VERSION 5.8 ;
BUSBITCHARS "[]" ;
DIVIDERCHAR "/" ;
UNITS
    DATABASE MICRONS 1000 ;
END UNITS

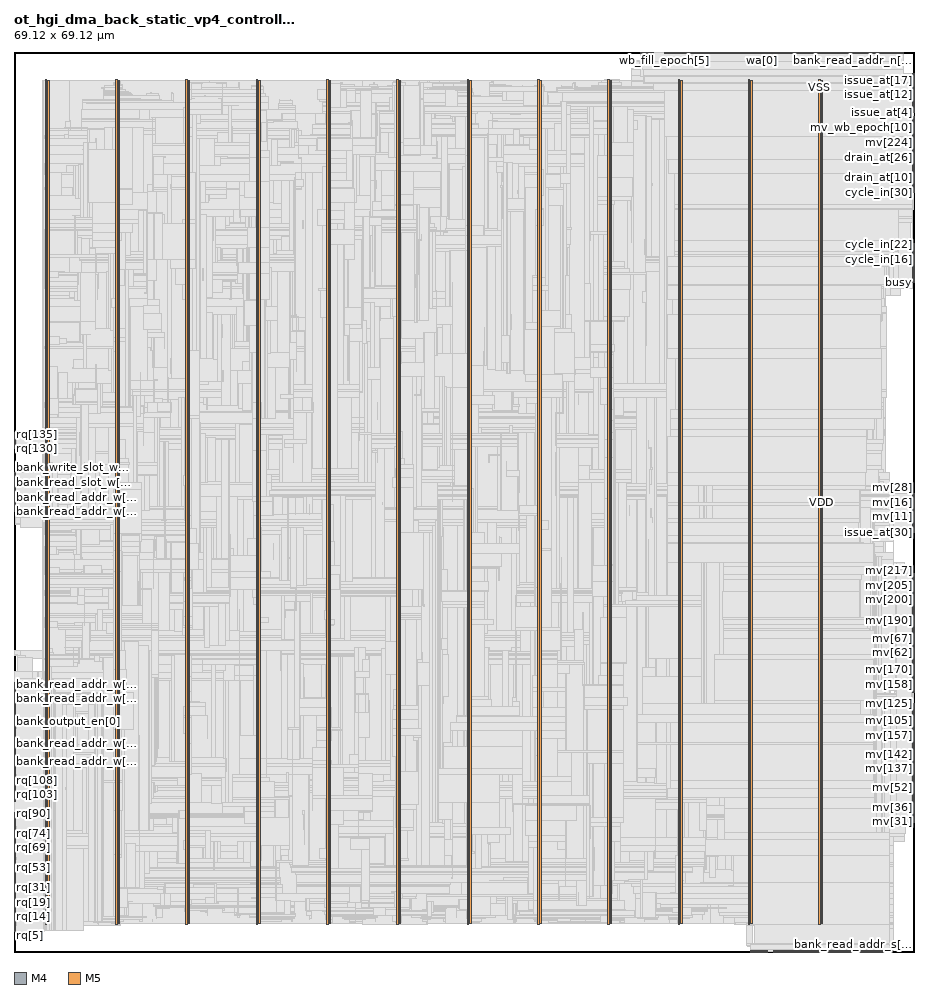
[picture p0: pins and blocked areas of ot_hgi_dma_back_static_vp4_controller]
MACRO ot_hgi_dma_back_static_vp4_controller
  FOREIGN ot_hgi_dma_back_static_vp4_controller 0 0 ;
  CLASS BLOCK ;
  SIZE 69.12 BY 69.12 ;
  PIN bank_output_en[0]
    DIRECTION OUTPUT ;
    USE SIGNAL ;
    PORT
      LAYER M4 ;
        RECT  0 17.712 0.084 17.736 ;
    END
  END bank_output_en[0]
  PIN bank_output_en[1]
    DIRECTION OUTPUT ;
    USE SIGNAL ;
    PORT
      LAYER M4 ;
        RECT  0 17.808 0.084 17.832 ;
    END
  END bank_output_en[1]
  PIN bank_output_en[2]
    DIRECTION OUTPUT ;
    USE SIGNAL ;
    PORT
      LAYER M4 ;
        RECT  0 17.904 0.084 17.928 ;
    END
  END bank_output_en[2]
  PIN bank_output_en[3]
    DIRECTION OUTPUT ;
    USE SIGNAL ;
    PORT
      LAYER M4 ;
        RECT  0 18 0.084 18.024 ;
    END
  END bank_output_en[3]
  PIN bank_output_en[4]
    DIRECTION OUTPUT ;
    USE SIGNAL ;
    PORT
      LAYER M4 ;
        RECT  0 18.096 0.084 18.12 ;
    END
  END bank_output_en[4]
  PIN bank_output_en[5]
    DIRECTION OUTPUT ;
    USE SIGNAL ;
    PORT
      LAYER M4 ;
        RECT  0 18.192 0.084 18.216 ;
    END
  END bank_output_en[5]
  PIN bank_output_en[6]
    DIRECTION OUTPUT ;
    USE SIGNAL ;
    PORT
      LAYER M4 ;
        RECT  0 18.288 0.084 18.312 ;
    END
  END bank_output_en[6]
  PIN bank_output_en[7]
    DIRECTION OUTPUT ;
    USE SIGNAL ;
    PORT
      LAYER M4 ;
        RECT  0 18.384 0.084 18.408 ;
    END
  END bank_output_en[7]
  PIN bank_read_addr_n[0]
    DIRECTION OUTPUT ;
    USE SIGNAL ;
    PORT
      LAYER M5 ;
        RECT  62.256 69.036 62.28 69.12 ;
    END
  END bank_read_addr_n[0]
  PIN bank_read_addr_n[10]
    DIRECTION OUTPUT ;
    USE SIGNAL ;
    PORT
      LAYER M5 ;
        RECT  63.216 69.036 63.24 69.12 ;
    END
  END bank_read_addr_n[10]
  PIN bank_read_addr_n[11]
    DIRECTION OUTPUT ;
    USE SIGNAL ;
    PORT
      LAYER M5 ;
        RECT  63.312 69.036 63.336 69.12 ;
    END
  END bank_read_addr_n[11]
  PIN bank_read_addr_n[12]
    DIRECTION OUTPUT ;
    USE SIGNAL ;
    PORT
      LAYER M5 ;
        RECT  63.408 69.036 63.432 69.12 ;
    END
  END bank_read_addr_n[12]
  PIN bank_read_addr_n[13]
    DIRECTION OUTPUT ;
    USE SIGNAL ;
    PORT
      LAYER M5 ;
        RECT  63.504 69.036 63.528 69.12 ;
    END
  END bank_read_addr_n[13]
  PIN bank_read_addr_n[14]
    DIRECTION OUTPUT ;
    USE SIGNAL ;
    PORT
      LAYER M5 ;
        RECT  63.6 69.036 63.624 69.12 ;
    END
  END bank_read_addr_n[14]
  PIN bank_read_addr_n[15]
    DIRECTION OUTPUT ;
    USE SIGNAL ;
    PORT
      LAYER M5 ;
        RECT  63.696 69.036 63.72 69.12 ;
    END
  END bank_read_addr_n[15]
  PIN bank_read_addr_n[16]
    DIRECTION OUTPUT ;
    USE SIGNAL ;
    PORT
      LAYER M5 ;
        RECT  63.792 69.036 63.816 69.12 ;
    END
  END bank_read_addr_n[16]
  PIN bank_read_addr_n[17]
    DIRECTION OUTPUT ;
    USE SIGNAL ;
    PORT
      LAYER M5 ;
        RECT  63.888 69.036 63.912 69.12 ;
    END
  END bank_read_addr_n[17]
  PIN bank_read_addr_n[18]
    DIRECTION OUTPUT ;
    USE SIGNAL ;
    PORT
      LAYER M5 ;
        RECT  63.984 69.036 64.008 69.12 ;
    END
  END bank_read_addr_n[18]
  PIN bank_read_addr_n[19]
    DIRECTION OUTPUT ;
    USE SIGNAL ;
    PORT
      LAYER M5 ;
        RECT  64.08 69.036 64.104 69.12 ;
    END
  END bank_read_addr_n[19]
  PIN bank_read_addr_n[1]
    DIRECTION OUTPUT ;
    USE SIGNAL ;
    PORT
      LAYER M5 ;
        RECT  62.352 69.036 62.376 69.12 ;
    END
  END bank_read_addr_n[1]
  PIN bank_read_addr_n[20]
    DIRECTION OUTPUT ;
    USE SIGNAL ;
    PORT
      LAYER M5 ;
        RECT  64.176 69.036 64.2 69.12 ;
    END
  END bank_read_addr_n[20]
  PIN bank_read_addr_n[21]
    DIRECTION OUTPUT ;
    USE SIGNAL ;
    PORT
      LAYER M5 ;
        RECT  64.272 69.036 64.296 69.12 ;
    END
  END bank_read_addr_n[21]
  PIN bank_read_addr_n[22]
    DIRECTION OUTPUT ;
    USE SIGNAL ;
    PORT
      LAYER M5 ;
        RECT  64.368 69.036 64.392 69.12 ;
    END
  END bank_read_addr_n[22]
  PIN bank_read_addr_n[23]
    DIRECTION OUTPUT ;
    USE SIGNAL ;
    PORT
      LAYER M5 ;
        RECT  64.464 69.036 64.488 69.12 ;
    END
  END bank_read_addr_n[23]
  PIN bank_read_addr_n[24]
    DIRECTION OUTPUT ;
    USE SIGNAL ;
    PORT
      LAYER M5 ;
        RECT  64.56 69.036 64.584 69.12 ;
    END
  END bank_read_addr_n[24]
  PIN bank_read_addr_n[25]
    DIRECTION OUTPUT ;
    USE SIGNAL ;
    PORT
      LAYER M5 ;
        RECT  64.656 69.036 64.68 69.12 ;
    END
  END bank_read_addr_n[25]
  PIN bank_read_addr_n[26]
    DIRECTION OUTPUT ;
    USE SIGNAL ;
    PORT
      LAYER M5 ;
        RECT  64.752 69.036 64.776 69.12 ;
    END
  END bank_read_addr_n[26]
  PIN bank_read_addr_n[27]
    DIRECTION OUTPUT ;
    USE SIGNAL ;
    PORT
      LAYER M5 ;
        RECT  64.848 69.036 64.872 69.12 ;
    END
  END bank_read_addr_n[27]
  PIN bank_read_addr_n[28]
    DIRECTION OUTPUT ;
    USE SIGNAL ;
    PORT
      LAYER M5 ;
        RECT  64.944 69.036 64.968 69.12 ;
    END
  END bank_read_addr_n[28]
  PIN bank_read_addr_n[29]
    DIRECTION OUTPUT ;
    USE SIGNAL ;
    PORT
      LAYER M5 ;
        RECT  65.04 69.036 65.064 69.12 ;
    END
  END bank_read_addr_n[29]
  PIN bank_read_addr_n[2]
    DIRECTION OUTPUT ;
    USE SIGNAL ;
    PORT
      LAYER M5 ;
        RECT  62.448 69.036 62.472 69.12 ;
    END
  END bank_read_addr_n[2]
  PIN bank_read_addr_n[30]
    DIRECTION OUTPUT ;
    USE SIGNAL ;
    PORT
      LAYER M5 ;
        RECT  65.136 69.036 65.16 69.12 ;
    END
  END bank_read_addr_n[30]
  PIN bank_read_addr_n[31]
    DIRECTION OUTPUT ;
    USE SIGNAL ;
    PORT
      LAYER M5 ;
        RECT  65.232 69.036 65.256 69.12 ;
    END
  END bank_read_addr_n[31]
  PIN bank_read_addr_n[32]
    DIRECTION OUTPUT ;
    USE SIGNAL ;
    PORT
      LAYER M5 ;
        RECT  65.328 69.036 65.352 69.12 ;
    END
  END bank_read_addr_n[32]
  PIN bank_read_addr_n[33]
    DIRECTION OUTPUT ;
    USE SIGNAL ;
    PORT
      LAYER M5 ;
        RECT  65.424 69.036 65.448 69.12 ;
    END
  END bank_read_addr_n[33]
  PIN bank_read_addr_n[34]
    DIRECTION OUTPUT ;
    USE SIGNAL ;
    PORT
      LAYER M5 ;
        RECT  65.52 69.036 65.544 69.12 ;
    END
  END bank_read_addr_n[34]
  PIN bank_read_addr_n[35]
    DIRECTION OUTPUT ;
    USE SIGNAL ;
    PORT
      LAYER M5 ;
        RECT  65.616 69.036 65.64 69.12 ;
    END
  END bank_read_addr_n[35]
  PIN bank_read_addr_n[36]
    DIRECTION OUTPUT ;
    USE SIGNAL ;
    PORT
      LAYER M5 ;
        RECT  65.712 69.036 65.736 69.12 ;
    END
  END bank_read_addr_n[36]
  PIN bank_read_addr_n[37]
    DIRECTION OUTPUT ;
    USE SIGNAL ;
    PORT
      LAYER M5 ;
        RECT  65.808 69.036 65.832 69.12 ;
    END
  END bank_read_addr_n[37]
  PIN bank_read_addr_n[38]
    DIRECTION OUTPUT ;
    USE SIGNAL ;
    PORT
      LAYER M5 ;
        RECT  65.904 69.036 65.928 69.12 ;
    END
  END bank_read_addr_n[38]
  PIN bank_read_addr_n[39]
    DIRECTION OUTPUT ;
    USE SIGNAL ;
    PORT
      LAYER M5 ;
        RECT  66 69.036 66.024 69.12 ;
    END
  END bank_read_addr_n[39]
  PIN bank_read_addr_n[3]
    DIRECTION OUTPUT ;
    USE SIGNAL ;
    PORT
      LAYER M5 ;
        RECT  62.544 69.036 62.568 69.12 ;
    END
  END bank_read_addr_n[3]
  PIN bank_read_addr_n[40]
    DIRECTION OUTPUT ;
    USE SIGNAL ;
    PORT
      LAYER M5 ;
        RECT  66.096 69.036 66.12 69.12 ;
    END
  END bank_read_addr_n[40]
  PIN bank_read_addr_n[41]
    DIRECTION OUTPUT ;
    USE SIGNAL ;
    PORT
      LAYER M5 ;
        RECT  66.192 69.036 66.216 69.12 ;
    END
  END bank_read_addr_n[41]
  PIN bank_read_addr_n[42]
    DIRECTION OUTPUT ;
    USE SIGNAL ;
    PORT
      LAYER M5 ;
        RECT  66.288 69.036 66.312 69.12 ;
    END
  END bank_read_addr_n[42]
  PIN bank_read_addr_n[43]
    DIRECTION OUTPUT ;
    USE SIGNAL ;
    PORT
      LAYER M5 ;
        RECT  66.384 69.036 66.408 69.12 ;
    END
  END bank_read_addr_n[43]
  PIN bank_read_addr_n[44]
    DIRECTION OUTPUT ;
    USE SIGNAL ;
    PORT
      LAYER M5 ;
        RECT  66.48 69.036 66.504 69.12 ;
    END
  END bank_read_addr_n[44]
  PIN bank_read_addr_n[45]
    DIRECTION OUTPUT ;
    USE SIGNAL ;
    PORT
      LAYER M5 ;
        RECT  66.576 69.036 66.6 69.12 ;
    END
  END bank_read_addr_n[45]
  PIN bank_read_addr_n[46]
    DIRECTION OUTPUT ;
    USE SIGNAL ;
    PORT
      LAYER M5 ;
        RECT  66.672 69.036 66.696 69.12 ;
    END
  END bank_read_addr_n[46]
  PIN bank_read_addr_n[47]
    DIRECTION OUTPUT ;
    USE SIGNAL ;
    PORT
      LAYER M5 ;
        RECT  66.768 69.036 66.792 69.12 ;
    END
  END bank_read_addr_n[47]
  PIN bank_read_addr_n[48]
    DIRECTION OUTPUT ;
    USE SIGNAL ;
    PORT
      LAYER M5 ;
        RECT  66.864 69.036 66.888 69.12 ;
    END
  END bank_read_addr_n[48]
  PIN bank_read_addr_n[49]
    DIRECTION OUTPUT ;
    USE SIGNAL ;
    PORT
      LAYER M5 ;
        RECT  66.96 69.036 66.984 69.12 ;
    END
  END bank_read_addr_n[49]
  PIN bank_read_addr_n[4]
    DIRECTION OUTPUT ;
    USE SIGNAL ;
    PORT
      LAYER M5 ;
        RECT  62.64 69.036 62.664 69.12 ;
    END
  END bank_read_addr_n[4]
  PIN bank_read_addr_n[50]
    DIRECTION OUTPUT ;
    USE SIGNAL ;
    PORT
      LAYER M5 ;
        RECT  67.056 69.036 67.08 69.12 ;
    END
  END bank_read_addr_n[50]
  PIN bank_read_addr_n[51]
    DIRECTION OUTPUT ;
    USE SIGNAL ;
    PORT
      LAYER M5 ;
        RECT  67.152 69.036 67.176 69.12 ;
    END
  END bank_read_addr_n[51]
  PIN bank_read_addr_n[52]
    DIRECTION OUTPUT ;
    USE SIGNAL ;
    PORT
      LAYER M5 ;
        RECT  67.248 69.036 67.272 69.12 ;
    END
  END bank_read_addr_n[52]
  PIN bank_read_addr_n[53]
    DIRECTION OUTPUT ;
    USE SIGNAL ;
    PORT
      LAYER M5 ;
        RECT  67.344 69.036 67.368 69.12 ;
    END
  END bank_read_addr_n[53]
  PIN bank_read_addr_n[54]
    DIRECTION OUTPUT ;
    USE SIGNAL ;
    PORT
      LAYER M5 ;
        RECT  67.44 69.036 67.464 69.12 ;
    END
  END bank_read_addr_n[54]
  PIN bank_read_addr_n[55]
    DIRECTION OUTPUT ;
    USE SIGNAL ;
    PORT
      LAYER M5 ;
        RECT  67.536 69.036 67.56 69.12 ;
    END
  END bank_read_addr_n[55]
  PIN bank_read_addr_n[56]
    DIRECTION OUTPUT ;
    USE SIGNAL ;
    PORT
      LAYER M5 ;
        RECT  67.632 69.036 67.656 69.12 ;
    END
  END bank_read_addr_n[56]
  PIN bank_read_addr_n[57]
    DIRECTION OUTPUT ;
    USE SIGNAL ;
    PORT
      LAYER M5 ;
        RECT  67.728 69.036 67.752 69.12 ;
    END
  END bank_read_addr_n[57]
  PIN bank_read_addr_n[58]
    DIRECTION OUTPUT ;
    USE SIGNAL ;
    PORT
      LAYER M5 ;
        RECT  67.824 69.036 67.848 69.12 ;
    END
  END bank_read_addr_n[58]
  PIN bank_read_addr_n[59]
    DIRECTION OUTPUT ;
    USE SIGNAL ;
    PORT
      LAYER M5 ;
        RECT  67.92 69.036 67.944 69.12 ;
    END
  END bank_read_addr_n[59]
  PIN bank_read_addr_n[5]
    DIRECTION OUTPUT ;
    USE SIGNAL ;
    PORT
      LAYER M5 ;
        RECT  62.736 69.036 62.76 69.12 ;
    END
  END bank_read_addr_n[5]
  PIN bank_read_addr_n[60]
    DIRECTION OUTPUT ;
    USE SIGNAL ;
    PORT
      LAYER M5 ;
        RECT  68.016 69.036 68.04 69.12 ;
    END
  END bank_read_addr_n[60]
  PIN bank_read_addr_n[61]
    DIRECTION OUTPUT ;
    USE SIGNAL ;
    PORT
      LAYER M5 ;
        RECT  68.112 69.036 68.136 69.12 ;
    END
  END bank_read_addr_n[61]
  PIN bank_read_addr_n[62]
    DIRECTION OUTPUT ;
    USE SIGNAL ;
    PORT
      LAYER M5 ;
        RECT  68.208 69.036 68.232 69.12 ;
    END
  END bank_read_addr_n[62]
  PIN bank_read_addr_n[63]
    DIRECTION OUTPUT ;
    USE SIGNAL ;
    PORT
      LAYER M5 ;
        RECT  68.304 69.036 68.328 69.12 ;
    END
  END bank_read_addr_n[63]
  PIN bank_read_addr_n[64]
    DIRECTION OUTPUT ;
    USE SIGNAL ;
    PORT
      LAYER M5 ;
        RECT  59.184 69.036 59.208 69.12 ;
    END
  END bank_read_addr_n[64]
  PIN bank_read_addr_n[65]
    DIRECTION OUTPUT ;
    USE SIGNAL ;
    PORT
      LAYER M5 ;
        RECT  59.28 69.036 59.304 69.12 ;
    END
  END bank_read_addr_n[65]
  PIN bank_read_addr_n[66]
    DIRECTION OUTPUT ;
    USE SIGNAL ;
    PORT
      LAYER M5 ;
        RECT  59.376 69.036 59.4 69.12 ;
    END
  END bank_read_addr_n[66]
  PIN bank_read_addr_n[67]
    DIRECTION OUTPUT ;
    USE SIGNAL ;
    PORT
      LAYER M5 ;
        RECT  59.472 69.036 59.496 69.12 ;
    END
  END bank_read_addr_n[67]
  PIN bank_read_addr_n[68]
    DIRECTION OUTPUT ;
    USE SIGNAL ;
    PORT
      LAYER M5 ;
        RECT  59.568 69.036 59.592 69.12 ;
    END
  END bank_read_addr_n[68]
  PIN bank_read_addr_n[69]
    DIRECTION OUTPUT ;
    USE SIGNAL ;
    PORT
      LAYER M5 ;
        RECT  59.664 69.036 59.688 69.12 ;
    END
  END bank_read_addr_n[69]
  PIN bank_read_addr_n[6]
    DIRECTION OUTPUT ;
    USE SIGNAL ;
    PORT
      LAYER M5 ;
        RECT  62.832 69.036 62.856 69.12 ;
    END
  END bank_read_addr_n[6]
  PIN bank_read_addr_n[70]
    DIRECTION OUTPUT ;
    USE SIGNAL ;
    PORT
      LAYER M5 ;
        RECT  59.76 69.036 59.784 69.12 ;
    END
  END bank_read_addr_n[70]
  PIN bank_read_addr_n[71]
    DIRECTION OUTPUT ;
    USE SIGNAL ;
    PORT
      LAYER M5 ;
        RECT  59.856 69.036 59.88 69.12 ;
    END
  END bank_read_addr_n[71]
  PIN bank_read_addr_n[72]
    DIRECTION OUTPUT ;
    USE SIGNAL ;
    PORT
      LAYER M5 ;
        RECT  59.952 69.036 59.976 69.12 ;
    END
  END bank_read_addr_n[72]
  PIN bank_read_addr_n[73]
    DIRECTION OUTPUT ;
    USE SIGNAL ;
    PORT
      LAYER M5 ;
        RECT  60.048 69.036 60.072 69.12 ;
    END
  END bank_read_addr_n[73]
  PIN bank_read_addr_n[74]
    DIRECTION OUTPUT ;
    USE SIGNAL ;
    PORT
      LAYER M5 ;
        RECT  60.144 69.036 60.168 69.12 ;
    END
  END bank_read_addr_n[74]
  PIN bank_read_addr_n[75]
    DIRECTION OUTPUT ;
    USE SIGNAL ;
    PORT
      LAYER M5 ;
        RECT  60.24 69.036 60.264 69.12 ;
    END
  END bank_read_addr_n[75]
  PIN bank_read_addr_n[76]
    DIRECTION OUTPUT ;
    USE SIGNAL ;
    PORT
      LAYER M5 ;
        RECT  60.336 69.036 60.36 69.12 ;
    END
  END bank_read_addr_n[76]
  PIN bank_read_addr_n[77]
    DIRECTION OUTPUT ;
    USE SIGNAL ;
    PORT
      LAYER M5 ;
        RECT  60.432 69.036 60.456 69.12 ;
    END
  END bank_read_addr_n[77]
  PIN bank_read_addr_n[78]
    DIRECTION OUTPUT ;
    USE SIGNAL ;
    PORT
      LAYER M5 ;
        RECT  60.528 69.036 60.552 69.12 ;
    END
  END bank_read_addr_n[78]
  PIN bank_read_addr_n[79]
    DIRECTION OUTPUT ;
    USE SIGNAL ;
    PORT
      LAYER M5 ;
        RECT  60.624 69.036 60.648 69.12 ;
    END
  END bank_read_addr_n[79]
  PIN bank_read_addr_n[7]
    DIRECTION OUTPUT ;
    USE SIGNAL ;
    PORT
      LAYER M5 ;
        RECT  62.928 69.036 62.952 69.12 ;
    END
  END bank_read_addr_n[7]
  PIN bank_read_addr_n[80]
    DIRECTION OUTPUT ;
    USE SIGNAL ;
    PORT
      LAYER M5 ;
        RECT  60.72 69.036 60.744 69.12 ;
    END
  END bank_read_addr_n[80]
  PIN bank_read_addr_n[81]
    DIRECTION OUTPUT ;
    USE SIGNAL ;
    PORT
      LAYER M5 ;
        RECT  60.816 69.036 60.84 69.12 ;
    END
  END bank_read_addr_n[81]
  PIN bank_read_addr_n[82]
    DIRECTION OUTPUT ;
    USE SIGNAL ;
    PORT
      LAYER M5 ;
        RECT  60.912 69.036 60.936 69.12 ;
    END
  END bank_read_addr_n[82]
  PIN bank_read_addr_n[83]
    DIRECTION OUTPUT ;
    USE SIGNAL ;
    PORT
      LAYER M5 ;
        RECT  61.008 69.036 61.032 69.12 ;
    END
  END bank_read_addr_n[83]
  PIN bank_read_addr_n[84]
    DIRECTION OUTPUT ;
    USE SIGNAL ;
    PORT
      LAYER M5 ;
        RECT  61.104 69.036 61.128 69.12 ;
    END
  END bank_read_addr_n[84]
  PIN bank_read_addr_n[85]
    DIRECTION OUTPUT ;
    USE SIGNAL ;
    PORT
      LAYER M5 ;
        RECT  61.2 69.036 61.224 69.12 ;
    END
  END bank_read_addr_n[85]
  PIN bank_read_addr_n[86]
    DIRECTION OUTPUT ;
    USE SIGNAL ;
    PORT
      LAYER M5 ;
        RECT  61.296 69.036 61.32 69.12 ;
    END
  END bank_read_addr_n[86]
  PIN bank_read_addr_n[87]
    DIRECTION OUTPUT ;
    USE SIGNAL ;
    PORT
      LAYER M5 ;
        RECT  61.392 69.036 61.416 69.12 ;
    END
  END bank_read_addr_n[87]
  PIN bank_read_addr_n[88]
    DIRECTION OUTPUT ;
    USE SIGNAL ;
    PORT
      LAYER M5 ;
        RECT  61.488 69.036 61.512 69.12 ;
    END
  END bank_read_addr_n[88]
  PIN bank_read_addr_n[89]
    DIRECTION OUTPUT ;
    USE SIGNAL ;
    PORT
      LAYER M5 ;
        RECT  61.584 69.036 61.608 69.12 ;
    END
  END bank_read_addr_n[89]
  PIN bank_read_addr_n[8]
    DIRECTION OUTPUT ;
    USE SIGNAL ;
    PORT
      LAYER M5 ;
        RECT  63.024 69.036 63.048 69.12 ;
    END
  END bank_read_addr_n[8]
  PIN bank_read_addr_n[90]
    DIRECTION OUTPUT ;
    USE SIGNAL ;
    PORT
      LAYER M5 ;
        RECT  61.68 69.036 61.704 69.12 ;
    END
  END bank_read_addr_n[90]
  PIN bank_read_addr_n[91]
    DIRECTION OUTPUT ;
    USE SIGNAL ;
    PORT
      LAYER M5 ;
        RECT  61.776 69.036 61.8 69.12 ;
    END
  END bank_read_addr_n[91]
  PIN bank_read_addr_n[92]
    DIRECTION OUTPUT ;
    USE SIGNAL ;
    PORT
      LAYER M5 ;
        RECT  61.872 69.036 61.896 69.12 ;
    END
  END bank_read_addr_n[92]
  PIN bank_read_addr_n[93]
    DIRECTION OUTPUT ;
    USE SIGNAL ;
    PORT
      LAYER M5 ;
        RECT  61.968 69.036 61.992 69.12 ;
    END
  END bank_read_addr_n[93]
  PIN bank_read_addr_n[94]
    DIRECTION OUTPUT ;
    USE SIGNAL ;
    PORT
      LAYER M5 ;
        RECT  62.064 69.036 62.088 69.12 ;
    END
  END bank_read_addr_n[94]
  PIN bank_read_addr_n[95]
    DIRECTION OUTPUT ;
    USE SIGNAL ;
    PORT
      LAYER M5 ;
        RECT  62.16 69.036 62.184 69.12 ;
    END
  END bank_read_addr_n[95]
  PIN bank_read_addr_n[9]
    DIRECTION OUTPUT ;
    USE SIGNAL ;
    PORT
      LAYER M5 ;
        RECT  63.12 69.036 63.144 69.12 ;
    END
  END bank_read_addr_n[9]
  PIN bank_read_addr_s[0]
    DIRECTION OUTPUT ;
    USE SIGNAL ;
    PORT
      LAYER M5 ;
        RECT  58.32 0 58.344 0.084 ;
    END
  END bank_read_addr_s[0]
  PIN bank_read_addr_s[10]
    DIRECTION OUTPUT ;
    USE SIGNAL ;
    PORT
      LAYER M5 ;
        RECT  59.28 0 59.304 0.084 ;
    END
  END bank_read_addr_s[10]
  PIN bank_read_addr_s[11]
    DIRECTION OUTPUT ;
    USE SIGNAL ;
    PORT
      LAYER M5 ;
        RECT  59.376 0 59.4 0.084 ;
    END
  END bank_read_addr_s[11]
  PIN bank_read_addr_s[12]
    DIRECTION OUTPUT ;
    USE SIGNAL ;
    PORT
      LAYER M5 ;
        RECT  59.472 0 59.496 0.084 ;
    END
  END bank_read_addr_s[12]
  PIN bank_read_addr_s[13]
    DIRECTION OUTPUT ;
    USE SIGNAL ;
    PORT
      LAYER M5 ;
        RECT  59.568 0 59.592 0.084 ;
    END
  END bank_read_addr_s[13]
  PIN bank_read_addr_s[14]
    DIRECTION OUTPUT ;
    USE SIGNAL ;
    PORT
      LAYER M5 ;
        RECT  59.664 0 59.688 0.084 ;
    END
  END bank_read_addr_s[14]
  PIN bank_read_addr_s[15]
    DIRECTION OUTPUT ;
    USE SIGNAL ;
    PORT
      LAYER M5 ;
        RECT  59.76 0 59.784 0.084 ;
    END
  END bank_read_addr_s[15]
  PIN bank_read_addr_s[16]
    DIRECTION OUTPUT ;
    USE SIGNAL ;
    PORT
      LAYER M5 ;
        RECT  59.856 0 59.88 0.084 ;
    END
  END bank_read_addr_s[16]
  PIN bank_read_addr_s[17]
    DIRECTION OUTPUT ;
    USE SIGNAL ;
    PORT
      LAYER M5 ;
        RECT  59.952 0 59.976 0.084 ;
    END
  END bank_read_addr_s[17]
  PIN bank_read_addr_s[18]
    DIRECTION OUTPUT ;
    USE SIGNAL ;
    PORT
      LAYER M5 ;
        RECT  60.048 0 60.072 0.084 ;
    END
  END bank_read_addr_s[18]
  PIN bank_read_addr_s[19]
    DIRECTION OUTPUT ;
    USE SIGNAL ;
    PORT
      LAYER M5 ;
        RECT  60.144 0 60.168 0.084 ;
    END
  END bank_read_addr_s[19]
  PIN bank_read_addr_s[1]
    DIRECTION OUTPUT ;
    USE SIGNAL ;
    PORT
      LAYER M5 ;
        RECT  58.416 0 58.44 0.084 ;
    END
  END bank_read_addr_s[1]
  PIN bank_read_addr_s[20]
    DIRECTION OUTPUT ;
    USE SIGNAL ;
    PORT
      LAYER M5 ;
        RECT  60.24 0 60.264 0.084 ;
    END
  END bank_read_addr_s[20]
  PIN bank_read_addr_s[21]
    DIRECTION OUTPUT ;
    USE SIGNAL ;
    PORT
      LAYER M5 ;
        RECT  60.336 0 60.36 0.084 ;
    END
  END bank_read_addr_s[21]
  PIN bank_read_addr_s[22]
    DIRECTION OUTPUT ;
    USE SIGNAL ;
    PORT
      LAYER M5 ;
        RECT  60.432 0 60.456 0.084 ;
    END
  END bank_read_addr_s[22]
  PIN bank_read_addr_s[23]
    DIRECTION OUTPUT ;
    USE SIGNAL ;
    PORT
      LAYER M5 ;
        RECT  60.528 0 60.552 0.084 ;
    END
  END bank_read_addr_s[23]
  PIN bank_read_addr_s[24]
    DIRECTION OUTPUT ;
    USE SIGNAL ;
    PORT
      LAYER M5 ;
        RECT  60.624 0 60.648 0.084 ;
    END
  END bank_read_addr_s[24]
  PIN bank_read_addr_s[25]
    DIRECTION OUTPUT ;
    USE SIGNAL ;
    PORT
      LAYER M5 ;
        RECT  60.72 0 60.744 0.084 ;
    END
  END bank_read_addr_s[25]
  PIN bank_read_addr_s[26]
    DIRECTION OUTPUT ;
    USE SIGNAL ;
    PORT
      LAYER M5 ;
        RECT  60.816 0 60.84 0.084 ;
    END
  END bank_read_addr_s[26]
  PIN bank_read_addr_s[27]
    DIRECTION OUTPUT ;
    USE SIGNAL ;
    PORT
      LAYER M5 ;
        RECT  60.912 0 60.936 0.084 ;
    END
  END bank_read_addr_s[27]
  PIN bank_read_addr_s[28]
    DIRECTION OUTPUT ;
    USE SIGNAL ;
    PORT
      LAYER M5 ;
        RECT  61.008 0 61.032 0.084 ;
    END
  END bank_read_addr_s[28]
  PIN bank_read_addr_s[29]
    DIRECTION OUTPUT ;
    USE SIGNAL ;
    PORT
      LAYER M5 ;
        RECT  61.104 0 61.128 0.084 ;
    END
  END bank_read_addr_s[29]
  PIN bank_read_addr_s[2]
    DIRECTION OUTPUT ;
    USE SIGNAL ;
    PORT
      LAYER M5 ;
        RECT  58.512 0 58.536 0.084 ;
    END
  END bank_read_addr_s[2]
  PIN bank_read_addr_s[30]
    DIRECTION OUTPUT ;
    USE SIGNAL ;
    PORT
      LAYER M5 ;
        RECT  61.2 0 61.224 0.084 ;
    END
  END bank_read_addr_s[30]
  PIN bank_read_addr_s[31]
    DIRECTION OUTPUT ;
    USE SIGNAL ;
    PORT
      LAYER M5 ;
        RECT  61.296 0 61.32 0.084 ;
    END
  END bank_read_addr_s[31]
  PIN bank_read_addr_s[32]
    DIRECTION OUTPUT ;
    USE SIGNAL ;
    PORT
      LAYER M5 ;
        RECT  61.392 0 61.416 0.084 ;
    END
  END bank_read_addr_s[32]
  PIN bank_read_addr_s[33]
    DIRECTION OUTPUT ;
    USE SIGNAL ;
    PORT
      LAYER M5 ;
        RECT  61.488 0 61.512 0.084 ;
    END
  END bank_read_addr_s[33]
  PIN bank_read_addr_s[34]
    DIRECTION OUTPUT ;
    USE SIGNAL ;
    PORT
      LAYER M5 ;
        RECT  61.584 0 61.608 0.084 ;
    END
  END bank_read_addr_s[34]
  PIN bank_read_addr_s[35]
    DIRECTION OUTPUT ;
    USE SIGNAL ;
    PORT
      LAYER M5 ;
        RECT  61.68 0 61.704 0.084 ;
    END
  END bank_read_addr_s[35]
  PIN bank_read_addr_s[36]
    DIRECTION OUTPUT ;
    USE SIGNAL ;
    PORT
      LAYER M5 ;
        RECT  61.776 0 61.8 0.084 ;
    END
  END bank_read_addr_s[36]
  PIN bank_read_addr_s[37]
    DIRECTION OUTPUT ;
    USE SIGNAL ;
    PORT
      LAYER M5 ;
        RECT  61.872 0 61.896 0.084 ;
    END
  END bank_read_addr_s[37]
  PIN bank_read_addr_s[38]
    DIRECTION OUTPUT ;
    USE SIGNAL ;
    PORT
      LAYER M5 ;
        RECT  61.968 0 61.992 0.084 ;
    END
  END bank_read_addr_s[38]
  PIN bank_read_addr_s[39]
    DIRECTION OUTPUT ;
    USE SIGNAL ;
    PORT
      LAYER M5 ;
        RECT  62.064 0 62.088 0.084 ;
    END
  END bank_read_addr_s[39]
  PIN bank_read_addr_s[3]
    DIRECTION OUTPUT ;
    USE SIGNAL ;
    PORT
      LAYER M5 ;
        RECT  58.608 0 58.632 0.084 ;
    END
  END bank_read_addr_s[3]
  PIN bank_read_addr_s[40]
    DIRECTION OUTPUT ;
    USE SIGNAL ;
    PORT
      LAYER M5 ;
        RECT  62.16 0 62.184 0.084 ;
    END
  END bank_read_addr_s[40]
  PIN bank_read_addr_s[41]
    DIRECTION OUTPUT ;
    USE SIGNAL ;
    PORT
      LAYER M5 ;
        RECT  62.256 0 62.28 0.084 ;
    END
  END bank_read_addr_s[41]
  PIN bank_read_addr_s[42]
    DIRECTION OUTPUT ;
    USE SIGNAL ;
    PORT
      LAYER M5 ;
        RECT  62.352 0 62.376 0.084 ;
    END
  END bank_read_addr_s[42]
  PIN bank_read_addr_s[43]
    DIRECTION OUTPUT ;
    USE SIGNAL ;
    PORT
      LAYER M5 ;
        RECT  62.448 0 62.472 0.084 ;
    END
  END bank_read_addr_s[43]
  PIN bank_read_addr_s[44]
    DIRECTION OUTPUT ;
    USE SIGNAL ;
    PORT
      LAYER M5 ;
        RECT  62.544 0 62.568 0.084 ;
    END
  END bank_read_addr_s[44]
  PIN bank_read_addr_s[45]
    DIRECTION OUTPUT ;
    USE SIGNAL ;
    PORT
      LAYER M5 ;
        RECT  62.64 0 62.664 0.084 ;
    END
  END bank_read_addr_s[45]
  PIN bank_read_addr_s[46]
    DIRECTION OUTPUT ;
    USE SIGNAL ;
    PORT
      LAYER M5 ;
        RECT  62.736 0 62.76 0.084 ;
    END
  END bank_read_addr_s[46]
  PIN bank_read_addr_s[47]
    DIRECTION OUTPUT ;
    USE SIGNAL ;
    PORT
      LAYER M5 ;
        RECT  62.832 0 62.856 0.084 ;
    END
  END bank_read_addr_s[47]
  PIN bank_read_addr_s[48]
    DIRECTION OUTPUT ;
    USE SIGNAL ;
    PORT
      LAYER M5 ;
        RECT  62.928 0 62.952 0.084 ;
    END
  END bank_read_addr_s[48]
  PIN bank_read_addr_s[49]
    DIRECTION OUTPUT ;
    USE SIGNAL ;
    PORT
      LAYER M5 ;
        RECT  63.024 0 63.048 0.084 ;
    END
  END bank_read_addr_s[49]
  PIN bank_read_addr_s[4]
    DIRECTION OUTPUT ;
    USE SIGNAL ;
    PORT
      LAYER M5 ;
        RECT  58.704 0 58.728 0.084 ;
    END
  END bank_read_addr_s[4]
  PIN bank_read_addr_s[50]
    DIRECTION OUTPUT ;
    USE SIGNAL ;
    PORT
      LAYER M5 ;
        RECT  63.12 0 63.144 0.084 ;
    END
  END bank_read_addr_s[50]
  PIN bank_read_addr_s[51]
    DIRECTION OUTPUT ;
    USE SIGNAL ;
    PORT
      LAYER M5 ;
        RECT  63.216 0 63.24 0.084 ;
    END
  END bank_read_addr_s[51]
  PIN bank_read_addr_s[52]
    DIRECTION OUTPUT ;
    USE SIGNAL ;
    PORT
      LAYER M5 ;
        RECT  63.312 0 63.336 0.084 ;
    END
  END bank_read_addr_s[52]
  PIN bank_read_addr_s[53]
    DIRECTION OUTPUT ;
    USE SIGNAL ;
    PORT
      LAYER M5 ;
        RECT  63.408 0 63.432 0.084 ;
    END
  END bank_read_addr_s[53]
  PIN bank_read_addr_s[54]
    DIRECTION OUTPUT ;
    USE SIGNAL ;
    PORT
      LAYER M5 ;
        RECT  63.504 0 63.528 0.084 ;
    END
  END bank_read_addr_s[54]
  PIN bank_read_addr_s[55]
    DIRECTION OUTPUT ;
    USE SIGNAL ;
    PORT
      LAYER M5 ;
        RECT  63.6 0 63.624 0.084 ;
    END
  END bank_read_addr_s[55]
  PIN bank_read_addr_s[56]
    DIRECTION OUTPUT ;
    USE SIGNAL ;
    PORT
      LAYER M5 ;
        RECT  63.696 0 63.72 0.084 ;
    END
  END bank_read_addr_s[56]
  PIN bank_read_addr_s[57]
    DIRECTION OUTPUT ;
    USE SIGNAL ;
    PORT
      LAYER M5 ;
        RECT  63.792 0 63.816 0.084 ;
    END
  END bank_read_addr_s[57]
  PIN bank_read_addr_s[58]
    DIRECTION OUTPUT ;
    USE SIGNAL ;
    PORT
      LAYER M5 ;
        RECT  63.888 0 63.912 0.084 ;
    END
  END bank_read_addr_s[58]
  PIN bank_read_addr_s[59]
    DIRECTION OUTPUT ;
    USE SIGNAL ;
    PORT
      LAYER M5 ;
        RECT  63.984 0 64.008 0.084 ;
    END
  END bank_read_addr_s[59]
  PIN bank_read_addr_s[5]
    DIRECTION OUTPUT ;
    USE SIGNAL ;
    PORT
      LAYER M5 ;
        RECT  58.8 0 58.824 0.084 ;
    END
  END bank_read_addr_s[5]
  PIN bank_read_addr_s[60]
    DIRECTION OUTPUT ;
    USE SIGNAL ;
    PORT
      LAYER M5 ;
        RECT  64.08 0 64.104 0.084 ;
    END
  END bank_read_addr_s[60]
  PIN bank_read_addr_s[61]
    DIRECTION OUTPUT ;
    USE SIGNAL ;
    PORT
      LAYER M5 ;
        RECT  64.176 0 64.2 0.084 ;
    END
  END bank_read_addr_s[61]
  PIN bank_read_addr_s[62]
    DIRECTION OUTPUT ;
    USE SIGNAL ;
    PORT
      LAYER M5 ;
        RECT  64.272 0 64.296 0.084 ;
    END
  END bank_read_addr_s[62]
  PIN bank_read_addr_s[63]
    DIRECTION OUTPUT ;
    USE SIGNAL ;
    PORT
      LAYER M5 ;
        RECT  64.368 0 64.392 0.084 ;
    END
  END bank_read_addr_s[63]
  PIN bank_read_addr_s[64]
    DIRECTION OUTPUT ;
    USE SIGNAL ;
    PORT
      LAYER M5 ;
        RECT  64.464 0 64.488 0.084 ;
    END
  END bank_read_addr_s[64]
  PIN bank_read_addr_s[65]
    DIRECTION OUTPUT ;
    USE SIGNAL ;
    PORT
      LAYER M5 ;
        RECT  64.56 0 64.584 0.084 ;
    END
  END bank_read_addr_s[65]
  PIN bank_read_addr_s[66]
    DIRECTION OUTPUT ;
    USE SIGNAL ;
    PORT
      LAYER M5 ;
        RECT  64.656 0 64.68 0.084 ;
    END
  END bank_read_addr_s[66]
  PIN bank_read_addr_s[67]
    DIRECTION OUTPUT ;
    USE SIGNAL ;
    PORT
      LAYER M5 ;
        RECT  64.752 0 64.776 0.084 ;
    END
  END bank_read_addr_s[67]
  PIN bank_read_addr_s[68]
    DIRECTION OUTPUT ;
    USE SIGNAL ;
    PORT
      LAYER M5 ;
        RECT  64.848 0 64.872 0.084 ;
    END
  END bank_read_addr_s[68]
  PIN bank_read_addr_s[69]
    DIRECTION OUTPUT ;
    USE SIGNAL ;
    PORT
      LAYER M5 ;
        RECT  64.944 0 64.968 0.084 ;
    END
  END bank_read_addr_s[69]
  PIN bank_read_addr_s[6]
    DIRECTION OUTPUT ;
    USE SIGNAL ;
    PORT
      LAYER M5 ;
        RECT  58.896 0 58.92 0.084 ;
    END
  END bank_read_addr_s[6]
  PIN bank_read_addr_s[70]
    DIRECTION OUTPUT ;
    USE SIGNAL ;
    PORT
      LAYER M5 ;
        RECT  65.04 0 65.064 0.084 ;
    END
  END bank_read_addr_s[70]
  PIN bank_read_addr_s[71]
    DIRECTION OUTPUT ;
    USE SIGNAL ;
    PORT
      LAYER M5 ;
        RECT  65.136 0 65.16 0.084 ;
    END
  END bank_read_addr_s[71]
  PIN bank_read_addr_s[72]
    DIRECTION OUTPUT ;
    USE SIGNAL ;
    PORT
      LAYER M5 ;
        RECT  65.232 0 65.256 0.084 ;
    END
  END bank_read_addr_s[72]
  PIN bank_read_addr_s[73]
    DIRECTION OUTPUT ;
    USE SIGNAL ;
    PORT
      LAYER M5 ;
        RECT  65.328 0 65.352 0.084 ;
    END
  END bank_read_addr_s[73]
  PIN bank_read_addr_s[74]
    DIRECTION OUTPUT ;
    USE SIGNAL ;
    PORT
      LAYER M5 ;
        RECT  65.424 0 65.448 0.084 ;
    END
  END bank_read_addr_s[74]
  PIN bank_read_addr_s[75]
    DIRECTION OUTPUT ;
    USE SIGNAL ;
    PORT
      LAYER M5 ;
        RECT  65.52 0 65.544 0.084 ;
    END
  END bank_read_addr_s[75]
  PIN bank_read_addr_s[76]
    DIRECTION OUTPUT ;
    USE SIGNAL ;
    PORT
      LAYER M5 ;
        RECT  65.616 0 65.64 0.084 ;
    END
  END bank_read_addr_s[76]
  PIN bank_read_addr_s[77]
    DIRECTION OUTPUT ;
    USE SIGNAL ;
    PORT
      LAYER M5 ;
        RECT  65.712 0 65.736 0.084 ;
    END
  END bank_read_addr_s[77]
  PIN bank_read_addr_s[78]
    DIRECTION OUTPUT ;
    USE SIGNAL ;
    PORT
      LAYER M5 ;
        RECT  65.808 0 65.832 0.084 ;
    END
  END bank_read_addr_s[78]
  PIN bank_read_addr_s[79]
    DIRECTION OUTPUT ;
    USE SIGNAL ;
    PORT
      LAYER M5 ;
        RECT  65.904 0 65.928 0.084 ;
    END
  END bank_read_addr_s[79]
  PIN bank_read_addr_s[7]
    DIRECTION OUTPUT ;
    USE SIGNAL ;
    PORT
      LAYER M5 ;
        RECT  58.992 0 59.016 0.084 ;
    END
  END bank_read_addr_s[7]
  PIN bank_read_addr_s[80]
    DIRECTION OUTPUT ;
    USE SIGNAL ;
    PORT
      LAYER M5 ;
        RECT  66 0 66.024 0.084 ;
    END
  END bank_read_addr_s[80]
  PIN bank_read_addr_s[81]
    DIRECTION OUTPUT ;
    USE SIGNAL ;
    PORT
      LAYER M5 ;
        RECT  66.096 0 66.12 0.084 ;
    END
  END bank_read_addr_s[81]
  PIN bank_read_addr_s[82]
    DIRECTION OUTPUT ;
    USE SIGNAL ;
    PORT
      LAYER M5 ;
        RECT  66.192 0 66.216 0.084 ;
    END
  END bank_read_addr_s[82]
  PIN bank_read_addr_s[83]
    DIRECTION OUTPUT ;
    USE SIGNAL ;
    PORT
      LAYER M5 ;
        RECT  66.288 0 66.312 0.084 ;
    END
  END bank_read_addr_s[83]
  PIN bank_read_addr_s[84]
    DIRECTION OUTPUT ;
    USE SIGNAL ;
    PORT
      LAYER M5 ;
        RECT  66.384 0 66.408 0.084 ;
    END
  END bank_read_addr_s[84]
  PIN bank_read_addr_s[85]
    DIRECTION OUTPUT ;
    USE SIGNAL ;
    PORT
      LAYER M5 ;
        RECT  66.48 0 66.504 0.084 ;
    END
  END bank_read_addr_s[85]
  PIN bank_read_addr_s[86]
    DIRECTION OUTPUT ;
    USE SIGNAL ;
    PORT
      LAYER M5 ;
        RECT  66.576 0 66.6 0.084 ;
    END
  END bank_read_addr_s[86]
  PIN bank_read_addr_s[87]
    DIRECTION OUTPUT ;
    USE SIGNAL ;
    PORT
      LAYER M5 ;
        RECT  66.672 0 66.696 0.084 ;
    END
  END bank_read_addr_s[87]
  PIN bank_read_addr_s[88]
    DIRECTION OUTPUT ;
    USE SIGNAL ;
    PORT
      LAYER M5 ;
        RECT  66.768 0 66.792 0.084 ;
    END
  END bank_read_addr_s[88]
  PIN bank_read_addr_s[89]
    DIRECTION OUTPUT ;
    USE SIGNAL ;
    PORT
      LAYER M5 ;
        RECT  66.864 0 66.888 0.084 ;
    END
  END bank_read_addr_s[89]
  PIN bank_read_addr_s[8]
    DIRECTION OUTPUT ;
    USE SIGNAL ;
    PORT
      LAYER M5 ;
        RECT  59.088 0 59.112 0.084 ;
    END
  END bank_read_addr_s[8]
  PIN bank_read_addr_s[90]
    DIRECTION OUTPUT ;
    USE SIGNAL ;
    PORT
      LAYER M5 ;
        RECT  66.96 0 66.984 0.084 ;
    END
  END bank_read_addr_s[90]
  PIN bank_read_addr_s[91]
    DIRECTION OUTPUT ;
    USE SIGNAL ;
    PORT
      LAYER M5 ;
        RECT  67.056 0 67.08 0.084 ;
    END
  END bank_read_addr_s[91]
  PIN bank_read_addr_s[92]
    DIRECTION OUTPUT ;
    USE SIGNAL ;
    PORT
      LAYER M5 ;
        RECT  67.152 0 67.176 0.084 ;
    END
  END bank_read_addr_s[92]
  PIN bank_read_addr_s[93]
    DIRECTION OUTPUT ;
    USE SIGNAL ;
    PORT
      LAYER M5 ;
        RECT  67.248 0 67.272 0.084 ;
    END
  END bank_read_addr_s[93]
  PIN bank_read_addr_s[94]
    DIRECTION OUTPUT ;
    USE SIGNAL ;
    PORT
      LAYER M5 ;
        RECT  67.344 0 67.368 0.084 ;
    END
  END bank_read_addr_s[94]
  PIN bank_read_addr_s[95]
    DIRECTION OUTPUT ;
    USE SIGNAL ;
    PORT
      LAYER M5 ;
        RECT  67.44 0 67.464 0.084 ;
    END
  END bank_read_addr_s[95]
  PIN bank_read_addr_s[9]
    DIRECTION OUTPUT ;
    USE SIGNAL ;
    PORT
      LAYER M5 ;
        RECT  59.184 0 59.208 0.084 ;
    END
  END bank_read_addr_s[9]
  PIN bank_read_addr_w[0]
    DIRECTION OUTPUT ;
    USE SIGNAL ;
    PORT
      LAYER M4 ;
        RECT  0 18.48 0.084 18.504 ;
    END
  END bank_read_addr_w[0]
  PIN bank_read_addr_w[10]
    DIRECTION OUTPUT ;
    USE SIGNAL ;
    PORT
      LAYER M4 ;
        RECT  0 19.44 0.084 19.464 ;
    END
  END bank_read_addr_w[10]
  PIN bank_read_addr_w[11]
    DIRECTION OUTPUT ;
    USE SIGNAL ;
    PORT
      LAYER M4 ;
        RECT  0 19.536 0.084 19.56 ;
    END
  END bank_read_addr_w[11]
  PIN bank_read_addr_w[12]
    DIRECTION OUTPUT ;
    USE SIGNAL ;
    PORT
      LAYER M4 ;
        RECT  0 19.632 0.084 19.656 ;
    END
  END bank_read_addr_w[12]
  PIN bank_read_addr_w[13]
    DIRECTION OUTPUT ;
    USE SIGNAL ;
    PORT
      LAYER M4 ;
        RECT  0 19.728 0.084 19.752 ;
    END
  END bank_read_addr_w[13]
  PIN bank_read_addr_w[14]
    DIRECTION OUTPUT ;
    USE SIGNAL ;
    PORT
      LAYER M4 ;
        RECT  0 19.824 0.084 19.848 ;
    END
  END bank_read_addr_w[14]
  PIN bank_read_addr_w[15]
    DIRECTION OUTPUT ;
    USE SIGNAL ;
    PORT
      LAYER M4 ;
        RECT  0 19.92 0.084 19.944 ;
    END
  END bank_read_addr_w[15]
  PIN bank_read_addr_w[16]
    DIRECTION OUTPUT ;
    USE SIGNAL ;
    PORT
      LAYER M4 ;
        RECT  0 20.016 0.084 20.04 ;
    END
  END bank_read_addr_w[16]
  PIN bank_read_addr_w[17]
    DIRECTION OUTPUT ;
    USE SIGNAL ;
    PORT
      LAYER M4 ;
        RECT  0 20.112 0.084 20.136 ;
    END
  END bank_read_addr_w[17]
  PIN bank_read_addr_w[18]
    DIRECTION OUTPUT ;
    USE SIGNAL ;
    PORT
      LAYER M4 ;
        RECT  0 20.208 0.084 20.232 ;
    END
  END bank_read_addr_w[18]
  PIN bank_read_addr_w[19]
    DIRECTION OUTPUT ;
    USE SIGNAL ;
    PORT
      LAYER M4 ;
        RECT  0 20.304 0.084 20.328 ;
    END
  END bank_read_addr_w[19]
  PIN bank_read_addr_w[1]
    DIRECTION OUTPUT ;
    USE SIGNAL ;
    PORT
      LAYER M4 ;
        RECT  0 18.576 0.084 18.6 ;
    END
  END bank_read_addr_w[1]
  PIN bank_read_addr_w[20]
    DIRECTION OUTPUT ;
    USE SIGNAL ;
    PORT
      LAYER M4 ;
        RECT  0 20.4 0.084 20.424 ;
    END
  END bank_read_addr_w[20]
  PIN bank_read_addr_w[21]
    DIRECTION OUTPUT ;
    USE SIGNAL ;
    PORT
      LAYER M4 ;
        RECT  0 20.496 0.084 20.52 ;
    END
  END bank_read_addr_w[21]
  PIN bank_read_addr_w[22]
    DIRECTION OUTPUT ;
    USE SIGNAL ;
    PORT
      LAYER M4 ;
        RECT  0 20.592 0.084 20.616 ;
    END
  END bank_read_addr_w[22]
  PIN bank_read_addr_w[23]
    DIRECTION OUTPUT ;
    USE SIGNAL ;
    PORT
      LAYER M4 ;
        RECT  0 20.688 0.084 20.712 ;
    END
  END bank_read_addr_w[23]
  PIN bank_read_addr_w[24]
    DIRECTION OUTPUT ;
    USE SIGNAL ;
    PORT
      LAYER M4 ;
        RECT  0 14.64 0.084 14.664 ;
    END
  END bank_read_addr_w[24]
  PIN bank_read_addr_w[25]
    DIRECTION OUTPUT ;
    USE SIGNAL ;
    PORT
      LAYER M4 ;
        RECT  0 14.736 0.084 14.76 ;
    END
  END bank_read_addr_w[25]
  PIN bank_read_addr_w[26]
    DIRECTION OUTPUT ;
    USE SIGNAL ;
    PORT
      LAYER M4 ;
        RECT  0 14.832 0.084 14.856 ;
    END
  END bank_read_addr_w[26]
  PIN bank_read_addr_w[27]
    DIRECTION OUTPUT ;
    USE SIGNAL ;
    PORT
      LAYER M4 ;
        RECT  0 14.928 0.084 14.952 ;
    END
  END bank_read_addr_w[27]
  PIN bank_read_addr_w[28]
    DIRECTION OUTPUT ;
    USE SIGNAL ;
    PORT
      LAYER M4 ;
        RECT  0 15.024 0.084 15.048 ;
    END
  END bank_read_addr_w[28]
  PIN bank_read_addr_w[29]
    DIRECTION OUTPUT ;
    USE SIGNAL ;
    PORT
      LAYER M4 ;
        RECT  0 15.12 0.084 15.144 ;
    END
  END bank_read_addr_w[29]
  PIN bank_read_addr_w[2]
    DIRECTION OUTPUT ;
    USE SIGNAL ;
    PORT
      LAYER M4 ;
        RECT  0 18.672 0.084 18.696 ;
    END
  END bank_read_addr_w[2]
  PIN bank_read_addr_w[30]
    DIRECTION OUTPUT ;
    USE SIGNAL ;
    PORT
      LAYER M4 ;
        RECT  0 15.216 0.084 15.24 ;
    END
  END bank_read_addr_w[30]
  PIN bank_read_addr_w[31]
    DIRECTION OUTPUT ;
    USE SIGNAL ;
    PORT
      LAYER M4 ;
        RECT  0 15.312 0.084 15.336 ;
    END
  END bank_read_addr_w[31]
  PIN bank_read_addr_w[32]
    DIRECTION OUTPUT ;
    USE SIGNAL ;
    PORT
      LAYER M4 ;
        RECT  0 15.408 0.084 15.432 ;
    END
  END bank_read_addr_w[32]
  PIN bank_read_addr_w[33]
    DIRECTION OUTPUT ;
    USE SIGNAL ;
    PORT
      LAYER M4 ;
        RECT  0 15.504 0.084 15.528 ;
    END
  END bank_read_addr_w[33]
  PIN bank_read_addr_w[34]
    DIRECTION OUTPUT ;
    USE SIGNAL ;
    PORT
      LAYER M4 ;
        RECT  0 15.6 0.084 15.624 ;
    END
  END bank_read_addr_w[34]
  PIN bank_read_addr_w[35]
    DIRECTION OUTPUT ;
    USE SIGNAL ;
    PORT
      LAYER M4 ;
        RECT  0 15.696 0.084 15.72 ;
    END
  END bank_read_addr_w[35]
  PIN bank_read_addr_w[36]
    DIRECTION OUTPUT ;
    USE SIGNAL ;
    PORT
      LAYER M4 ;
        RECT  0 15.792 0.084 15.816 ;
    END
  END bank_read_addr_w[36]
  PIN bank_read_addr_w[37]
    DIRECTION OUTPUT ;
    USE SIGNAL ;
    PORT
      LAYER M4 ;
        RECT  0 15.888 0.084 15.912 ;
    END
  END bank_read_addr_w[37]
  PIN bank_read_addr_w[38]
    DIRECTION OUTPUT ;
    USE SIGNAL ;
    PORT
      LAYER M4 ;
        RECT  0 15.984 0.084 16.008 ;
    END
  END bank_read_addr_w[38]
  PIN bank_read_addr_w[39]
    DIRECTION OUTPUT ;
    USE SIGNAL ;
    PORT
      LAYER M4 ;
        RECT  0 16.08 0.084 16.104 ;
    END
  END bank_read_addr_w[39]
  PIN bank_read_addr_w[3]
    DIRECTION OUTPUT ;
    USE SIGNAL ;
    PORT
      LAYER M4 ;
        RECT  0 18.768 0.084 18.792 ;
    END
  END bank_read_addr_w[3]
  PIN bank_read_addr_w[40]
    DIRECTION OUTPUT ;
    USE SIGNAL ;
    PORT
      LAYER M4 ;
        RECT  0 16.176 0.084 16.2 ;
    END
  END bank_read_addr_w[40]
  PIN bank_read_addr_w[41]
    DIRECTION OUTPUT ;
    USE SIGNAL ;
    PORT
      LAYER M4 ;
        RECT  0 16.272 0.084 16.296 ;
    END
  END bank_read_addr_w[41]
  PIN bank_read_addr_w[42]
    DIRECTION OUTPUT ;
    USE SIGNAL ;
    PORT
      LAYER M4 ;
        RECT  0 16.368 0.084 16.392 ;
    END
  END bank_read_addr_w[42]
  PIN bank_read_addr_w[43]
    DIRECTION OUTPUT ;
    USE SIGNAL ;
    PORT
      LAYER M4 ;
        RECT  0 16.464 0.084 16.488 ;
    END
  END bank_read_addr_w[43]
  PIN bank_read_addr_w[44]
    DIRECTION OUTPUT ;
    USE SIGNAL ;
    PORT
      LAYER M4 ;
        RECT  0 16.56 0.084 16.584 ;
    END
  END bank_read_addr_w[44]
  PIN bank_read_addr_w[45]
    DIRECTION OUTPUT ;
    USE SIGNAL ;
    PORT
      LAYER M4 ;
        RECT  0 16.656 0.084 16.68 ;
    END
  END bank_read_addr_w[45]
  PIN bank_read_addr_w[46]
    DIRECTION OUTPUT ;
    USE SIGNAL ;
    PORT
      LAYER M4 ;
        RECT  0 16.752 0.084 16.776 ;
    END
  END bank_read_addr_w[46]
  PIN bank_read_addr_w[47]
    DIRECTION OUTPUT ;
    USE SIGNAL ;
    PORT
      LAYER M4 ;
        RECT  0 16.848 0.084 16.872 ;
    END
  END bank_read_addr_w[47]
  PIN bank_read_addr_w[48]
    DIRECTION OUTPUT ;
    USE SIGNAL ;
    PORT
      LAYER M4 ;
        RECT  0 16.944 0.084 16.968 ;
    END
  END bank_read_addr_w[48]
  PIN bank_read_addr_w[49]
    DIRECTION OUTPUT ;
    USE SIGNAL ;
    PORT
      LAYER M4 ;
        RECT  0 17.04 0.084 17.064 ;
    END
  END bank_read_addr_w[49]
  PIN bank_read_addr_w[4]
    DIRECTION OUTPUT ;
    USE SIGNAL ;
    PORT
      LAYER M4 ;
        RECT  0 18.864 0.084 18.888 ;
    END
  END bank_read_addr_w[4]
  PIN bank_read_addr_w[50]
    DIRECTION OUTPUT ;
    USE SIGNAL ;
    PORT
      LAYER M4 ;
        RECT  0 17.136 0.084 17.16 ;
    END
  END bank_read_addr_w[50]
  PIN bank_read_addr_w[51]
    DIRECTION OUTPUT ;
    USE SIGNAL ;
    PORT
      LAYER M4 ;
        RECT  0 17.232 0.084 17.256 ;
    END
  END bank_read_addr_w[51]
  PIN bank_read_addr_w[52]
    DIRECTION OUTPUT ;
    USE SIGNAL ;
    PORT
      LAYER M4 ;
        RECT  0 17.328 0.084 17.352 ;
    END
  END bank_read_addr_w[52]
  PIN bank_read_addr_w[53]
    DIRECTION OUTPUT ;
    USE SIGNAL ;
    PORT
      LAYER M4 ;
        RECT  0 17.424 0.084 17.448 ;
    END
  END bank_read_addr_w[53]
  PIN bank_read_addr_w[54]
    DIRECTION OUTPUT ;
    USE SIGNAL ;
    PORT
      LAYER M4 ;
        RECT  0 17.52 0.084 17.544 ;
    END
  END bank_read_addr_w[54]
  PIN bank_read_addr_w[55]
    DIRECTION OUTPUT ;
    USE SIGNAL ;
    PORT
      LAYER M4 ;
        RECT  0 17.616 0.084 17.64 ;
    END
  END bank_read_addr_w[55]
  PIN bank_read_addr_w[56]
    DIRECTION OUTPUT ;
    USE SIGNAL ;
    PORT
      LAYER M4 ;
        RECT  0 33.84 0.084 33.864 ;
    END
  END bank_read_addr_w[56]
  PIN bank_read_addr_w[57]
    DIRECTION OUTPUT ;
    USE SIGNAL ;
    PORT
      LAYER M4 ;
        RECT  0 33.936 0.084 33.96 ;
    END
  END bank_read_addr_w[57]
  PIN bank_read_addr_w[58]
    DIRECTION OUTPUT ;
    USE SIGNAL ;
    PORT
      LAYER M4 ;
        RECT  0 34.032 0.084 34.056 ;
    END
  END bank_read_addr_w[58]
  PIN bank_read_addr_w[59]
    DIRECTION OUTPUT ;
    USE SIGNAL ;
    PORT
      LAYER M4 ;
        RECT  0 34.128 0.084 34.152 ;
    END
  END bank_read_addr_w[59]
  PIN bank_read_addr_w[5]
    DIRECTION OUTPUT ;
    USE SIGNAL ;
    PORT
      LAYER M4 ;
        RECT  0 18.96 0.084 18.984 ;
    END
  END bank_read_addr_w[5]
  PIN bank_read_addr_w[60]
    DIRECTION OUTPUT ;
    USE SIGNAL ;
    PORT
      LAYER M4 ;
        RECT  0 34.224 0.084 34.248 ;
    END
  END bank_read_addr_w[60]
  PIN bank_read_addr_w[61]
    DIRECTION OUTPUT ;
    USE SIGNAL ;
    PORT
      LAYER M4 ;
        RECT  0 34.32 0.084 34.344 ;
    END
  END bank_read_addr_w[61]
  PIN bank_read_addr_w[62]
    DIRECTION OUTPUT ;
    USE SIGNAL ;
    PORT
      LAYER M4 ;
        RECT  0 34.416 0.084 34.44 ;
    END
  END bank_read_addr_w[62]
  PIN bank_read_addr_w[63]
    DIRECTION OUTPUT ;
    USE SIGNAL ;
    PORT
      LAYER M4 ;
        RECT  0 34.512 0.084 34.536 ;
    END
  END bank_read_addr_w[63]
  PIN bank_read_addr_w[6]
    DIRECTION OUTPUT ;
    USE SIGNAL ;
    PORT
      LAYER M4 ;
        RECT  0 19.056 0.084 19.08 ;
    END
  END bank_read_addr_w[6]
  PIN bank_read_addr_w[7]
    DIRECTION OUTPUT ;
    USE SIGNAL ;
    PORT
      LAYER M4 ;
        RECT  0 19.152 0.084 19.176 ;
    END
  END bank_read_addr_w[7]
  PIN bank_read_addr_w[8]
    DIRECTION OUTPUT ;
    USE SIGNAL ;
    PORT
      LAYER M4 ;
        RECT  0 19.248 0.084 19.272 ;
    END
  END bank_read_addr_w[8]
  PIN bank_read_addr_w[9]
    DIRECTION OUTPUT ;
    USE SIGNAL ;
    PORT
      LAYER M4 ;
        RECT  0 19.344 0.084 19.368 ;
    END
  END bank_read_addr_w[9]
  PIN bank_read_en[0]
    DIRECTION OUTPUT ;
    USE SIGNAL ;
    PORT
      LAYER M4 ;
        RECT  0 34.608 0.084 34.632 ;
    END
  END bank_read_en[0]
  PIN bank_read_en[1]
    DIRECTION OUTPUT ;
    USE SIGNAL ;
    PORT
      LAYER M4 ;
        RECT  0 34.704 0.084 34.728 ;
    END
  END bank_read_en[1]
  PIN bank_read_en[2]
    DIRECTION OUTPUT ;
    USE SIGNAL ;
    PORT
      LAYER M4 ;
        RECT  0 34.8 0.084 34.824 ;
    END
  END bank_read_en[2]
  PIN bank_read_en[3]
    DIRECTION OUTPUT ;
    USE SIGNAL ;
    PORT
      LAYER M4 ;
        RECT  0 34.896 0.084 34.92 ;
    END
  END bank_read_en[3]
  PIN bank_read_en[4]
    DIRECTION OUTPUT ;
    USE SIGNAL ;
    PORT
      LAYER M4 ;
        RECT  0 34.992 0.084 35.016 ;
    END
  END bank_read_en[4]
  PIN bank_read_en[5]
    DIRECTION OUTPUT ;
    USE SIGNAL ;
    PORT
      LAYER M4 ;
        RECT  0 35.088 0.084 35.112 ;
    END
  END bank_read_en[5]
  PIN bank_read_en[6]
    DIRECTION OUTPUT ;
    USE SIGNAL ;
    PORT
      LAYER M4 ;
        RECT  0 35.184 0.084 35.208 ;
    END
  END bank_read_en[6]
  PIN bank_read_en[7]
    DIRECTION OUTPUT ;
    USE SIGNAL ;
    PORT
      LAYER M4 ;
        RECT  0 35.28 0.084 35.304 ;
    END
  END bank_read_en[7]
  PIN bank_read_slot_n[0]
    DIRECTION OUTPUT ;
    USE SIGNAL ;
    PORT
      LAYER M5 ;
        RECT  56.112 69.036 56.136 69.12 ;
    END
  END bank_read_slot_n[0]
  PIN bank_read_slot_n[1]
    DIRECTION OUTPUT ;
    USE SIGNAL ;
    PORT
      LAYER M5 ;
        RECT  56.208 69.036 56.232 69.12 ;
    END
  END bank_read_slot_n[1]
  PIN bank_read_slot_n[2]
    DIRECTION OUTPUT ;
    USE SIGNAL ;
    PORT
      LAYER M5 ;
        RECT  56.304 69.036 56.328 69.12 ;
    END
  END bank_read_slot_n[2]
  PIN bank_read_slot_n[3]
    DIRECTION OUTPUT ;
    USE SIGNAL ;
    PORT
      LAYER M5 ;
        RECT  56.4 69.036 56.424 69.12 ;
    END
  END bank_read_slot_n[3]
  PIN bank_read_slot_n[4]
    DIRECTION OUTPUT ;
    USE SIGNAL ;
    PORT
      LAYER M5 ;
        RECT  56.496 69.036 56.52 69.12 ;
    END
  END bank_read_slot_n[4]
  PIN bank_read_slot_n[5]
    DIRECTION OUTPUT ;
    USE SIGNAL ;
    PORT
      LAYER M5 ;
        RECT  56.592 69.036 56.616 69.12 ;
    END
  END bank_read_slot_n[5]
  PIN bank_read_slot_n[6]
    DIRECTION OUTPUT ;
    USE SIGNAL ;
    PORT
      LAYER M5 ;
        RECT  56.688 69.036 56.712 69.12 ;
    END
  END bank_read_slot_n[6]
  PIN bank_read_slot_s[0]
    DIRECTION OUTPUT ;
    USE SIGNAL ;
    PORT
      LAYER M5 ;
        RECT  56.592 0 56.616 0.084 ;
    END
  END bank_read_slot_s[0]
  PIN bank_read_slot_s[1]
    DIRECTION OUTPUT ;
    USE SIGNAL ;
    PORT
      LAYER M5 ;
        RECT  56.688 0 56.712 0.084 ;
    END
  END bank_read_slot_s[1]
  PIN bank_read_slot_s[2]
    DIRECTION OUTPUT ;
    USE SIGNAL ;
    PORT
      LAYER M5 ;
        RECT  56.784 0 56.808 0.084 ;
    END
  END bank_read_slot_s[2]
  PIN bank_read_slot_s[3]
    DIRECTION OUTPUT ;
    USE SIGNAL ;
    PORT
      LAYER M5 ;
        RECT  56.88 0 56.904 0.084 ;
    END
  END bank_read_slot_s[3]
  PIN bank_read_slot_s[4]
    DIRECTION OUTPUT ;
    USE SIGNAL ;
    PORT
      LAYER M5 ;
        RECT  56.976 0 57 0.084 ;
    END
  END bank_read_slot_s[4]
  PIN bank_read_slot_s[5]
    DIRECTION OUTPUT ;
    USE SIGNAL ;
    PORT
      LAYER M5 ;
        RECT  57.072 0 57.096 0.084 ;
    END
  END bank_read_slot_s[5]
  PIN bank_read_slot_s[6]
    DIRECTION OUTPUT ;
    USE SIGNAL ;
    PORT
      LAYER M5 ;
        RECT  57.168 0 57.192 0.084 ;
    END
  END bank_read_slot_s[6]
  PIN bank_read_slot_w[0]
    DIRECTION OUTPUT ;
    USE SIGNAL ;
    PORT
      LAYER M4 ;
        RECT  0 35.376 0.084 35.4 ;
    END
  END bank_read_slot_w[0]
  PIN bank_read_slot_w[1]
    DIRECTION OUTPUT ;
    USE SIGNAL ;
    PORT
      LAYER M4 ;
        RECT  0 35.472 0.084 35.496 ;
    END
  END bank_read_slot_w[1]
  PIN bank_read_slot_w[2]
    DIRECTION OUTPUT ;
    USE SIGNAL ;
    PORT
      LAYER M4 ;
        RECT  0 35.568 0.084 35.592 ;
    END
  END bank_read_slot_w[2]
  PIN bank_read_slot_w[3]
    DIRECTION OUTPUT ;
    USE SIGNAL ;
    PORT
      LAYER M4 ;
        RECT  0 35.664 0.084 35.688 ;
    END
  END bank_read_slot_w[3]
  PIN bank_read_slot_w[4]
    DIRECTION OUTPUT ;
    USE SIGNAL ;
    PORT
      LAYER M4 ;
        RECT  0 35.76 0.084 35.784 ;
    END
  END bank_read_slot_w[4]
  PIN bank_read_slot_w[5]
    DIRECTION OUTPUT ;
    USE SIGNAL ;
    PORT
      LAYER M4 ;
        RECT  0 35.856 0.084 35.88 ;
    END
  END bank_read_slot_w[5]
  PIN bank_read_slot_w[6]
    DIRECTION OUTPUT ;
    USE SIGNAL ;
    PORT
      LAYER M4 ;
        RECT  0 35.952 0.084 35.976 ;
    END
  END bank_read_slot_w[6]
  PIN bank_write_slot_n[0]
    DIRECTION OUTPUT ;
    USE SIGNAL ;
    PORT
      LAYER M5 ;
        RECT  56.784 69.036 56.808 69.12 ;
    END
  END bank_write_slot_n[0]
  PIN bank_write_slot_n[1]
    DIRECTION OUTPUT ;
    USE SIGNAL ;
    PORT
      LAYER M5 ;
        RECT  56.88 69.036 56.904 69.12 ;
    END
  END bank_write_slot_n[1]
  PIN bank_write_slot_n[2]
    DIRECTION OUTPUT ;
    USE SIGNAL ;
    PORT
      LAYER M5 ;
        RECT  56.976 69.036 57 69.12 ;
    END
  END bank_write_slot_n[2]
  PIN bank_write_slot_n[3]
    DIRECTION OUTPUT ;
    USE SIGNAL ;
    PORT
      LAYER M5 ;
        RECT  57.072 69.036 57.096 69.12 ;
    END
  END bank_write_slot_n[3]
  PIN bank_write_slot_n[4]
    DIRECTION OUTPUT ;
    USE SIGNAL ;
    PORT
      LAYER M5 ;
        RECT  57.168 69.036 57.192 69.12 ;
    END
  END bank_write_slot_n[4]
  PIN bank_write_slot_n[5]
    DIRECTION OUTPUT ;
    USE SIGNAL ;
    PORT
      LAYER M5 ;
        RECT  57.264 69.036 57.288 69.12 ;
    END
  END bank_write_slot_n[5]
  PIN bank_write_slot_n[6]
    DIRECTION OUTPUT ;
    USE SIGNAL ;
    PORT
      LAYER M5 ;
        RECT  57.36 69.036 57.384 69.12 ;
    END
  END bank_write_slot_n[6]
  PIN bank_write_slot_s[0]
    DIRECTION OUTPUT ;
    USE SIGNAL ;
    PORT
      LAYER M5 ;
        RECT  57.264 0 57.288 0.084 ;
    END
  END bank_write_slot_s[0]
  PIN bank_write_slot_s[1]
    DIRECTION OUTPUT ;
    USE SIGNAL ;
    PORT
      LAYER M5 ;
        RECT  57.36 0 57.384 0.084 ;
    END
  END bank_write_slot_s[1]
  PIN bank_write_slot_s[2]
    DIRECTION OUTPUT ;
    USE SIGNAL ;
    PORT
      LAYER M5 ;
        RECT  57.456 0 57.48 0.084 ;
    END
  END bank_write_slot_s[2]
  PIN bank_write_slot_s[3]
    DIRECTION OUTPUT ;
    USE SIGNAL ;
    PORT
      LAYER M5 ;
        RECT  57.552 0 57.576 0.084 ;
    END
  END bank_write_slot_s[3]
  PIN bank_write_slot_s[4]
    DIRECTION OUTPUT ;
    USE SIGNAL ;
    PORT
      LAYER M5 ;
        RECT  57.648 0 57.672 0.084 ;
    END
  END bank_write_slot_s[4]
  PIN bank_write_slot_s[5]
    DIRECTION OUTPUT ;
    USE SIGNAL ;
    PORT
      LAYER M5 ;
        RECT  57.744 0 57.768 0.084 ;
    END
  END bank_write_slot_s[5]
  PIN bank_write_slot_s[6]
    DIRECTION OUTPUT ;
    USE SIGNAL ;
    PORT
      LAYER M5 ;
        RECT  57.84 0 57.864 0.084 ;
    END
  END bank_write_slot_s[6]
  PIN bank_write_slot_w[0]
    DIRECTION OUTPUT ;
    USE SIGNAL ;
    PORT
      LAYER M4 ;
        RECT  0 36.048 0.084 36.072 ;
    END
  END bank_write_slot_w[0]
  PIN bank_write_slot_w[1]
    DIRECTION OUTPUT ;
    USE SIGNAL ;
    PORT
      LAYER M4 ;
        RECT  0 36.144 0.084 36.168 ;
    END
  END bank_write_slot_w[1]
  PIN bank_write_slot_w[2]
    DIRECTION OUTPUT ;
    USE SIGNAL ;
    PORT
      LAYER M4 ;
        RECT  0 36.24 0.084 36.264 ;
    END
  END bank_write_slot_w[2]
  PIN bank_write_slot_w[3]
    DIRECTION OUTPUT ;
    USE SIGNAL ;
    PORT
      LAYER M4 ;
        RECT  0 36.336 0.084 36.36 ;
    END
  END bank_write_slot_w[3]
  PIN bank_write_slot_w[4]
    DIRECTION OUTPUT ;
    USE SIGNAL ;
    PORT
      LAYER M4 ;
        RECT  0 36.432 0.084 36.456 ;
    END
  END bank_write_slot_w[4]
  PIN bank_write_slot_w[5]
    DIRECTION OUTPUT ;
    USE SIGNAL ;
    PORT
      LAYER M4 ;
        RECT  0 36.528 0.084 36.552 ;
    END
  END bank_write_slot_w[5]
  PIN bank_write_slot_w[6]
    DIRECTION OUTPUT ;
    USE SIGNAL ;
    PORT
      LAYER M4 ;
        RECT  0 36.624 0.084 36.648 ;
    END
  END bank_write_slot_w[6]
  PIN busy
    DIRECTION OUTPUT ;
    USE SIGNAL ;
    PORT
      LAYER M4 ;
        RECT  69.036 51.408 69.12 51.432 ;
    END
  END busy
  PIN clk
    DIRECTION INPUT ;
    USE SIGNAL ;
    PORT
      LAYER M4 ;
        RECT  69.036 51.504 69.12 51.528 ;
    END
  END clk
  PIN cycle_in[0]
    DIRECTION INPUT ;
    USE SIGNAL ;
    PORT
      LAYER M4 ;
        RECT  69.036 51.6 69.12 51.624 ;
    END
  END cycle_in[0]
  PIN cycle_in[10]
    DIRECTION INPUT ;
    USE SIGNAL ;
    PORT
      LAYER M4 ;
        RECT  69.036 52.56 69.12 52.584 ;
    END
  END cycle_in[10]
  PIN cycle_in[11]
    DIRECTION INPUT ;
    USE SIGNAL ;
    PORT
      LAYER M4 ;
        RECT  69.036 52.656 69.12 52.68 ;
    END
  END cycle_in[11]
  PIN cycle_in[12]
    DIRECTION INPUT ;
    USE SIGNAL ;
    PORT
      LAYER M4 ;
        RECT  69.036 52.752 69.12 52.776 ;
    END
  END cycle_in[12]
  PIN cycle_in[13]
    DIRECTION INPUT ;
    USE SIGNAL ;
    PORT
      LAYER M4 ;
        RECT  69.036 52.848 69.12 52.872 ;
    END
  END cycle_in[13]
  PIN cycle_in[14]
    DIRECTION INPUT ;
    USE SIGNAL ;
    PORT
      LAYER M4 ;
        RECT  69.036 52.944 69.12 52.968 ;
    END
  END cycle_in[14]
  PIN cycle_in[15]
    DIRECTION INPUT ;
    USE SIGNAL ;
    PORT
      LAYER M4 ;
        RECT  69.036 53.04 69.12 53.064 ;
    END
  END cycle_in[15]
  PIN cycle_in[16]
    DIRECTION INPUT ;
    USE SIGNAL ;
    PORT
      LAYER M4 ;
        RECT  69.036 53.136 69.12 53.16 ;
    END
  END cycle_in[16]
  PIN cycle_in[17]
    DIRECTION INPUT ;
    USE SIGNAL ;
    PORT
      LAYER M4 ;
        RECT  69.036 53.232 69.12 53.256 ;
    END
  END cycle_in[17]
  PIN cycle_in[18]
    DIRECTION INPUT ;
    USE SIGNAL ;
    PORT
      LAYER M4 ;
        RECT  69.036 53.328 69.12 53.352 ;
    END
  END cycle_in[18]
  PIN cycle_in[19]
    DIRECTION INPUT ;
    USE SIGNAL ;
    PORT
      LAYER M4 ;
        RECT  69.036 53.424 69.12 53.448 ;
    END
  END cycle_in[19]
  PIN cycle_in[1]
    DIRECTION INPUT ;
    USE SIGNAL ;
    PORT
      LAYER M4 ;
        RECT  69.036 51.696 69.12 51.72 ;
    END
  END cycle_in[1]
  PIN cycle_in[20]
    DIRECTION INPUT ;
    USE SIGNAL ;
    PORT
      LAYER M4 ;
        RECT  69.036 53.52 69.12 53.544 ;
    END
  END cycle_in[20]
  PIN cycle_in[21]
    DIRECTION INPUT ;
    USE SIGNAL ;
    PORT
      LAYER M4 ;
        RECT  69.036 53.616 69.12 53.64 ;
    END
  END cycle_in[21]
  PIN cycle_in[22]
    DIRECTION INPUT ;
    USE SIGNAL ;
    PORT
      LAYER M4 ;
        RECT  69.036 53.712 69.12 53.736 ;
    END
  END cycle_in[22]
  PIN cycle_in[23]
    DIRECTION INPUT ;
    USE SIGNAL ;
    PORT
      LAYER M4 ;
        RECT  69.036 53.808 69.12 53.832 ;
    END
  END cycle_in[23]
  PIN cycle_in[24]
    DIRECTION INPUT ;
    USE SIGNAL ;
    PORT
      LAYER M4 ;
        RECT  69.036 53.904 69.12 53.928 ;
    END
  END cycle_in[24]
  PIN cycle_in[25]
    DIRECTION INPUT ;
    USE SIGNAL ;
    PORT
      LAYER M4 ;
        RECT  69.036 54 69.12 54.024 ;
    END
  END cycle_in[25]
  PIN cycle_in[26]
    DIRECTION INPUT ;
    USE SIGNAL ;
    PORT
      LAYER M4 ;
        RECT  69.036 54.096 69.12 54.12 ;
    END
  END cycle_in[26]
  PIN cycle_in[27]
    DIRECTION INPUT ;
    USE SIGNAL ;
    PORT
      LAYER M4 ;
        RECT  69.036 54.192 69.12 54.216 ;
    END
  END cycle_in[27]
  PIN cycle_in[28]
    DIRECTION INPUT ;
    USE SIGNAL ;
    PORT
      LAYER M4 ;
        RECT  69.036 54.288 69.12 54.312 ;
    END
  END cycle_in[28]
  PIN cycle_in[29]
    DIRECTION INPUT ;
    USE SIGNAL ;
    PORT
      LAYER M4 ;
        RECT  69.036 54.384 69.12 54.408 ;
    END
  END cycle_in[29]
  PIN cycle_in[2]
    DIRECTION INPUT ;
    USE SIGNAL ;
    PORT
      LAYER M4 ;
        RECT  69.036 51.792 69.12 51.816 ;
    END
  END cycle_in[2]
  PIN cycle_in[30]
    DIRECTION INPUT ;
    USE SIGNAL ;
    PORT
      LAYER M4 ;
        RECT  69.036 58.32 69.12 58.344 ;
    END
  END cycle_in[30]
  PIN cycle_in[31]
    DIRECTION INPUT ;
    USE SIGNAL ;
    PORT
      LAYER M4 ;
        RECT  69.036 58.416 69.12 58.44 ;
    END
  END cycle_in[31]
  PIN cycle_in[3]
    DIRECTION INPUT ;
    USE SIGNAL ;
    PORT
      LAYER M4 ;
        RECT  69.036 51.888 69.12 51.912 ;
    END
  END cycle_in[3]
  PIN cycle_in[4]
    DIRECTION INPUT ;
    USE SIGNAL ;
    PORT
      LAYER M4 ;
        RECT  69.036 51.984 69.12 52.008 ;
    END
  END cycle_in[4]
  PIN cycle_in[5]
    DIRECTION INPUT ;
    USE SIGNAL ;
    PORT
      LAYER M4 ;
        RECT  69.036 52.08 69.12 52.104 ;
    END
  END cycle_in[5]
  PIN cycle_in[6]
    DIRECTION INPUT ;
    USE SIGNAL ;
    PORT
      LAYER M4 ;
        RECT  69.036 52.176 69.12 52.2 ;
    END
  END cycle_in[6]
  PIN cycle_in[7]
    DIRECTION INPUT ;
    USE SIGNAL ;
    PORT
      LAYER M4 ;
        RECT  69.036 52.272 69.12 52.296 ;
    END
  END cycle_in[7]
  PIN cycle_in[8]
    DIRECTION INPUT ;
    USE SIGNAL ;
    PORT
      LAYER M4 ;
        RECT  69.036 52.368 69.12 52.392 ;
    END
  END cycle_in[8]
  PIN cycle_in[9]
    DIRECTION INPUT ;
    USE SIGNAL ;
    PORT
      LAYER M4 ;
        RECT  69.036 52.464 69.12 52.488 ;
    END
  END cycle_in[9]
  PIN drain_at[0]
    DIRECTION INPUT ;
    USE SIGNAL ;
    PORT
      LAYER M4 ;
        RECT  69.036 58.512 69.12 58.536 ;
    END
  END drain_at[0]
  PIN drain_at[10]
    DIRECTION INPUT ;
    USE SIGNAL ;
    PORT
      LAYER M4 ;
        RECT  69.036 59.472 69.12 59.496 ;
    END
  END drain_at[10]
  PIN drain_at[11]
    DIRECTION INPUT ;
    USE SIGNAL ;
    PORT
      LAYER M4 ;
        RECT  69.036 59.568 69.12 59.592 ;
    END
  END drain_at[11]
  PIN drain_at[12]
    DIRECTION INPUT ;
    USE SIGNAL ;
    PORT
      LAYER M4 ;
        RECT  69.036 59.664 69.12 59.688 ;
    END
  END drain_at[12]
  PIN drain_at[13]
    DIRECTION INPUT ;
    USE SIGNAL ;
    PORT
      LAYER M4 ;
        RECT  69.036 59.76 69.12 59.784 ;
    END
  END drain_at[13]
  PIN drain_at[14]
    DIRECTION INPUT ;
    USE SIGNAL ;
    PORT
      LAYER M4 ;
        RECT  69.036 59.856 69.12 59.88 ;
    END
  END drain_at[14]
  PIN drain_at[15]
    DIRECTION INPUT ;
    USE SIGNAL ;
    PORT
      LAYER M4 ;
        RECT  69.036 59.952 69.12 59.976 ;
    END
  END drain_at[15]
  PIN drain_at[16]
    DIRECTION INPUT ;
    USE SIGNAL ;
    PORT
      LAYER M4 ;
        RECT  69.036 60.048 69.12 60.072 ;
    END
  END drain_at[16]
  PIN drain_at[17]
    DIRECTION INPUT ;
    USE SIGNAL ;
    PORT
      LAYER M4 ;
        RECT  69.036 60.144 69.12 60.168 ;
    END
  END drain_at[17]
  PIN drain_at[18]
    DIRECTION INPUT ;
    USE SIGNAL ;
    PORT
      LAYER M4 ;
        RECT  69.036 60.24 69.12 60.264 ;
    END
  END drain_at[18]
  PIN drain_at[19]
    DIRECTION INPUT ;
    USE SIGNAL ;
    PORT
      LAYER M4 ;
        RECT  69.036 60.336 69.12 60.36 ;
    END
  END drain_at[19]
  PIN drain_at[1]
    DIRECTION INPUT ;
    USE SIGNAL ;
    PORT
      LAYER M4 ;
        RECT  69.036 58.608 69.12 58.632 ;
    END
  END drain_at[1]
  PIN drain_at[20]
    DIRECTION INPUT ;
    USE SIGNAL ;
    PORT
      LAYER M4 ;
        RECT  69.036 60.432 69.12 60.456 ;
    END
  END drain_at[20]
  PIN drain_at[21]
    DIRECTION INPUT ;
    USE SIGNAL ;
    PORT
      LAYER M4 ;
        RECT  69.036 60.528 69.12 60.552 ;
    END
  END drain_at[21]
  PIN drain_at[22]
    DIRECTION INPUT ;
    USE SIGNAL ;
    PORT
      LAYER M4 ;
        RECT  69.036 60.624 69.12 60.648 ;
    END
  END drain_at[22]
  PIN drain_at[23]
    DIRECTION INPUT ;
    USE SIGNAL ;
    PORT
      LAYER M4 ;
        RECT  69.036 60.72 69.12 60.744 ;
    END
  END drain_at[23]
  PIN drain_at[24]
    DIRECTION INPUT ;
    USE SIGNAL ;
    PORT
      LAYER M4 ;
        RECT  69.036 60.816 69.12 60.84 ;
    END
  END drain_at[24]
  PIN drain_at[25]
    DIRECTION INPUT ;
    USE SIGNAL ;
    PORT
      LAYER M4 ;
        RECT  69.036 60.912 69.12 60.936 ;
    END
  END drain_at[25]
  PIN drain_at[26]
    DIRECTION INPUT ;
    USE SIGNAL ;
    PORT
      LAYER M4 ;
        RECT  69.036 61.008 69.12 61.032 ;
    END
  END drain_at[26]
  PIN drain_at[27]
    DIRECTION INPUT ;
    USE SIGNAL ;
    PORT
      LAYER M4 ;
        RECT  69.036 61.104 69.12 61.128 ;
    END
  END drain_at[27]
  PIN drain_at[28]
    DIRECTION INPUT ;
    USE SIGNAL ;
    PORT
      LAYER M4 ;
        RECT  69.036 61.2 69.12 61.224 ;
    END
  END drain_at[28]
  PIN drain_at[29]
    DIRECTION INPUT ;
    USE SIGNAL ;
    PORT
      LAYER M4 ;
        RECT  69.036 61.296 69.12 61.32 ;
    END
  END drain_at[29]
  PIN drain_at[2]
    DIRECTION INPUT ;
    USE SIGNAL ;
    PORT
      LAYER M4 ;
        RECT  69.036 58.704 69.12 58.728 ;
    END
  END drain_at[2]
  PIN drain_at[30]
    DIRECTION INPUT ;
    USE SIGNAL ;
    PORT
      LAYER M4 ;
        RECT  69.036 64.464 69.12 64.488 ;
    END
  END drain_at[30]
  PIN drain_at[31]
    DIRECTION INPUT ;
    USE SIGNAL ;
    PORT
      LAYER M4 ;
        RECT  69.036 64.56 69.12 64.584 ;
    END
  END drain_at[31]
  PIN drain_at[3]
    DIRECTION INPUT ;
    USE SIGNAL ;
    PORT
      LAYER M4 ;
        RECT  69.036 58.8 69.12 58.824 ;
    END
  END drain_at[3]
  PIN drain_at[4]
    DIRECTION INPUT ;
    USE SIGNAL ;
    PORT
      LAYER M4 ;
        RECT  69.036 58.896 69.12 58.92 ;
    END
  END drain_at[4]
  PIN drain_at[5]
    DIRECTION INPUT ;
    USE SIGNAL ;
    PORT
      LAYER M4 ;
        RECT  69.036 58.992 69.12 59.016 ;
    END
  END drain_at[5]
  PIN drain_at[6]
    DIRECTION INPUT ;
    USE SIGNAL ;
    PORT
      LAYER M4 ;
        RECT  69.036 59.088 69.12 59.112 ;
    END
  END drain_at[6]
  PIN drain_at[7]
    DIRECTION INPUT ;
    USE SIGNAL ;
    PORT
      LAYER M4 ;
        RECT  69.036 59.184 69.12 59.208 ;
    END
  END drain_at[7]
  PIN drain_at[8]
    DIRECTION INPUT ;
    USE SIGNAL ;
    PORT
      LAYER M4 ;
        RECT  69.036 59.28 69.12 59.304 ;
    END
  END drain_at[8]
  PIN drain_at[9]
    DIRECTION INPUT ;
    USE SIGNAL ;
    PORT
      LAYER M4 ;
        RECT  69.036 59.376 69.12 59.4 ;
    END
  END drain_at[9]
  PIN issue_at[0]
    DIRECTION INPUT ;
    USE SIGNAL ;
    PORT
      LAYER M4 ;
        RECT  69.036 64.656 69.12 64.68 ;
    END
  END issue_at[0]
  PIN issue_at[10]
    DIRECTION INPUT ;
    USE SIGNAL ;
    PORT
      LAYER M4 ;
        RECT  69.036 65.616 69.12 65.64 ;
    END
  END issue_at[10]
  PIN issue_at[11]
    DIRECTION INPUT ;
    USE SIGNAL ;
    PORT
      LAYER M4 ;
        RECT  69.036 65.712 69.12 65.736 ;
    END
  END issue_at[11]
  PIN issue_at[12]
    DIRECTION INPUT ;
    USE SIGNAL ;
    PORT
      LAYER M4 ;
        RECT  69.036 65.808 69.12 65.832 ;
    END
  END issue_at[12]
  PIN issue_at[13]
    DIRECTION INPUT ;
    USE SIGNAL ;
    PORT
      LAYER M4 ;
        RECT  69.036 65.904 69.12 65.928 ;
    END
  END issue_at[13]
  PIN issue_at[14]
    DIRECTION INPUT ;
    USE SIGNAL ;
    PORT
      LAYER M4 ;
        RECT  69.036 66 69.12 66.024 ;
    END
  END issue_at[14]
  PIN issue_at[15]
    DIRECTION INPUT ;
    USE SIGNAL ;
    PORT
      LAYER M4 ;
        RECT  69.036 66.096 69.12 66.12 ;
    END
  END issue_at[15]
  PIN issue_at[16]
    DIRECTION INPUT ;
    USE SIGNAL ;
    PORT
      LAYER M4 ;
        RECT  69.036 66.192 69.12 66.216 ;
    END
  END issue_at[16]
  PIN issue_at[17]
    DIRECTION INPUT ;
    USE SIGNAL ;
    PORT
      LAYER M4 ;
        RECT  69.036 66.288 69.12 66.312 ;
    END
  END issue_at[17]
  PIN issue_at[18]
    DIRECTION INPUT ;
    USE SIGNAL ;
    PORT
      LAYER M4 ;
        RECT  69.036 66.384 69.12 66.408 ;
    END
  END issue_at[18]
  PIN issue_at[19]
    DIRECTION INPUT ;
    USE SIGNAL ;
    PORT
      LAYER M4 ;
        RECT  69.036 66.48 69.12 66.504 ;
    END
  END issue_at[19]
  PIN issue_at[1]
    DIRECTION INPUT ;
    USE SIGNAL ;
    PORT
      LAYER M4 ;
        RECT  69.036 64.752 69.12 64.776 ;
    END
  END issue_at[1]
  PIN issue_at[20]
    DIRECTION INPUT ;
    USE SIGNAL ;
    PORT
      LAYER M4 ;
        RECT  69.036 66.576 69.12 66.6 ;
    END
  END issue_at[20]
  PIN issue_at[21]
    DIRECTION INPUT ;
    USE SIGNAL ;
    PORT
      LAYER M4 ;
        RECT  69.036 66.672 69.12 66.696 ;
    END
  END issue_at[21]
  PIN issue_at[22]
    DIRECTION INPUT ;
    USE SIGNAL ;
    PORT
      LAYER M4 ;
        RECT  69.036 66.768 69.12 66.792 ;
    END
  END issue_at[22]
  PIN issue_at[23]
    DIRECTION INPUT ;
    USE SIGNAL ;
    PORT
      LAYER M4 ;
        RECT  69.036 66.864 69.12 66.888 ;
    END
  END issue_at[23]
  PIN issue_at[24]
    DIRECTION INPUT ;
    USE SIGNAL ;
    PORT
      LAYER M4 ;
        RECT  69.036 66.96 69.12 66.984 ;
    END
  END issue_at[24]
  PIN issue_at[25]
    DIRECTION INPUT ;
    USE SIGNAL ;
    PORT
      LAYER M4 ;
        RECT  69.036 67.056 69.12 67.08 ;
    END
  END issue_at[25]
  PIN issue_at[26]
    DIRECTION INPUT ;
    USE SIGNAL ;
    PORT
      LAYER M4 ;
        RECT  69.036 67.152 69.12 67.176 ;
    END
  END issue_at[26]
  PIN issue_at[27]
    DIRECTION INPUT ;
    USE SIGNAL ;
    PORT
      LAYER M4 ;
        RECT  69.036 67.248 69.12 67.272 ;
    END
  END issue_at[27]
  PIN issue_at[28]
    DIRECTION INPUT ;
    USE SIGNAL ;
    PORT
      LAYER M4 ;
        RECT  69.036 67.344 69.12 67.368 ;
    END
  END issue_at[28]
  PIN issue_at[29]
    DIRECTION INPUT ;
    USE SIGNAL ;
    PORT
      LAYER M4 ;
        RECT  69.036 67.44 69.12 67.464 ;
    END
  END issue_at[29]
  PIN issue_at[2]
    DIRECTION INPUT ;
    USE SIGNAL ;
    PORT
      LAYER M4 ;
        RECT  69.036 64.848 69.12 64.872 ;
    END
  END issue_at[2]
  PIN issue_at[30]
    DIRECTION INPUT ;
    USE SIGNAL ;
    PORT
      LAYER M4 ;
        RECT  69.036 32.208 69.12 32.232 ;
    END
  END issue_at[30]
  PIN issue_at[31]
    DIRECTION INPUT ;
    USE SIGNAL ;
    PORT
      LAYER M4 ;
        RECT  69.036 32.304 69.12 32.328 ;
    END
  END issue_at[31]
  PIN issue_at[3]
    DIRECTION INPUT ;
    USE SIGNAL ;
    PORT
      LAYER M4 ;
        RECT  69.036 64.944 69.12 64.968 ;
    END
  END issue_at[3]
  PIN issue_at[4]
    DIRECTION INPUT ;
    USE SIGNAL ;
    PORT
      LAYER M4 ;
        RECT  69.036 65.04 69.12 65.064 ;
    END
  END issue_at[4]
  PIN issue_at[5]
    DIRECTION INPUT ;
    USE SIGNAL ;
    PORT
      LAYER M4 ;
        RECT  69.036 65.136 69.12 65.16 ;
    END
  END issue_at[5]
  PIN issue_at[6]
    DIRECTION INPUT ;
    USE SIGNAL ;
    PORT
      LAYER M4 ;
        RECT  69.036 65.232 69.12 65.256 ;
    END
  END issue_at[6]
  PIN issue_at[7]
    DIRECTION INPUT ;
    USE SIGNAL ;
    PORT
      LAYER M4 ;
        RECT  69.036 65.328 69.12 65.352 ;
    END
  END issue_at[7]
  PIN issue_at[8]
    DIRECTION INPUT ;
    USE SIGNAL ;
    PORT
      LAYER M4 ;
        RECT  69.036 65.424 69.12 65.448 ;
    END
  END issue_at[8]
  PIN issue_at[9]
    DIRECTION INPUT ;
    USE SIGNAL ;
    PORT
      LAYER M4 ;
        RECT  69.036 65.52 69.12 65.544 ;
    END
  END issue_at[9]
  PIN mv[0]
    DIRECTION INPUT ;
    USE SIGNAL ;
    PORT
      LAYER M4 ;
        RECT  69.036 32.4 69.12 32.424 ;
    END
  END mv[0]
  PIN mv[100]
    DIRECTION INPUT ;
    USE SIGNAL ;
    PORT
      LAYER M4 ;
        RECT  69.036 16.656 69.12 16.68 ;
    END
  END mv[100]
  PIN mv[101]
    DIRECTION INPUT ;
    USE SIGNAL ;
    PORT
      LAYER M4 ;
        RECT  69.036 16.752 69.12 16.776 ;
    END
  END mv[101]
  PIN mv[102]
    DIRECTION INPUT ;
    USE SIGNAL ;
    PORT
      LAYER M4 ;
        RECT  69.036 16.848 69.12 16.872 ;
    END
  END mv[102]
  PIN mv[103]
    DIRECTION INPUT ;
    USE SIGNAL ;
    PORT
      LAYER M4 ;
        RECT  69.036 16.944 69.12 16.968 ;
    END
  END mv[103]
  PIN mv[104]
    DIRECTION INPUT ;
    USE SIGNAL ;
    PORT
      LAYER M4 ;
        RECT  69.036 17.04 69.12 17.064 ;
    END
  END mv[104]
  PIN mv[105]
    DIRECTION INPUT ;
    USE SIGNAL ;
    PORT
      LAYER M4 ;
        RECT  69.036 17.136 69.12 17.16 ;
    END
  END mv[105]
  PIN mv[106]
    DIRECTION INPUT ;
    USE SIGNAL ;
    PORT
      LAYER M4 ;
        RECT  69.036 17.232 69.12 17.256 ;
    END
  END mv[106]
  PIN mv[107]
    DIRECTION INPUT ;
    USE SIGNAL ;
    PORT
      LAYER M4 ;
        RECT  69.036 17.328 69.12 17.352 ;
    END
  END mv[107]
  PIN mv[108]
    DIRECTION INPUT ;
    USE SIGNAL ;
    PORT
      LAYER M4 ;
        RECT  69.036 17.424 69.12 17.448 ;
    END
  END mv[108]
  PIN mv[109]
    DIRECTION INPUT ;
    USE SIGNAL ;
    PORT
      LAYER M4 ;
        RECT  69.036 17.52 69.12 17.544 ;
    END
  END mv[109]
  PIN mv[10]
    DIRECTION INPUT ;
    USE SIGNAL ;
    PORT
      LAYER M4 ;
        RECT  69.036 33.36 69.12 33.384 ;
    END
  END mv[10]
  PIN mv[110]
    DIRECTION INPUT ;
    USE SIGNAL ;
    PORT
      LAYER M4 ;
        RECT  69.036 17.616 69.12 17.64 ;
    END
  END mv[110]
  PIN mv[111]
    DIRECTION INPUT ;
    USE SIGNAL ;
    PORT
      LAYER M4 ;
        RECT  69.036 17.712 69.12 17.736 ;
    END
  END mv[111]
  PIN mv[112]
    DIRECTION INPUT ;
    USE SIGNAL ;
    PORT
      LAYER M4 ;
        RECT  69.036 17.808 69.12 17.832 ;
    END
  END mv[112]
  PIN mv[113]
    DIRECTION INPUT ;
    USE SIGNAL ;
    PORT
      LAYER M4 ;
        RECT  69.036 17.904 69.12 17.928 ;
    END
  END mv[113]
  PIN mv[114]
    DIRECTION INPUT ;
    USE SIGNAL ;
    PORT
      LAYER M4 ;
        RECT  69.036 18 69.12 18.024 ;
    END
  END mv[114]
  PIN mv[115]
    DIRECTION INPUT ;
    USE SIGNAL ;
    PORT
      LAYER M4 ;
        RECT  69.036 18.096 69.12 18.12 ;
    END
  END mv[115]
  PIN mv[116]
    DIRECTION INPUT ;
    USE SIGNAL ;
    PORT
      LAYER M4 ;
        RECT  69.036 18.192 69.12 18.216 ;
    END
  END mv[116]
  PIN mv[117]
    DIRECTION INPUT ;
    USE SIGNAL ;
    PORT
      LAYER M4 ;
        RECT  69.036 18.288 69.12 18.312 ;
    END
  END mv[117]
  PIN mv[118]
    DIRECTION INPUT ;
    USE SIGNAL ;
    PORT
      LAYER M4 ;
        RECT  69.036 18.384 69.12 18.408 ;
    END
  END mv[118]
  PIN mv[119]
    DIRECTION INPUT ;
    USE SIGNAL ;
    PORT
      LAYER M4 ;
        RECT  69.036 18.48 69.12 18.504 ;
    END
  END mv[119]
  PIN mv[11]
    DIRECTION INPUT ;
    USE SIGNAL ;
    PORT
      LAYER M4 ;
        RECT  69.036 33.456 69.12 33.48 ;
    END
  END mv[11]
  PIN mv[120]
    DIRECTION INPUT ;
    USE SIGNAL ;
    PORT
      LAYER M4 ;
        RECT  69.036 18.576 69.12 18.6 ;
    END
  END mv[120]
  PIN mv[121]
    DIRECTION INPUT ;
    USE SIGNAL ;
    PORT
      LAYER M4 ;
        RECT  69.036 18.672 69.12 18.696 ;
    END
  END mv[121]
  PIN mv[122]
    DIRECTION INPUT ;
    USE SIGNAL ;
    PORT
      LAYER M4 ;
        RECT  69.036 18.768 69.12 18.792 ;
    END
  END mv[122]
  PIN mv[123]
    DIRECTION INPUT ;
    USE SIGNAL ;
    PORT
      LAYER M4 ;
        RECT  69.036 18.864 69.12 18.888 ;
    END
  END mv[123]
  PIN mv[124]
    DIRECTION INPUT ;
    USE SIGNAL ;
    PORT
      LAYER M4 ;
        RECT  69.036 18.96 69.12 18.984 ;
    END
  END mv[124]
  PIN mv[125]
    DIRECTION INPUT ;
    USE SIGNAL ;
    PORT
      LAYER M4 ;
        RECT  69.036 19.056 69.12 19.08 ;
    END
  END mv[125]
  PIN mv[126]
    DIRECTION INPUT ;
    USE SIGNAL ;
    PORT
      LAYER M4 ;
        RECT  69.036 13.008 69.12 13.032 ;
    END
  END mv[126]
  PIN mv[127]
    DIRECTION INPUT ;
    USE SIGNAL ;
    PORT
      LAYER M4 ;
        RECT  69.036 13.104 69.12 13.128 ;
    END
  END mv[127]
  PIN mv[128]
    DIRECTION INPUT ;
    USE SIGNAL ;
    PORT
      LAYER M4 ;
        RECT  69.036 13.2 69.12 13.224 ;
    END
  END mv[128]
  PIN mv[129]
    DIRECTION INPUT ;
    USE SIGNAL ;
    PORT
      LAYER M4 ;
        RECT  69.036 13.296 69.12 13.32 ;
    END
  END mv[129]
  PIN mv[12]
    DIRECTION INPUT ;
    USE SIGNAL ;
    PORT
      LAYER M4 ;
        RECT  69.036 33.552 69.12 33.576 ;
    END
  END mv[12]
  PIN mv[130]
    DIRECTION INPUT ;
    USE SIGNAL ;
    PORT
      LAYER M4 ;
        RECT  69.036 13.392 69.12 13.416 ;
    END
  END mv[130]
  PIN mv[131]
    DIRECTION INPUT ;
    USE SIGNAL ;
    PORT
      LAYER M4 ;
        RECT  69.036 13.488 69.12 13.512 ;
    END
  END mv[131]
  PIN mv[132]
    DIRECTION INPUT ;
    USE SIGNAL ;
    PORT
      LAYER M4 ;
        RECT  69.036 13.584 69.12 13.608 ;
    END
  END mv[132]
  PIN mv[133]
    DIRECTION INPUT ;
    USE SIGNAL ;
    PORT
      LAYER M4 ;
        RECT  69.036 13.68 69.12 13.704 ;
    END
  END mv[133]
  PIN mv[134]
    DIRECTION INPUT ;
    USE SIGNAL ;
    PORT
      LAYER M4 ;
        RECT  69.036 13.776 69.12 13.8 ;
    END
  END mv[134]
  PIN mv[135]
    DIRECTION INPUT ;
    USE SIGNAL ;
    PORT
      LAYER M4 ;
        RECT  69.036 13.872 69.12 13.896 ;
    END
  END mv[135]
  PIN mv[136]
    DIRECTION INPUT ;
    USE SIGNAL ;
    PORT
      LAYER M4 ;
        RECT  69.036 13.968 69.12 13.992 ;
    END
  END mv[136]
  PIN mv[137]
    DIRECTION INPUT ;
    USE SIGNAL ;
    PORT
      LAYER M4 ;
        RECT  69.036 14.064 69.12 14.088 ;
    END
  END mv[137]
  PIN mv[138]
    DIRECTION INPUT ;
    USE SIGNAL ;
    PORT
      LAYER M4 ;
        RECT  69.036 14.16 69.12 14.184 ;
    END
  END mv[138]
  PIN mv[139]
    DIRECTION INPUT ;
    USE SIGNAL ;
    PORT
      LAYER M4 ;
        RECT  69.036 14.256 69.12 14.28 ;
    END
  END mv[139]
  PIN mv[13]
    DIRECTION INPUT ;
    USE SIGNAL ;
    PORT
      LAYER M4 ;
        RECT  69.036 33.648 69.12 33.672 ;
    END
  END mv[13]
  PIN mv[140]
    DIRECTION INPUT ;
    USE SIGNAL ;
    PORT
      LAYER M4 ;
        RECT  69.036 14.352 69.12 14.376 ;
    END
  END mv[140]
  PIN mv[141]
    DIRECTION INPUT ;
    USE SIGNAL ;
    PORT
      LAYER M4 ;
        RECT  69.036 14.448 69.12 14.472 ;
    END
  END mv[141]
  PIN mv[142]
    DIRECTION INPUT ;
    USE SIGNAL ;
    PORT
      LAYER M4 ;
        RECT  69.036 14.544 69.12 14.568 ;
    END
  END mv[142]
  PIN mv[143]
    DIRECTION INPUT ;
    USE SIGNAL ;
    PORT
      LAYER M4 ;
        RECT  69.036 14.64 69.12 14.664 ;
    END
  END mv[143]
  PIN mv[144]
    DIRECTION INPUT ;
    USE SIGNAL ;
    PORT
      LAYER M4 ;
        RECT  69.036 14.736 69.12 14.76 ;
    END
  END mv[144]
  PIN mv[145]
    DIRECTION INPUT ;
    USE SIGNAL ;
    PORT
      LAYER M4 ;
        RECT  69.036 14.832 69.12 14.856 ;
    END
  END mv[145]
  PIN mv[146]
    DIRECTION INPUT ;
    USE SIGNAL ;
    PORT
      LAYER M4 ;
        RECT  69.036 14.928 69.12 14.952 ;
    END
  END mv[146]
  PIN mv[147]
    DIRECTION INPUT ;
    USE SIGNAL ;
    PORT
      LAYER M4 ;
        RECT  69.036 15.024 69.12 15.048 ;
    END
  END mv[147]
  PIN mv[148]
    DIRECTION INPUT ;
    USE SIGNAL ;
    PORT
      LAYER M4 ;
        RECT  69.036 15.12 69.12 15.144 ;
    END
  END mv[148]
  PIN mv[149]
    DIRECTION INPUT ;
    USE SIGNAL ;
    PORT
      LAYER M4 ;
        RECT  69.036 15.216 69.12 15.24 ;
    END
  END mv[149]
  PIN mv[14]
    DIRECTION INPUT ;
    USE SIGNAL ;
    PORT
      LAYER M4 ;
        RECT  69.036 33.744 69.12 33.768 ;
    END
  END mv[14]
  PIN mv[150]
    DIRECTION INPUT ;
    USE SIGNAL ;
    PORT
      LAYER M4 ;
        RECT  69.036 15.312 69.12 15.336 ;
    END
  END mv[150]
  PIN mv[151]
    DIRECTION INPUT ;
    USE SIGNAL ;
    PORT
      LAYER M4 ;
        RECT  69.036 15.408 69.12 15.432 ;
    END
  END mv[151]
  PIN mv[152]
    DIRECTION INPUT ;
    USE SIGNAL ;
    PORT
      LAYER M4 ;
        RECT  69.036 15.504 69.12 15.528 ;
    END
  END mv[152]
  PIN mv[153]
    DIRECTION INPUT ;
    USE SIGNAL ;
    PORT
      LAYER M4 ;
        RECT  69.036 15.6 69.12 15.624 ;
    END
  END mv[153]
  PIN mv[154]
    DIRECTION INPUT ;
    USE SIGNAL ;
    PORT
      LAYER M4 ;
        RECT  69.036 15.696 69.12 15.72 ;
    END
  END mv[154]
  PIN mv[155]
    DIRECTION INPUT ;
    USE SIGNAL ;
    PORT
      LAYER M4 ;
        RECT  69.036 15.792 69.12 15.816 ;
    END
  END mv[155]
  PIN mv[156]
    DIRECTION INPUT ;
    USE SIGNAL ;
    PORT
      LAYER M4 ;
        RECT  69.036 15.888 69.12 15.912 ;
    END
  END mv[156]
  PIN mv[157]
    DIRECTION INPUT ;
    USE SIGNAL ;
    PORT
      LAYER M4 ;
        RECT  69.036 15.984 69.12 16.008 ;
    END
  END mv[157]
  PIN mv[158]
    DIRECTION INPUT ;
    USE SIGNAL ;
    PORT
      LAYER M4 ;
        RECT  69.036 19.92 69.12 19.944 ;
    END
  END mv[158]
  PIN mv[159]
    DIRECTION INPUT ;
    USE SIGNAL ;
    PORT
      LAYER M4 ;
        RECT  69.036 20.016 69.12 20.04 ;
    END
  END mv[159]
  PIN mv[15]
    DIRECTION INPUT ;
    USE SIGNAL ;
    PORT
      LAYER M4 ;
        RECT  69.036 33.84 69.12 33.864 ;
    END
  END mv[15]
  PIN mv[160]
    DIRECTION INPUT ;
    USE SIGNAL ;
    PORT
      LAYER M4 ;
        RECT  69.036 20.112 69.12 20.136 ;
    END
  END mv[160]
  PIN mv[161]
    DIRECTION INPUT ;
    USE SIGNAL ;
    PORT
      LAYER M4 ;
        RECT  69.036 20.208 69.12 20.232 ;
    END
  END mv[161]
  PIN mv[162]
    DIRECTION INPUT ;
    USE SIGNAL ;
    PORT
      LAYER M4 ;
        RECT  69.036 20.304 69.12 20.328 ;
    END
  END mv[162]
  PIN mv[163]
    DIRECTION INPUT ;
    USE SIGNAL ;
    PORT
      LAYER M4 ;
        RECT  69.036 20.4 69.12 20.424 ;
    END
  END mv[163]
  PIN mv[164]
    DIRECTION INPUT ;
    USE SIGNAL ;
    PORT
      LAYER M4 ;
        RECT  69.036 20.496 69.12 20.52 ;
    END
  END mv[164]
  PIN mv[165]
    DIRECTION INPUT ;
    USE SIGNAL ;
    PORT
      LAYER M4 ;
        RECT  69.036 20.592 69.12 20.616 ;
    END
  END mv[165]
  PIN mv[166]
    DIRECTION INPUT ;
    USE SIGNAL ;
    PORT
      LAYER M4 ;
        RECT  69.036 20.688 69.12 20.712 ;
    END
  END mv[166]
  PIN mv[167]
    DIRECTION INPUT ;
    USE SIGNAL ;
    PORT
      LAYER M4 ;
        RECT  69.036 20.784 69.12 20.808 ;
    END
  END mv[167]
  PIN mv[168]
    DIRECTION INPUT ;
    USE SIGNAL ;
    PORT
      LAYER M4 ;
        RECT  69.036 20.88 69.12 20.904 ;
    END
  END mv[168]
  PIN mv[169]
    DIRECTION INPUT ;
    USE SIGNAL ;
    PORT
      LAYER M4 ;
        RECT  69.036 20.976 69.12 21 ;
    END
  END mv[169]
  PIN mv[16]
    DIRECTION INPUT ;
    USE SIGNAL ;
    PORT
      LAYER M4 ;
        RECT  69.036 33.936 69.12 33.96 ;
    END
  END mv[16]
  PIN mv[170]
    DIRECTION INPUT ;
    USE SIGNAL ;
    PORT
      LAYER M4 ;
        RECT  69.036 21.072 69.12 21.096 ;
    END
  END mv[170]
  PIN mv[171]
    DIRECTION INPUT ;
    USE SIGNAL ;
    PORT
      LAYER M4 ;
        RECT  69.036 21.168 69.12 21.192 ;
    END
  END mv[171]
  PIN mv[172]
    DIRECTION INPUT ;
    USE SIGNAL ;
    PORT
      LAYER M4 ;
        RECT  69.036 21.264 69.12 21.288 ;
    END
  END mv[172]
  PIN mv[173]
    DIRECTION INPUT ;
    USE SIGNAL ;
    PORT
      LAYER M4 ;
        RECT  69.036 21.36 69.12 21.384 ;
    END
  END mv[173]
  PIN mv[174]
    DIRECTION INPUT ;
    USE SIGNAL ;
    PORT
      LAYER M4 ;
        RECT  69.036 21.456 69.12 21.48 ;
    END
  END mv[174]
  PIN mv[175]
    DIRECTION INPUT ;
    USE SIGNAL ;
    PORT
      LAYER M4 ;
        RECT  69.036 21.552 69.12 21.576 ;
    END
  END mv[175]
  PIN mv[176]
    DIRECTION INPUT ;
    USE SIGNAL ;
    PORT
      LAYER M4 ;
        RECT  69.036 21.648 69.12 21.672 ;
    END
  END mv[176]
  PIN mv[177]
    DIRECTION INPUT ;
    USE SIGNAL ;
    PORT
      LAYER M4 ;
        RECT  69.036 21.744 69.12 21.768 ;
    END
  END mv[177]
  PIN mv[178]
    DIRECTION INPUT ;
    USE SIGNAL ;
    PORT
      LAYER M4 ;
        RECT  69.036 21.84 69.12 21.864 ;
    END
  END mv[178]
  PIN mv[179]
    DIRECTION INPUT ;
    USE SIGNAL ;
    PORT
      LAYER M4 ;
        RECT  69.036 21.936 69.12 21.96 ;
    END
  END mv[179]
  PIN mv[17]
    DIRECTION INPUT ;
    USE SIGNAL ;
    PORT
      LAYER M4 ;
        RECT  69.036 34.032 69.12 34.056 ;
    END
  END mv[17]
  PIN mv[180]
    DIRECTION INPUT ;
    USE SIGNAL ;
    PORT
      LAYER M4 ;
        RECT  69.036 22.032 69.12 22.056 ;
    END
  END mv[180]
  PIN mv[181]
    DIRECTION INPUT ;
    USE SIGNAL ;
    PORT
      LAYER M4 ;
        RECT  69.036 22.128 69.12 22.152 ;
    END
  END mv[181]
  PIN mv[182]
    DIRECTION INPUT ;
    USE SIGNAL ;
    PORT
      LAYER M4 ;
        RECT  69.036 22.224 69.12 22.248 ;
    END
  END mv[182]
  PIN mv[183]
    DIRECTION INPUT ;
    USE SIGNAL ;
    PORT
      LAYER M4 ;
        RECT  69.036 22.32 69.12 22.344 ;
    END
  END mv[183]
  PIN mv[184]
    DIRECTION INPUT ;
    USE SIGNAL ;
    PORT
      LAYER M4 ;
        RECT  69.036 22.416 69.12 22.44 ;
    END
  END mv[184]
  PIN mv[185]
    DIRECTION INPUT ;
    USE SIGNAL ;
    PORT
      LAYER M4 ;
        RECT  69.036 22.512 69.12 22.536 ;
    END
  END mv[185]
  PIN mv[186]
    DIRECTION INPUT ;
    USE SIGNAL ;
    PORT
      LAYER M4 ;
        RECT  69.036 22.608 69.12 22.632 ;
    END
  END mv[186]
  PIN mv[187]
    DIRECTION INPUT ;
    USE SIGNAL ;
    PORT
      LAYER M4 ;
        RECT  69.036 22.704 69.12 22.728 ;
    END
  END mv[187]
  PIN mv[188]
    DIRECTION INPUT ;
    USE SIGNAL ;
    PORT
      LAYER M4 ;
        RECT  69.036 22.8 69.12 22.824 ;
    END
  END mv[188]
  PIN mv[189]
    DIRECTION INPUT ;
    USE SIGNAL ;
    PORT
      LAYER M4 ;
        RECT  69.036 22.896 69.12 22.92 ;
    END
  END mv[189]
  PIN mv[18]
    DIRECTION INPUT ;
    USE SIGNAL ;
    PORT
      LAYER M4 ;
        RECT  69.036 34.128 69.12 34.152 ;
    END
  END mv[18]
  PIN mv[190]
    DIRECTION INPUT ;
    USE SIGNAL ;
    PORT
      LAYER M4 ;
        RECT  69.036 26.064 69.12 26.088 ;
    END
  END mv[190]
  PIN mv[191]
    DIRECTION INPUT ;
    USE SIGNAL ;
    PORT
      LAYER M4 ;
        RECT  69.036 26.16 69.12 26.184 ;
    END
  END mv[191]
  PIN mv[192]
    DIRECTION INPUT ;
    USE SIGNAL ;
    PORT
      LAYER M4 ;
        RECT  69.036 26.256 69.12 26.28 ;
    END
  END mv[192]
  PIN mv[193]
    DIRECTION INPUT ;
    USE SIGNAL ;
    PORT
      LAYER M4 ;
        RECT  69.036 26.352 69.12 26.376 ;
    END
  END mv[193]
  PIN mv[194]
    DIRECTION INPUT ;
    USE SIGNAL ;
    PORT
      LAYER M4 ;
        RECT  69.036 26.448 69.12 26.472 ;
    END
  END mv[194]
  PIN mv[195]
    DIRECTION INPUT ;
    USE SIGNAL ;
    PORT
      LAYER M4 ;
        RECT  69.036 26.544 69.12 26.568 ;
    END
  END mv[195]
  PIN mv[196]
    DIRECTION INPUT ;
    USE SIGNAL ;
    PORT
      LAYER M4 ;
        RECT  69.036 26.64 69.12 26.664 ;
    END
  END mv[196]
  PIN mv[197]
    DIRECTION INPUT ;
    USE SIGNAL ;
    PORT
      LAYER M4 ;
        RECT  69.036 26.736 69.12 26.76 ;
    END
  END mv[197]
  PIN mv[198]
    DIRECTION INPUT ;
    USE SIGNAL ;
    PORT
      LAYER M4 ;
        RECT  69.036 26.832 69.12 26.856 ;
    END
  END mv[198]
  PIN mv[199]
    DIRECTION INPUT ;
    USE SIGNAL ;
    PORT
      LAYER M4 ;
        RECT  69.036 26.928 69.12 26.952 ;
    END
  END mv[199]
  PIN mv[19]
    DIRECTION INPUT ;
    USE SIGNAL ;
    PORT
      LAYER M4 ;
        RECT  69.036 34.224 69.12 34.248 ;
    END
  END mv[19]
  PIN mv[1]
    DIRECTION INPUT ;
    USE SIGNAL ;
    PORT
      LAYER M4 ;
        RECT  69.036 32.496 69.12 32.52 ;
    END
  END mv[1]
  PIN mv[200]
    DIRECTION INPUT ;
    USE SIGNAL ;
    PORT
      LAYER M4 ;
        RECT  69.036 27.024 69.12 27.048 ;
    END
  END mv[200]
  PIN mv[201]
    DIRECTION INPUT ;
    USE SIGNAL ;
    PORT
      LAYER M4 ;
        RECT  69.036 27.12 69.12 27.144 ;
    END
  END mv[201]
  PIN mv[202]
    DIRECTION INPUT ;
    USE SIGNAL ;
    PORT
      LAYER M4 ;
        RECT  69.036 27.216 69.12 27.24 ;
    END
  END mv[202]
  PIN mv[203]
    DIRECTION INPUT ;
    USE SIGNAL ;
    PORT
      LAYER M4 ;
        RECT  69.036 27.312 69.12 27.336 ;
    END
  END mv[203]
  PIN mv[204]
    DIRECTION INPUT ;
    USE SIGNAL ;
    PORT
      LAYER M4 ;
        RECT  69.036 27.408 69.12 27.432 ;
    END
  END mv[204]
  PIN mv[205]
    DIRECTION INPUT ;
    USE SIGNAL ;
    PORT
      LAYER M4 ;
        RECT  69.036 27.504 69.12 27.528 ;
    END
  END mv[205]
  PIN mv[206]
    DIRECTION INPUT ;
    USE SIGNAL ;
    PORT
      LAYER M4 ;
        RECT  69.036 27.6 69.12 27.624 ;
    END
  END mv[206]
  PIN mv[207]
    DIRECTION INPUT ;
    USE SIGNAL ;
    PORT
      LAYER M4 ;
        RECT  69.036 27.696 69.12 27.72 ;
    END
  END mv[207]
  PIN mv[208]
    DIRECTION INPUT ;
    USE SIGNAL ;
    PORT
      LAYER M4 ;
        RECT  69.036 27.792 69.12 27.816 ;
    END
  END mv[208]
  PIN mv[209]
    DIRECTION INPUT ;
    USE SIGNAL ;
    PORT
      LAYER M4 ;
        RECT  69.036 27.888 69.12 27.912 ;
    END
  END mv[209]
  PIN mv[20]
    DIRECTION INPUT ;
    USE SIGNAL ;
    PORT
      LAYER M4 ;
        RECT  69.036 34.32 69.12 34.344 ;
    END
  END mv[20]
  PIN mv[210]
    DIRECTION INPUT ;
    USE SIGNAL ;
    PORT
      LAYER M4 ;
        RECT  69.036 27.984 69.12 28.008 ;
    END
  END mv[210]
  PIN mv[211]
    DIRECTION INPUT ;
    USE SIGNAL ;
    PORT
      LAYER M4 ;
        RECT  69.036 28.08 69.12 28.104 ;
    END
  END mv[211]
  PIN mv[212]
    DIRECTION INPUT ;
    USE SIGNAL ;
    PORT
      LAYER M4 ;
        RECT  69.036 28.176 69.12 28.2 ;
    END
  END mv[212]
  PIN mv[213]
    DIRECTION INPUT ;
    USE SIGNAL ;
    PORT
      LAYER M4 ;
        RECT  69.036 28.272 69.12 28.296 ;
    END
  END mv[213]
  PIN mv[214]
    DIRECTION INPUT ;
    USE SIGNAL ;
    PORT
      LAYER M4 ;
        RECT  69.036 28.368 69.12 28.392 ;
    END
  END mv[214]
  PIN mv[215]
    DIRECTION INPUT ;
    USE SIGNAL ;
    PORT
      LAYER M4 ;
        RECT  69.036 28.464 69.12 28.488 ;
    END
  END mv[215]
  PIN mv[216]
    DIRECTION INPUT ;
    USE SIGNAL ;
    PORT
      LAYER M4 ;
        RECT  69.036 28.56 69.12 28.584 ;
    END
  END mv[216]
  PIN mv[217]
    DIRECTION INPUT ;
    USE SIGNAL ;
    PORT
      LAYER M4 ;
        RECT  69.036 28.656 69.12 28.68 ;
    END
  END mv[217]
  PIN mv[218]
    DIRECTION INPUT ;
    USE SIGNAL ;
    PORT
      LAYER M4 ;
        RECT  69.036 28.752 69.12 28.776 ;
    END
  END mv[218]
  PIN mv[219]
    DIRECTION INPUT ;
    USE SIGNAL ;
    PORT
      LAYER M4 ;
        RECT  69.036 28.848 69.12 28.872 ;
    END
  END mv[219]
  PIN mv[21]
    DIRECTION INPUT ;
    USE SIGNAL ;
    PORT
      LAYER M4 ;
        RECT  69.036 34.416 69.12 34.44 ;
    END
  END mv[21]
  PIN mv[220]
    DIRECTION INPUT ;
    USE SIGNAL ;
    PORT
      LAYER M4 ;
        RECT  69.036 28.944 69.12 28.968 ;
    END
  END mv[220]
  PIN mv[221]
    DIRECTION INPUT ;
    USE SIGNAL ;
    PORT
      LAYER M4 ;
        RECT  69.036 29.04 69.12 29.064 ;
    END
  END mv[221]
  PIN mv[222]
    DIRECTION INPUT ;
    USE SIGNAL ;
    PORT
      LAYER M4 ;
        RECT  69.036 61.392 69.12 61.416 ;
    END
  END mv[222]
  PIN mv[223]
    DIRECTION INPUT ;
    USE SIGNAL ;
    PORT
      LAYER M4 ;
        RECT  69.036 61.488 69.12 61.512 ;
    END
  END mv[223]
  PIN mv[224]
    DIRECTION INPUT ;
    USE SIGNAL ;
    PORT
      LAYER M4 ;
        RECT  69.036 61.584 69.12 61.608 ;
    END
  END mv[224]
  PIN mv[225]
    DIRECTION INPUT ;
    USE SIGNAL ;
    PORT
      LAYER M4 ;
        RECT  69.036 61.68 69.12 61.704 ;
    END
  END mv[225]
  PIN mv[226]
    DIRECTION INPUT ;
    USE SIGNAL ;
    PORT
      LAYER M4 ;
        RECT  69.036 61.776 69.12 61.8 ;
    END
  END mv[226]
  PIN mv[22]
    DIRECTION INPUT ;
    USE SIGNAL ;
    PORT
      LAYER M4 ;
        RECT  69.036 34.512 69.12 34.536 ;
    END
  END mv[22]
  PIN mv[23]
    DIRECTION INPUT ;
    USE SIGNAL ;
    PORT
      LAYER M4 ;
        RECT  69.036 34.608 69.12 34.632 ;
    END
  END mv[23]
  PIN mv[24]
    DIRECTION INPUT ;
    USE SIGNAL ;
    PORT
      LAYER M4 ;
        RECT  69.036 34.704 69.12 34.728 ;
    END
  END mv[24]
  PIN mv[25]
    DIRECTION INPUT ;
    USE SIGNAL ;
    PORT
      LAYER M4 ;
        RECT  69.036 34.8 69.12 34.824 ;
    END
  END mv[25]
  PIN mv[26]
    DIRECTION INPUT ;
    USE SIGNAL ;
    PORT
      LAYER M4 ;
        RECT  69.036 34.896 69.12 34.92 ;
    END
  END mv[26]
  PIN mv[27]
    DIRECTION INPUT ;
    USE SIGNAL ;
    PORT
      LAYER M4 ;
        RECT  69.036 34.992 69.12 35.016 ;
    END
  END mv[27]
  PIN mv[28]
    DIRECTION INPUT ;
    USE SIGNAL ;
    PORT
      LAYER M4 ;
        RECT  69.036 35.088 69.12 35.112 ;
    END
  END mv[28]
  PIN mv[29]
    DIRECTION INPUT ;
    USE SIGNAL ;
    PORT
      LAYER M4 ;
        RECT  69.036 35.184 69.12 35.208 ;
    END
  END mv[29]
  PIN mv[2]
    DIRECTION INPUT ;
    USE SIGNAL ;
    PORT
      LAYER M4 ;
        RECT  69.036 32.592 69.12 32.616 ;
    END
  END mv[2]
  PIN mv[30]
    DIRECTION INPUT ;
    USE SIGNAL ;
    PORT
      LAYER M4 ;
        RECT  69.036 9.936 69.12 9.96 ;
    END
  END mv[30]
  PIN mv[31]
    DIRECTION INPUT ;
    USE SIGNAL ;
    PORT
      LAYER M4 ;
        RECT  69.036 10.032 69.12 10.056 ;
    END
  END mv[31]
  PIN mv[32]
    DIRECTION INPUT ;
    USE SIGNAL ;
    PORT
      LAYER M4 ;
        RECT  69.036 10.128 69.12 10.152 ;
    END
  END mv[32]
  PIN mv[33]
    DIRECTION INPUT ;
    USE SIGNAL ;
    PORT
      LAYER M4 ;
        RECT  69.036 10.224 69.12 10.248 ;
    END
  END mv[33]
  PIN mv[34]
    DIRECTION INPUT ;
    USE SIGNAL ;
    PORT
      LAYER M4 ;
        RECT  69.036 10.32 69.12 10.344 ;
    END
  END mv[34]
  PIN mv[35]
    DIRECTION INPUT ;
    USE SIGNAL ;
    PORT
      LAYER M4 ;
        RECT  69.036 10.416 69.12 10.44 ;
    END
  END mv[35]
  PIN mv[36]
    DIRECTION INPUT ;
    USE SIGNAL ;
    PORT
      LAYER M4 ;
        RECT  69.036 10.512 69.12 10.536 ;
    END
  END mv[36]
  PIN mv[37]
    DIRECTION INPUT ;
    USE SIGNAL ;
    PORT
      LAYER M4 ;
        RECT  69.036 10.608 69.12 10.632 ;
    END
  END mv[37]
  PIN mv[38]
    DIRECTION INPUT ;
    USE SIGNAL ;
    PORT
      LAYER M4 ;
        RECT  69.036 10.704 69.12 10.728 ;
    END
  END mv[38]
  PIN mv[39]
    DIRECTION INPUT ;
    USE SIGNAL ;
    PORT
      LAYER M4 ;
        RECT  69.036 10.8 69.12 10.824 ;
    END
  END mv[39]
  PIN mv[3]
    DIRECTION INPUT ;
    USE SIGNAL ;
    PORT
      LAYER M4 ;
        RECT  69.036 32.688 69.12 32.712 ;
    END
  END mv[3]
  PIN mv[40]
    DIRECTION INPUT ;
    USE SIGNAL ;
    PORT
      LAYER M4 ;
        RECT  69.036 10.896 69.12 10.92 ;
    END
  END mv[40]
  PIN mv[41]
    DIRECTION INPUT ;
    USE SIGNAL ;
    PORT
      LAYER M4 ;
        RECT  69.036 10.992 69.12 11.016 ;
    END
  END mv[41]
  PIN mv[42]
    DIRECTION INPUT ;
    USE SIGNAL ;
    PORT
      LAYER M4 ;
        RECT  69.036 11.088 69.12 11.112 ;
    END
  END mv[42]
  PIN mv[43]
    DIRECTION INPUT ;
    USE SIGNAL ;
    PORT
      LAYER M4 ;
        RECT  69.036 11.184 69.12 11.208 ;
    END
  END mv[43]
  PIN mv[44]
    DIRECTION INPUT ;
    USE SIGNAL ;
    PORT
      LAYER M4 ;
        RECT  69.036 11.28 69.12 11.304 ;
    END
  END mv[44]
  PIN mv[45]
    DIRECTION INPUT ;
    USE SIGNAL ;
    PORT
      LAYER M4 ;
        RECT  69.036 11.376 69.12 11.4 ;
    END
  END mv[45]
  PIN mv[46]
    DIRECTION INPUT ;
    USE SIGNAL ;
    PORT
      LAYER M4 ;
        RECT  69.036 11.472 69.12 11.496 ;
    END
  END mv[46]
  PIN mv[47]
    DIRECTION INPUT ;
    USE SIGNAL ;
    PORT
      LAYER M4 ;
        RECT  69.036 11.568 69.12 11.592 ;
    END
  END mv[47]
  PIN mv[48]
    DIRECTION INPUT ;
    USE SIGNAL ;
    PORT
      LAYER M4 ;
        RECT  69.036 11.664 69.12 11.688 ;
    END
  END mv[48]
  PIN mv[49]
    DIRECTION INPUT ;
    USE SIGNAL ;
    PORT
      LAYER M4 ;
        RECT  69.036 11.76 69.12 11.784 ;
    END
  END mv[49]
  PIN mv[4]
    DIRECTION INPUT ;
    USE SIGNAL ;
    PORT
      LAYER M4 ;
        RECT  69.036 32.784 69.12 32.808 ;
    END
  END mv[4]
  PIN mv[50]
    DIRECTION INPUT ;
    USE SIGNAL ;
    PORT
      LAYER M4 ;
        RECT  69.036 11.856 69.12 11.88 ;
    END
  END mv[50]
  PIN mv[51]
    DIRECTION INPUT ;
    USE SIGNAL ;
    PORT
      LAYER M4 ;
        RECT  69.036 11.952 69.12 11.976 ;
    END
  END mv[51]
  PIN mv[52]
    DIRECTION INPUT ;
    USE SIGNAL ;
    PORT
      LAYER M4 ;
        RECT  69.036 12.048 69.12 12.072 ;
    END
  END mv[52]
  PIN mv[53]
    DIRECTION INPUT ;
    USE SIGNAL ;
    PORT
      LAYER M4 ;
        RECT  69.036 12.144 69.12 12.168 ;
    END
  END mv[53]
  PIN mv[54]
    DIRECTION INPUT ;
    USE SIGNAL ;
    PORT
      LAYER M4 ;
        RECT  69.036 12.24 69.12 12.264 ;
    END
  END mv[54]
  PIN mv[55]
    DIRECTION INPUT ;
    USE SIGNAL ;
    PORT
      LAYER M4 ;
        RECT  69.036 12.336 69.12 12.36 ;
    END
  END mv[55]
  PIN mv[56]
    DIRECTION INPUT ;
    USE SIGNAL ;
    PORT
      LAYER M4 ;
        RECT  69.036 12.432 69.12 12.456 ;
    END
  END mv[56]
  PIN mv[57]
    DIRECTION INPUT ;
    USE SIGNAL ;
    PORT
      LAYER M4 ;
        RECT  69.036 12.528 69.12 12.552 ;
    END
  END mv[57]
  PIN mv[58]
    DIRECTION INPUT ;
    USE SIGNAL ;
    PORT
      LAYER M4 ;
        RECT  69.036 12.624 69.12 12.648 ;
    END
  END mv[58]
  PIN mv[59]
    DIRECTION INPUT ;
    USE SIGNAL ;
    PORT
      LAYER M4 ;
        RECT  69.036 12.72 69.12 12.744 ;
    END
  END mv[59]
  PIN mv[5]
    DIRECTION INPUT ;
    USE SIGNAL ;
    PORT
      LAYER M4 ;
        RECT  69.036 32.88 69.12 32.904 ;
    END
  END mv[5]
  PIN mv[60]
    DIRECTION INPUT ;
    USE SIGNAL ;
    PORT
      LAYER M4 ;
        RECT  69.036 12.816 69.12 12.84 ;
    END
  END mv[60]
  PIN mv[61]
    DIRECTION INPUT ;
    USE SIGNAL ;
    PORT
      LAYER M4 ;
        RECT  69.036 12.912 69.12 12.936 ;
    END
  END mv[61]
  PIN mv[62]
    DIRECTION INPUT ;
    USE SIGNAL ;
    PORT
      LAYER M4 ;
        RECT  69.036 22.992 69.12 23.016 ;
    END
  END mv[62]
  PIN mv[63]
    DIRECTION INPUT ;
    USE SIGNAL ;
    PORT
      LAYER M4 ;
        RECT  69.036 23.088 69.12 23.112 ;
    END
  END mv[63]
  PIN mv[64]
    DIRECTION INPUT ;
    USE SIGNAL ;
    PORT
      LAYER M4 ;
        RECT  69.036 23.184 69.12 23.208 ;
    END
  END mv[64]
  PIN mv[65]
    DIRECTION INPUT ;
    USE SIGNAL ;
    PORT
      LAYER M4 ;
        RECT  69.036 23.28 69.12 23.304 ;
    END
  END mv[65]
  PIN mv[66]
    DIRECTION INPUT ;
    USE SIGNAL ;
    PORT
      LAYER M4 ;
        RECT  69.036 23.376 69.12 23.4 ;
    END
  END mv[66]
  PIN mv[67]
    DIRECTION INPUT ;
    USE SIGNAL ;
    PORT
      LAYER M4 ;
        RECT  69.036 23.472 69.12 23.496 ;
    END
  END mv[67]
  PIN mv[68]
    DIRECTION INPUT ;
    USE SIGNAL ;
    PORT
      LAYER M4 ;
        RECT  69.036 23.568 69.12 23.592 ;
    END
  END mv[68]
  PIN mv[69]
    DIRECTION INPUT ;
    USE SIGNAL ;
    PORT
      LAYER M4 ;
        RECT  69.036 23.664 69.12 23.688 ;
    END
  END mv[69]
  PIN mv[6]
    DIRECTION INPUT ;
    USE SIGNAL ;
    PORT
      LAYER M4 ;
        RECT  69.036 32.976 69.12 33 ;
    END
  END mv[6]
  PIN mv[70]
    DIRECTION INPUT ;
    USE SIGNAL ;
    PORT
      LAYER M4 ;
        RECT  69.036 23.76 69.12 23.784 ;
    END
  END mv[70]
  PIN mv[71]
    DIRECTION INPUT ;
    USE SIGNAL ;
    PORT
      LAYER M4 ;
        RECT  69.036 23.856 69.12 23.88 ;
    END
  END mv[71]
  PIN mv[72]
    DIRECTION INPUT ;
    USE SIGNAL ;
    PORT
      LAYER M4 ;
        RECT  69.036 23.952 69.12 23.976 ;
    END
  END mv[72]
  PIN mv[73]
    DIRECTION INPUT ;
    USE SIGNAL ;
    PORT
      LAYER M4 ;
        RECT  69.036 24.048 69.12 24.072 ;
    END
  END mv[73]
  PIN mv[74]
    DIRECTION INPUT ;
    USE SIGNAL ;
    PORT
      LAYER M4 ;
        RECT  69.036 24.144 69.12 24.168 ;
    END
  END mv[74]
  PIN mv[75]
    DIRECTION INPUT ;
    USE SIGNAL ;
    PORT
      LAYER M4 ;
        RECT  69.036 24.24 69.12 24.264 ;
    END
  END mv[75]
  PIN mv[76]
    DIRECTION INPUT ;
    USE SIGNAL ;
    PORT
      LAYER M4 ;
        RECT  69.036 24.336 69.12 24.36 ;
    END
  END mv[76]
  PIN mv[77]
    DIRECTION INPUT ;
    USE SIGNAL ;
    PORT
      LAYER M4 ;
        RECT  69.036 24.432 69.12 24.456 ;
    END
  END mv[77]
  PIN mv[78]
    DIRECTION INPUT ;
    USE SIGNAL ;
    PORT
      LAYER M4 ;
        RECT  69.036 24.528 69.12 24.552 ;
    END
  END mv[78]
  PIN mv[79]
    DIRECTION INPUT ;
    USE SIGNAL ;
    PORT
      LAYER M4 ;
        RECT  69.036 24.624 69.12 24.648 ;
    END
  END mv[79]
  PIN mv[7]
    DIRECTION INPUT ;
    USE SIGNAL ;
    PORT
      LAYER M4 ;
        RECT  69.036 33.072 69.12 33.096 ;
    END
  END mv[7]
  PIN mv[80]
    DIRECTION INPUT ;
    USE SIGNAL ;
    PORT
      LAYER M4 ;
        RECT  69.036 24.72 69.12 24.744 ;
    END
  END mv[80]
  PIN mv[81]
    DIRECTION INPUT ;
    USE SIGNAL ;
    PORT
      LAYER M4 ;
        RECT  69.036 24.816 69.12 24.84 ;
    END
  END mv[81]
  PIN mv[82]
    DIRECTION INPUT ;
    USE SIGNAL ;
    PORT
      LAYER M4 ;
        RECT  69.036 24.912 69.12 24.936 ;
    END
  END mv[82]
  PIN mv[83]
    DIRECTION INPUT ;
    USE SIGNAL ;
    PORT
      LAYER M4 ;
        RECT  69.036 25.008 69.12 25.032 ;
    END
  END mv[83]
  PIN mv[84]
    DIRECTION INPUT ;
    USE SIGNAL ;
    PORT
      LAYER M4 ;
        RECT  69.036 25.104 69.12 25.128 ;
    END
  END mv[84]
  PIN mv[85]
    DIRECTION INPUT ;
    USE SIGNAL ;
    PORT
      LAYER M4 ;
        RECT  69.036 25.2 69.12 25.224 ;
    END
  END mv[85]
  PIN mv[86]
    DIRECTION INPUT ;
    USE SIGNAL ;
    PORT
      LAYER M4 ;
        RECT  69.036 25.296 69.12 25.32 ;
    END
  END mv[86]
  PIN mv[87]
    DIRECTION INPUT ;
    USE SIGNAL ;
    PORT
      LAYER M4 ;
        RECT  69.036 25.392 69.12 25.416 ;
    END
  END mv[87]
  PIN mv[88]
    DIRECTION INPUT ;
    USE SIGNAL ;
    PORT
      LAYER M4 ;
        RECT  69.036 25.488 69.12 25.512 ;
    END
  END mv[88]
  PIN mv[89]
    DIRECTION INPUT ;
    USE SIGNAL ;
    PORT
      LAYER M4 ;
        RECT  69.036 25.584 69.12 25.608 ;
    END
  END mv[89]
  PIN mv[8]
    DIRECTION INPUT ;
    USE SIGNAL ;
    PORT
      LAYER M4 ;
        RECT  69.036 33.168 69.12 33.192 ;
    END
  END mv[8]
  PIN mv[90]
    DIRECTION INPUT ;
    USE SIGNAL ;
    PORT
      LAYER M4 ;
        RECT  69.036 25.68 69.12 25.704 ;
    END
  END mv[90]
  PIN mv[91]
    DIRECTION INPUT ;
    USE SIGNAL ;
    PORT
      LAYER M4 ;
        RECT  69.036 25.776 69.12 25.8 ;
    END
  END mv[91]
  PIN mv[92]
    DIRECTION INPUT ;
    USE SIGNAL ;
    PORT
      LAYER M4 ;
        RECT  69.036 25.872 69.12 25.896 ;
    END
  END mv[92]
  PIN mv[93]
    DIRECTION INPUT ;
    USE SIGNAL ;
    PORT
      LAYER M4 ;
        RECT  69.036 25.968 69.12 25.992 ;
    END
  END mv[93]
  PIN mv[94]
    DIRECTION INPUT ;
    USE SIGNAL ;
    PORT
      LAYER M4 ;
        RECT  69.036 16.08 69.12 16.104 ;
    END
  END mv[94]
  PIN mv[95]
    DIRECTION INPUT ;
    USE SIGNAL ;
    PORT
      LAYER M4 ;
        RECT  69.036 16.176 69.12 16.2 ;
    END
  END mv[95]
  PIN mv[96]
    DIRECTION INPUT ;
    USE SIGNAL ;
    PORT
      LAYER M4 ;
        RECT  69.036 16.272 69.12 16.296 ;
    END
  END mv[96]
  PIN mv[97]
    DIRECTION INPUT ;
    USE SIGNAL ;
    PORT
      LAYER M4 ;
        RECT  69.036 16.368 69.12 16.392 ;
    END
  END mv[97]
  PIN mv[98]
    DIRECTION INPUT ;
    USE SIGNAL ;
    PORT
      LAYER M4 ;
        RECT  69.036 16.464 69.12 16.488 ;
    END
  END mv[98]
  PIN mv[99]
    DIRECTION INPUT ;
    USE SIGNAL ;
    PORT
      LAYER M4 ;
        RECT  69.036 16.56 69.12 16.584 ;
    END
  END mv[99]
  PIN mv[9]
    DIRECTION INPUT ;
    USE SIGNAL ;
    PORT
      LAYER M4 ;
        RECT  69.036 33.264 69.12 33.288 ;
    END
  END mv[9]
  PIN mv_done
    DIRECTION OUTPUT ;
    USE SIGNAL ;
    PORT
      LAYER M4 ;
        RECT  69.036 61.872 69.12 61.896 ;
    END
  END mv_done
  PIN mv_fault
    DIRECTION OUTPUT ;
    USE SIGNAL ;
    PORT
      LAYER M4 ;
        RECT  69.036 61.968 69.12 61.992 ;
    END
  END mv_fault
  PIN mv_src
    DIRECTION OUTPUT ;
    USE SIGNAL ;
    PORT
      LAYER M4 ;
        RECT  69.036 62.064 69.12 62.088 ;
    END
  END mv_src
  PIN mv_v
    DIRECTION INPUT ;
    USE SIGNAL ;
    PORT
      LAYER M4 ;
        RECT  69.036 62.16 69.12 62.184 ;
    END
  END mv_v
  PIN mv_wb_bank
    DIRECTION INPUT ;
    USE SIGNAL ;
    PORT
      LAYER M4 ;
        RECT  69.036 62.256 69.12 62.28 ;
    END
  END mv_wb_bank
  PIN mv_wb_epoch[0]
    DIRECTION INPUT ;
    USE SIGNAL ;
    PORT
      LAYER M4 ;
        RECT  69.036 62.352 69.12 62.376 ;
    END
  END mv_wb_epoch[0]
  PIN mv_wb_epoch[10]
    DIRECTION INPUT ;
    USE SIGNAL ;
    PORT
      LAYER M4 ;
        RECT  69.036 63.312 69.12 63.336 ;
    END
  END mv_wb_epoch[10]
  PIN mv_wb_epoch[11]
    DIRECTION INPUT ;
    USE SIGNAL ;
    PORT
      LAYER M4 ;
        RECT  69.036 63.408 69.12 63.432 ;
    END
  END mv_wb_epoch[11]
  PIN mv_wb_epoch[12]
    DIRECTION INPUT ;
    USE SIGNAL ;
    PORT
      LAYER M4 ;
        RECT  69.036 63.504 69.12 63.528 ;
    END
  END mv_wb_epoch[12]
  PIN mv_wb_epoch[13]
    DIRECTION INPUT ;
    USE SIGNAL ;
    PORT
      LAYER M4 ;
        RECT  69.036 63.6 69.12 63.624 ;
    END
  END mv_wb_epoch[13]
  PIN mv_wb_epoch[14]
    DIRECTION INPUT ;
    USE SIGNAL ;
    PORT
      LAYER M4 ;
        RECT  69.036 63.696 69.12 63.72 ;
    END
  END mv_wb_epoch[14]
  PIN mv_wb_epoch[15]
    DIRECTION INPUT ;
    USE SIGNAL ;
    PORT
      LAYER M4 ;
        RECT  69.036 63.792 69.12 63.816 ;
    END
  END mv_wb_epoch[15]
  PIN mv_wb_epoch[1]
    DIRECTION INPUT ;
    USE SIGNAL ;
    PORT
      LAYER M4 ;
        RECT  69.036 62.448 69.12 62.472 ;
    END
  END mv_wb_epoch[1]
  PIN mv_wb_epoch[2]
    DIRECTION INPUT ;
    USE SIGNAL ;
    PORT
      LAYER M4 ;
        RECT  69.036 62.544 69.12 62.568 ;
    END
  END mv_wb_epoch[2]
  PIN mv_wb_epoch[3]
    DIRECTION INPUT ;
    USE SIGNAL ;
    PORT
      LAYER M4 ;
        RECT  69.036 62.64 69.12 62.664 ;
    END
  END mv_wb_epoch[3]
  PIN mv_wb_epoch[4]
    DIRECTION INPUT ;
    USE SIGNAL ;
    PORT
      LAYER M4 ;
        RECT  69.036 62.736 69.12 62.76 ;
    END
  END mv_wb_epoch[4]
  PIN mv_wb_epoch[5]
    DIRECTION INPUT ;
    USE SIGNAL ;
    PORT
      LAYER M4 ;
        RECT  69.036 62.832 69.12 62.856 ;
    END
  END mv_wb_epoch[5]
  PIN mv_wb_epoch[6]
    DIRECTION INPUT ;
    USE SIGNAL ;
    PORT
      LAYER M4 ;
        RECT  69.036 62.928 69.12 62.952 ;
    END
  END mv_wb_epoch[6]
  PIN mv_wb_epoch[7]
    DIRECTION INPUT ;
    USE SIGNAL ;
    PORT
      LAYER M4 ;
        RECT  69.036 63.024 69.12 63.048 ;
    END
  END mv_wb_epoch[7]
  PIN mv_wb_epoch[8]
    DIRECTION INPUT ;
    USE SIGNAL ;
    PORT
      LAYER M4 ;
        RECT  69.036 63.12 69.12 63.144 ;
    END
  END mv_wb_epoch[8]
  PIN mv_wb_epoch[9]
    DIRECTION INPUT ;
    USE SIGNAL ;
    PORT
      LAYER M4 ;
        RECT  69.036 63.216 69.12 63.24 ;
    END
  END mv_wb_epoch[9]
  PIN quiet
    DIRECTION OUTPUT ;
    USE SIGNAL ;
    PORT
      LAYER M4 ;
        RECT  69.036 63.888 69.12 63.912 ;
    END
  END quiet
  PIN rq[0]
    DIRECTION OUTPUT ;
    USE SIGNAL ;
    PORT
      LAYER M4 ;
        RECT  0 36.72 0.084 36.744 ;
    END
  END rq[0]
  PIN rq[100]
    DIRECTION OUTPUT ;
    USE SIGNAL ;
    PORT
      LAYER M4 ;
        RECT  0 11.76 0.084 11.784 ;
    END
  END rq[100]
  PIN rq[101]
    DIRECTION OUTPUT ;
    USE SIGNAL ;
    PORT
      LAYER M4 ;
        RECT  0 11.856 0.084 11.88 ;
    END
  END rq[101]
  PIN rq[102]
    DIRECTION OUTPUT ;
    USE SIGNAL ;
    PORT
      LAYER M4 ;
        RECT  0 11.952 0.084 11.976 ;
    END
  END rq[102]
  PIN rq[103]
    DIRECTION OUTPUT ;
    USE SIGNAL ;
    PORT
      LAYER M4 ;
        RECT  0 12.048 0.084 12.072 ;
    END
  END rq[103]
  PIN rq[104]
    DIRECTION OUTPUT ;
    USE SIGNAL ;
    PORT
      LAYER M4 ;
        RECT  0 12.144 0.084 12.168 ;
    END
  END rq[104]
  PIN rq[105]
    DIRECTION OUTPUT ;
    USE SIGNAL ;
    PORT
      LAYER M4 ;
        RECT  0 12.24 0.084 12.264 ;
    END
  END rq[105]
  PIN rq[106]
    DIRECTION OUTPUT ;
    USE SIGNAL ;
    PORT
      LAYER M4 ;
        RECT  0 12.336 0.084 12.36 ;
    END
  END rq[106]
  PIN rq[107]
    DIRECTION OUTPUT ;
    USE SIGNAL ;
    PORT
      LAYER M4 ;
        RECT  0 12.432 0.084 12.456 ;
    END
  END rq[107]
  PIN rq[108]
    DIRECTION OUTPUT ;
    USE SIGNAL ;
    PORT
      LAYER M4 ;
        RECT  0 12.528 0.084 12.552 ;
    END
  END rq[108]
  PIN rq[109]
    DIRECTION OUTPUT ;
    USE SIGNAL ;
    PORT
      LAYER M4 ;
        RECT  0 12.624 0.084 12.648 ;
    END
  END rq[109]
  PIN rq[10]
    DIRECTION OUTPUT ;
    USE SIGNAL ;
    PORT
      LAYER M4 ;
        RECT  0 2.352 0.084 2.376 ;
    END
  END rq[10]
  PIN rq[110]
    DIRECTION OUTPUT ;
    USE SIGNAL ;
    PORT
      LAYER M4 ;
        RECT  0 12.72 0.084 12.744 ;
    END
  END rq[110]
  PIN rq[111]
    DIRECTION OUTPUT ;
    USE SIGNAL ;
    PORT
      LAYER M4 ;
        RECT  0 12.816 0.084 12.84 ;
    END
  END rq[111]
  PIN rq[112]
    DIRECTION OUTPUT ;
    USE SIGNAL ;
    PORT
      LAYER M4 ;
        RECT  0 12.912 0.084 12.936 ;
    END
  END rq[112]
  PIN rq[113]
    DIRECTION OUTPUT ;
    USE SIGNAL ;
    PORT
      LAYER M4 ;
        RECT  0 13.008 0.084 13.032 ;
    END
  END rq[113]
  PIN rq[114]
    DIRECTION OUTPUT ;
    USE SIGNAL ;
    PORT
      LAYER M4 ;
        RECT  0 13.104 0.084 13.128 ;
    END
  END rq[114]
  PIN rq[115]
    DIRECTION OUTPUT ;
    USE SIGNAL ;
    PORT
      LAYER M4 ;
        RECT  0 13.2 0.084 13.224 ;
    END
  END rq[115]
  PIN rq[116]
    DIRECTION OUTPUT ;
    USE SIGNAL ;
    PORT
      LAYER M4 ;
        RECT  0 13.296 0.084 13.32 ;
    END
  END rq[116]
  PIN rq[117]
    DIRECTION OUTPUT ;
    USE SIGNAL ;
    PORT
      LAYER M4 ;
        RECT  0 13.392 0.084 13.416 ;
    END
  END rq[117]
  PIN rq[118]
    DIRECTION OUTPUT ;
    USE SIGNAL ;
    PORT
      LAYER M4 ;
        RECT  0 13.488 0.084 13.512 ;
    END
  END rq[118]
  PIN rq[119]
    DIRECTION OUTPUT ;
    USE SIGNAL ;
    PORT
      LAYER M4 ;
        RECT  0 13.584 0.084 13.608 ;
    END
  END rq[119]
  PIN rq[11]
    DIRECTION OUTPUT ;
    USE SIGNAL ;
    PORT
      LAYER M4 ;
        RECT  0 2.448 0.084 2.472 ;
    END
  END rq[11]
  PIN rq[120]
    DIRECTION OUTPUT ;
    USE SIGNAL ;
    PORT
      LAYER M4 ;
        RECT  0 13.68 0.084 13.704 ;
    END
  END rq[120]
  PIN rq[121]
    DIRECTION OUTPUT ;
    USE SIGNAL ;
    PORT
      LAYER M4 ;
        RECT  0 13.776 0.084 13.8 ;
    END
  END rq[121]
  PIN rq[122]
    DIRECTION OUTPUT ;
    USE SIGNAL ;
    PORT
      LAYER M4 ;
        RECT  0 13.872 0.084 13.896 ;
    END
  END rq[122]
  PIN rq[123]
    DIRECTION OUTPUT ;
    USE SIGNAL ;
    PORT
      LAYER M4 ;
        RECT  0 13.968 0.084 13.992 ;
    END
  END rq[123]
  PIN rq[124]
    DIRECTION OUTPUT ;
    USE SIGNAL ;
    PORT
      LAYER M4 ;
        RECT  0 14.064 0.084 14.088 ;
    END
  END rq[124]
  PIN rq[125]
    DIRECTION OUTPUT ;
    USE SIGNAL ;
    PORT
      LAYER M4 ;
        RECT  0 14.16 0.084 14.184 ;
    END
  END rq[125]
  PIN rq[126]
    DIRECTION OUTPUT ;
    USE SIGNAL ;
    PORT
      LAYER M4 ;
        RECT  0 14.256 0.084 14.28 ;
    END
  END rq[126]
  PIN rq[127]
    DIRECTION OUTPUT ;
    USE SIGNAL ;
    PORT
      LAYER M4 ;
        RECT  0 14.352 0.084 14.376 ;
    END
  END rq[127]
  PIN rq[128]
    DIRECTION OUTPUT ;
    USE SIGNAL ;
    PORT
      LAYER M4 ;
        RECT  0 14.448 0.084 14.472 ;
    END
  END rq[128]
  PIN rq[129]
    DIRECTION OUTPUT ;
    USE SIGNAL ;
    PORT
      LAYER M4 ;
        RECT  0 14.544 0.084 14.568 ;
    END
  END rq[129]
  PIN rq[12]
    DIRECTION OUTPUT ;
    USE SIGNAL ;
    PORT
      LAYER M4 ;
        RECT  0 2.544 0.084 2.568 ;
    END
  END rq[12]
  PIN rq[130]
    DIRECTION OUTPUT ;
    USE SIGNAL ;
    PORT
      LAYER M4 ;
        RECT  0 38.64 0.084 38.664 ;
    END
  END rq[130]
  PIN rq[131]
    DIRECTION OUTPUT ;
    USE SIGNAL ;
    PORT
      LAYER M4 ;
        RECT  0 38.736 0.084 38.76 ;
    END
  END rq[131]
  PIN rq[132]
    DIRECTION OUTPUT ;
    USE SIGNAL ;
    PORT
      LAYER M4 ;
        RECT  0 38.832 0.084 38.856 ;
    END
  END rq[132]
  PIN rq[133]
    DIRECTION OUTPUT ;
    USE SIGNAL ;
    PORT
      LAYER M4 ;
        RECT  0 38.928 0.084 38.952 ;
    END
  END rq[133]
  PIN rq[134]
    DIRECTION OUTPUT ;
    USE SIGNAL ;
    PORT
      LAYER M4 ;
        RECT  0 39.024 0.084 39.048 ;
    END
  END rq[134]
  PIN rq[135]
    DIRECTION OUTPUT ;
    USE SIGNAL ;
    PORT
      LAYER M4 ;
        RECT  0 39.12 0.084 39.144 ;
    END
  END rq[135]
  PIN rq[13]
    DIRECTION OUTPUT ;
    USE SIGNAL ;
    PORT
      LAYER M4 ;
        RECT  0 2.64 0.084 2.664 ;
    END
  END rq[13]
  PIN rq[14]
    DIRECTION OUTPUT ;
    USE SIGNAL ;
    PORT
      LAYER M4 ;
        RECT  0 2.736 0.084 2.76 ;
    END
  END rq[14]
  PIN rq[15]
    DIRECTION OUTPUT ;
    USE SIGNAL ;
    PORT
      LAYER M4 ;
        RECT  0 2.832 0.084 2.856 ;
    END
  END rq[15]
  PIN rq[16]
    DIRECTION OUTPUT ;
    USE SIGNAL ;
    PORT
      LAYER M4 ;
        RECT  0 2.928 0.084 2.952 ;
    END
  END rq[16]
  PIN rq[17]
    DIRECTION OUTPUT ;
    USE SIGNAL ;
    PORT
      LAYER M4 ;
        RECT  0 3.024 0.084 3.048 ;
    END
  END rq[17]
  PIN rq[18]
    DIRECTION OUTPUT ;
    USE SIGNAL ;
    PORT
      LAYER M4 ;
        RECT  0 3.12 0.084 3.144 ;
    END
  END rq[18]
  PIN rq[19]
    DIRECTION OUTPUT ;
    USE SIGNAL ;
    PORT
      LAYER M4 ;
        RECT  0 3.216 0.084 3.24 ;
    END
  END rq[19]
  PIN rq[1]
    DIRECTION OUTPUT ;
    USE SIGNAL ;
    PORT
      LAYER M4 ;
        RECT  0 36.816 0.084 36.84 ;
    END
  END rq[1]
  PIN rq[20]
    DIRECTION OUTPUT ;
    USE SIGNAL ;
    PORT
      LAYER M4 ;
        RECT  0 3.312 0.084 3.336 ;
    END
  END rq[20]
  PIN rq[21]
    DIRECTION OUTPUT ;
    USE SIGNAL ;
    PORT
      LAYER M4 ;
        RECT  0 3.408 0.084 3.432 ;
    END
  END rq[21]
  PIN rq[22]
    DIRECTION OUTPUT ;
    USE SIGNAL ;
    PORT
      LAYER M4 ;
        RECT  0 3.504 0.084 3.528 ;
    END
  END rq[22]
  PIN rq[23]
    DIRECTION OUTPUT ;
    USE SIGNAL ;
    PORT
      LAYER M4 ;
        RECT  0 3.6 0.084 3.624 ;
    END
  END rq[23]
  PIN rq[24]
    DIRECTION OUTPUT ;
    USE SIGNAL ;
    PORT
      LAYER M4 ;
        RECT  0 3.696 0.084 3.72 ;
    END
  END rq[24]
  PIN rq[25]
    DIRECTION OUTPUT ;
    USE SIGNAL ;
    PORT
      LAYER M4 ;
        RECT  0 3.792 0.084 3.816 ;
    END
  END rq[25]
  PIN rq[26]
    DIRECTION OUTPUT ;
    USE SIGNAL ;
    PORT
      LAYER M4 ;
        RECT  0 3.888 0.084 3.912 ;
    END
  END rq[26]
  PIN rq[27]
    DIRECTION OUTPUT ;
    USE SIGNAL ;
    PORT
      LAYER M4 ;
        RECT  0 3.984 0.084 4.008 ;
    END
  END rq[27]
  PIN rq[28]
    DIRECTION OUTPUT ;
    USE SIGNAL ;
    PORT
      LAYER M4 ;
        RECT  0 4.08 0.084 4.104 ;
    END
  END rq[28]
  PIN rq[29]
    DIRECTION OUTPUT ;
    USE SIGNAL ;
    PORT
      LAYER M4 ;
        RECT  0 4.176 0.084 4.2 ;
    END
  END rq[29]
  PIN rq[2]
    DIRECTION OUTPUT ;
    USE SIGNAL ;
    PORT
      LAYER M4 ;
        RECT  0 1.584 0.084 1.608 ;
    END
  END rq[2]
  PIN rq[30]
    DIRECTION OUTPUT ;
    USE SIGNAL ;
    PORT
      LAYER M4 ;
        RECT  0 4.272 0.084 4.296 ;
    END
  END rq[30]
  PIN rq[31]
    DIRECTION OUTPUT ;
    USE SIGNAL ;
    PORT
      LAYER M4 ;
        RECT  0 4.368 0.084 4.392 ;
    END
  END rq[31]
  PIN rq[32]
    DIRECTION OUTPUT ;
    USE SIGNAL ;
    PORT
      LAYER M4 ;
        RECT  0 4.464 0.084 4.488 ;
    END
  END rq[32]
  PIN rq[33]
    DIRECTION OUTPUT ;
    USE SIGNAL ;
    PORT
      LAYER M4 ;
        RECT  0 4.56 0.084 4.584 ;
    END
  END rq[33]
  PIN rq[34]
    DIRECTION OUTPUT ;
    USE SIGNAL ;
    PORT
      LAYER M4 ;
        RECT  0 4.656 0.084 4.68 ;
    END
  END rq[34]
  PIN rq[35]
    DIRECTION OUTPUT ;
    USE SIGNAL ;
    PORT
      LAYER M4 ;
        RECT  0 4.752 0.084 4.776 ;
    END
  END rq[35]
  PIN rq[36]
    DIRECTION OUTPUT ;
    USE SIGNAL ;
    PORT
      LAYER M4 ;
        RECT  0 4.848 0.084 4.872 ;
    END
  END rq[36]
  PIN rq[37]
    DIRECTION OUTPUT ;
    USE SIGNAL ;
    PORT
      LAYER M4 ;
        RECT  0 4.944 0.084 4.968 ;
    END
  END rq[37]
  PIN rq[38]
    DIRECTION OUTPUT ;
    USE SIGNAL ;
    PORT
      LAYER M4 ;
        RECT  0 5.04 0.084 5.064 ;
    END
  END rq[38]
  PIN rq[39]
    DIRECTION OUTPUT ;
    USE SIGNAL ;
    PORT
      LAYER M4 ;
        RECT  0 5.136 0.084 5.16 ;
    END
  END rq[39]
  PIN rq[3]
    DIRECTION OUTPUT ;
    USE SIGNAL ;
    PORT
      LAYER M4 ;
        RECT  0 1.68 0.084 1.704 ;
    END
  END rq[3]
  PIN rq[40]
    DIRECTION OUTPUT ;
    USE SIGNAL ;
    PORT
      LAYER M4 ;
        RECT  0 5.232 0.084 5.256 ;
    END
  END rq[40]
  PIN rq[41]
    DIRECTION OUTPUT ;
    USE SIGNAL ;
    PORT
      LAYER M4 ;
        RECT  0 5.328 0.084 5.352 ;
    END
  END rq[41]
  PIN rq[42]
    DIRECTION OUTPUT ;
    USE SIGNAL ;
    PORT
      LAYER M4 ;
        RECT  0 5.424 0.084 5.448 ;
    END
  END rq[42]
  PIN rq[43]
    DIRECTION OUTPUT ;
    USE SIGNAL ;
    PORT
      LAYER M4 ;
        RECT  0 5.52 0.084 5.544 ;
    END
  END rq[43]
  PIN rq[44]
    DIRECTION OUTPUT ;
    USE SIGNAL ;
    PORT
      LAYER M4 ;
        RECT  0 5.616 0.084 5.64 ;
    END
  END rq[44]
  PIN rq[45]
    DIRECTION OUTPUT ;
    USE SIGNAL ;
    PORT
      LAYER M4 ;
        RECT  0 5.712 0.084 5.736 ;
    END
  END rq[45]
  PIN rq[46]
    DIRECTION OUTPUT ;
    USE SIGNAL ;
    PORT
      LAYER M4 ;
        RECT  0 5.808 0.084 5.832 ;
    END
  END rq[46]
  PIN rq[47]
    DIRECTION OUTPUT ;
    USE SIGNAL ;
    PORT
      LAYER M4 ;
        RECT  0 5.904 0.084 5.928 ;
    END
  END rq[47]
  PIN rq[48]
    DIRECTION OUTPUT ;
    USE SIGNAL ;
    PORT
      LAYER M4 ;
        RECT  0 6 0.084 6.024 ;
    END
  END rq[48]
  PIN rq[49]
    DIRECTION OUTPUT ;
    USE SIGNAL ;
    PORT
      LAYER M4 ;
        RECT  0 6.096 0.084 6.12 ;
    END
  END rq[49]
  PIN rq[4]
    DIRECTION OUTPUT ;
    USE SIGNAL ;
    PORT
      LAYER M4 ;
        RECT  0 1.776 0.084 1.8 ;
    END
  END rq[4]
  PIN rq[50]
    DIRECTION OUTPUT ;
    USE SIGNAL ;
    PORT
      LAYER M4 ;
        RECT  0 6.192 0.084 6.216 ;
    END
  END rq[50]
  PIN rq[51]
    DIRECTION OUTPUT ;
    USE SIGNAL ;
    PORT
      LAYER M4 ;
        RECT  0 6.288 0.084 6.312 ;
    END
  END rq[51]
  PIN rq[52]
    DIRECTION OUTPUT ;
    USE SIGNAL ;
    PORT
      LAYER M4 ;
        RECT  0 6.384 0.084 6.408 ;
    END
  END rq[52]
  PIN rq[53]
    DIRECTION OUTPUT ;
    USE SIGNAL ;
    PORT
      LAYER M4 ;
        RECT  0 6.48 0.084 6.504 ;
    END
  END rq[53]
  PIN rq[54]
    DIRECTION OUTPUT ;
    USE SIGNAL ;
    PORT
      LAYER M4 ;
        RECT  0 6.576 0.084 6.6 ;
    END
  END rq[54]
  PIN rq[55]
    DIRECTION OUTPUT ;
    USE SIGNAL ;
    PORT
      LAYER M4 ;
        RECT  0 6.672 0.084 6.696 ;
    END
  END rq[55]
  PIN rq[56]
    DIRECTION OUTPUT ;
    USE SIGNAL ;
    PORT
      LAYER M4 ;
        RECT  0 6.768 0.084 6.792 ;
    END
  END rq[56]
  PIN rq[57]
    DIRECTION OUTPUT ;
    USE SIGNAL ;
    PORT
      LAYER M4 ;
        RECT  0 6.864 0.084 6.888 ;
    END
  END rq[57]
  PIN rq[58]
    DIRECTION OUTPUT ;
    USE SIGNAL ;
    PORT
      LAYER M4 ;
        RECT  0 6.96 0.084 6.984 ;
    END
  END rq[58]
  PIN rq[59]
    DIRECTION OUTPUT ;
    USE SIGNAL ;
    PORT
      LAYER M4 ;
        RECT  0 7.056 0.084 7.08 ;
    END
  END rq[59]
  PIN rq[5]
    DIRECTION OUTPUT ;
    USE SIGNAL ;
    PORT
      LAYER M4 ;
        RECT  0 1.872 0.084 1.896 ;
    END
  END rq[5]
  PIN rq[60]
    DIRECTION OUTPUT ;
    USE SIGNAL ;
    PORT
      LAYER M4 ;
        RECT  0 7.152 0.084 7.176 ;
    END
  END rq[60]
  PIN rq[61]
    DIRECTION OUTPUT ;
    USE SIGNAL ;
    PORT
      LAYER M4 ;
        RECT  0 7.248 0.084 7.272 ;
    END
  END rq[61]
  PIN rq[62]
    DIRECTION OUTPUT ;
    USE SIGNAL ;
    PORT
      LAYER M4 ;
        RECT  0 7.344 0.084 7.368 ;
    END
  END rq[62]
  PIN rq[63]
    DIRECTION OUTPUT ;
    USE SIGNAL ;
    PORT
      LAYER M4 ;
        RECT  0 7.44 0.084 7.464 ;
    END
  END rq[63]
  PIN rq[64]
    DIRECTION OUTPUT ;
    USE SIGNAL ;
    PORT
      LAYER M4 ;
        RECT  0 7.536 0.084 7.56 ;
    END
  END rq[64]
  PIN rq[65]
    DIRECTION OUTPUT ;
    USE SIGNAL ;
    PORT
      LAYER M4 ;
        RECT  0 7.632 0.084 7.656 ;
    END
  END rq[65]
  PIN rq[66]
    DIRECTION OUTPUT ;
    USE SIGNAL ;
    PORT
      LAYER M4 ;
        RECT  0 7.728 0.084 7.752 ;
    END
  END rq[66]
  PIN rq[67]
    DIRECTION OUTPUT ;
    USE SIGNAL ;
    PORT
      LAYER M4 ;
        RECT  0 7.824 0.084 7.848 ;
    END
  END rq[67]
  PIN rq[68]
    DIRECTION OUTPUT ;
    USE SIGNAL ;
    PORT
      LAYER M4 ;
        RECT  0 7.92 0.084 7.944 ;
    END
  END rq[68]
  PIN rq[69]
    DIRECTION OUTPUT ;
    USE SIGNAL ;
    PORT
      LAYER M4 ;
        RECT  0 8.016 0.084 8.04 ;
    END
  END rq[69]
  PIN rq[6]
    DIRECTION OUTPUT ;
    USE SIGNAL ;
    PORT
      LAYER M4 ;
        RECT  0 1.968 0.084 1.992 ;
    END
  END rq[6]
  PIN rq[70]
    DIRECTION OUTPUT ;
    USE SIGNAL ;
    PORT
      LAYER M4 ;
        RECT  0 8.112 0.084 8.136 ;
    END
  END rq[70]
  PIN rq[71]
    DIRECTION OUTPUT ;
    USE SIGNAL ;
    PORT
      LAYER M4 ;
        RECT  0 8.208 0.084 8.232 ;
    END
  END rq[71]
  PIN rq[72]
    DIRECTION OUTPUT ;
    USE SIGNAL ;
    PORT
      LAYER M4 ;
        RECT  0 8.304 0.084 8.328 ;
    END
  END rq[72]
  PIN rq[73]
    DIRECTION OUTPUT ;
    USE SIGNAL ;
    PORT
      LAYER M4 ;
        RECT  0 8.4 0.084 8.424 ;
    END
  END rq[73]
  PIN rq[74]
    DIRECTION OUTPUT ;
    USE SIGNAL ;
    PORT
      LAYER M4 ;
        RECT  0 8.496 0.084 8.52 ;
    END
  END rq[74]
  PIN rq[75]
    DIRECTION OUTPUT ;
    USE SIGNAL ;
    PORT
      LAYER M4 ;
        RECT  0 8.592 0.084 8.616 ;
    END
  END rq[75]
  PIN rq[76]
    DIRECTION OUTPUT ;
    USE SIGNAL ;
    PORT
      LAYER M4 ;
        RECT  0 8.688 0.084 8.712 ;
    END
  END rq[76]
  PIN rq[77]
    DIRECTION OUTPUT ;
    USE SIGNAL ;
    PORT
      LAYER M4 ;
        RECT  0 8.784 0.084 8.808 ;
    END
  END rq[77]
  PIN rq[78]
    DIRECTION OUTPUT ;
    USE SIGNAL ;
    PORT
      LAYER M4 ;
        RECT  0 8.88 0.084 8.904 ;
    END
  END rq[78]
  PIN rq[79]
    DIRECTION OUTPUT ;
    USE SIGNAL ;
    PORT
      LAYER M4 ;
        RECT  0 8.976 0.084 9 ;
    END
  END rq[79]
  PIN rq[7]
    DIRECTION OUTPUT ;
    USE SIGNAL ;
    PORT
      LAYER M4 ;
        RECT  0 2.064 0.084 2.088 ;
    END
  END rq[7]
  PIN rq[80]
    DIRECTION OUTPUT ;
    USE SIGNAL ;
    PORT
      LAYER M4 ;
        RECT  0 9.072 0.084 9.096 ;
    END
  END rq[80]
  PIN rq[81]
    DIRECTION OUTPUT ;
    USE SIGNAL ;
    PORT
      LAYER M4 ;
        RECT  0 9.168 0.084 9.192 ;
    END
  END rq[81]
  PIN rq[82]
    DIRECTION OUTPUT ;
    USE SIGNAL ;
    PORT
      LAYER M4 ;
        RECT  0 9.264 0.084 9.288 ;
    END
  END rq[82]
  PIN rq[83]
    DIRECTION OUTPUT ;
    USE SIGNAL ;
    PORT
      LAYER M4 ;
        RECT  0 9.36 0.084 9.384 ;
    END
  END rq[83]
  PIN rq[84]
    DIRECTION OUTPUT ;
    USE SIGNAL ;
    PORT
      LAYER M4 ;
        RECT  0 9.456 0.084 9.48 ;
    END
  END rq[84]
  PIN rq[85]
    DIRECTION OUTPUT ;
    USE SIGNAL ;
    PORT
      LAYER M4 ;
        RECT  0 9.552 0.084 9.576 ;
    END
  END rq[85]
  PIN rq[86]
    DIRECTION OUTPUT ;
    USE SIGNAL ;
    PORT
      LAYER M4 ;
        RECT  0 9.648 0.084 9.672 ;
    END
  END rq[86]
  PIN rq[87]
    DIRECTION OUTPUT ;
    USE SIGNAL ;
    PORT
      LAYER M4 ;
        RECT  0 9.744 0.084 9.768 ;
    END
  END rq[87]
  PIN rq[88]
    DIRECTION OUTPUT ;
    USE SIGNAL ;
    PORT
      LAYER M4 ;
        RECT  0 9.84 0.084 9.864 ;
    END
  END rq[88]
  PIN rq[89]
    DIRECTION OUTPUT ;
    USE SIGNAL ;
    PORT
      LAYER M4 ;
        RECT  0 9.936 0.084 9.96 ;
    END
  END rq[89]
  PIN rq[8]
    DIRECTION OUTPUT ;
    USE SIGNAL ;
    PORT
      LAYER M4 ;
        RECT  0 2.16 0.084 2.184 ;
    END
  END rq[8]
  PIN rq[90]
    DIRECTION OUTPUT ;
    USE SIGNAL ;
    PORT
      LAYER M4 ;
        RECT  0 10.032 0.084 10.056 ;
    END
  END rq[90]
  PIN rq[91]
    DIRECTION OUTPUT ;
    USE SIGNAL ;
    PORT
      LAYER M4 ;
        RECT  0 10.128 0.084 10.152 ;
    END
  END rq[91]
  PIN rq[92]
    DIRECTION OUTPUT ;
    USE SIGNAL ;
    PORT
      LAYER M4 ;
        RECT  0 10.224 0.084 10.248 ;
    END
  END rq[92]
  PIN rq[93]
    DIRECTION OUTPUT ;
    USE SIGNAL ;
    PORT
      LAYER M4 ;
        RECT  0 10.32 0.084 10.344 ;
    END
  END rq[93]
  PIN rq[94]
    DIRECTION OUTPUT ;
    USE SIGNAL ;
    PORT
      LAYER M4 ;
        RECT  0 10.416 0.084 10.44 ;
    END
  END rq[94]
  PIN rq[95]
    DIRECTION OUTPUT ;
    USE SIGNAL ;
    PORT
      LAYER M4 ;
        RECT  0 10.512 0.084 10.536 ;
    END
  END rq[95]
  PIN rq[96]
    DIRECTION OUTPUT ;
    USE SIGNAL ;
    PORT
      LAYER M4 ;
        RECT  0 10.608 0.084 10.632 ;
    END
  END rq[96]
  PIN rq[97]
    DIRECTION OUTPUT ;
    USE SIGNAL ;
    PORT
      LAYER M4 ;
        RECT  0 10.704 0.084 10.728 ;
    END
  END rq[97]
  PIN rq[98]
    DIRECTION OUTPUT ;
    USE SIGNAL ;
    PORT
      LAYER M4 ;
        RECT  0 11.568 0.084 11.592 ;
    END
  END rq[98]
  PIN rq[99]
    DIRECTION OUTPUT ;
    USE SIGNAL ;
    PORT
      LAYER M4 ;
        RECT  0 11.664 0.084 11.688 ;
    END
  END rq[99]
  PIN rq[9]
    DIRECTION OUTPUT ;
    USE SIGNAL ;
    PORT
      LAYER M4 ;
        RECT  0 2.256 0.084 2.28 ;
    END
  END rq[9]
  PIN rr_valid_i[0]
    DIRECTION INPUT ;
    USE SIGNAL ;
    PORT
      LAYER M4 ;
        RECT  0 39.216 0.084 39.24 ;
    END
  END rr_valid_i[0]
  PIN rr_valid_i[1]
    DIRECTION INPUT ;
    USE SIGNAL ;
    PORT
      LAYER M4 ;
        RECT  0 39.312 0.084 39.336 ;
    END
  END rr_valid_i[1]
  PIN rr_valid_i[2]
    DIRECTION INPUT ;
    USE SIGNAL ;
    PORT
      LAYER M4 ;
        RECT  0 39.408 0.084 39.432 ;
    END
  END rr_valid_i[2]
  PIN rr_valid_i[3]
    DIRECTION INPUT ;
    USE SIGNAL ;
    PORT
      LAYER M4 ;
        RECT  0 39.504 0.084 39.528 ;
    END
  END rr_valid_i[3]
  PIN rr_valid_i[4]
    DIRECTION INPUT ;
    USE SIGNAL ;
    PORT
      LAYER M4 ;
        RECT  0 39.6 0.084 39.624 ;
    END
  END rr_valid_i[4]
  PIN rr_valid_i[5]
    DIRECTION INPUT ;
    USE SIGNAL ;
    PORT
      LAYER M4 ;
        RECT  0 39.696 0.084 39.72 ;
    END
  END rr_valid_i[5]
  PIN rr_valid_i[6]
    DIRECTION INPUT ;
    USE SIGNAL ;
    PORT
      LAYER M4 ;
        RECT  0 39.792 0.084 39.816 ;
    END
  END rr_valid_i[6]
  PIN rr_valid_i[7]
    DIRECTION INPUT ;
    USE SIGNAL ;
    PORT
      LAYER M4 ;
        RECT  0 39.888 0.084 39.912 ;
    END
  END rr_valid_i[7]
  PIN rst_n
    DIRECTION INPUT ;
    USE SIGNAL ;
    PORT
      LAYER M4 ;
        RECT  69.036 63.984 69.12 64.008 ;
    END
  END rst_n
  PIN stk[0]
    DIRECTION INPUT ;
    USE SIGNAL ;
    PORT
      LAYER M4 ;
        RECT  69.036 64.08 69.12 64.104 ;
    END
  END stk[0]
  PIN stk[1]
    DIRECTION INPUT ;
    USE SIGNAL ;
    PORT
      LAYER M4 ;
        RECT  69.036 64.176 69.12 64.2 ;
    END
  END stk[1]
  PIN wa[0]
    DIRECTION INPUT ;
    USE SIGNAL ;
    PORT
      LAYER M5 ;
        RECT  57.456 69.036 57.48 69.12 ;
    END
  END wa[0]
  PIN wa[10]
    DIRECTION INPUT ;
    USE SIGNAL ;
    PORT
      LAYER M5 ;
        RECT  58.416 69.036 58.44 69.12 ;
    END
  END wa[10]
  PIN wa[11]
    DIRECTION INPUT ;
    USE SIGNAL ;
    PORT
      LAYER M5 ;
        RECT  58.512 69.036 58.536 69.12 ;
    END
  END wa[11]
  PIN wa[1]
    DIRECTION INPUT ;
    USE SIGNAL ;
    PORT
      LAYER M5 ;
        RECT  57.552 69.036 57.576 69.12 ;
    END
  END wa[1]
  PIN wa[2]
    DIRECTION INPUT ;
    USE SIGNAL ;
    PORT
      LAYER M5 ;
        RECT  57.648 69.036 57.672 69.12 ;
    END
  END wa[2]
  PIN wa[3]
    DIRECTION INPUT ;
    USE SIGNAL ;
    PORT
      LAYER M5 ;
        RECT  57.744 69.036 57.768 69.12 ;
    END
  END wa[3]
  PIN wa[4]
    DIRECTION INPUT ;
    USE SIGNAL ;
    PORT
      LAYER M5 ;
        RECT  57.84 69.036 57.864 69.12 ;
    END
  END wa[4]
  PIN wa[5]
    DIRECTION INPUT ;
    USE SIGNAL ;
    PORT
      LAYER M5 ;
        RECT  57.936 69.036 57.96 69.12 ;
    END
  END wa[5]
  PIN wa[6]
    DIRECTION INPUT ;
    USE SIGNAL ;
    PORT
      LAYER M5 ;
        RECT  58.032 69.036 58.056 69.12 ;
    END
  END wa[6]
  PIN wa[7]
    DIRECTION INPUT ;
    USE SIGNAL ;
    PORT
      LAYER M5 ;
        RECT  58.128 69.036 58.152 69.12 ;
    END
  END wa[7]
  PIN wa[8]
    DIRECTION INPUT ;
    USE SIGNAL ;
    PORT
      LAYER M5 ;
        RECT  58.224 69.036 58.248 69.12 ;
    END
  END wa[8]
  PIN wa[9]
    DIRECTION INPUT ;
    USE SIGNAL ;
    PORT
      LAYER M5 ;
        RECT  58.32 69.036 58.344 69.12 ;
    END
  END wa[9]
  PIN wb_fill_bank
    DIRECTION OUTPUT ;
    USE SIGNAL ;
    PORT
      LAYER M5 ;
        RECT  58.608 69.036 58.632 69.12 ;
    END
  END wb_fill_bank
  PIN wb_fill_epoch[0]
    DIRECTION OUTPUT ;
    USE SIGNAL ;
    PORT
      LAYER M5 ;
        RECT  58.704 69.036 58.728 69.12 ;
    END
  END wb_fill_epoch[0]
  PIN wb_fill_epoch[10]
    DIRECTION OUTPUT ;
    USE SIGNAL ;
    PORT
      LAYER M5 ;
        RECT  50.448 69.036 50.472 69.12 ;
    END
  END wb_fill_epoch[10]
  PIN wb_fill_epoch[11]
    DIRECTION OUTPUT ;
    USE SIGNAL ;
    PORT
      LAYER M5 ;
        RECT  50.544 69.036 50.568 69.12 ;
    END
  END wb_fill_epoch[11]
  PIN wb_fill_epoch[12]
    DIRECTION OUTPUT ;
    USE SIGNAL ;
    PORT
      LAYER M5 ;
        RECT  50.64 69.036 50.664 69.12 ;
    END
  END wb_fill_epoch[12]
  PIN wb_fill_epoch[13]
    DIRECTION OUTPUT ;
    USE SIGNAL ;
    PORT
      LAYER M5 ;
        RECT  50.736 69.036 50.76 69.12 ;
    END
  END wb_fill_epoch[13]
  PIN wb_fill_epoch[14]
    DIRECTION OUTPUT ;
    USE SIGNAL ;
    PORT
      LAYER M5 ;
        RECT  50.832 69.036 50.856 69.12 ;
    END
  END wb_fill_epoch[14]
  PIN wb_fill_epoch[15]
    DIRECTION OUTPUT ;
    USE SIGNAL ;
    PORT
      LAYER M5 ;
        RECT  50.928 69.036 50.952 69.12 ;
    END
  END wb_fill_epoch[15]
  PIN wb_fill_epoch[1]
    DIRECTION OUTPUT ;
    USE SIGNAL ;
    PORT
      LAYER M5 ;
        RECT  58.8 69.036 58.824 69.12 ;
    END
  END wb_fill_epoch[1]
  PIN wb_fill_epoch[2]
    DIRECTION OUTPUT ;
    USE SIGNAL ;
    PORT
      LAYER M5 ;
        RECT  58.896 69.036 58.92 69.12 ;
    END
  END wb_fill_epoch[2]
  PIN wb_fill_epoch[3]
    DIRECTION OUTPUT ;
    USE SIGNAL ;
    PORT
      LAYER M5 ;
        RECT  58.992 69.036 59.016 69.12 ;
    END
  END wb_fill_epoch[3]
  PIN wb_fill_epoch[4]
    DIRECTION OUTPUT ;
    USE SIGNAL ;
    PORT
      LAYER M5 ;
        RECT  59.088 69.036 59.112 69.12 ;
    END
  END wb_fill_epoch[4]
  PIN wb_fill_epoch[5]
    DIRECTION OUTPUT ;
    USE SIGNAL ;
    PORT
      LAYER M5 ;
        RECT  49.968 69.036 49.992 69.12 ;
    END
  END wb_fill_epoch[5]
  PIN wb_fill_epoch[6]
    DIRECTION OUTPUT ;
    USE SIGNAL ;
    PORT
      LAYER M5 ;
        RECT  50.064 69.036 50.088 69.12 ;
    END
  END wb_fill_epoch[6]
  PIN wb_fill_epoch[7]
    DIRECTION OUTPUT ;
    USE SIGNAL ;
    PORT
      LAYER M5 ;
        RECT  50.16 69.036 50.184 69.12 ;
    END
  END wb_fill_epoch[7]
  PIN wb_fill_epoch[8]
    DIRECTION OUTPUT ;
    USE SIGNAL ;
    PORT
      LAYER M5 ;
        RECT  50.256 69.036 50.28 69.12 ;
    END
  END wb_fill_epoch[8]
  PIN wb_fill_epoch[9]
    DIRECTION OUTPUT ;
    USE SIGNAL ;
    PORT
      LAYER M5 ;
        RECT  50.352 69.036 50.376 69.12 ;
    END
  END wb_fill_epoch[9]
  PIN wb_fill_start
    DIRECTION OUTPUT ;
    USE SIGNAL ;
    PORT
      LAYER M5 ;
        RECT  51.024 69.036 51.048 69.12 ;
    END
  END wb_fill_start
  PIN wb_ready
    DIRECTION INPUT ;
    USE SIGNAL ;
    PORT
      LAYER M5 ;
        RECT  51.12 69.036 51.144 69.12 ;
    END
  END wb_ready
  PIN wb_reserve_bank
    DIRECTION OUTPUT ;
    USE SIGNAL ;
    PORT
      LAYER M5 ;
        RECT  51.216 69.036 51.24 69.12 ;
    END
  END wb_reserve_bank
  PIN wb_reserve_base[0]
    DIRECTION OUTPUT ;
    USE SIGNAL ;
    PORT
      LAYER M5 ;
        RECT  51.312 69.036 51.336 69.12 ;
    END
  END wb_reserve_base[0]
  PIN wb_reserve_base[10]
    DIRECTION OUTPUT ;
    USE SIGNAL ;
    PORT
      LAYER M5 ;
        RECT  52.272 69.036 52.296 69.12 ;
    END
  END wb_reserve_base[10]
  PIN wb_reserve_base[11]
    DIRECTION OUTPUT ;
    USE SIGNAL ;
    PORT
      LAYER M5 ;
        RECT  52.368 69.036 52.392 69.12 ;
    END
  END wb_reserve_base[11]
  PIN wb_reserve_base[12]
    DIRECTION OUTPUT ;
    USE SIGNAL ;
    PORT
      LAYER M5 ;
        RECT  52.464 69.036 52.488 69.12 ;
    END
  END wb_reserve_base[12]
  PIN wb_reserve_base[13]
    DIRECTION OUTPUT ;
    USE SIGNAL ;
    PORT
      LAYER M5 ;
        RECT  52.56 69.036 52.584 69.12 ;
    END
  END wb_reserve_base[13]
  PIN wb_reserve_base[14]
    DIRECTION OUTPUT ;
    USE SIGNAL ;
    PORT
      LAYER M5 ;
        RECT  52.656 69.036 52.68 69.12 ;
    END
  END wb_reserve_base[14]
  PIN wb_reserve_base[15]
    DIRECTION OUTPUT ;
    USE SIGNAL ;
    PORT
      LAYER M5 ;
        RECT  52.752 69.036 52.776 69.12 ;
    END
  END wb_reserve_base[15]
  PIN wb_reserve_base[16]
    DIRECTION OUTPUT ;
    USE SIGNAL ;
    PORT
      LAYER M5 ;
        RECT  52.848 69.036 52.872 69.12 ;
    END
  END wb_reserve_base[16]
  PIN wb_reserve_base[17]
    DIRECTION OUTPUT ;
    USE SIGNAL ;
    PORT
      LAYER M5 ;
        RECT  52.944 69.036 52.968 69.12 ;
    END
  END wb_reserve_base[17]
  PIN wb_reserve_base[18]
    DIRECTION OUTPUT ;
    USE SIGNAL ;
    PORT
      LAYER M5 ;
        RECT  53.04 69.036 53.064 69.12 ;
    END
  END wb_reserve_base[18]
  PIN wb_reserve_base[19]
    DIRECTION OUTPUT ;
    USE SIGNAL ;
    PORT
      LAYER M5 ;
        RECT  53.136 69.036 53.16 69.12 ;
    END
  END wb_reserve_base[19]
  PIN wb_reserve_base[1]
    DIRECTION OUTPUT ;
    USE SIGNAL ;
    PORT
      LAYER M5 ;
        RECT  51.408 69.036 51.432 69.12 ;
    END
  END wb_reserve_base[1]
  PIN wb_reserve_base[20]
    DIRECTION OUTPUT ;
    USE SIGNAL ;
    PORT
      LAYER M5 ;
        RECT  53.232 69.036 53.256 69.12 ;
    END
  END wb_reserve_base[20]
  PIN wb_reserve_base[21]
    DIRECTION OUTPUT ;
    USE SIGNAL ;
    PORT
      LAYER M5 ;
        RECT  53.328 69.036 53.352 69.12 ;
    END
  END wb_reserve_base[21]
  PIN wb_reserve_base[22]
    DIRECTION OUTPUT ;
    USE SIGNAL ;
    PORT
      LAYER M5 ;
        RECT  53.424 69.036 53.448 69.12 ;
    END
  END wb_reserve_base[22]
  PIN wb_reserve_base[23]
    DIRECTION OUTPUT ;
    USE SIGNAL ;
    PORT
      LAYER M5 ;
        RECT  53.52 69.036 53.544 69.12 ;
    END
  END wb_reserve_base[23]
  PIN wb_reserve_base[24]
    DIRECTION OUTPUT ;
    USE SIGNAL ;
    PORT
      LAYER M5 ;
        RECT  53.616 69.036 53.64 69.12 ;
    END
  END wb_reserve_base[24]
  PIN wb_reserve_base[25]
    DIRECTION OUTPUT ;
    USE SIGNAL ;
    PORT
      LAYER M5 ;
        RECT  53.712 69.036 53.736 69.12 ;
    END
  END wb_reserve_base[25]
  PIN wb_reserve_base[26]
    DIRECTION OUTPUT ;
    USE SIGNAL ;
    PORT
      LAYER M5 ;
        RECT  53.808 69.036 53.832 69.12 ;
    END
  END wb_reserve_base[26]
  PIN wb_reserve_base[27]
    DIRECTION OUTPUT ;
    USE SIGNAL ;
    PORT
      LAYER M5 ;
        RECT  53.904 69.036 53.928 69.12 ;
    END
  END wb_reserve_base[27]
  PIN wb_reserve_base[28]
    DIRECTION OUTPUT ;
    USE SIGNAL ;
    PORT
      LAYER M5 ;
        RECT  54 69.036 54.024 69.12 ;
    END
  END wb_reserve_base[28]
  PIN wb_reserve_base[29]
    DIRECTION OUTPUT ;
    USE SIGNAL ;
    PORT
      LAYER M5 ;
        RECT  54.096 69.036 54.12 69.12 ;
    END
  END wb_reserve_base[29]
  PIN wb_reserve_base[2]
    DIRECTION OUTPUT ;
    USE SIGNAL ;
    PORT
      LAYER M5 ;
        RECT  51.504 69.036 51.528 69.12 ;
    END
  END wb_reserve_base[2]
  PIN wb_reserve_base[30]
    DIRECTION OUTPUT ;
    USE SIGNAL ;
    PORT
      LAYER M5 ;
        RECT  54.192 69.036 54.216 69.12 ;
    END
  END wb_reserve_base[30]
  PIN wb_reserve_base[31]
    DIRECTION OUTPUT ;
    USE SIGNAL ;
    PORT
      LAYER M5 ;
        RECT  54.288 69.036 54.312 69.12 ;
    END
  END wb_reserve_base[31]
  PIN wb_reserve_base[3]
    DIRECTION OUTPUT ;
    USE SIGNAL ;
    PORT
      LAYER M5 ;
        RECT  51.6 69.036 51.624 69.12 ;
    END
  END wb_reserve_base[3]
  PIN wb_reserve_base[4]
    DIRECTION OUTPUT ;
    USE SIGNAL ;
    PORT
      LAYER M5 ;
        RECT  51.696 69.036 51.72 69.12 ;
    END
  END wb_reserve_base[4]
  PIN wb_reserve_base[5]
    DIRECTION OUTPUT ;
    USE SIGNAL ;
    PORT
      LAYER M5 ;
        RECT  51.792 69.036 51.816 69.12 ;
    END
  END wb_reserve_base[5]
  PIN wb_reserve_base[6]
    DIRECTION OUTPUT ;
    USE SIGNAL ;
    PORT
      LAYER M5 ;
        RECT  51.888 69.036 51.912 69.12 ;
    END
  END wb_reserve_base[6]
  PIN wb_reserve_base[7]
    DIRECTION OUTPUT ;
    USE SIGNAL ;
    PORT
      LAYER M5 ;
        RECT  51.984 69.036 52.008 69.12 ;
    END
  END wb_reserve_base[7]
  PIN wb_reserve_base[8]
    DIRECTION OUTPUT ;
    USE SIGNAL ;
    PORT
      LAYER M5 ;
        RECT  52.08 69.036 52.104 69.12 ;
    END
  END wb_reserve_base[8]
  PIN wb_reserve_base[9]
    DIRECTION OUTPUT ;
    USE SIGNAL ;
    PORT
      LAYER M5 ;
        RECT  52.176 69.036 52.2 69.12 ;
    END
  END wb_reserve_base[9]
  PIN wb_reserve_epoch[0]
    DIRECTION OUTPUT ;
    USE SIGNAL ;
    PORT
      LAYER M5 ;
        RECT  54.384 69.036 54.408 69.12 ;
    END
  END wb_reserve_epoch[0]
  PIN wb_reserve_epoch[10]
    DIRECTION OUTPUT ;
    USE SIGNAL ;
    PORT
      LAYER M5 ;
        RECT  55.344 69.036 55.368 69.12 ;
    END
  END wb_reserve_epoch[10]
  PIN wb_reserve_epoch[11]
    DIRECTION OUTPUT ;
    USE SIGNAL ;
    PORT
      LAYER M5 ;
        RECT  55.44 69.036 55.464 69.12 ;
    END
  END wb_reserve_epoch[11]
  PIN wb_reserve_epoch[12]
    DIRECTION OUTPUT ;
    USE SIGNAL ;
    PORT
      LAYER M5 ;
        RECT  55.536 69.036 55.56 69.12 ;
    END
  END wb_reserve_epoch[12]
  PIN wb_reserve_epoch[13]
    DIRECTION OUTPUT ;
    USE SIGNAL ;
    PORT
      LAYER M5 ;
        RECT  55.632 69.036 55.656 69.12 ;
    END
  END wb_reserve_epoch[13]
  PIN wb_reserve_epoch[14]
    DIRECTION OUTPUT ;
    USE SIGNAL ;
    PORT
      LAYER M5 ;
        RECT  55.728 69.036 55.752 69.12 ;
    END
  END wb_reserve_epoch[14]
  PIN wb_reserve_epoch[15]
    DIRECTION OUTPUT ;
    USE SIGNAL ;
    PORT
      LAYER M5 ;
        RECT  55.824 69.036 55.848 69.12 ;
    END
  END wb_reserve_epoch[15]
  PIN wb_reserve_epoch[1]
    DIRECTION OUTPUT ;
    USE SIGNAL ;
    PORT
      LAYER M5 ;
        RECT  54.48 69.036 54.504 69.12 ;
    END
  END wb_reserve_epoch[1]
  PIN wb_reserve_epoch[2]
    DIRECTION OUTPUT ;
    USE SIGNAL ;
    PORT
      LAYER M5 ;
        RECT  54.576 69.036 54.6 69.12 ;
    END
  END wb_reserve_epoch[2]
  PIN wb_reserve_epoch[3]
    DIRECTION OUTPUT ;
    USE SIGNAL ;
    PORT
      LAYER M5 ;
        RECT  54.672 69.036 54.696 69.12 ;
    END
  END wb_reserve_epoch[3]
  PIN wb_reserve_epoch[4]
    DIRECTION OUTPUT ;
    USE SIGNAL ;
    PORT
      LAYER M5 ;
        RECT  54.768 69.036 54.792 69.12 ;
    END
  END wb_reserve_epoch[4]
  PIN wb_reserve_epoch[5]
    DIRECTION OUTPUT ;
    USE SIGNAL ;
    PORT
      LAYER M5 ;
        RECT  54.864 69.036 54.888 69.12 ;
    END
  END wb_reserve_epoch[5]
  PIN wb_reserve_epoch[6]
    DIRECTION OUTPUT ;
    USE SIGNAL ;
    PORT
      LAYER M5 ;
        RECT  54.96 69.036 54.984 69.12 ;
    END
  END wb_reserve_epoch[6]
  PIN wb_reserve_epoch[7]
    DIRECTION OUTPUT ;
    USE SIGNAL ;
    PORT
      LAYER M5 ;
        RECT  55.056 69.036 55.08 69.12 ;
    END
  END wb_reserve_epoch[7]
  PIN wb_reserve_epoch[8]
    DIRECTION OUTPUT ;
    USE SIGNAL ;
    PORT
      LAYER M5 ;
        RECT  55.152 69.036 55.176 69.12 ;
    END
  END wb_reserve_epoch[8]
  PIN wb_reserve_epoch[9]
    DIRECTION OUTPUT ;
    USE SIGNAL ;
    PORT
      LAYER M5 ;
        RECT  55.248 69.036 55.272 69.12 ;
    END
  END wb_reserve_epoch[9]
  PIN wb_reserve_sectors[0]
    DIRECTION OUTPUT ;
    USE SIGNAL ;
    PORT
      LAYER M5 ;
        RECT  55.92 69.036 55.944 69.12 ;
    END
  END wb_reserve_sectors[0]
  PIN wb_reserve_sectors[10]
    DIRECTION OUTPUT ;
    USE SIGNAL ;
    PORT
      LAYER M5 ;
        RECT  48.912 69.036 48.936 69.12 ;
    END
  END wb_reserve_sectors[10]
  PIN wb_reserve_sectors[11]
    DIRECTION OUTPUT ;
    USE SIGNAL ;
    PORT
      LAYER M5 ;
        RECT  49.008 69.036 49.032 69.12 ;
    END
  END wb_reserve_sectors[11]
  PIN wb_reserve_sectors[1]
    DIRECTION OUTPUT ;
    USE SIGNAL ;
    PORT
      LAYER M5 ;
        RECT  56.016 69.036 56.04 69.12 ;
    END
  END wb_reserve_sectors[1]
  PIN wb_reserve_sectors[2]
    DIRECTION OUTPUT ;
    USE SIGNAL ;
    PORT
      LAYER M5 ;
        RECT  48.144 69.036 48.168 69.12 ;
    END
  END wb_reserve_sectors[2]
  PIN wb_reserve_sectors[3]
    DIRECTION OUTPUT ;
    USE SIGNAL ;
    PORT
      LAYER M5 ;
        RECT  48.24 69.036 48.264 69.12 ;
    END
  END wb_reserve_sectors[3]
  PIN wb_reserve_sectors[4]
    DIRECTION OUTPUT ;
    USE SIGNAL ;
    PORT
      LAYER M5 ;
        RECT  48.336 69.036 48.36 69.12 ;
    END
  END wb_reserve_sectors[4]
  PIN wb_reserve_sectors[5]
    DIRECTION OUTPUT ;
    USE SIGNAL ;
    PORT
      LAYER M5 ;
        RECT  48.432 69.036 48.456 69.12 ;
    END
  END wb_reserve_sectors[5]
  PIN wb_reserve_sectors[6]
    DIRECTION OUTPUT ;
    USE SIGNAL ;
    PORT
      LAYER M5 ;
        RECT  48.528 69.036 48.552 69.12 ;
    END
  END wb_reserve_sectors[6]
  PIN wb_reserve_sectors[7]
    DIRECTION OUTPUT ;
    USE SIGNAL ;
    PORT
      LAYER M5 ;
        RECT  48.624 69.036 48.648 69.12 ;
    END
  END wb_reserve_sectors[7]
  PIN wb_reserve_sectors[8]
    DIRECTION OUTPUT ;
    USE SIGNAL ;
    PORT
      LAYER M5 ;
        RECT  48.72 69.036 48.744 69.12 ;
    END
  END wb_reserve_sectors[8]
  PIN wb_reserve_sectors[9]
    DIRECTION OUTPUT ;
    USE SIGNAL ;
    PORT
      LAYER M5 ;
        RECT  48.816 69.036 48.84 69.12 ;
    END
  END wb_reserve_sectors[9]
  PIN wb_reserve_v
    DIRECTION OUTPUT ;
    USE SIGNAL ;
    PORT
      LAYER M5 ;
        RECT  49.104 69.036 49.128 69.12 ;
    END
  END wb_reserve_v
  PIN VDD
    DIRECTION INOUT ;
    USE POWER ;
    PORT
      LAYER M5 ;
        RECT  61.992 2.151 62.112 66.969 ;
        RECT  56.592 2.151 56.712 66.969 ;
        RECT  51.192 2.151 51.312 66.969 ;
        RECT  45.792 2.151 45.912 66.969 ;
        RECT  40.392 2.151 40.512 66.969 ;
        RECT  34.992 2.151 35.112 66.969 ;
        RECT  29.592 2.151 29.712 66.969 ;
        RECT  24.192 2.151 24.312 66.969 ;
        RECT  18.792 2.151 18.912 66.969 ;
        RECT  13.392 2.151 13.512 66.969 ;
        RECT  7.992 2.151 8.112 66.969 ;
        RECT  2.592 2.151 2.712 66.969 ;
    END
  END VDD
  PIN VSS
    DIRECTION INOUT ;
    USE GROUND ;
    PORT
      LAYER M5 ;
        RECT  61.8 2.137 61.92 66.983 ;
        RECT  56.4 2.137 56.52 66.983 ;
        RECT  51 2.137 51.12 66.983 ;
        RECT  45.6 2.137 45.72 66.983 ;
        RECT  40.2 2.137 40.32 66.983 ;
        RECT  34.8 2.137 34.92 66.983 ;
        RECT  29.4 2.137 29.52 66.983 ;
        RECT  24 2.137 24.12 66.983 ;
        RECT  18.6 2.137 18.72 66.983 ;
        RECT  13.2 2.137 13.32 66.983 ;
        RECT  7.8 2.137 7.92 66.983 ;
        RECT  2.4 2.137 2.52 66.983 ;
    END
  END VSS
  OBS
    LAYER RVTN ;
     RECT  2.16 2.16 66.96 2.295 ;
     RECT  2.16 2.565 66.96 2.835 ;
     RECT  2.16 3.105 66.96 3.375 ;
     RECT  2.16 3.645 66.96 3.915 ;
     RECT  2.16 4.185 66.96 4.455 ;
     RECT  2.16 4.725 66.96 4.995 ;
     RECT  2.16 5.265 66.96 5.535 ;
     RECT  2.16 5.805 66.96 6.075 ;
     RECT  2.16 6.345 66.96 6.615 ;
     RECT  2.16 6.885 66.96 7.155 ;
     RECT  2.16 7.425 66.96 7.695 ;
     RECT  2.16 7.965 66.96 8.235 ;
     RECT  2.16 8.505 66.96 8.775 ;
     RECT  2.16 9.045 66.96 9.315 ;
     RECT  2.16 9.585 66.96 9.855 ;
     RECT  2.16 10.125 66.96 10.395 ;
     RECT  2.16 10.665 66.96 10.935 ;
     RECT  2.16 11.205 66.96 11.475 ;
     RECT  2.16 11.745 66.96 12.015 ;
     RECT  2.16 12.285 66.96 12.555 ;
     RECT  2.16 12.825 66.96 13.095 ;
     RECT  2.16 13.365 66.96 13.635 ;
     RECT  2.16 13.905 66.96 14.175 ;
     RECT  2.16 14.445 66.96 14.715 ;
     RECT  2.16 14.985 66.96 15.255 ;
     RECT  2.16 15.525 66.96 15.795 ;
     RECT  2.16 16.065 66.96 16.335 ;
     RECT  2.16 16.605 66.96 16.875 ;
     RECT  2.16 17.145 66.96 17.415 ;
     RECT  2.16 17.685 66.96 17.955 ;
     RECT  2.16 18.225 66.96 18.495 ;
     RECT  2.16 18.765 66.96 19.035 ;
     RECT  2.16 19.305 66.96 19.575 ;
     RECT  2.16 19.845 66.96 20.115 ;
     RECT  2.16 20.385 66.96 20.655 ;
     RECT  2.16 20.925 66.96 21.195 ;
     RECT  2.16 21.465 66.96 21.735 ;
     RECT  2.16 22.005 66.96 22.275 ;
     RECT  2.16 22.545 66.96 22.815 ;
     RECT  2.16 23.085 66.96 23.355 ;
     RECT  2.16 23.625 66.96 23.895 ;
     RECT  2.16 24.165 66.96 24.435 ;
     RECT  2.16 24.705 66.96 24.975 ;
     RECT  2.16 25.245 66.96 25.515 ;
     RECT  2.16 25.785 66.96 26.055 ;
     RECT  2.16 26.325 66.96 26.595 ;
     RECT  2.16 26.865 66.96 27.135 ;
     RECT  2.16 27.405 66.96 27.675 ;
     RECT  2.16 27.945 66.96 28.215 ;
     RECT  2.16 28.485 66.96 28.755 ;
     RECT  2.16 29.025 66.96 29.295 ;
     RECT  2.16 29.565 66.96 29.835 ;
     RECT  2.16 30.105 66.96 30.375 ;
     RECT  2.16 30.645 66.96 30.915 ;
     RECT  2.16 31.185 66.96 31.455 ;
     RECT  2.16 31.725 66.96 31.995 ;
     RECT  2.16 32.265 66.96 32.535 ;
     RECT  2.16 32.805 66.96 33.075 ;
     RECT  2.16 33.345 66.96 33.615 ;
     RECT  2.16 33.885 66.96 34.155 ;
     RECT  2.16 34.425 66.96 34.695 ;
     RECT  2.16 34.965 66.96 35.235 ;
     RECT  2.16 35.505 66.96 35.775 ;
     RECT  2.16 36.045 66.96 36.315 ;
     RECT  2.16 36.585 66.96 36.855 ;
     RECT  2.16 37.125 66.96 37.395 ;
     RECT  2.16 37.665 66.96 37.935 ;
     RECT  2.16 38.205 66.96 38.475 ;
     RECT  2.16 38.745 66.96 39.015 ;
     RECT  2.16 39.285 66.96 39.555 ;
     RECT  2.16 39.825 66.96 40.095 ;
     RECT  2.16 40.365 66.96 40.635 ;
     RECT  2.16 40.905 66.96 41.175 ;
     RECT  2.16 41.445 66.96 41.715 ;
     RECT  2.16 41.985 66.96 42.255 ;
     RECT  2.16 42.525 66.96 42.795 ;
     RECT  2.16 43.065 66.96 43.335 ;
     RECT  2.16 43.605 66.96 43.875 ;
     RECT  2.16 44.145 66.96 44.415 ;
     RECT  2.16 44.685 66.96 44.955 ;
     RECT  2.16 45.225 66.96 45.495 ;
     RECT  2.16 45.765 66.96 46.035 ;
     RECT  2.16 46.305 66.96 46.575 ;
     RECT  2.16 46.845 66.96 47.115 ;
     RECT  2.16 47.385 66.96 47.655 ;
     RECT  2.16 47.925 66.96 48.195 ;
     RECT  2.16 48.465 66.96 48.735 ;
     RECT  2.16 49.005 66.96 49.275 ;
     RECT  2.16 49.545 66.96 49.815 ;
     RECT  2.16 50.085 66.96 50.355 ;
     RECT  2.16 50.625 66.96 50.895 ;
     RECT  2.16 51.165 66.96 51.435 ;
     RECT  2.16 51.705 66.96 51.975 ;
     RECT  2.16 52.245 66.96 52.515 ;
     RECT  2.16 52.785 66.96 53.055 ;
     RECT  2.16 53.325 66.96 53.595 ;
     RECT  2.16 53.865 66.96 54.135 ;
     RECT  2.16 54.405 66.96 54.675 ;
     RECT  2.16 54.945 66.96 55.215 ;
     RECT  2.16 55.485 66.96 55.755 ;
     RECT  2.16 56.025 66.96 56.295 ;
     RECT  2.16 56.565 66.96 56.835 ;
     RECT  2.16 57.105 66.96 57.375 ;
     RECT  2.16 57.645 66.96 57.915 ;
     RECT  2.16 58.185 66.96 58.455 ;
     RECT  2.16 58.725 66.96 58.995 ;
     RECT  2.16 59.265 66.96 59.535 ;
     RECT  2.16 59.805 66.96 60.075 ;
     RECT  2.16 60.345 66.96 60.615 ;
     RECT  2.16 60.885 66.96 61.155 ;
     RECT  2.16 61.425 66.96 61.695 ;
     RECT  2.16 61.965 66.96 62.235 ;
     RECT  2.16 62.505 66.96 62.775 ;
     RECT  2.16 63.045 66.96 63.315 ;
     RECT  2.16 63.585 66.96 63.855 ;
     RECT  2.16 64.125 66.96 64.395 ;
     RECT  2.16 64.665 66.96 64.935 ;
     RECT  2.16 65.205 66.96 65.475 ;
     RECT  2.16 65.745 66.96 66.015 ;
     RECT  2.16 66.285 66.96 66.555 ;
     RECT  2.16 66.825 66.96 66.96 ;
    LAYER RVTP ;
     RECT  2.16 2.295 66.96 2.565 ;
     RECT  2.16 2.835 66.96 3.105 ;
     RECT  2.16 3.375 66.96 3.645 ;
     RECT  2.16 3.915 66.96 4.185 ;
     RECT  2.16 4.455 66.96 4.725 ;
     RECT  2.16 4.995 66.96 5.265 ;
     RECT  2.16 5.535 66.96 5.805 ;
     RECT  2.16 6.075 66.96 6.345 ;
     RECT  2.16 6.615 66.96 6.885 ;
     RECT  2.16 7.155 66.96 7.425 ;
     RECT  2.16 7.695 66.96 7.965 ;
     RECT  2.16 8.235 66.96 8.505 ;
     RECT  2.16 8.775 66.96 9.045 ;
     RECT  2.16 9.315 66.96 9.585 ;
     RECT  2.16 9.855 66.96 10.125 ;
     RECT  2.16 10.395 66.96 10.665 ;
     RECT  2.16 10.935 66.96 11.205 ;
     RECT  2.16 11.475 66.96 11.745 ;
     RECT  2.16 12.015 66.96 12.285 ;
     RECT  2.16 12.555 66.96 12.825 ;
     RECT  2.16 13.095 66.96 13.365 ;
     RECT  2.16 13.635 66.96 13.905 ;
     RECT  2.16 14.175 66.96 14.445 ;
     RECT  2.16 14.715 66.96 14.985 ;
     RECT  2.16 15.255 66.96 15.525 ;
     RECT  2.16 15.795 66.96 16.065 ;
     RECT  2.16 16.335 66.96 16.605 ;
     RECT  2.16 16.875 66.96 17.145 ;
     RECT  2.16 17.415 66.96 17.685 ;
     RECT  2.16 17.955 66.96 18.225 ;
     RECT  2.16 18.495 66.96 18.765 ;
     RECT  2.16 19.035 66.96 19.305 ;
     RECT  2.16 19.575 66.96 19.845 ;
     RECT  2.16 20.115 66.96 20.385 ;
     RECT  2.16 20.655 66.96 20.925 ;
     RECT  2.16 21.195 66.96 21.465 ;
     RECT  2.16 21.735 66.96 22.005 ;
     RECT  2.16 22.275 66.96 22.545 ;
     RECT  2.16 22.815 66.96 23.085 ;
     RECT  2.16 23.355 66.96 23.625 ;
     RECT  2.16 23.895 66.96 24.165 ;
     RECT  2.16 24.435 66.96 24.705 ;
     RECT  2.16 24.975 66.96 25.245 ;
     RECT  2.16 25.515 66.96 25.785 ;
     RECT  2.16 26.055 66.96 26.325 ;
     RECT  2.16 26.595 66.96 26.865 ;
     RECT  2.16 27.135 66.96 27.405 ;
     RECT  2.16 27.675 66.96 27.945 ;
     RECT  2.16 28.215 66.96 28.485 ;
     RECT  2.16 28.755 66.96 29.025 ;
     RECT  2.16 29.295 66.96 29.565 ;
     RECT  2.16 29.835 66.96 30.105 ;
     RECT  2.16 30.375 66.96 30.645 ;
     RECT  2.16 30.915 66.96 31.185 ;
     RECT  2.16 31.455 66.96 31.725 ;
     RECT  2.16 31.995 66.96 32.265 ;
     RECT  2.16 32.535 66.96 32.805 ;
     RECT  2.16 33.075 66.96 33.345 ;
     RECT  2.16 33.615 66.96 33.885 ;
     RECT  2.16 34.155 66.96 34.425 ;
     RECT  2.16 34.695 66.96 34.965 ;
     RECT  2.16 35.235 66.96 35.505 ;
     RECT  2.16 35.775 66.96 36.045 ;
     RECT  2.16 36.315 66.96 36.585 ;
     RECT  2.16 36.855 66.96 37.125 ;
     RECT  2.16 37.395 66.96 37.665 ;
     RECT  2.16 37.935 66.96 38.205 ;
     RECT  2.16 38.475 66.96 38.745 ;
     RECT  2.16 39.015 66.96 39.285 ;
     RECT  2.16 39.555 66.96 39.825 ;
     RECT  2.16 40.095 66.96 40.365 ;
     RECT  2.16 40.635 66.96 40.905 ;
     RECT  2.16 41.175 66.96 41.445 ;
     RECT  2.16 41.715 66.96 41.985 ;
     RECT  2.16 42.255 66.96 42.525 ;
     RECT  2.16 42.795 66.96 43.065 ;
     RECT  2.16 43.335 66.96 43.605 ;
     RECT  2.16 43.875 66.96 44.145 ;
     RECT  2.16 44.415 66.96 44.685 ;
     RECT  2.16 44.955 66.96 45.225 ;
     RECT  2.16 45.495 66.96 45.765 ;
     RECT  2.16 46.035 66.96 46.305 ;
     RECT  2.16 46.575 66.96 46.845 ;
     RECT  2.16 47.115 66.96 47.385 ;
     RECT  2.16 47.655 66.96 47.925 ;
     RECT  2.16 48.195 66.96 48.465 ;
     RECT  2.16 48.735 66.96 49.005 ;
     RECT  2.16 49.275 66.96 49.545 ;
     RECT  2.16 49.815 66.96 50.085 ;
     RECT  2.16 50.355 66.96 50.625 ;
     RECT  2.16 50.895 66.96 51.165 ;
     RECT  2.16 51.435 66.96 51.705 ;
     RECT  2.16 51.975 66.96 52.245 ;
     RECT  2.16 52.515 66.96 52.785 ;
     RECT  2.16 53.055 66.96 53.325 ;
     RECT  2.16 53.595 66.96 53.865 ;
     RECT  2.16 54.135 66.96 54.405 ;
     RECT  2.16 54.675 66.96 54.945 ;
     RECT  2.16 55.215 66.96 55.485 ;
     RECT  2.16 55.755 66.96 56.025 ;
     RECT  2.16 56.295 66.96 56.565 ;
     RECT  2.16 56.835 66.96 57.105 ;
     RECT  2.16 57.375 66.96 57.645 ;
     RECT  2.16 57.915 66.96 58.185 ;
     RECT  2.16 58.455 66.96 58.725 ;
     RECT  2.16 58.995 66.96 59.265 ;
     RECT  2.16 59.535 66.96 59.805 ;
     RECT  2.16 60.075 66.96 60.345 ;
     RECT  2.16 60.615 66.96 60.885 ;
     RECT  2.16 61.155 66.96 61.425 ;
     RECT  2.16 61.695 66.96 61.965 ;
     RECT  2.16 62.235 66.96 62.505 ;
     RECT  2.16 62.775 66.96 63.045 ;
     RECT  2.16 63.315 66.96 63.585 ;
     RECT  2.16 63.855 66.96 64.125 ;
     RECT  2.16 64.395 66.96 64.665 ;
     RECT  2.16 64.935 66.96 65.205 ;
     RECT  2.16 65.475 66.96 65.745 ;
     RECT  2.16 66.015 66.96 66.285 ;
     RECT  2.16 66.555 66.96 66.825 ;
    LAYER M1 ;
     RECT  2.16 2.151 66.96 66.969 ;
    LAYER M2 ;
     RECT  0.103 14.796 0.139 14.814 ;
     RECT  0.103 17.694 0.139 17.712 ;
     RECT  0.067 18.504 0.139 18.522 ;
     RECT  0.103 32.886 0.139 32.904 ;
     RECT  0.139 17.694 0.167 18.522 ;
     RECT  0.103 9.36 0.175 9.378 ;
     RECT  0.139 32.814 0.175 32.904 ;
     RECT  0.103 33.966 0.175 33.984 ;
     RECT  0.103 3.888 0.203 3.906 ;
     RECT  0.175 8.946 0.211 9.378 ;
     RECT  0.175 32.814 0.211 34.452 ;
     RECT  0.139 2.916 0.239 2.934 ;
     RECT  0.103 36.252 0.275 36.27 ;
     RECT  0.103 39.294 0.275 39.312 ;
     RECT  0.211 8.946 0.347 9.459 ;
     RECT  0.211 32.814 0.347 34.992 ;
     RECT  0.103 5.508 0.463 5.526 ;
     RECT  0.103 6.282 0.463 6.3 ;
     RECT  0.347 32.814 0.463 34.452 ;
     RECT  0.463 7.434 0.499 7.452 ;
     RECT  0.499 7.434 0.535 7.722 ;
     RECT  0.103 13.068 0.535 13.356 ;
     RECT  0.031 22.788 0.535 23.184 ;
     RECT  0.067 21.546 0.859 21.564 ;
     RECT  0.535 12.33 1.111 13.356 ;
     RECT  0.463 5.508 1.147 6.3 ;
     RECT  0.535 7.092 1.147 7.722 ;
     RECT  0.167 17.694 1.147 17.982 ;
     RECT  0.859 21.24 1.147 21.564 ;
     RECT  0.139 14.724 1.183 14.814 ;
     RECT  0.139 16.146 1.183 16.164 ;
     RECT  1.147 17.496 1.183 17.982 ;
     RECT  1.183 14.724 1.283 16.164 ;
     RECT  1.723 19.386 1.759 19.404 ;
     RECT  1.723 37.368 1.759 37.386 ;
     RECT  1.759 19.386 1.831 19.674 ;
     RECT  1.147 20.664 1.831 21.564 ;
     RECT  1.831 19.386 1.867 21.564 ;
     RECT  2.083 36.018 2.155 36.036 ;
     RECT  0.571 2.88 2.16 2.898 ;
     RECT  1.147 5.508 2.16 7.722 ;
     RECT  0.347 8.946 2.16 8.964 ;
     RECT  0.535 11.178 2.16 11.196 ;
     RECT  1.111 12.024 2.16 13.356 ;
     RECT  1.283 14.724 2.16 14.814 ;
     RECT  1.283 16.146 2.16 16.164 ;
     RECT  1.183 17.496 2.16 18.054 ;
     RECT  1.867 19.116 2.16 21.564 ;
     RECT  0.535 22.554 2.16 23.184 ;
     RECT  0.463 32.616 2.16 34.452 ;
     RECT  2.155 35.406 2.16 36.036 ;
     RECT  1.759 37.206 2.16 37.386 ;
     RECT  2.16 2.151 2.299 66.969 ;
     RECT  2.299 1.998 4.235 66.969 ;
     RECT  4.235 2.034 8.195 66.969 ;
     RECT  8.195 2.151 26.779 66.969 ;
     RECT  26.779 2.106 31.739 66.969 ;
     RECT  31.739 2.151 45.319 66.969 ;
     RECT  45.319 2.151 46.499 67.014 ;
     RECT  46.499 2.151 50.359 66.969 ;
     RECT  50.359 2.151 50.963 67.014 ;
     RECT  50.963 2.151 53.455 66.969 ;
     RECT  53.455 2.151 54.491 67.014 ;
     RECT  54.491 2.151 55.363 66.969 ;
     RECT  55.363 2.106 56.623 66.969 ;
     RECT  56.623 2.034 57.335 66.969 ;
     RECT  57.335 2.106 58.559 66.969 ;
     RECT  58.559 2.151 59.971 66.969 ;
     RECT  59.971 2.106 60.403 66.969 ;
     RECT  60.403 2.106 60.763 67.014 ;
     RECT  60.763 2.106 61.403 67.122 ;
     RECT  61.403 2.151 61.987 67.122 ;
     RECT  61.987 2.151 63.311 67.158 ;
     RECT  63.311 2.151 64.283 67.122 ;
     RECT  64.283 2.151 64.579 67.05 ;
     RECT  64.579 2.106 65.471 67.05 ;
     RECT  65.471 2.151 66.96 67.05 ;
     RECT  66.96 6.084 66.983 9.576 ;
     RECT  66.96 42.606 66.983 42.624 ;
     RECT  66.96 49.518 66.983 49.536 ;
     RECT  66.96 55.8 66.983 67.05 ;
     RECT  66.983 6.084 67.019 6.264 ;
     RECT  66.96 31.968 67.019 36.846 ;
     RECT  66.96 4.536 67.055 5.328 ;
     RECT  67.055 4.896 67.091 4.914 ;
     RECT  67.019 6.246 67.091 6.264 ;
     RECT  67.019 36.828 67.235 36.846 ;
     RECT  66.96 10.332 67.271 30.708 ;
     RECT  66.96 52.794 67.271 53.694 ;
     RECT  66.983 7.164 67.307 9.576 ;
     RECT  67.271 10.332 67.307 30.132 ;
     RECT  66.96 50.4 67.307 52.002 ;
     RECT  66.983 55.8 67.307 65.034 ;
     RECT  66.96 2.646 67.415 3.204 ;
     RECT  67.415 2.646 67.451 2.934 ;
     RECT  67.307 7.164 67.451 7.254 ;
     RECT  67.451 7.236 67.487 7.254 ;
     RECT  67.307 60.66 67.487 65.034 ;
     RECT  67.307 8.046 67.523 9.576 ;
     RECT  67.451 2.646 67.559 2.664 ;
     RECT  67.523 8.478 67.559 9.576 ;
     RECT  67.307 20.088 67.559 30.132 ;
     RECT  67.019 31.968 67.739 35.766 ;
     RECT  67.307 55.8 67.739 56.592 ;
     RECT  67.559 20.088 67.775 29.934 ;
     RECT  67.307 10.332 67.811 19.332 ;
     RECT  67.775 20.124 67.811 22.104 ;
     RECT  67.775 23.436 67.811 29.934 ;
     RECT  67.739 31.968 67.811 35.496 ;
     RECT  67.271 53.568 67.811 53.694 ;
     RECT  67.307 57.348 67.811 59.526 ;
     RECT  67.811 10.332 67.847 16.938 ;
     RECT  67.811 21.204 67.847 22.068 ;
     RECT  67.811 31.968 67.847 33.174 ;
     RECT  67.307 51.984 67.847 52.002 ;
     RECT  67.811 57.924 67.847 59.526 ;
     RECT  67.487 60.66 67.847 60.912 ;
     RECT  66.983 65.826 67.847 67.05 ;
     RECT  67.847 10.332 67.883 12.852 ;
     RECT  67.847 13.914 67.883 16.938 ;
     RECT  67.847 32.346 67.883 32.364 ;
     RECT  67.847 59.346 67.919 59.526 ;
     RECT  67.847 60.741 67.919 60.912 ;
     RECT  67.847 57.924 67.991 58.518 ;
     RECT  67.919 60.822 67.991 60.912 ;
     RECT  67.487 61.668 67.991 65.034 ;
     RECT  67.307 50.4 68.099 50.994 ;
     RECT  66.96 54.99 68.099 55.008 ;
     RECT  67.883 10.98 68.135 12.852 ;
     RECT  67.811 25.02 68.351 27.936 ;
     RECT  68.135 10.98 68.387 12.546 ;
     RECT  67.811 17.766 68.387 19.332 ;
     RECT  67.847 21.24 68.387 22.068 ;
     RECT  68.351 25.02 68.387 27.774 ;
     RECT  67.811 29.538 68.387 29.934 ;
     RECT  67.811 53.676 68.387 53.694 ;
     RECT  67.919 59.508 68.387 59.526 ;
     RECT  67.991 61.668 68.387 61.794 ;
     RECT  67.847 65.988 68.387 67.05 ;
     RECT  67.559 8.478 68.423 9.108 ;
     RECT  68.387 10.98 68.423 11.808 ;
     RECT  67.883 14.454 68.423 16.938 ;
     RECT  67.811 20.124 68.423 20.142 ;
     RECT  67.811 34.164 68.423 35.064 ;
     RECT  67.739 55.998 68.423 56.592 ;
     RECT  67.991 60.894 68.423 60.912 ;
     RECT  68.387 66.87 68.423 67.05 ;
     RECT  68.423 9.09 68.459 9.108 ;
     RECT  67.991 58.122 68.459 58.518 ;
     RECT  67.991 62.55 68.495 65.034 ;
     RECT  68.423 55.998 68.891 56.25 ;
     RECT  68.423 15.804 68.927 16.938 ;
     RECT  68.387 17.766 68.927 18.324 ;
     RECT  68.459 58.5 68.927 58.518 ;
     RECT  68.495 62.55 68.927 63.999 ;
     RECT  67.271 52.794 68.935 52.812 ;
     RECT  68.495 64.944 68.935 65.034 ;
     RECT  68.423 10.98 68.963 11.268 ;
     RECT  68.387 26.298 68.963 27.738 ;
     RECT  68.963 11.214 68.999 11.268 ;
     RECT  68.927 16.146 68.999 16.938 ;
     RECT  68.927 17.964 68.999 18.324 ;
     RECT  68.387 21.51 68.999 22.068 ;
     RECT  68.387 25.02 68.999 25.236 ;
     RECT  68.423 34.164 68.999 35.028 ;
     RECT  68.935 52.56 68.999 52.812 ;
     RECT  68.891 55.998 68.999 56.016 ;
     RECT  68.387 61.668 68.999 61.686 ;
     RECT  68.927 62.55 68.999 62.568 ;
     RECT  68.927 63.396 68.999 63.999 ;
     RECT  68.935 64.944 68.999 65.232 ;
     RECT  68.999 11.25 69.035 11.268 ;
     RECT  68.423 15.03 69.035 15.048 ;
     RECT  68.999 16.416 69.035 16.938 ;
     RECT  68.999 17.964 69.035 17.982 ;
     RECT  68.999 21.51 69.035 22.032 ;
     RECT  67.811 23.436 69.035 23.454 ;
     RECT  67.811 24.246 69.035 24.264 ;
     RECT  68.999 25.218 69.035 25.236 ;
     RECT  68.963 26.406 69.035 27.504 ;
     RECT  68.387 29.538 69.035 29.556 ;
     RECT  67.847 33.156 69.035 33.174 ;
     RECT  68.999 34.164 69.035 34.758 ;
     RECT  68.099 50.976 69.035 50.994 ;
     RECT  68.999 52.56 69.035 52.578 ;
     RECT  68.999 63.396 69.035 63.81 ;
     RECT  68.999 65.214 69.035 65.232 ;
     RECT  68.387 65.988 69.035 66.006 ;
     RECT  68.423 67.032 69.035 67.05 ;
     RECT  68.971 57.006 69.071 57.024 ;
     RECT  69.035 63.792 69.071 63.81 ;
    LAYER M3 ;
     RECT  67.5 0.091 67.518 0.139 ;
     RECT  56.376 0.427 56.394 0.475 ;
     RECT  56.232 0.475 56.394 0.523 ;
     RECT  60.912 0.091 60.93 0.523 ;
     RECT  62.604 0.523 62.622 0.571 ;
     RECT  66.132 0.091 66.15 0.571 ;
     RECT  66.996 0.139 67.518 0.571 ;
     RECT  56.232 0.523 56.574 0.619 ;
     RECT  59.292 0.571 59.31 1.099 ;
     RECT  60.264 0.523 60.93 1.147 ;
     RECT  61.74 0.523 61.758 1.147 ;
     RECT  59.292 1.099 59.49 1.723 ;
     RECT  60.264 1.147 61.758 1.723 ;
     RECT  62.532 0.571 62.622 1.723 ;
     RECT  63.648 0.571 63.666 1.723 ;
     RECT  64.404 0.091 64.422 1.723 ;
     RECT  65.232 0.139 65.25 1.723 ;
     RECT  62.532 1.723 63.666 1.771 ;
     RECT  64.404 1.723 65.25 1.771 ;
     RECT  66.132 0.571 67.518 1.771 ;
     RECT  3.708 1.867 3.726 1.963 ;
     RECT  2.34 1.579 2.358 1.993 ;
     RECT  3.636 1.963 3.726 1.993 ;
     RECT  4.5 1.771 4.518 1.993 ;
     RECT  58.608 1.723 61.794 2.011 ;
     RECT  62.532 1.771 65.25 2.011 ;
     RECT  56.232 0.619 56.754 2.029 ;
     RECT  57.528 1.723 57.546 2.029 ;
     RECT  2.304 1.993 2.358 2.065 ;
     RECT  58.608 2.011 65.25 2.101 ;
     RECT  66.096 1.771 67.518 2.101 ;
     RECT  8.172 2.029 8.19 2.143 ;
     RECT  0.576 2.059 0.594 2.155 ;
     RECT  58.536 2.101 67.518 2.155 ;
     RECT  3.636 1.993 4.518 2.191 ;
     RECT  5.328 1.675 5.346 2.191 ;
     RECT  6.48 2.101 6.498 2.191 ;
     RECT  7.815 2.143 8.19 2.191 ;
     RECT  56.232 2.029 57.546 2.191 ;
     RECT  58.284 2.155 67.518 2.191 ;
     RECT  2.304 2.065 2.754 2.251 ;
     RECT  3.636 2.191 5.346 2.251 ;
     RECT  6.408 2.191 6.498 2.263 ;
     RECT  7.488 2.191 8.19 2.263 ;
     RECT  24.015 2.143 24.105 2.263 ;
     RECT  29.415 2.143 29.505 2.263 ;
     RECT  34.815 2.143 34.905 2.263 ;
     RECT  40.215 2.143 40.305 2.263 ;
     RECT  45.615 2.143 45.705 2.263 ;
     RECT  46.836 2.191 46.854 2.263 ;
     RECT  55.368 2.101 55.386 2.263 ;
     RECT  56.232 2.191 67.518 2.263 ;
     RECT  34.815 2.263 35.658 2.299 ;
     RECT  41.076 2.263 41.49 2.299 ;
     RECT  42.768 2.191 42.786 2.299 ;
     RECT  43.704 2.227 43.83 2.299 ;
     RECT  2.304 2.251 5.346 2.335 ;
     RECT  6.12 2.263 8.19 2.335 ;
     RECT  29.268 2.263 29.754 2.335 ;
     RECT  2.304 2.335 8.19 2.371 ;
     RECT  9.648 2.335 9.666 2.371 ;
     RECT  18.615 2.143 18.705 2.371 ;
     RECT  19.692 2.335 19.89 2.371 ;
     RECT  25.74 2.227 25.758 2.371 ;
     RECT  26.784 2.101 26.802 2.371 ;
     RECT  31.716 2.101 31.734 2.371 ;
     RECT  33.156 2.263 33.174 2.371 ;
     RECT  34.815 2.299 35.766 2.371 ;
     RECT  38.412 2.251 38.43 2.371 ;
     RECT  40.14 2.263 40.305 2.371 ;
     RECT  42.768 2.299 43.83 2.371 ;
     RECT  13.215 2.143 13.305 2.413 ;
     RECT  39.996 2.371 40.305 2.413 ;
     RECT  41.076 2.299 41.742 2.413 ;
     RECT  45.216 2.263 45.705 2.413 ;
     RECT  46.548 2.263 46.854 2.413 ;
     RECT  51.015 2.143 51.105 2.413 ;
     RECT  2.268 2.371 8.406 2.461 ;
     RECT  9.648 2.371 9.882 2.461 ;
     RECT  18.615 2.371 20.574 2.461 ;
     RECT  21.348 2.371 21.366 2.461 ;
     RECT  25.74 2.371 26.802 2.461 ;
     RECT  31.392 2.371 31.734 2.461 ;
     RECT  39.996 2.413 41.742 2.461 ;
     RECT  48.384 2.371 48.402 2.461 ;
     RECT  51.015 2.413 51.297 2.461 ;
     RECT  10.656 2.371 10.674 2.489 ;
     RECT  38.412 2.371 38.61 2.491 ;
     RECT  24.015 2.263 24.426 2.497 ;
     RECT  31.392 2.461 31.806 2.497 ;
     RECT  42.768 2.371 43.902 2.497 ;
     RECT  45.216 2.413 46.854 2.497 ;
     RECT  50.4 2.461 51.297 2.497 ;
     RECT  25.344 2.461 26.982 2.569 ;
     RECT  27.756 2.371 27.774 2.569 ;
     RECT  31.392 2.497 31.986 2.569 ;
     RECT  32.976 2.371 33.174 2.569 ;
     RECT  34.815 2.371 35.874 2.569 ;
     RECT  37.944 2.491 38.61 2.569 ;
     RECT  18.615 2.461 21.366 2.605 ;
     RECT  22.68 2.497 22.698 2.605 ;
     RECT  31.392 2.569 33.174 2.605 ;
     RECT  34.776 2.569 35.874 2.605 ;
     RECT  37.944 2.569 38.79 2.605 ;
     RECT  39.888 2.461 41.742 2.605 ;
     RECT  42.768 2.497 46.854 2.605 ;
     RECT  48.384 2.461 49.41 2.605 ;
     RECT  50.256 2.497 51.297 2.605 ;
     RECT  47.916 2.605 49.41 2.635 ;
     RECT  2.268 2.461 9.882 2.641 ;
     RECT  10.944 2.605 10.962 2.641 ;
     RECT  18.615 2.605 21.51 2.641 ;
     RECT  25.236 2.569 27.774 2.641 ;
     RECT  31.248 2.605 33.174 2.641 ;
     RECT  34.776 2.605 36.234 2.641 ;
     RECT  37.944 2.605 46.854 2.641 ;
     RECT  47.628 2.635 49.41 2.641 ;
     RECT  50.256 2.605 51.858 2.641 ;
     RECT  54.504 2.605 54.522 2.641 ;
     RECT  55.368 2.263 67.518 2.641 ;
     RECT  18.108 2.641 21.51 2.731 ;
     RECT  23.94 2.497 24.426 2.731 ;
     RECT  25.236 2.641 27.882 2.731 ;
     RECT  2.268 2.641 10.206 2.759 ;
     RECT  23.94 2.731 27.882 2.767 ;
     RECT  29.088 2.335 29.754 2.767 ;
     RECT  37.944 2.641 49.518 2.767 ;
     RECT  50.256 2.641 52.11 2.767 ;
     RECT  17.172 2.641 17.334 2.803 ;
     RECT  22.68 2.605 22.878 2.803 ;
     RECT  23.94 2.767 29.754 2.803 ;
     RECT  30.528 2.641 33.174 2.803 ;
     RECT  34.776 2.641 36.954 2.803 ;
     RECT  54.504 2.641 67.554 2.803 ;
     RECT  17.1 2.803 17.37 2.839 ;
     RECT  16.956 2.839 17.37 2.86 ;
     RECT  18.108 2.731 21.582 2.86 ;
     RECT  0.324 2.155 0.594 2.875 ;
     RECT  23.94 2.803 33.174 2.875 ;
     RECT  34.776 2.803 37.026 2.875 ;
     RECT  37.944 2.767 52.11 2.875 ;
     RECT  0.216 2.875 0.594 2.903 ;
     RECT  0.216 2.903 0.234 2.911 ;
     RECT  14.832 2.839 14.85 2.911 ;
     RECT  34.776 2.875 52.11 2.911 ;
     RECT  52.848 2.533 52.866 2.911 ;
     RECT  0.144 2.911 0.234 2.939 ;
     RECT  16.956 2.86 21.582 2.939 ;
     RECT  0.144 2.939 0.162 2.957 ;
     RECT  14.832 2.911 14.886 3.001 ;
     RECT  54.18 2.803 67.554 3.001 ;
     RECT  14.724 3.001 14.886 3.073 ;
     RECT  34.776 2.911 53.046 3.109 ;
     RECT  13.215 2.413 13.497 3.145 ;
     RECT  22.5 2.803 22.878 3.145 ;
     RECT  23.832 2.875 33.174 3.145 ;
     RECT  34.776 3.109 53.298 3.149 ;
     RECT  13.104 3.145 13.497 3.181 ;
     RECT  14.292 3.073 14.886 3.181 ;
     RECT  16.02 3.019 16.038 3.181 ;
     RECT  22.428 3.145 22.878 3.181 ;
     RECT  23.688 3.145 33.174 3.181 ;
     RECT  33.984 2.641 34.002 3.181 ;
     RECT  34.776 3.149 38.682 3.181 ;
     RECT  22.428 3.181 33.174 3.209 ;
     RECT  39.492 3.149 53.298 3.209 ;
     RECT  31.392 3.209 33.174 3.299 ;
     RECT  39.492 3.209 46.962 3.299 ;
     RECT  47.736 3.209 53.298 3.299 ;
     RECT  13.104 3.181 14.886 3.307 ;
     RECT  16.02 3.181 16.182 3.307 ;
     RECT  31.68 3.299 33.174 3.343 ;
     RECT  10.944 2.641 11.43 3.379 ;
     RECT  13.104 3.307 16.182 3.415 ;
     RECT  16.956 2.939 21.546 3.415 ;
     RECT  10.944 3.379 11.97 3.445 ;
     RECT  13.104 3.415 21.546 3.445 ;
     RECT  31.68 3.343 33.246 3.451 ;
     RECT  33.984 3.181 38.682 3.451 ;
     RECT  31.68 3.451 38.682 3.479 ;
     RECT  10.944 3.445 21.546 3.499 ;
     RECT  31.68 3.479 36.306 3.569 ;
     RECT  10.692 3.499 21.546 3.605 ;
     RECT  47.772 3.299 53.298 3.649 ;
     RECT  54.144 3.001 67.554 3.649 ;
     RECT  2.304 2.759 9.882 3.721 ;
     RECT  10.692 3.605 11.25 3.721 ;
     RECT  22.428 3.209 30.546 3.749 ;
     RECT  26.532 3.749 30.546 3.839 ;
     RECT  12.024 3.605 21.546 3.847 ;
     RECT  0.216 3.787 0.234 3.868 ;
     RECT  12.024 3.847 21.69 3.883 ;
     RECT  22.428 3.749 25.794 3.883 ;
     RECT  39.492 3.299 46.89 3.947 ;
     RECT  37.044 3.479 38.682 3.955 ;
     RECT  39.492 3.947 46.386 3.955 ;
     RECT  26.604 3.839 30.546 4.075 ;
     RECT  47.772 3.649 67.554 4.075 ;
     RECT  0.108 3.868 0.234 4.109 ;
     RECT  37.044 3.955 46.386 4.109 ;
     RECT  26.604 4.075 30.87 4.225 ;
     RECT  31.716 3.569 36.306 4.267 ;
     RECT  37.044 4.109 44.19 4.267 ;
     RECT  0.144 4.109 0.234 4.363 ;
     RECT  31.716 4.267 44.19 4.379 ;
     RECT  12.024 3.883 25.794 4.487 ;
     RECT  0.144 4.363 0.342 4.493 ;
     RECT  2.304 3.721 11.25 4.507 ;
     RECT  12.024 4.487 20.646 4.507 ;
     RECT  26.604 4.225 30.906 4.531 ;
     RECT  31.716 4.379 33.426 4.531 ;
     RECT  47.736 4.075 67.554 4.531 ;
     RECT  2.304 4.507 20.646 4.919 ;
     RECT  0.144 4.493 0.162 4.939 ;
     RECT  21.672 4.487 25.794 4.999 ;
     RECT  26.604 4.531 33.426 4.999 ;
     RECT  47.556 4.531 67.554 5.035 ;
     RECT  21.672 4.999 33.426 5.131 ;
     RECT  45.072 4.109 46.386 5.131 ;
     RECT  2.304 4.919 20.61 5.189 ;
     RECT  21.672 5.131 33.462 5.197 ;
     RECT  47.412 5.035 67.554 5.261 ;
     RECT  44.928 5.131 46.386 5.275 ;
     RECT  47.412 5.261 51.786 5.275 ;
     RECT  44.928 5.275 51.786 5.297 ;
     RECT  2.304 5.189 20.502 5.323 ;
     RECT  21.672 5.197 33.498 5.341 ;
     RECT  34.38 4.379 44.19 5.341 ;
     RECT  1.728 5.323 20.502 5.369 ;
     RECT  52.704 5.261 67.554 5.369 ;
     RECT  1.728 5.369 20.43 5.515 ;
     RECT  0.108 4.939 0.162 5.531 ;
     RECT  1.152 5.515 20.43 5.611 ;
     RECT  0.468 5.611 20.43 5.729 ;
     RECT  21.672 5.341 44.19 5.971 ;
     RECT  21.6 5.971 44.19 6.115 ;
     RECT  44.928 5.297 51.57 6.115 ;
     RECT  21.348 6.115 44.19 6.151 ;
     RECT  44.928 6.115 52.146 6.151 ;
     RECT  0.468 5.729 20.394 6.277 ;
     RECT  0.108 6.277 20.394 6.377 ;
     RECT  1.728 6.377 20.394 6.449 ;
     RECT  2.268 6.449 20.394 6.509 ;
     RECT  21.348 6.151 52.146 6.511 ;
     RECT  21.204 6.511 52.146 6.547 ;
     RECT  52.992 5.369 67.554 6.547 ;
     RECT  21.204 6.547 67.554 6.691 ;
     RECT  2.304 6.509 20.394 6.889 ;
     RECT  21.132 6.691 67.554 6.889 ;
     RECT  2.304 6.889 67.554 7.531 ;
     RECT  0.108 6.377 0.558 7.949 ;
     RECT  0.144 7.949 0.558 8.141 ;
     RECT  2.268 7.531 67.554 8.159 ;
     RECT  0.144 8.141 0.522 8.237 ;
     RECT  0.144 8.237 0.486 8.429 ;
     RECT  2.304 8.159 67.554 8.851 ;
     RECT  68.4 8.473 68.418 8.851 ;
     RECT  2.304 8.851 68.418 9.085 ;
     RECT  0.144 8.429 0.198 9.163 ;
     RECT  0.144 9.163 0.342 9.259 ;
     RECT  0.108 9.259 0.342 9.383 ;
     RECT  0.144 9.383 0.342 9.485 ;
     RECT  2.304 9.085 68.454 9.643 ;
     RECT  0.144 9.485 0.198 9.773 ;
     RECT  0.144 9.773 0.162 10.109 ;
     RECT  2.268 9.643 68.454 10.315 ;
     RECT  2.268 10.315 69.03 10.391 ;
     RECT  2.304 10.391 69.03 10.445 ;
     RECT  2.304 10.445 68.13 10.541 ;
     RECT  2.34 10.541 68.13 10.589 ;
     RECT  2.34 10.589 35.154 10.637 ;
     RECT  68.904 10.445 69.03 10.733 ;
     RECT  68.94 10.733 69.03 11.003 ;
     RECT  68.976 11.003 69.03 11.273 ;
     RECT  2.34 10.637 35.097 11.515 ;
     RECT  35.892 10.589 68.13 11.515 ;
     RECT  0.54 11.173 0.558 11.597 ;
     RECT  2.34 11.515 68.13 11.785 ;
     RECT  2.34 11.785 68.418 11.821 ;
     RECT  2.304 11.821 68.418 11.975 ;
     RECT  0.324 11.851 0.342 11.981 ;
     RECT  41.364 11.975 68.418 12.283 ;
     RECT  1.116 12.019 1.134 12.325 ;
     RECT  2.304 11.975 40.554 12.427 ;
     RECT  41.364 12.283 68.958 12.461 ;
     RECT  1.98 12.427 40.554 12.605 ;
     RECT  2.232 12.605 40.554 12.757 ;
     RECT  41.364 12.461 68.418 12.757 ;
     RECT  0.54 12.325 1.134 13.037 ;
     RECT  2.232 12.757 68.418 13.133 ;
     RECT  2.304 13.133 68.418 13.325 ;
     RECT  2.304 13.325 66.834 13.373 ;
     RECT  41.364 13.373 66.834 13.517 ;
     RECT  67.788 13.325 68.418 13.517 ;
     RECT  0.108 13.063 0.342 13.613 ;
     RECT  0.108 13.613 0.162 13.805 ;
     RECT  1.116 13.037 1.134 13.901 ;
     RECT  2.304 13.373 40.626 14.215 ;
     RECT  41.364 13.517 66.762 14.215 ;
     RECT  67.788 13.517 67.878 14.441 ;
     RECT  2.304 14.215 66.762 14.443 ;
     RECT  69.012 13.675 69.03 14.449 ;
     RECT  0.144 13.805 0.162 14.539 ;
     RECT  0.144 14.539 0.198 14.791 ;
     RECT  0.108 14.791 0.198 14.861 ;
     RECT  0.144 14.861 0.198 14.957 ;
     RECT  0.18 14.957 0.198 15.053 ;
     RECT  68.4 14.449 69.03 15.053 ;
     RECT  2.304 14.443 67.374 15.179 ;
     RECT  2.304 15.179 16.182 15.323 ;
     RECT  1.152 15.115 1.17 15.403 ;
     RECT  1.152 15.403 1.206 15.421 ;
     RECT  1.152 15.421 1.278 15.485 ;
     RECT  68.4 15.053 68.994 15.629 ;
     RECT  2.304 15.323 16.146 15.691 ;
     RECT  16.956 15.179 67.374 15.719 ;
     RECT  2.268 15.691 16.146 15.728 ;
     RECT  2.304 15.728 16.146 15.899 ;
     RECT  50.256 15.719 67.374 15.979 ;
     RECT  0.144 15.739 0.162 16.075 ;
     RECT  68.904 15.629 68.994 16.267 ;
     RECT  16.956 15.719 49.446 16.501 ;
     RECT  50.256 15.979 67.842 16.573 ;
     RECT  0.108 16.075 0.162 16.603 ;
     RECT  50.256 16.573 67.878 16.747 ;
     RECT  68.904 16.267 69.03 16.747 ;
     RECT  16.956 16.501 49.518 16.807 ;
     RECT  50.256 16.747 69.03 16.807 ;
     RECT  2.304 15.899 15.786 16.879 ;
     RECT  16.956 16.807 69.03 16.943 ;
     RECT  16.956 16.943 68.994 17.105 ;
     RECT  1.152 15.485 1.206 17.131 ;
     RECT  2.304 16.879 16.002 17.131 ;
     RECT  0.108 16.603 0.234 17.323 ;
     RECT  0.108 17.323 0.342 17.453 ;
     RECT  1.152 17.131 16.002 17.581 ;
     RECT  1.152 17.581 16.11 17.707 ;
     RECT  0.108 17.453 0.198 17.717 ;
     RECT  32.616 17.105 68.994 17.803 ;
     RECT  1.152 17.707 16.218 17.879 ;
     RECT  16.956 17.105 31.878 17.923 ;
     RECT  32.616 17.803 69.03 17.923 ;
     RECT  16.956 17.923 69.03 17.987 ;
     RECT  0.144 17.717 0.198 18.187 ;
     RECT  1.152 17.879 16.182 18.187 ;
     RECT  16.956 17.987 68.994 18.329 ;
     RECT  0.144 18.187 16.182 18.499 ;
     RECT  16.956 18.329 68.958 19.037 ;
     RECT  16.956 19.037 68.382 19.337 ;
     RECT  0.072 18.499 16.182 19.651 ;
     RECT  16.956 19.337 67.806 19.651 ;
     RECT  0.072 19.651 67.806 19.769 ;
     RECT  0.072 19.769 16.182 19.841 ;
     RECT  16.956 19.769 67.806 19.841 ;
     RECT  0.072 19.841 16.146 19.913 ;
     RECT  67.644 19.841 67.806 20.119 ;
     RECT  67.644 20.119 68.418 20.723 ;
     RECT  67.752 20.723 68.418 20.779 ;
     RECT  0.072 19.913 16.11 21.029 ;
     RECT  16.956 19.841 66.834 21.227 ;
     RECT  67.752 20.779 69.03 21.389 ;
     RECT  67.752 21.389 67.842 21.451 ;
     RECT  2.232 21.029 16.11 21.497 ;
     RECT  0.072 21.029 1.458 21.569 ;
     RECT  14.508 21.497 16.11 21.631 ;
     RECT  67.716 21.451 67.842 21.677 ;
     RECT  27.36 21.227 66.834 21.739 ;
     RECT  27.36 21.739 66.978 21.973 ;
     RECT  67.716 21.677 67.806 21.973 ;
     RECT  16.956 21.227 26.514 22.009 ;
     RECT  27.36 21.973 67.806 22.009 ;
     RECT  68.94 21.389 69.03 22.037 ;
     RECT  68.94 22.037 68.994 22.073 ;
     RECT  14.508 21.631 16.218 22.081 ;
     RECT  16.956 22.009 67.806 22.081 ;
     RECT  2.232 21.497 13.626 22.477 ;
     RECT  14.508 22.081 67.806 22.477 ;
     RECT  2.232 22.477 67.806 22.505 ;
     RECT  0.288 21.569 1.458 22.649 ;
     RECT  0.288 22.649 0.846 22.739 ;
     RECT  0.288 22.739 0.306 22.783 ;
     RECT  2.415 22.505 67.806 22.795 ;
     RECT  68.94 22.073 68.958 22.795 ;
     RECT  0.036 22.783 0.306 22.811 ;
     RECT  2.415 22.795 68.958 22.811 ;
     RECT  3.924 22.811 68.958 22.891 ;
     RECT  2.415 22.811 3.006 23.009 ;
     RECT  3.924 22.891 69.03 23.153 ;
     RECT  0.036 22.811 0.054 23.189 ;
     RECT  49.5 23.153 69.03 23.189 ;
     RECT  2.415 23.009 2.934 23.279 ;
     RECT  2.415 23.279 2.79 23.315 ;
     RECT  3.924 23.153 48.366 23.899 ;
     RECT  49.536 23.189 69.03 24.061 ;
     RECT  3.924 23.899 48.438 24.169 ;
     RECT  49.176 24.061 69.03 24.169 ;
     RECT  3.924 24.169 69.03 24.269 ;
     RECT  3.924 24.269 68.994 24.745 ;
     RECT  3.636 24.745 68.994 24.781 ;
     RECT  2.415 23.315 2.697 24.901 ;
     RECT  3.42 24.781 68.994 24.901 ;
     RECT  2.415 24.901 68.994 24.907 ;
     RECT  2.376 24.907 68.994 25.099 ;
     RECT  2.376 25.099 69.03 25.241 ;
     RECT  2.376 25.241 68.958 25.709 ;
     RECT  2.415 25.709 68.958 25.853 ;
     RECT  2.415 25.853 66.834 25.979 ;
     RECT  67.644 25.853 68.958 26.155 ;
     RECT  2.415 25.979 66.726 26.789 ;
     RECT  2.415 26.789 46.674 26.825 ;
     RECT  67.644 26.155 69.03 26.861 ;
     RECT  47.52 26.789 66.726 26.905 ;
     RECT  47.52 26.905 67.302 27.053 ;
     RECT  2.415 26.825 46.638 27.409 ;
     RECT  68.364 26.861 69.03 27.509 ;
     RECT  2.34 27.409 46.638 27.571 ;
     RECT  68.364 27.509 68.958 27.595 ;
     RECT  2.34 27.571 46.71 27.643 ;
     RECT  68.328 27.595 68.958 27.691 ;
     RECT  2.34 27.643 46.746 27.715 ;
     RECT  47.52 27.053 66.726 27.715 ;
     RECT  2.34 27.715 66.726 27.743 ;
     RECT  67.788 27.691 68.958 27.743 ;
     RECT  67.788 27.743 68.382 27.979 ;
     RECT  2.415 27.743 66.726 28.021 ;
     RECT  67.752 27.979 68.382 28.075 ;
     RECT  67.716 28.075 68.382 28.171 ;
     RECT  2.415 28.021 66.762 28.255 ;
     RECT  2.415 28.255 66.834 28.651 ;
     RECT  67.68 28.171 68.382 28.651 ;
     RECT  2.415 28.651 68.382 28.843 ;
     RECT  2.415 28.843 69.03 29.029 ;
     RECT  2.34 29.029 69.03 29.363 ;
     RECT  68.364 29.363 69.03 29.561 ;
     RECT  68.364 29.561 68.382 29.939 ;
     RECT  2.34 29.363 67.518 30.109 ;
     RECT  2.34 30.109 67.554 30.713 ;
     RECT  2.34 30.713 66.762 31.145 ;
     RECT  2.415 31.145 66.762 31.531 ;
     RECT  67.536 30.713 67.554 31.531 ;
     RECT  2.415 31.531 67.554 31.963 ;
     RECT  2.415 31.963 67.842 32.035 ;
     RECT  2.34 32.035 67.842 32.341 ;
     RECT  2.34 32.341 67.878 32.717 ;
     RECT  2.34 32.717 67.842 32.773 ;
     RECT  0.468 32.611 0.486 32.809 ;
     RECT  0.144 32.809 0.486 32.845 ;
     RECT  0.144 32.845 0.522 32.881 ;
     RECT  2.304 32.773 67.842 33.007 ;
     RECT  2.16 33.007 67.842 33.197 ;
     RECT  0.108 32.881 0.522 33.349 ;
     RECT  2.16 33.197 67.806 33.965 ;
     RECT  2.16 33.965 66.69 34.087 ;
     RECT  69.012 32.395 69.03 34.411 ;
     RECT  0.108 33.349 1.17 34.541 ;
     RECT  2.088 34.087 66.69 34.699 ;
     RECT  67.608 33.965 67.806 34.699 ;
     RECT  68.976 34.411 69.03 34.763 ;
     RECT  2.088 34.699 67.806 34.973 ;
     RECT  68.976 34.763 68.994 35.033 ;
     RECT  19.62 34.973 67.806 35.041 ;
     RECT  0.18 34.541 1.17 35.117 ;
     RECT  19.62 35.041 68.418 35.117 ;
     RECT  0.18 35.117 0.306 35.405 ;
     RECT  19.62 35.117 67.806 35.465 ;
     RECT  1.152 35.117 1.17 35.501 ;
     RECT  19.764 35.465 67.806 35.501 ;
     RECT  19.764 35.501 67.734 35.771 ;
     RECT  2.088 34.973 18.897 35.941 ;
     RECT  0.216 35.405 0.306 35.947 ;
     RECT  2.088 35.941 19.026 36.187 ;
     RECT  0.216 35.947 0.342 36.235 ;
     RECT  0.108 36.235 0.342 36.269 ;
     RECT  0.108 36.269 0.27 36.275 ;
     RECT  19.764 35.771 67.23 36.275 ;
     RECT  43.956 36.275 67.23 36.311 ;
     RECT  0.18 36.275 0.27 36.413 ;
     RECT  0.18 36.413 0.198 36.461 ;
     RECT  19.764 36.275 43.146 36.545 ;
     RECT  1.728 36.187 19.026 36.661 ;
     RECT  19.764 36.545 26.586 36.661 ;
     RECT  44.208 36.311 67.23 36.851 ;
     RECT  27.36 36.545 43.146 37.003 ;
     RECT  44.208 36.851 66.762 37.049 ;
     RECT  1.728 36.661 26.586 37.327 ;
     RECT  27.36 37.003 43.326 37.327 ;
     RECT  1.728 37.327 43.326 37.339 ;
     RECT  44.208 37.049 66.654 37.339 ;
     RECT  1.728 37.339 66.654 37.391 ;
     RECT  2.304 37.391 66.654 38.273 ;
     RECT  25.452 38.273 66.654 38.551 ;
     RECT  0.324 38.923 0.342 39.067 ;
     RECT  2.304 38.273 24.714 39.067 ;
     RECT  25.452 38.551 66.726 39.067 ;
     RECT  2.304 39.067 66.726 39.091 ;
     RECT  0.144 39.067 0.342 39.245 ;
     RECT  0.144 39.245 0.27 39.289 ;
     RECT  0.108 39.289 0.27 39.317 ;
     RECT  0.108 39.317 0.162 39.341 ;
     RECT  2.304 39.091 66.762 39.355 ;
     RECT  2.304 39.355 66.798 39.403 ;
     RECT  2.268 39.403 66.798 39.631 ;
     RECT  0.144 39.341 0.162 39.821 ;
     RECT  2.268 39.631 66.834 40.127 ;
     RECT  2.304 40.127 66.834 40.163 ;
     RECT  2.304 40.163 66.762 40.289 ;
     RECT  2.415 40.289 66.762 40.595 ;
     RECT  32.184 40.595 66.762 40.981 ;
     RECT  32.184 40.981 66.834 41.021 ;
     RECT  32.184 41.021 66.762 41.099 ;
     RECT  2.415 40.595 31.338 41.441 ;
     RECT  11.016 41.441 31.338 41.449 ;
     RECT  32.184 41.099 62.514 41.449 ;
     RECT  11.016 41.449 62.514 41.513 ;
     RECT  2.415 41.441 10.278 41.791 ;
     RECT  24.015 41.513 62.514 41.881 ;
     RECT  63.288 41.099 66.762 41.881 ;
     RECT  2.376 41.791 10.278 42.179 ;
     RECT  2.415 42.179 10.278 42.187 ;
     RECT  11.016 41.513 23.094 42.187 ;
     RECT  24.015 41.881 66.762 42.215 ;
     RECT  2.415 42.187 23.094 42.259 ;
     RECT  24.015 42.215 29.862 42.259 ;
     RECT  2.415 42.259 29.862 42.287 ;
     RECT  9.072 42.287 29.862 42.323 ;
     RECT  30.6 42.215 66.762 42.601 ;
     RECT  9.072 42.323 29.826 43.069 ;
     RECT  30.6 42.601 66.978 43.069 ;
     RECT  2.415 42.287 8.262 43.231 ;
     RECT  9.072 43.069 66.978 43.231 ;
     RECT  2.415 43.231 66.978 46.381 ;
     RECT  2.376 46.381 66.978 46.499 ;
     RECT  2.415 46.499 66.978 49.541 ;
     RECT  2.415 49.541 66.834 50.153 ;
     RECT  2.415 50.153 66.798 50.935 ;
     RECT  2.376 50.935 66.798 51.115 ;
     RECT  69.012 50.971 69.03 51.437 ;
     RECT  2.376 51.115 66.834 51.475 ;
     RECT  2.376 51.475 67.302 51.979 ;
     RECT  68.076 50.395 68.094 51.979 ;
     RECT  2.376 51.979 68.094 52.013 ;
     RECT  67.824 52.013 68.094 52.109 ;
     RECT  2.376 52.013 66.834 52.211 ;
     RECT  68.976 52.363 68.994 52.507 ;
     RECT  68.94 52.507 68.994 52.555 ;
     RECT  68.94 52.555 69.03 52.592 ;
     RECT  68.94 52.592 68.994 52.817 ;
     RECT  5.148 52.211 66.834 52.939 ;
     RECT  67.824 52.109 67.842 52.939 ;
     RECT  5.148 52.939 67.842 53.095 ;
     RECT  5.004 53.095 67.842 53.159 ;
     RECT  67.788 53.159 67.842 53.323 ;
     RECT  68.832 53.131 68.85 53.323 ;
     RECT  2.376 52.211 4.266 53.329 ;
     RECT  5.004 53.159 66.834 53.329 ;
     RECT  2.376 53.329 66.834 53.597 ;
     RECT  67.788 53.323 68.85 53.899 ;
     RECT  5.004 53.597 66.834 54.031 ;
     RECT  67.788 53.899 68.958 54.077 ;
     RECT  67.788 54.077 68.886 54.283 ;
     RECT  2.376 53.597 4.23 54.337 ;
     RECT  5.004 54.031 66.906 54.337 ;
     RECT  2.376 54.337 66.906 55.049 ;
     RECT  2.376 55.049 66.87 55.409 ;
     RECT  2.376 55.409 32.418 55.517 ;
     RECT  33.156 55.409 66.834 55.589 ;
     RECT  2.415 55.517 32.418 55.679 ;
     RECT  2.415 55.679 32.274 55.985 ;
     RECT  67.716 54.283 68.886 55.993 ;
     RECT  2.415 55.985 32.022 56.219 ;
     RECT  33.228 55.589 66.834 56.371 ;
     RECT  67.716 55.993 68.994 56.371 ;
     RECT  33.228 56.371 68.994 56.491 ;
     RECT  32.76 56.491 68.994 57.001 ;
     RECT  2.415 56.219 31.95 57.019 ;
     RECT  32.76 57.001 69.066 57.019 ;
     RECT  2.415 57.019 69.066 58.531 ;
     RECT  2.376 58.531 69.066 58.685 ;
     RECT  2.415 58.685 69.066 59.737 ;
     RECT  2.34 59.737 69.066 60.575 ;
     RECT  2.415 60.575 69.066 61.223 ;
     RECT  2.415 61.223 21.87 61.969 ;
     RECT  22.608 61.223 69.066 61.969 ;
     RECT  2.415 61.969 69.066 62.443 ;
     RECT  2.376 62.443 69.066 62.735 ;
     RECT  22.788 62.735 69.066 62.807 ;
     RECT  2.415 62.735 22.05 63.077 ;
     RECT  5.184 63.077 22.05 63.101 ;
     RECT  5.184 63.101 21.87 63.113 ;
     RECT  2.415 63.077 4.302 63.239 ;
     RECT  5.22 63.113 21.834 63.239 ;
     RECT  22.896 62.807 69.066 63.239 ;
     RECT  3.852 63.239 4.302 63.275 ;
     RECT  22.896 63.239 35.73 63.275 ;
     RECT  3.888 63.275 4.302 63.347 ;
     RECT  22.896 63.275 35.694 63.581 ;
     RECT  23.148 63.581 35.694 63.617 ;
     RECT  3.96 63.347 4.302 63.779 ;
     RECT  5.22 63.239 21.798 63.779 ;
     RECT  4.14 63.779 4.302 63.815 ;
     RECT  36.72 63.239 69.066 63.815 ;
     RECT  4.284 63.815 4.302 63.887 ;
     RECT  5.22 63.779 21.654 63.959 ;
     RECT  36.72 63.815 68.994 64.013 ;
     RECT  5.22 63.959 9.63 64.021 ;
     RECT  23.148 63.617 35.442 64.363 ;
     RECT  23.148 64.363 35.586 64.397 ;
     RECT  36.72 64.013 68.958 64.399 ;
     RECT  23.724 64.397 35.586 64.561 ;
     RECT  36.612 64.399 68.958 64.561 ;
     RECT  5.184 64.021 9.63 64.697 ;
     RECT  5.256 64.697 9.63 64.705 ;
     RECT  10.44 63.959 21.654 64.705 ;
     RECT  5.256 64.705 21.654 64.733 ;
     RECT  20.304 64.733 21.654 64.859 ;
     RECT  20.34 64.859 21.654 64.895 ;
     RECT  23.724 64.561 68.958 64.931 ;
     RECT  34.092 64.931 68.958 64.933 ;
     RECT  20.34 64.895 21.582 65.039 ;
     RECT  23.724 64.931 33.174 65.039 ;
     RECT  20.34 65.039 21.402 65.129 ;
     RECT  34.092 64.933 68.994 65.129 ;
     RECT  42.012 65.129 68.994 65.209 ;
     RECT  23.724 65.039 33.102 65.237 ;
     RECT  5.256 64.733 19.566 65.273 ;
     RECT  23.724 65.237 25.506 65.281 ;
     RECT  42.012 65.209 69.03 65.315 ;
     RECT  5.256 65.273 12.258 65.399 ;
     RECT  20.376 65.129 21.402 65.399 ;
     RECT  5.256 65.399 11.358 65.435 ;
     RECT  20.376 65.399 20.394 65.435 ;
     RECT  21.24 65.399 21.258 65.435 ;
     RECT  5.256 65.435 11.178 65.471 ;
     RECT  5.256 65.471 5.274 65.507 ;
     RECT  23.472 65.281 25.506 65.515 ;
     RECT  23.292 65.515 25.506 65.552 ;
     RECT  13.215 65.273 19.566 65.669 ;
     RECT  23.724 65.552 25.506 65.669 ;
     RECT  34.092 65.129 41.022 65.705 ;
     RECT  6.84 65.471 11.178 65.777 ;
     RECT  6.84 65.777 11.106 65.813 ;
     RECT  34.092 65.705 35.802 65.813 ;
     RECT  36.54 65.705 41.022 65.813 ;
     RECT  6.84 65.813 9.126 65.849 ;
     RECT  26.244 65.237 33.102 65.911 ;
     RECT  6.84 65.849 9.054 65.939 ;
     RECT  10.152 65.813 11.106 65.939 ;
     RECT  12.132 65.399 12.258 65.939 ;
     RECT  13.215 65.669 19.35 65.939 ;
     RECT  36.54 65.813 40.878 65.939 ;
     RECT  12.132 65.939 12.15 65.975 ;
     RECT  6.84 65.939 8.946 66.011 ;
     RECT  10.512 65.939 10.53 66.011 ;
     RECT  34.092 65.813 35.298 66.011 ;
     RECT  42.12 65.315 69.03 66.011 ;
     RECT  42.12 66.011 68.958 66.043 ;
     RECT  6.84 66.011 8.802 66.083 ;
     RECT  41.688 66.043 68.958 66.125 ;
     RECT  34.092 66.011 35.226 66.181 ;
     RECT  6.84 66.083 8.586 66.209 ;
     RECT  13.215 65.939 19.17 66.209 ;
     RECT  26.244 65.911 33.138 66.209 ;
     RECT  31.932 66.209 33.138 66.217 ;
     RECT  33.876 66.181 35.226 66.217 ;
     RECT  14.436 66.209 17.37 66.245 ;
     RECT  23.94 65.669 25.506 66.245 ;
     RECT  31.932 66.217 35.226 66.317 ;
     RECT  41.688 66.125 68.382 66.317 ;
     RECT  6.84 66.209 8.37 66.325 ;
     RECT  24.015 66.245 25.506 66.325 ;
     RECT  26.244 66.209 31.158 66.325 ;
     RECT  6.732 66.325 8.37 66.365 ;
     RECT  41.688 66.317 67.662 66.365 ;
     RECT  14.436 66.245 17.334 66.389 ;
     RECT  31.932 66.317 35.154 66.389 ;
     RECT  42.048 66.365 67.662 66.389 ;
     RECT  18.216 66.209 19.17 66.479 ;
     RECT  24.015 66.325 31.158 66.479 ;
     RECT  31.932 66.389 35.097 66.479 ;
     RECT  36.54 65.939 40.77 66.479 ;
     RECT  42.048 66.389 43.254 66.479 ;
     RECT  44.316 66.389 67.662 66.479 ;
     RECT  6.948 66.365 8.37 66.515 ;
     RECT  18.216 66.479 19.098 66.515 ;
     RECT  28.656 66.479 31.158 66.515 ;
     RECT  36.54 66.479 38.214 66.515 ;
     RECT  42.048 66.479 42.066 66.515 ;
     RECT  36.54 66.515 37.854 66.551 ;
     RECT  39.024 66.479 39.042 66.551 ;
     RECT  39.96 66.479 40.698 66.551 ;
     RECT  44.316 66.479 46.674 66.551 ;
     RECT  29.052 66.515 31.158 66.557 ;
     RECT  7.632 66.515 8.37 66.587 ;
     RECT  27.324 66.479 27.918 66.587 ;
     RECT  40.215 66.551 40.698 66.587 ;
     RECT  24.015 66.479 26.118 66.623 ;
     RECT  27.468 66.587 27.918 66.623 ;
     RECT  36.54 66.551 37.71 66.623 ;
     RECT  24.015 66.623 25.29 66.659 ;
     RECT  36.54 66.623 37.458 66.659 ;
     RECT  40.215 66.587 40.626 66.659 ;
     RECT  24.015 66.659 25.218 66.701 ;
     RECT  42.912 66.479 43.11 66.701 ;
     RECT  2.415 63.239 2.697 66.707 ;
     RECT  7.632 66.587 8.097 66.707 ;
     RECT  18.615 66.515 18.897 66.707 ;
     RECT  24.015 66.701 24.297 66.707 ;
     RECT  33.768 66.479 35.097 66.707 ;
     RECT  40.215 66.659 40.497 66.707 ;
     RECT  13.215 66.209 13.59 66.749 ;
     RECT  14.436 66.389 16.29 66.749 ;
     RECT  17.244 66.389 17.334 66.749 ;
     RECT  25.056 66.701 25.218 66.749 ;
     RECT  27.648 66.623 27.666 66.749 ;
     RECT  29.052 66.557 30.042 66.749 ;
     RECT  31.032 66.557 31.158 66.749 ;
     RECT  31.932 66.479 32.958 66.749 ;
     RECT  42.948 66.701 43.11 66.749 ;
     RECT  44.856 66.551 46.674 66.749 ;
     RECT  7.632 66.707 7.905 66.785 ;
     RECT  14.436 66.749 15.03 66.785 ;
     RECT  17.244 66.749 17.262 66.785 ;
     RECT  29.052 66.749 29.79 66.785 ;
     RECT  33.768 66.707 34.905 66.785 ;
     RECT  36.54 66.659 36.81 66.785 ;
     RECT  42.948 66.749 42.966 66.785 ;
     RECT  34.272 66.785 34.905 66.821 ;
     RECT  36.648 66.785 36.81 66.821 ;
     RECT  47.448 66.479 67.662 66.821 ;
     RECT  29.16 66.785 29.79 66.857 ;
     RECT  31.14 66.749 31.158 66.857 ;
     RECT  64.26 66.821 67.662 66.857 ;
     RECT  29.16 66.857 29.505 66.893 ;
     RECT  31.932 66.749 32.67 66.893 ;
     RECT  45.108 66.749 46.494 66.893 ;
     RECT  15.012 66.785 15.03 66.929 ;
     RECT  32.652 66.893 32.67 66.929 ;
     RECT  34.74 66.821 34.905 66.929 ;
     RECT  47.448 66.821 63.414 66.929 ;
     RECT  64.26 66.857 66.726 66.929 ;
     RECT  2.415 66.707 2.505 66.977 ;
     RECT  7.815 66.785 7.905 66.977 ;
     RECT  13.215 66.749 13.305 66.977 ;
     RECT  18.615 66.707 18.705 66.977 ;
     RECT  24.015 66.707 24.105 66.977 ;
     RECT  29.415 66.893 29.505 66.977 ;
     RECT  34.815 66.929 34.905 66.977 ;
     RECT  40.215 66.707 40.305 66.977 ;
     RECT  45.324 66.893 45.705 66.977 ;
     RECT  49.896 66.929 63.414 66.977 ;
     RECT  45.324 66.977 45.342 67.019 ;
     RECT  46.476 66.893 46.494 67.019 ;
     RECT  65.268 66.929 65.43 67.019 ;
     RECT  68.4 66.859 69.03 67.055 ;
     RECT  64.26 66.929 64.494 67.127 ;
     RECT  61.992 66.977 63.414 67.163 ;
     RECT  68.4 67.055 68.418 67.181 ;
     RECT  47.448 66.929 49.014 67.277 ;
     RECT  64.476 67.127 64.494 67.277 ;
     RECT  62.388 67.163 63.414 67.325 ;
     RECT  66.204 66.929 66.726 67.373 ;
     RECT  62.388 67.325 63.306 67.421 ;
     RECT  47.448 67.277 48.978 67.805 ;
     RECT  49.896 66.977 61.182 67.805 ;
     RECT  47.448 67.805 48.834 67.853 ;
     RECT  49.896 67.805 52.902 67.853 ;
     RECT  53.892 67.805 61.182 67.853 ;
     RECT  62.388 67.421 62.73 67.853 ;
     RECT  56.16 67.853 61.182 67.901 ;
     RECT  53.892 67.853 55.386 67.949 ;
     RECT  55.152 67.949 55.386 68.381 ;
     RECT  56.844 67.901 61.182 68.381 ;
     RECT  47.7 67.853 48.762 68.429 ;
     RECT  49.896 67.853 51.57 68.429 ;
     RECT  52.704 67.853 52.902 68.429 ;
     RECT  53.892 67.949 54.414 68.429 ;
     RECT  55.152 68.381 55.17 68.429 ;
     RECT  59.796 68.381 61.182 68.429 ;
     RECT  48.06 68.429 48.762 68.477 ;
     RECT  52.884 68.429 52.902 68.477 ;
     RECT  54 68.429 54.414 68.477 ;
     RECT  59.796 68.429 59.958 68.477 ;
     RECT  54 68.477 54.018 68.525 ;
     RECT  63.792 68.731 63.81 68.827 ;
     RECT  56.844 68.381 58.626 68.861 ;
     RECT  48.744 68.477 48.762 69.005 ;
     RECT  50.544 68.429 50.922 69.005 ;
     RECT  56.844 68.861 57.582 69.005 ;
     RECT  58.608 68.861 58.626 69.005 ;
     RECT  59.796 68.477 59.814 69.005 ;
     RECT  60.876 68.429 61.182 69.005 ;
     RECT  62.388 67.853 62.406 69.005 ;
     RECT  63.468 68.827 63.81 69.005 ;
     RECT  65.268 67.019 65.286 69.005 ;
     RECT  66.204 67.373 66.222 69.005 ;
     RECT  67.464 66.857 67.662 69.005 ;
    LAYER M4 ;
     RECT  0.06 33.84 0.137 36.84 ;
     RECT  0.06 1.584 2.257 20.712 ;
     RECT  2.257 1.584 2.369 21.528 ;
     RECT  2.369 1.68 2.408 21.528 ;
     RECT  2.365 24.912 2.408 24.936 ;
     RECT  2.329 29.52 2.408 29.544 ;
     RECT  2.329 30.864 2.408 30.888 ;
     RECT  2.329 32.256 2.408 32.28 ;
     RECT  0.137 33.936 2.408 36.84 ;
     RECT  0.06 38.64 2.408 39.912 ;
     RECT  2.365 52.224 2.408 52.248 ;
     RECT  2.365 58.656 2.408 58.68 ;
     RECT  2.329 59.76 2.408 59.784 ;
     RECT  2.365 62.448 2.408 62.472 ;
     RECT  2.408 1.68 2.512 66.972 ;
     RECT  2.512 1.68 2.704 66.702 ;
     RECT  2.704 1.68 2.909 21.96 ;
     RECT  2.704 33.648 2.945 37.608 ;
     RECT  2.909 1.68 3.053 20.904 ;
     RECT  3.053 1.68 3.089 20.616 ;
     RECT  3.089 1.68 3.197 20.328 ;
     RECT  2.704 38.736 3.233 39.864 ;
     RECT  2.704 30.528 3.269 31.176 ;
     RECT  2.945 33.648 3.305 37.368 ;
     RECT  2.704 41.04 3.305 45 ;
     RECT  2.704 24.912 3.341 25.368 ;
     RECT  3.305 41.04 3.395 44.472 ;
     RECT  3.197 20.304 3.413 20.328 ;
     RECT  3.305 33.648 3.413 35.784 ;
     RECT  3.269 30.528 3.449 30.888 ;
     RECT  2.704 51.84 3.449 52.296 ;
     RECT  2.704 46.704 3.491 47.256 ;
     RECT  2.704 29.088 3.521 29.544 ;
     RECT  3.449 52.224 3.521 52.296 ;
     RECT  3.491 46.704 3.529 47.112 ;
     RECT  2.704 58.128 3.629 59.88 ;
     RECT  3.197 1.68 3.737 19.272 ;
     RECT  2.704 62.448 3.841 62.472 ;
     RECT  3.521 52.272 3.845 52.296 ;
     RECT  3.629 59.856 4.021 59.88 ;
     RECT  3.529 46.752 4.025 47.112 ;
     RECT  3.737 1.68 4.061 19.032 ;
     RECT  4.025 46.8 4.061 47.112 ;
     RECT  4.061 46.8 4.097 46.872 ;
     RECT  3.413 33.648 4.115 34.344 ;
     RECT  3.395 42.48 4.133 44.472 ;
     RECT  3.841 62.448 4.165 62.808 ;
     RECT  4.165 62.448 4.205 63.288 ;
     RECT  2.704 50.448 4.237 50.712 ;
     RECT  3.341 24.912 4.277 24.936 ;
     RECT  3.413 35.568 4.309 35.784 ;
     RECT  3.305 36.96 4.309 37.368 ;
     RECT  2.704 27.312 4.345 27.336 ;
     RECT  4.309 35.568 4.381 37.608 ;
     RECT  3.697 38.64 4.381 38.664 ;
     RECT  2.704 32.256 4.453 32.28 ;
     RECT  3.629 58.128 4.489 58.68 ;
     RECT  4.133 42.48 4.501 43.752 ;
     RECT  2.909 21.936 4.549 21.96 ;
     RECT  4.061 9.312 4.565 19.032 ;
     RECT  4.525 44.832 4.597 44.856 ;
     RECT  2.704 48.384 4.597 48.408 ;
     RECT  4.489 58.08 4.597 58.68 ;
     RECT  4.021 59.856 4.597 60.408 ;
     RECT  3.449 30.864 4.604 30.888 ;
     RECT  2.704 53.568 4.645 55.416 ;
     RECT  4.525 56.544 4.645 56.568 ;
     RECT  4.237 50.256 4.669 50.712 ;
     RECT  4.453 32.256 4.705 32.472 ;
     RECT  4.565 15.456 4.709 19.032 ;
     RECT  4.501 42.048 4.717 43.752 ;
     RECT  4.645 53.568 4.732 56.568 ;
     RECT  4.115 34.08 4.741 34.344 ;
     RECT  4.381 35.568 4.741 38.664 ;
     RECT  4.597 58.08 4.741 60.408 ;
     RECT  4.741 34.08 4.777 38.664 ;
     RECT  3.233 39.84 4.777 39.864 ;
     RECT  4.604 30.528 4.813 30.888 ;
     RECT  4.705 31.92 4.813 32.472 ;
     RECT  4.777 34.08 4.813 39.864 ;
     RECT  3.395 41.04 4.813 41.064 ;
     RECT  4.345 27.312 4.844 27.96 ;
     RECT  4.549 21.936 4.853 22.2 ;
     RECT  4.732 53.568 4.853 55.416 ;
     RECT  4.669 50.016 4.885 50.712 ;
     RECT  4.844 52.176 4.885 52.2 ;
     RECT  4.709 15.456 4.889 18.312 ;
     RECT  4.853 22.176 4.921 22.2 ;
     RECT  3.913 23.376 4.921 23.4 ;
     RECT  4.717 43.248 4.925 43.752 ;
     RECT  4.844 26.736 4.931 27.96 ;
     RECT  4.741 57.84 4.957 60.408 ;
     RECT  4.921 22.176 4.997 23.4 ;
     RECT  4.097 46.848 5.029 46.872 ;
     RECT  4.597 48.384 5.029 48.456 ;
     RECT  4.813 30.528 5.101 32.472 ;
     RECT  5.029 46.848 5.101 48.456 ;
     RECT  4.885 50.016 5.101 52.2 ;
     RECT  4.813 34.08 5.137 41.064 ;
     RECT  4.717 42.048 5.137 42.072 ;
     RECT  4.732 56.448 5.137 56.568 ;
     RECT  4.957 57.84 5.137 60.504 ;
     RECT  4.849 19.392 5.141 19.416 ;
     RECT  5.101 46.848 5.141 52.2 ;
     RECT  5.137 34.08 5.177 42.072 ;
     RECT  5.101 30.24 5.205 32.472 ;
     RECT  4.997 22.56 5.209 23.4 ;
     RECT  3.521 29.088 5.209 29.112 ;
     RECT  4.853 53.568 5.213 54.888 ;
     RECT  4.565 9.312 5.245 14.184 ;
     RECT  5.141 46.848 5.245 47.448 ;
     RECT  5.205 30.24 5.249 30.264 ;
     RECT  5.209 22.56 5.281 23.88 ;
     RECT  4.633 25.056 5.281 25.272 ;
     RECT  4.597 44.832 5.317 45.528 ;
     RECT  5.137 56.448 5.317 60.504 ;
     RECT  5.245 61.632 5.317 61.656 ;
     RECT  5.209 29.088 5.353 29.208 ;
     RECT  5.317 44.832 5.353 45.72 ;
     RECT  5.245 46.704 5.353 47.448 ;
     RECT  4.061 1.68 5.357 7.944 ;
     RECT  4.931 27.312 5.411 27.96 ;
     RECT  5.353 29.088 5.425 29.688 ;
     RECT  5.353 44.832 5.573 47.448 ;
     RECT  5.245 9.072 5.605 14.184 ;
     RECT  5.317 56.448 5.677 62.184 ;
     RECT  4.205 63.264 5.677 63.288 ;
     RECT  5.677 56.448 5.681 63.288 ;
     RECT  4.889 15.936 5.713 18.312 ;
     RECT  5.357 2.352 5.749 7.944 ;
     RECT  5.605 9.072 5.749 14.904 ;
     RECT  5.177 34.08 5.753 42.024 ;
     RECT  5.281 22.56 5.825 25.272 ;
     RECT  5.213 53.568 5.825 54.792 ;
     RECT  5.681 56.448 5.825 63.144 ;
     RECT  5.825 56.448 5.836 60.216 ;
     RECT  5.825 23.856 5.897 25.272 ;
     RECT  5.573 47.424 5.897 47.448 ;
     RECT  5.825 54.096 6.035 54.792 ;
     RECT  5.836 56.448 6.113 59.784 ;
     RECT  5.825 22.56 6.145 22.776 ;
     RECT  6.113 56.448 6.145 58.248 ;
     RECT  5.749 2.352 6.217 14.904 ;
     RECT  5.713 15.936 6.217 19.032 ;
     RECT  5.141 48.432 6.229 52.2 ;
     RECT  4.925 43.248 6.236 43.704 ;
     RECT  6.217 2.352 6.253 19.032 ;
     RECT  5.753 34.08 6.257 40.248 ;
     RECT  5.897 24.672 6.289 25.272 ;
     RECT  6.236 43.248 6.323 43.848 ;
     RECT  6.145 55.872 6.365 58.248 ;
     RECT  5.753 41.376 6.397 42.024 ;
     RECT  6.323 43.248 6.397 43.656 ;
     RECT  6.253 2.352 6.433 19.176 ;
     RECT  6.361 20.544 6.433 20.568 ;
     RECT  6.289 24.672 6.433 25.896 ;
     RECT  6.035 54.432 6.473 54.792 ;
     RECT  6.365 55.872 6.473 58.152 ;
     RECT  6.257 34.08 6.545 37.464 ;
     RECT  6.145 22.32 6.581 22.776 ;
     RECT  5.205 31.296 6.581 32.472 ;
     RECT  6.397 41.376 6.617 43.656 ;
     RECT  5.425 29.04 6.689 29.688 ;
     RECT  6.433 2.352 6.757 19.416 ;
     RECT  6.433 20.544 6.757 20.664 ;
     RECT  6.581 22.32 6.793 22.584 ;
     RECT  5.411 27.312 6.793 27.816 ;
     RECT  6.757 2.352 6.833 20.664 ;
     RECT  6.433 24.672 6.833 26.328 ;
     RECT  6.689 29.04 6.833 29.4 ;
     RECT  6.617 41.904 6.833 43.656 ;
     RECT  6.473 56.448 6.833 58.152 ;
     RECT  6.833 2.592 6.865 20.664 ;
     RECT  6.793 21.696 6.865 22.584 ;
     RECT  6.113 59.28 6.973 59.784 ;
     RECT  5.825 61.2 6.973 63.144 ;
     RECT  6.721 66.336 6.973 66.36 ;
     RECT  6.833 24.672 7.117 25.32 ;
     RECT  6.229 47.856 7.117 52.2 ;
     RECT  6.473 54.72 7.189 54.792 ;
     RECT  5.573 44.832 7.225 46.344 ;
     RECT  6.833 26.304 7.261 26.328 ;
     RECT  6.793 27.312 7.261 27.912 ;
     RECT  6.545 34.368 7.261 37.464 ;
     RECT  6.257 38.448 7.261 40.248 ;
     RECT  7.117 47.856 7.261 52.248 ;
     RECT  7.004 53.664 7.261 53.688 ;
     RECT  7.189 54.72 7.369 54.84 ;
     RECT  6.581 31.632 7.405 32.472 ;
     RECT  7.261 47.856 7.405 53.688 ;
     RECT  6.833 43.008 7.477 43.656 ;
     RECT  7.225 44.688 7.477 46.344 ;
     RECT  7.369 54.72 7.513 54.888 ;
     RECT  6.973 59.28 7.585 63.288 ;
     RECT  7.405 47.712 7.621 53.688 ;
     RECT  6.865 2.592 7.657 22.584 ;
     RECT  7.477 43.008 7.665 46.344 ;
     RECT  7.621 47.328 7.665 53.688 ;
     RECT  7.665 43.008 7.801 53.688 ;
     RECT  7.513 54.72 7.801 54.984 ;
     RECT  7.657 2.592 7.808 22.776 ;
     RECT  7.117 24.432 7.808 25.32 ;
     RECT  7.261 26.304 7.808 27.912 ;
     RECT  6.833 29.04 7.808 29.064 ;
     RECT  7.549 30.432 7.808 30.456 ;
     RECT  7.405 31.632 7.808 32.856 ;
     RECT  7.261 34.368 7.808 40.248 ;
     RECT  6.833 41.904 7.808 42.024 ;
     RECT  7.801 43.008 7.808 54.984 ;
     RECT  6.833 56.64 7.808 58.152 ;
     RECT  7.585 59.232 7.808 63.288 ;
     RECT  5.533 65.136 7.808 65.16 ;
     RECT  6.973 66.144 7.808 66.36 ;
     RECT  7.808 2.148 7.912 66.972 ;
     RECT  7.912 2.418 8.104 66.702 ;
     RECT  8.104 25.248 8.201 30.792 ;
     RECT  8.104 32.16 8.201 33.048 ;
     RECT  8.201 26.592 8.309 30.792 ;
     RECT  8.104 2.784 8.489 23.88 ;
     RECT  8.104 41.904 8.561 55.944 ;
     RECT  8.489 2.784 8.669 8.328 ;
     RECT  8.669 2.784 8.764 3.912 ;
     RECT  8.764 2.784 8.813 2.808 ;
     RECT  8.561 41.904 8.813 52.44 ;
     RECT  8.813 41.904 8.849 50.088 ;
     RECT  8.849 41.904 8.921 49.608 ;
     RECT  8.561 53.52 8.921 55.944 ;
     RECT  8.921 41.904 9.097 42.744 ;
     RECT  8.104 57.408 9.097 57.432 ;
     RECT  8.104 58.608 9.097 63.288 ;
     RECT  8.764 3.888 9.137 3.912 ;
     RECT  9.097 57.408 9.137 63.288 ;
     RECT  8.104 34.128 9.205 40.392 ;
     RECT  9.097 41.616 9.205 42.744 ;
     RECT  8.813 51.12 9.209 52.44 ;
     RECT  8.201 32.16 9.281 32.472 ;
     RECT  8.669 4.896 9.317 8.328 ;
     RECT  9.205 33.6 9.389 42.744 ;
     RECT  9.389 33.6 9.461 40.008 ;
     RECT  8.309 26.592 9.491 30.456 ;
     RECT  8.921 53.808 9.529 55.944 ;
     RECT  9.491 26.592 9.532 29.64 ;
     RECT  8.489 9.312 9.533 23.88 ;
     RECT  9.532 26.592 9.605 29.544 ;
     RECT  9.281 32.16 9.683 32.184 ;
     RECT  9.637 30.72 9.692 30.888 ;
     RECT  9.389 41.136 9.713 42.744 ;
     RECT  8.104 65.52 9.713 65.544 ;
     RECT  9.605 26.592 9.749 29.352 ;
     RECT  8.201 25.248 9.889 25.56 ;
     RECT  9.749 26.592 9.889 29.16 ;
     RECT  9.209 52.08 9.925 52.44 ;
     RECT  9.529 53.808 9.925 56.952 ;
     RECT  9.137 58.368 9.929 63.288 ;
     RECT  9.317 4.896 10.037 7.704 ;
     RECT  9.461 33.888 10.037 36.6 ;
     RECT  9.713 41.328 10.037 42.744 ;
     RECT  10.033 50.592 10.177 50.616 ;
     RECT  9.925 52.08 10.177 56.952 ;
     RECT  8.921 43.92 10.249 49.608 ;
     RECT  10.177 50.592 10.249 56.952 ;
     RECT  9.533 9.312 10.361 23.544 ;
     RECT  10.361 9.312 10.397 23.16 ;
     RECT  10.037 6 10.433 7.704 ;
     RECT  10.037 33.936 10.433 36.6 ;
     RECT  10.397 11.424 10.541 23.16 ;
     RECT  10.541 11.808 10.577 23.16 ;
     RECT  10.577 14.352 10.595 23.16 ;
     RECT  9.929 58.368 10.613 62.808 ;
     RECT  10.577 11.808 10.685 13.032 ;
     RECT  10.613 58.368 10.685 61.08 ;
     RECT  9.692 30.72 10.693 31.704 ;
     RECT  10.037 42.192 10.693 42.744 ;
     RECT  10.249 43.92 10.693 56.952 ;
     RECT  10.397 9.312 10.721 10.248 ;
     RECT  10.693 42.192 10.739 56.952 ;
     RECT  10.693 30.336 10.753 31.704 ;
     RECT  10.685 12.24 10.757 13.032 ;
     RECT  10.595 14.352 10.757 21.096 ;
     RECT  10.739 44.928 10.789 56.952 ;
     RECT  10.685 58.368 10.789 58.392 ;
     RECT  10.739 42.192 10.793 43.944 ;
     RECT  9.461 37.584 10.825 40.008 ;
     RECT  10.741 40.992 10.825 41.016 ;
     RECT  10.681 3.504 10.837 3.528 ;
     RECT  10.613 62.112 10.897 62.808 ;
     RECT  10.597 64.08 10.897 64.104 ;
     RECT  10.757 12.24 10.901 12.792 ;
     RECT  10.757 14.4 10.901 21.096 ;
     RECT  10.753 30.336 10.933 31.944 ;
     RECT  10.901 14.64 10.937 21.096 ;
     RECT  10.837 2.832 10.973 3.528 ;
     RECT  10.595 22.08 10.973 23.16 ;
     RECT  10.037 4.896 11.005 5.016 ;
     RECT  10.901 12.336 11.009 12.792 ;
     RECT  10.793 43.92 11.009 43.944 ;
     RECT  10.433 34.224 11.041 36.6 ;
     RECT  10.825 37.584 11.041 41.016 ;
     RECT  10.433 6.528 11.045 7.704 ;
     RECT  10.937 14.976 11.045 21.096 ;
     RECT  9.889 25.248 11.077 29.16 ;
     RECT  11.041 34.224 11.153 41.016 ;
     RECT  11.153 40.272 11.221 41.016 ;
     RECT  10.793 42.192 11.441 42.504 ;
     RECT  11.293 33.12 11.473 33.144 ;
     RECT  11.153 34.224 11.473 39.24 ;
     RECT  10.685 59.712 11.513 61.08 ;
     RECT  11.005 4.8 11.516 5.016 ;
     RECT  11.516 4.512 11.557 5.016 ;
     RECT  10.933 30.24 11.557 31.944 ;
     RECT  11.473 33.12 11.557 39.24 ;
     RECT  10.973 3.504 11.603 3.528 ;
     RECT  11.557 4.512 11.603 5.256 ;
     RECT  11.557 30.24 11.603 39.24 ;
     RECT  11.513 61.056 11.621 61.08 ;
     RECT  11.603 30.24 11.644 33.144 ;
     RECT  11.644 30.24 11.693 31.704 ;
     RECT  10.721 9.792 11.725 10.248 ;
     RECT  11.644 33.12 11.729 33.144 ;
     RECT  10.789 44.928 11.756 58.392 ;
     RECT  11.756 44.064 11.797 58.392 ;
     RECT  11.513 59.712 11.797 59.736 ;
     RECT  11.603 34.224 11.837 39.24 ;
     RECT  11.077 24.672 11.945 29.16 ;
     RECT  11.045 14.976 11.977 20.856 ;
     RECT  11.945 27.6 11.989 29.16 ;
     RECT  11.693 30.24 11.989 31.416 ;
     RECT  11.221 40.272 12.037 41.064 ;
     RECT  11.441 42.192 12.037 42.456 ;
     RECT  11.977 14.64 12.085 20.856 ;
     RECT  10.973 22.08 12.085 22.776 ;
     RECT  11.989 27.6 12.089 31.416 ;
     RECT  11.797 44.064 12.124 59.736 ;
     RECT  11.725 9.792 12.193 10.296 ;
     RECT  12.085 14.64 12.337 22.776 ;
     RECT  11.945 24.672 12.337 26.28 ;
     RECT  11.045 7.152 12.445 7.704 ;
     RECT  11.009 12.768 12.553 12.792 ;
     RECT  12.445 6.816 12.589 7.704 ;
     RECT  12.193 9.168 12.589 10.296 ;
     RECT  12.037 40.272 12.625 42.456 ;
     RECT  12.589 6.816 12.661 10.296 ;
     RECT  11.837 34.224 12.841 38.568 ;
     RECT  12.841 34.224 12.877 39.048 ;
     RECT  12.625 40.272 12.877 42.6 ;
     RECT  12.337 24.624 12.908 26.28 ;
     RECT  12.908 24.288 12.997 26.28 ;
     RECT  12.089 27.6 12.997 29.112 ;
     RECT  10.897 62.112 12.997 64.104 ;
     RECT  12.877 34.224 13.057 42.6 ;
     RECT  13.057 33.6 13.093 42.6 ;
     RECT  12.517 3.456 13.201 3.48 ;
     RECT  13.201 3.456 13.208 3.72 ;
     RECT  11.603 4.992 13.208 5.256 ;
     RECT  12.661 6.816 13.208 10.872 ;
     RECT  12.553 12.768 13.208 13.368 ;
     RECT  12.337 14.64 13.208 22.872 ;
     RECT  12.997 24.288 13.208 29.112 ;
     RECT  12.089 30.24 13.208 31.416 ;
     RECT  13.093 33.12 13.208 42.6 ;
     RECT  12.124 44.064 13.208 58.536 ;
     RECT  12.124 59.568 13.208 59.736 ;
     RECT  12.997 62.112 13.208 64.824 ;
     RECT  13.208 2.148 13.312 66.972 ;
     RECT  13.312 2.418 13.504 66.744 ;
     RECT  13.504 14.976 13.601 22.776 ;
     RECT  13.504 3.696 13.619 4.008 ;
     RECT  13.601 14.976 13.619 22.104 ;
     RECT  13.504 65.52 13.619 66.744 ;
     RECT  13.504 30.672 13.637 41.16 ;
     RECT  13.504 42.192 13.715 64.344 ;
     RECT  13.504 24.768 13.745 29.4 ;
     RECT  13.504 4.992 13.781 5.256 ;
     RECT  13.715 42.192 13.817 44.472 ;
     RECT  13.619 65.52 13.889 65.544 ;
     RECT  13.715 45.6 13.997 64.344 ;
     RECT  13.637 30.672 14.243 41.016 ;
     RECT  13.817 42.192 14.243 44.04 ;
     RECT  13.997 45.6 14.249 62.472 ;
     RECT  14.243 43.584 14.284 44.04 ;
     RECT  14.243 30.672 14.285 40.68 ;
     RECT  14.285 30.672 14.321 39.816 ;
     RECT  14.249 45.6 14.321 59.208 ;
     RECT  14.321 33.84 14.357 39.816 ;
     RECT  13.997 63.6 14.357 64.344 ;
     RECT  13.504 11.472 14.393 13.704 ;
     RECT  13.619 66.72 14.465 66.744 ;
     RECT  14.243 42.192 14.533 42.6 ;
     RECT  13.745 24.768 14.569 26.568 ;
     RECT  13.745 27.6 14.569 29.4 ;
     RECT  14.321 30.672 14.569 32.568 ;
     RECT  14.569 24.336 14.641 26.568 ;
     RECT  13.619 3.744 14.677 4.008 ;
     RECT  14.357 36.048 14.681 39.816 ;
     RECT  13.504 7.152 14.713 8.04 ;
     RECT  13.504 9.312 14.713 9.336 ;
     RECT  14.321 57.6 14.717 59.208 ;
     RECT  14.605 65.76 14.717 65.784 ;
     RECT  14.533 42.048 14.785 42.6 ;
     RECT  14.569 27.6 14.789 32.568 ;
     RECT  14.321 45.6 14.789 56.616 ;
     RECT  13.781 5.232 14.821 5.256 ;
     RECT  14.681 36.048 14.861 39.48 ;
     RECT  14.785 41.664 14.897 42.6 ;
     RECT  14.284 43.584 14.933 43.848 ;
     RECT  14.717 57.6 14.969 58.152 ;
     RECT  14.641 23.376 15.005 26.568 ;
     RECT  14.969 57.696 15.005 58.152 ;
     RECT  14.713 7.152 15.077 9.336 ;
     RECT  13.619 14.976 15.145 20.856 ;
     RECT  13.619 22.08 15.145 22.104 ;
     RECT  14.789 27.984 15.149 32.568 ;
     RECT  14.393 11.472 15.181 12.792 ;
     RECT  14.789 45.6 15.257 49.08 ;
     RECT  14.789 50.256 15.257 56.472 ;
     RECT  15.149 30.192 15.289 32.568 ;
     RECT  15.077 7.152 15.325 8.472 ;
     RECT  15.257 45.6 15.325 48.936 ;
     RECT  14.249 60.432 15.401 62.472 ;
     RECT  15.325 6.24 15.409 8.472 ;
     RECT  14.677 3.744 15.433 4.2 ;
     RECT  14.821 5.184 15.433 5.256 ;
     RECT  15.145 14.976 15.437 22.104 ;
     RECT  14.861 36.144 15.437 39.48 ;
     RECT  15.437 36.144 15.509 39.432 ;
     RECT  15.257 52.992 15.509 56.472 ;
     RECT  15.289 30.192 15.577 32.616 ;
     RECT  14.357 33.84 15.577 35.016 ;
     RECT  15.433 3.744 15.581 5.256 ;
     RECT  14.933 43.824 15.613 43.848 ;
     RECT  15.325 45.504 15.613 48.936 ;
     RECT  15.401 62.208 15.649 62.472 ;
     RECT  15.409 6.864 15.653 8.472 ;
     RECT  15.509 52.992 15.653 54.072 ;
     RECT  15.005 23.52 15.685 26.568 ;
     RECT  15.581 3.744 15.725 3.768 ;
     RECT  15.653 7.152 15.833 8.472 ;
     RECT  15.653 53.136 15.833 54.072 ;
     RECT  15.401 60.432 15.833 61.128 ;
     RECT  15.181 11.424 15.937 12.792 ;
     RECT  14.897 41.952 15.937 42.6 ;
     RECT  15.613 43.824 15.937 48.936 ;
     RECT  15.833 53.136 15.941 54.024 ;
     RECT  15.577 30.192 15.973 35.016 ;
     RECT  15.509 36.144 15.973 39.336 ;
     RECT  14.357 64.32 15.973 64.344 ;
     RECT  15.685 65.52 15.973 65.544 ;
     RECT  15.941 53.232 15.977 54.024 ;
     RECT  15.257 50.688 16.013 51.624 ;
     RECT  15.932 10.32 16.019 10.344 ;
     RECT  15.973 64.32 16.019 65.544 ;
     RECT  15.437 14.976 16.117 20.856 ;
     RECT  15.937 11.424 16.261 13.416 ;
     RECT  16.117 14.832 16.261 20.856 ;
     RECT  15.685 23.52 16.265 26.76 ;
     RECT  15.509 55.488 16.265 56.472 ;
     RECT  15.005 57.84 16.297 58.152 ;
     RECT  14.717 59.184 16.297 59.208 ;
     RECT  15.541 66.72 16.301 66.744 ;
     RECT  16.297 57.84 16.337 59.208 ;
     RECT  15.833 60.96 16.373 61.128 ;
     RECT  16.261 11.424 16.441 20.856 ;
     RECT  15.649 62.208 16.441 62.952 ;
     RECT  16.019 64.32 16.441 65.016 ;
     RECT  15.149 27.984 16.477 29.16 ;
     RECT  15.973 30.192 16.477 39.336 ;
     RECT  16.477 27.984 16.517 39.336 ;
     RECT  16.265 23.904 16.547 26.76 ;
     RECT  16.265 55.776 16.553 56.472 ;
     RECT  16.547 24.624 16.556 26.76 ;
     RECT  16.517 27.984 16.556 35.016 ;
     RECT  15.937 41.952 16.589 48.936 ;
     RECT  16.549 50.112 16.691 50.136 ;
     RECT  16.441 62.208 16.733 65.016 ;
     RECT  16.589 46.32 16.765 48.936 ;
     RECT  16.733 62.208 16.769 63.432 ;
     RECT  16.553 56.064 16.837 56.472 ;
     RECT  16.765 46.32 16.913 48.984 ;
     RECT  16.009 3.024 16.945 3.048 ;
     RECT  16.517 36.048 17.017 39.336 ;
     RECT  16.729 40.56 17.017 40.584 ;
     RECT  16.013 51.6 17.017 51.624 ;
     RECT  16.913 46.896 17.053 48.984 ;
     RECT  15.977 53.568 17.053 54.024 ;
     RECT  17.053 52.992 17.089 54.024 ;
     RECT  16.945 2.88 17.112 3.048 ;
     RECT  17.053 46.896 17.125 49.032 ;
     RECT  16.556 24.624 17.129 35.016 ;
     RECT  15.581 4.848 17.132 4.872 ;
     RECT  17.017 51.312 17.161 51.624 ;
     RECT  17.089 52.752 17.161 54.024 ;
     RECT  15.833 7.152 17.197 7.704 ;
     RECT  16.589 41.952 17.201 44.664 ;
     RECT  17.112 2.832 17.219 3.048 ;
     RECT  17.132 4.08 17.219 4.872 ;
     RECT  17.201 41.952 17.233 43.656 ;
     RECT  16.733 64.992 17.237 65.016 ;
     RECT  17.017 36.048 17.309 40.584 ;
     RECT  16.337 58.656 17.317 59.208 ;
     RECT  16.441 11.184 17.345 20.856 ;
     RECT  17.345 12.768 17.363 20.856 ;
     RECT  16.837 56.064 17.363 57.048 ;
     RECT  17.219 2.832 17.381 2.904 ;
     RECT  17.233 41.712 17.521 43.656 ;
     RECT  17.201 44.64 17.557 44.664 ;
     RECT  17.161 51.312 17.557 54.024 ;
     RECT  17.197 7.152 17.593 8.472 ;
     RECT  17.345 11.184 17.593 11.544 ;
     RECT  17.129 24.624 17.597 34.776 ;
     RECT  17.381 2.88 17.633 2.904 ;
     RECT  17.125 46.896 17.653 49.608 ;
     RECT  17.557 50.592 17.653 54.024 ;
     RECT  17.593 10.368 17.737 11.544 ;
     RECT  17.317 58.08 17.737 59.208 ;
     RECT  17.363 56.064 17.809 56.472 ;
     RECT  17.653 46.896 17.881 54.024 ;
     RECT  17.881 46.896 17.941 54.072 ;
     RECT  17.941 46.896 18.025 54.12 ;
     RECT  17.809 55.632 18.025 56.472 ;
     RECT  16.373 60.96 18.053 60.984 ;
     RECT  18.053 60.96 18.061 61.032 ;
     RECT  16.769 62.208 18.061 62.856 ;
     RECT  17.557 44.64 18.085 45.384 ;
     RECT  18.025 46.896 18.085 56.472 ;
     RECT  17.593 6.912 18.133 8.472 ;
     RECT  17.521 41.616 18.241 43.656 ;
     RECT  18.085 44.64 18.241 56.472 ;
     RECT  17.363 13.056 18.421 20.856 ;
     RECT  15.437 22.08 18.421 22.104 ;
     RECT  17.309 36.048 18.529 40.536 ;
     RECT  18.241 41.616 18.529 56.472 ;
     RECT  18.277 4.128 18.608 4.152 ;
     RECT  18.169 5.28 18.608 5.304 ;
     RECT  18.133 6.576 18.608 8.472 ;
     RECT  17.737 9.888 18.608 11.544 ;
     RECT  18.421 13.056 18.608 22.104 ;
     RECT  17.557 23.136 18.608 23.16 ;
     RECT  17.597 24.624 18.608 28.296 ;
     RECT  17.597 29.568 18.608 34.776 ;
     RECT  18.529 36.048 18.608 56.472 ;
     RECT  17.737 57.936 18.608 59.208 ;
     RECT  18.061 60.96 18.608 62.856 ;
     RECT  18.608 2.148 18.712 66.972 ;
     RECT  18.712 2.418 18.904 66.702 ;
     RECT  18.904 28.8 19.001 32.568 ;
     RECT  18.904 57.6 19.043 64.584 ;
     RECT  18.904 40.992 19.217 54.792 ;
     RECT  19.043 57.6 19.225 59.304 ;
     RECT  19.217 40.992 19.289 52.584 ;
     RECT  19.217 53.568 19.361 54.792 ;
     RECT  18.904 36.048 19.379 39.768 ;
     RECT  19.289 49.584 19.397 52.584 ;
     RECT  19.043 60.384 19.42 64.584 ;
     RECT  18.904 14.688 19.427 23.16 ;
     RECT  19.42 60.384 19.433 63.864 ;
     RECT  19.433 60.384 19.469 62.76 ;
     RECT  19.289 40.992 19.505 48.504 ;
     RECT  19.379 37.056 19.577 39.768 ;
     RECT  19.505 45.984 19.721 48.504 ;
     RECT  19.397 49.584 19.757 52.536 ;
     RECT  19.469 60.384 19.757 62.472 ;
     RECT  18.904 33.552 19.9 34.968 ;
     RECT  19.225 57.6 19.933 59.256 ;
     RECT  19.361 53.568 19.937 54.744 ;
     RECT  19.433 63.744 19.937 63.864 ;
     RECT  18.904 6.576 19.957 9 ;
     RECT  18.904 10.128 19.957 11.88 ;
     RECT  19.505 40.992 20.081 44.904 ;
     RECT  19.957 6.576 20.117 11.88 ;
     RECT  18.904 3.024 20.147 4.152 ;
     RECT  19.937 53.616 20.153 54.744 ;
     RECT  19.757 60.384 20.225 62.424 ;
     RECT  19.721 46.032 20.257 48.504 ;
     RECT  19.757 49.584 20.257 52.296 ;
     RECT  18.904 5.28 20.297 5.304 ;
     RECT  19.379 36.048 20.365 36.072 ;
     RECT  19.577 37.056 20.365 38.568 ;
     RECT  19.001 28.8 20.401 32.088 ;
     RECT  20.225 60.384 20.477 60.696 ;
     RECT  19.427 14.832 20.531 23.16 ;
     RECT  18.904 24.768 20.545 27.384 ;
     RECT  20.153 53.904 20.545 54.744 ;
     RECT  18.904 55.968 20.545 56.424 ;
     RECT  19.933 57.456 20.545 59.256 ;
     RECT  19.937 63.84 20.545 63.864 ;
     RECT  20.401 28.56 20.581 32.088 ;
     RECT  20.545 53.904 20.581 54.84 ;
     RECT  19.9 33.6 20.585 34.968 ;
     RECT  20.545 63.84 20.585 64.392 ;
     RECT  20.365 36.048 20.653 38.568 ;
     RECT  19.577 39.744 20.653 39.768 ;
     RECT  20.545 24 20.765 27.384 ;
     RECT  20.147 3.024 20.797 3.96 ;
     RECT  18.904 13.056 20.905 13.656 ;
     RECT  20.581 28.56 20.972 32.616 ;
     RECT  20.585 33.6 20.972 34.92 ;
     RECT  20.531 14.832 21.013 22.872 ;
     RECT  20.117 7.008 21.049 11.88 ;
     RECT  20.905 13.056 21.049 13.752 ;
     RECT  21.049 7.008 21.053 13.752 ;
     RECT  20.972 28.56 21.059 34.92 ;
     RECT  20.081 41.568 21.085 44.904 ;
     RECT  20.225 61.776 21.121 62.424 ;
     RECT  21.085 40.992 21.157 44.904 ;
     RECT  20.257 46.032 21.157 52.296 ;
     RECT  20.581 53.904 21.193 54.936 ;
     RECT  20.545 55.968 21.193 59.256 ;
     RECT  21.059 28.56 21.205 32.616 ;
     RECT  20.797 2.88 21.233 3.96 ;
     RECT  21.157 40.992 21.269 52.296 ;
     RECT  21.121 61.776 21.302 63.24 ;
     RECT  21.053 7.008 21.373 13.608 ;
     RECT  21.269 47.664 21.377 52.296 ;
     RECT  21.233 3.024 21.413 3.096 ;
     RECT  21.193 53.904 21.445 59.256 ;
     RECT  21.269 40.992 21.449 46.152 ;
     RECT  20.477 60.672 21.449 60.696 ;
     RECT  21.013 14.784 21.517 22.872 ;
     RECT  20.765 24 21.517 26.904 ;
     RECT  21.377 48.768 21.517 52.296 ;
     RECT  21.445 53.568 21.517 59.256 ;
     RECT  21.413 3.072 21.521 3.096 ;
     RECT  21.517 48.768 21.553 59.256 ;
     RECT  21.302 61.776 21.557 63.192 ;
     RECT  21.553 48.768 21.589 59.496 ;
     RECT  21.557 62.16 21.665 63.192 ;
     RECT  21.205 27.936 21.683 32.616 ;
     RECT  21.665 62.16 21.875 63.096 ;
     RECT  21.517 14.784 21.923 26.904 ;
     RECT  21.923 14.88 21.989 26.904 ;
     RECT  21.875 63.072 22.061 63.096 ;
     RECT  21.829 60.96 22.115 60.984 ;
     RECT  20.653 36.048 22.129 39.768 ;
     RECT  21.449 40.992 22.129 42.6 ;
     RECT  21.059 33.648 22.201 34.92 ;
     RECT  21.989 14.88 22.205 22.152 ;
     RECT  21.683 28.176 22.241 32.616 ;
     RECT  21.449 43.584 22.273 46.152 ;
     RECT  21.377 47.664 22.273 47.736 ;
     RECT  22.273 43.584 22.381 47.736 ;
     RECT  21.589 48.768 22.381 59.88 ;
     RECT  22.412 3.168 22.415 3.192 ;
     RECT  22.201 33.648 22.453 34.968 ;
     RECT  22.241 28.176 22.457 32.088 ;
     RECT  21.373 6.672 22.601 13.608 ;
     RECT  22.601 7.056 22.673 13.608 ;
     RECT  22.415 3.168 22.709 4.104 ;
     RECT  21.989 24.48 22.777 26.904 ;
     RECT  22.129 36.048 22.817 42.6 ;
     RECT  22.453 33.648 22.889 35.016 ;
     RECT  22.777 24.48 22.925 27.576 ;
     RECT  22.817 37.104 22.957 42.6 ;
     RECT  22.381 43.584 22.957 59.88 ;
     RECT  22.673 13.248 23.021 13.608 ;
     RECT  23.137 61.536 23.209 61.56 ;
     RECT  23.021 13.248 23.269 13.704 ;
     RECT  23.209 61.536 23.317 62.472 ;
     RECT  23.281 65.52 23.317 65.544 ;
     RECT  23.269 13.248 23.605 13.896 ;
     RECT  22.205 14.88 23.605 22.104 ;
     RECT  22.889 33.648 23.605 34.776 ;
     RECT  22.957 37.104 23.677 59.88 ;
     RECT  22.457 28.704 23.713 32.088 ;
     RECT  23.605 33.312 23.713 34.776 ;
     RECT  22.709 4.08 23.857 4.104 ;
     RECT  22.673 7.056 23.893 12.264 ;
     RECT  23.605 13.248 23.893 22.104 ;
     RECT  22.925 24.48 23.929 27.192 ;
     RECT  20.585 64.368 23.929 64.392 ;
     RECT  23.857 3.408 24.008 4.104 ;
     RECT  23.893 7.056 24.008 22.104 ;
     RECT  23.929 24.144 24.008 27.192 ;
     RECT  23.713 28.704 24.008 34.776 ;
     RECT  22.817 36.048 24.008 36.072 ;
     RECT  23.677 37.104 24.008 60.36 ;
     RECT  23.317 61.536 24.008 62.568 ;
     RECT  23.929 63.6 24.008 64.392 ;
     RECT  23.317 65.52 24.008 66.264 ;
     RECT  24.008 2.148 24.112 66.972 ;
     RECT  24.112 2.418 24.304 66.702 ;
     RECT  24.304 37.152 24.869 55.944 ;
     RECT  24.304 6.384 24.941 22.728 ;
     RECT  24.304 24.048 25.043 35.064 ;
     RECT  24.941 13.296 25.085 22.728 ;
     RECT  24.304 64.848 25.085 66.696 ;
     RECT  24.941 9.792 25.193 12.312 ;
     RECT  25.085 13.584 25.235 22.728 ;
     RECT  25.193 9.792 25.283 12.024 ;
     RECT  25.283 10.08 25.301 12.024 ;
     RECT  24.869 43.584 25.331 55.944 ;
     RECT  25.043 24.048 25.369 27.336 ;
     RECT  25.043 28.464 25.481 35.064 ;
     RECT  25.085 64.848 25.517 66.168 ;
     RECT  24.304 3.408 25.585 3.432 ;
     RECT  24.304 56.976 25.585 59.88 ;
     RECT  24.304 60.96 25.585 62.568 ;
     RECT  25.331 49.536 25.621 55.944 ;
     RECT  25.585 56.976 25.621 62.568 ;
     RECT  24.304 63.6 25.657 63.624 ;
     RECT  25.621 49.536 25.667 62.568 ;
     RECT  25.667 55.776 25.733 62.568 ;
     RECT  25.331 43.584 25.769 48.168 ;
     RECT  25.733 57.456 25.861 62.568 ;
     RECT  25.657 63.6 25.861 63.672 ;
     RECT  25.861 57.456 25.868 63.672 ;
     RECT  25.369 23.952 25.877 27.336 ;
     RECT  25.868 57.456 25.877 64.632 ;
     RECT  25.877 62.448 25.907 64.632 ;
     RECT  24.869 37.152 25.949 42.552 ;
     RECT  25.481 28.464 26.021 34.776 ;
     RECT  25.877 57.456 26.099 61.272 ;
     RECT  25.235 13.824 26.125 22.728 ;
     RECT  25.585 3.408 26.197 3.816 ;
     RECT  25.729 2.256 26.243 2.28 ;
     RECT  26.197 3.36 26.243 3.816 ;
     RECT  26.099 57.552 26.273 61.272 ;
     RECT  26.125 13.824 26.453 23.352 ;
     RECT  24.304 36.048 26.485 36.072 ;
     RECT  25.949 37.152 26.485 39.912 ;
     RECT  25.949 41.04 26.533 42.552 ;
     RECT  25.769 43.584 26.533 46.92 ;
     RECT  26.273 58.128 26.561 61.272 ;
     RECT  25.907 62.544 26.593 64.632 ;
     RECT  25.517 66.144 26.593 66.168 ;
     RECT  25.301 10.08 26.629 11.976 ;
     RECT  25.769 47.904 26.701 48.168 ;
     RECT  26.701 47.904 26.725 48.504 ;
     RECT  25.667 49.536 26.725 54.744 ;
     RECT  26.725 47.904 26.773 54.744 ;
     RECT  25.733 55.776 26.773 56.472 ;
     RECT  24.941 6.384 26.779 8.808 ;
     RECT  26.773 47.904 26.849 56.472 ;
     RECT  26.485 36.048 26.953 39.912 ;
     RECT  26.533 41.04 26.953 46.92 ;
     RECT  26.453 14.688 26.957 23.352 ;
     RECT  26.779 6.384 27.065 8.76 ;
     RECT  27.065 6.672 27.137 8.76 ;
     RECT  26.953 36.048 27.173 46.92 ;
     RECT  26.243 3.36 27.241 3.384 ;
     RECT  26.849 51.072 27.313 56.472 ;
     RECT  27.241 3.36 27.325 3.96 ;
     RECT  27.173 44.928 27.349 46.92 ;
     RECT  26.849 47.904 27.349 49.896 ;
     RECT  27.313 51.072 27.385 56.904 ;
     RECT  26.561 58.128 27.385 61.08 ;
     RECT  26.629 10.08 27.389 13.704 ;
     RECT  26.593 62.544 27.421 66.168 ;
     RECT  26.021 28.8 27.457 34.776 ;
     RECT  27.173 36.048 27.461 43.944 ;
     RECT  27.461 39.744 27.491 43.944 ;
     RECT  27.421 62.544 27.491 66.36 ;
     RECT  27.389 13.104 27.541 13.704 ;
     RECT  27.325 3.36 27.601 3.384 ;
     RECT  27.385 51.072 27.677 61.08 ;
     RECT  27.349 44.928 27.713 49.896 ;
     RECT  27.457 28.8 27.745 34.968 ;
     RECT  27.461 36.048 27.745 38.664 ;
     RECT  27.677 51.168 27.745 61.08 ;
     RECT  27.745 51.168 27.781 61.416 ;
     RECT  27.491 62.544 27.781 65.256 ;
     RECT  27.781 51.168 27.785 65.256 ;
     RECT  27.785 61.392 27.857 65.256 ;
     RECT  27.491 66.336 27.965 66.36 ;
     RECT  27.713 44.928 28.073 49.56 ;
     RECT  27.857 61.392 28.073 64.632 ;
     RECT  28.073 48.48 28.109 49.56 ;
     RECT  28.073 61.392 28.145 63.288 ;
     RECT  27.491 39.84 28.177 43.944 ;
     RECT  28.073 44.928 28.177 47.112 ;
     RECT  26.957 14.688 28.213 22.776 ;
     RECT  27.785 51.168 28.259 60.024 ;
     RECT  27.541 13.104 28.397 13.656 ;
     RECT  27.137 6.768 28.429 8.76 ;
     RECT  27.745 28.8 28.433 38.664 ;
     RECT  27.601 2.832 28.501 3.384 ;
     RECT  28.213 14.688 28.501 23.304 ;
     RECT  25.877 24.72 28.501 27.336 ;
     RECT  28.429 6.672 28.537 8.76 ;
     RECT  28.145 61.392 28.789 62.904 ;
     RECT  28.073 64.608 28.825 64.632 ;
     RECT  28.397 13.152 28.933 13.656 ;
     RECT  28.501 14.688 28.933 27.336 ;
     RECT  28.109 48.624 28.933 49.56 ;
     RECT  28.825 64.608 29.041 65.592 ;
     RECT  28.177 39.84 29.113 47.112 ;
     RECT  28.933 48.624 29.113 50.184 ;
     RECT  28.537 6.672 29.149 9.096 ;
     RECT  27.389 10.08 29.149 11.976 ;
     RECT  28.501 2.832 29.185 3.432 ;
     RECT  29.005 4.608 29.185 4.632 ;
     RECT  28.433 34.128 29.185 38.664 ;
     RECT  28.259 56.352 29.221 57.048 ;
     RECT  28.259 58.128 29.221 60.024 ;
     RECT  28.789 61.056 29.221 62.904 ;
     RECT  29.041 64.608 29.221 66.552 ;
     RECT  29.185 2.832 29.408 4.632 ;
     RECT  29.149 6.672 29.408 11.976 ;
     RECT  28.933 13.152 29.408 27.336 ;
     RECT  28.433 28.8 29.408 33.048 ;
     RECT  29.185 34.128 29.408 38.808 ;
     RECT  29.113 39.84 29.408 50.184 ;
     RECT  28.259 51.168 29.408 55.224 ;
     RECT  29.221 56.256 29.408 60.024 ;
     RECT  29.221 61.056 29.408 66.552 ;
     RECT  29.408 2.148 29.512 66.972 ;
     RECT  29.512 2.418 29.704 66.702 ;
     RECT  29.704 45.168 29.765 46.104 ;
     RECT  29.704 47.088 29.765 55.224 ;
     RECT  29.704 3.312 29.801 4.488 ;
     RECT  29.704 61.2 29.891 66.552 ;
     RECT  29.891 62.256 29.945 66.552 ;
     RECT  29.704 13.152 30.053 25.56 ;
     RECT  29.801 3.312 30.419 4.104 ;
     RECT  29.704 26.544 30.629 44.184 ;
     RECT  29.704 56.256 30.709 59.928 ;
     RECT  29.765 48.528 30.733 55.224 ;
     RECT  29.765 45.312 30.841 46.104 ;
     RECT  29.765 47.088 30.841 47.112 ;
     RECT  29.704 6.672 30.877 11.976 ;
     RECT  30.053 13.152 30.877 25.512 ;
     RECT  30.733 48.384 30.877 55.224 ;
     RECT  30.709 56.256 30.877 57.384 ;
     RECT  30.419 4.08 30.881 4.104 ;
     RECT  30.629 34.128 30.917 44.184 ;
     RECT  30.877 48.384 30.989 57.384 ;
     RECT  30.629 26.544 31.097 33.144 ;
     RECT  29.945 62.448 31.129 66.552 ;
     RECT  30.989 48.528 31.133 57.384 ;
     RECT  29.891 61.2 31.201 61.224 ;
     RECT  31.129 62.448 31.201 66.744 ;
     RECT  31.201 61.2 31.241 66.744 ;
     RECT  30.917 34.224 31.277 44.184 ;
     RECT  30.877 6.672 31.309 25.512 ;
     RECT  31.097 26.544 31.309 32.232 ;
     RECT  31.277 34.224 31.313 40.488 ;
     RECT  31.313 37.056 31.349 40.488 ;
     RECT  30.841 45.312 31.417 47.112 ;
     RECT  31.241 61.968 31.475 66.744 ;
     RECT  31.475 61.968 31.516 64.872 ;
     RECT  31.277 41.712 31.525 44.184 ;
     RECT  31.417 45.312 31.525 47.544 ;
     RECT  31.309 2.736 31.741 2.76 ;
     RECT  31.133 48.528 31.817 57.144 ;
     RECT  31.309 6.672 31.889 32.232 ;
     RECT  31.817 49.44 31.889 57.144 ;
     RECT  31.889 56.352 31.925 57.144 ;
     RECT  31.741 2.736 32.033 3.912 ;
     RECT  31.516 61.968 32.069 64.392 ;
     RECT  31.475 66.384 32.141 66.744 ;
     RECT  31.889 9.984 32.173 32.232 ;
     RECT  31.889 49.44 32.177 55.32 ;
     RECT  32.033 3.024 32.213 3.912 ;
     RECT  32.213 3.408 32.249 3.912 ;
     RECT  32.069 64.032 32.285 64.392 ;
     RECT  31.525 41.712 32.321 47.544 ;
     RECT  32.173 9.984 32.353 32.76 ;
     RECT  32.177 50.736 32.357 55.32 ;
     RECT  32.285 64.032 32.357 64.296 ;
     RECT  32.321 45.792 32.437 47.544 ;
     RECT  32.137 60.96 32.485 60.984 ;
     RECT  32.069 61.968 32.485 62.664 ;
     RECT  32.353 9.984 32.533 33.144 ;
     RECT  31.313 34.224 32.533 36.072 ;
     RECT  32.533 9.984 32.537 36.072 ;
     RECT  31.349 37.056 32.537 38.856 ;
     RECT  32.437 45.792 32.537 47.976 ;
     RECT  32.537 9.984 32.573 34.776 ;
     RECT  32.573 12.768 32.645 34.776 ;
     RECT  32.537 37.2 32.681 38.856 ;
     RECT  31.349 39.84 32.713 40.488 ;
     RECT  32.321 41.712 32.713 44.184 ;
     RECT  31.925 56.496 32.725 57.144 ;
     RECT  30.709 58.704 32.725 59.928 ;
     RECT  32.645 12.816 32.753 34.776 ;
     RECT  32.725 56.496 32.821 59.928 ;
     RECT  32.485 60.96 32.821 62.664 ;
     RECT  32.573 9.984 32.893 11.784 ;
     RECT  32.753 13.104 32.915 34.776 ;
     RECT  32.537 45.984 32.917 47.976 ;
     RECT  32.681 37.392 32.929 38.856 ;
     RECT  32.713 39.84 32.929 44.184 ;
     RECT  32.357 55.056 33.005 55.32 ;
     RECT  32.929 37.392 33.041 44.184 ;
     RECT  31.889 6.672 33.073 8.808 ;
     RECT  32.893 9.84 33.073 11.784 ;
     RECT  32.177 49.44 33.145 49.56 ;
     RECT  32.357 50.736 33.145 53.832 ;
     RECT  33.041 37.392 33.221 43.464 ;
     RECT  33.005 55.296 33.329 55.32 ;
     RECT  32.821 56.496 33.329 62.664 ;
     RECT  33.329 56.496 33.397 60.504 ;
     RECT  33.145 49.44 33.433 53.832 ;
     RECT  33.397 56.256 33.437 60.504 ;
     RECT  32.389 5.136 33.473 5.16 ;
     RECT  32.537 35.808 33.505 36.072 ;
     RECT  32.917 45.984 33.541 48.264 ;
     RECT  33.433 49.44 33.541 53.88 ;
     RECT  33.221 37.392 33.545 43.368 ;
     RECT  32.357 64.032 33.545 64.248 ;
     RECT  33.073 6.672 33.587 11.784 ;
     RECT  33.545 64.032 33.685 64.2 ;
     RECT  33.605 5.664 33.689 5.688 ;
     RECT  33.505 35.76 33.761 36.072 ;
     RECT  33.685 63.792 33.797 64.2 ;
     RECT  32.141 66.72 33.797 66.744 ;
     RECT  33.761 35.808 33.865 36.072 ;
     RECT  33.545 37.392 33.865 38.568 ;
     RECT  33.329 61.728 33.937 62.664 ;
     RECT  33.797 63.792 33.937 64.152 ;
     RECT  32.915 13.104 34.045 32.76 ;
     RECT  32.249 3.408 34.117 3.432 ;
     RECT  34.117 3.408 34.124 4.008 ;
     RECT  33.437 56.256 34.477 60.072 ;
     RECT  34.045 12.864 34.513 32.76 ;
     RECT  32.915 34.224 34.513 34.776 ;
     RECT  33.587 9.84 34.585 11.784 ;
     RECT  34.513 12.864 34.585 34.776 ;
     RECT  34.477 56.256 34.657 60.312 ;
     RECT  34.657 56.064 34.685 60.312 ;
     RECT  33.937 61.728 34.685 64.152 ;
     RECT  33.541 45.984 34.693 53.88 ;
     RECT  33.587 6.672 34.765 8.808 ;
     RECT  34.585 9.84 34.765 34.776 ;
     RECT  34.124 3.312 34.808 4.008 ;
     RECT  34.765 6.672 34.808 34.776 ;
     RECT  33.865 35.808 34.808 38.568 ;
     RECT  33.545 39.792 34.808 43.368 ;
     RECT  34.693 45.984 34.808 53.928 ;
     RECT  34.685 56.064 34.808 64.152 ;
     RECT  34.729 65.136 34.808 65.16 ;
     RECT  34.808 2.148 34.912 66.972 ;
     RECT  34.912 2.418 35.104 66.702 ;
     RECT  35.104 63.6 35.417 63.624 ;
     RECT  35.104 6.432 35.453 38.856 ;
     RECT  35.453 24.432 35.633 38.856 ;
     RECT  35.104 39.84 35.669 43.032 ;
     RECT  35.669 39.84 35.885 40.296 ;
     RECT  35.453 6.432 35.921 23.352 ;
     RECT  35.104 55.056 36.124 62.568 ;
     RECT  35.104 45.024 36.277 54.072 ;
     RECT  36.124 55.536 36.349 62.568 ;
     RECT  35.633 24.432 36.353 33 ;
     RECT  36.349 55.536 36.38 62.808 ;
     RECT  36.277 45.024 36.385 54.168 ;
     RECT  35.921 6.576 36.461 23.352 ;
     RECT  36.38 55.536 36.467 62.856 ;
     RECT  36.461 23.088 36.533 23.352 ;
     RECT  35.104 2.832 36.569 4.296 ;
     RECT  36.461 6.576 36.569 22.104 ;
     RECT  36.569 6.576 36.605 12.024 ;
     RECT  35.669 41.712 36.781 43.032 ;
     RECT  36.385 44.736 36.997 54.168 ;
     RECT  36.353 24.72 37.073 33 ;
     RECT  36.467 55.536 37.105 62.808 ;
     RECT  35.633 34.224 37.141 38.856 ;
     RECT  36.421 63.84 37.145 63.864 ;
     RECT  37.141 33.936 37.333 38.856 ;
     RECT  35.885 39.84 37.333 39.912 ;
     RECT  37.333 33.936 37.42 39.912 ;
     RECT  36.997 44.64 37.429 54.168 ;
     RECT  37.105 55.44 37.429 62.808 ;
     RECT  36.569 13.104 37.537 22.104 ;
     RECT  36.533 23.088 37.537 23.16 ;
     RECT  36.601 66.096 37.537 66.12 ;
     RECT  36.529 5.472 37.573 5.496 ;
     RECT  37.429 44.64 37.619 62.808 ;
     RECT  36.569 2.832 37.753 3.72 ;
     RECT  36.605 7.152 37.753 11.784 ;
     RECT  37.619 61.968 37.757 62.808 ;
     RECT  37.537 65.376 37.829 66.12 ;
     RECT  37.619 44.64 37.861 60.6 ;
     RECT  37.753 2.832 37.933 4.248 ;
     RECT  37.861 44.448 37.937 60.6 ;
     RECT  37.537 13.104 38.009 23.16 ;
     RECT  37.42 39.84 38.041 39.912 ;
     RECT  37.937 44.448 38.099 56.904 ;
     RECT  38.009 23.088 38.185 23.16 ;
     RECT  37.073 24.72 38.221 32.616 ;
     RECT  36.781 41.568 38.225 43.032 ;
     RECT  37.933 2.496 38.261 4.248 ;
     RECT  38.041 39.84 38.297 40.44 ;
     RECT  37.937 57.888 38.297 60.6 ;
     RECT  37.757 62.016 38.329 62.808 ;
     RECT  38.225 41.568 38.332 42.936 ;
     RECT  37.753 6.96 38.365 11.784 ;
     RECT  38.009 13.104 38.365 22.104 ;
     RECT  38.261 2.496 38.396 3.72 ;
     RECT  38.396 2.256 38.483 3.72 ;
     RECT  38.221 24.672 38.579 32.616 ;
     RECT  38.483 2.832 38.621 3.72 ;
     RECT  37.42 33.936 38.689 38.856 ;
     RECT  38.297 39.84 38.689 39.912 ;
     RECT  38.689 33.936 38.725 39.912 ;
     RECT  38.332 41.568 38.725 42.552 ;
     RECT  38.297 57.888 38.729 60.552 ;
     RECT  38.621 2.832 38.801 3.144 ;
     RECT  38.579 28.128 38.819 32.616 ;
     RECT  38.329 62.016 38.837 63.144 ;
     RECT  38.185 23.088 38.869 23.4 ;
     RECT  38.579 24.672 38.869 26.808 ;
     RECT  38.113 64.32 38.873 64.344 ;
     RECT  38.365 6.96 39.017 22.104 ;
     RECT  37.829 65.376 39.121 66.072 ;
     RECT  38.099 44.688 39.157 56.904 ;
     RECT  38.837 62.016 39.161 62.664 ;
     RECT  39.157 44.4 39.193 56.904 ;
     RECT  38.729 57.888 39.193 60.36 ;
     RECT  39.193 44.4 39.197 60.36 ;
     RECT  39.197 44.4 39.301 58.728 ;
     RECT  38.725 41.376 39.349 42.552 ;
     RECT  38.819 28.416 39.397 32.616 ;
     RECT  38.725 33.648 39.397 39.912 ;
     RECT  37.573 5.472 39.409 5.688 ;
     RECT  39.409 4.512 39.517 5.688 ;
     RECT  39.017 6.96 39.517 11.784 ;
     RECT  39.161 62.016 39.589 62.568 ;
     RECT  39.017 13.104 39.661 22.104 ;
     RECT  38.869 23.088 39.661 26.808 ;
     RECT  38.801 3.12 39.877 3.144 ;
     RECT  39.517 4.512 39.877 11.784 ;
     RECT  39.661 13.104 39.949 26.808 ;
     RECT  39.397 28.416 39.949 39.912 ;
     RECT  39.949 13.104 40.057 39.912 ;
     RECT  39.349 41.376 40.057 42.6 ;
     RECT  39.877 2.88 40.208 11.784 ;
     RECT  40.057 13.104 40.208 42.6 ;
     RECT  39.301 43.824 40.208 58.728 ;
     RECT  39.197 59.856 40.208 60.36 ;
     RECT  39.589 61.632 40.208 62.568 ;
     RECT  39.121 64.992 40.208 66.072 ;
     RECT  40.208 2.148 40.312 66.972 ;
     RECT  40.312 2.418 40.504 66.702 ;
     RECT  40.504 64.992 40.673 66.504 ;
     RECT  40.504 49.248 40.853 63.24 ;
     RECT  40.853 59.76 40.961 63.24 ;
     RECT  40.673 64.992 40.997 66.072 ;
     RECT  40.853 49.248 41.069 58.728 ;
     RECT  40.504 23.088 41.249 42.552 ;
     RECT  40.961 61.584 41.533 63.24 ;
     RECT  41.249 27.936 41.651 42.552 ;
     RECT  40.997 66.048 41.677 66.072 ;
     RECT  41.677 66.048 41.717 66.36 ;
     RECT  40.504 3.936 41.797 3.96 ;
     RECT  40.504 5.28 41.797 5.496 ;
     RECT  40.504 12.768 41.845 22.104 ;
     RECT  41.249 23.088 41.845 26.808 ;
     RECT  41.651 39.792 41.861 42.552 ;
     RECT  41.797 3.936 41.884 5.496 ;
     RECT  41.651 27.936 41.897 38.76 ;
     RECT  41.069 58.704 41.941 58.728 ;
     RECT  40.961 59.76 41.941 60.36 ;
     RECT  40.504 44.352 41.965 48.024 ;
     RECT  41.069 49.248 41.965 57.336 ;
     RECT  40.997 64.992 42.001 65.016 ;
     RECT  41.533 61.584 42.037 63.624 ;
     RECT  42.001 64.992 42.037 65.304 ;
     RECT  41.845 12.768 42.077 26.808 ;
     RECT  41.965 44.352 42.133 57.336 ;
     RECT  42.133 44.016 42.217 57.336 ;
     RECT  41.941 58.704 42.217 60.36 ;
     RECT  42.037 61.584 42.401 65.304 ;
     RECT  42.401 61.584 42.421 62.568 ;
     RECT  40.504 7.152 42.433 11.784 ;
     RECT  42.077 12.768 42.433 23.448 ;
     RECT  41.861 39.84 42.433 42.552 ;
     RECT  42.217 44.016 42.433 60.36 ;
     RECT  42.077 24.576 42.505 26.808 ;
     RECT  41.897 27.936 42.505 34.872 ;
     RECT  42.421 61.44 42.505 62.568 ;
     RECT  42.433 39.84 42.563 60.36 ;
     RECT  42.401 63.6 42.755 65.016 ;
     RECT  42.755 64.704 42.761 65.016 ;
     RECT  41.717 66.336 42.901 66.36 ;
     RECT  42.505 24.576 42.941 34.872 ;
     RECT  42.563 39.84 43.009 44.712 ;
     RECT  43.009 39.792 43.043 44.712 ;
     RECT  42.901 66.336 43.081 66.696 ;
     RECT  43.043 44.352 43.085 44.712 ;
     RECT  43.081 66.24 43.121 66.696 ;
     RECT  41.884 3.936 43.189 3.96 ;
     RECT  43.189 3.552 43.225 3.96 ;
     RECT  41.884 5.04 43.225 5.496 ;
     RECT  42.941 27.936 43.297 34.872 ;
     RECT  41.897 36.048 43.337 38.76 ;
     RECT  43.297 27.936 43.369 35.016 ;
     RECT  43.337 36.048 43.369 36.072 ;
     RECT  42.433 7.152 43.765 23.448 ;
     RECT  42.563 45.696 43.801 60.36 ;
     RECT  42.505 61.344 43.801 62.568 ;
     RECT  43.225 3.552 43.945 5.496 ;
     RECT  43.765 7.152 43.945 23.592 ;
     RECT  43.945 3.552 43.949 23.592 ;
     RECT  42.755 63.6 44.017 63.624 ;
     RECT  42.761 64.704 44.017 64.92 ;
     RECT  43.043 39.792 44.089 42.984 ;
     RECT  43.949 4.272 44.161 23.592 ;
     RECT  42.941 24.576 44.161 26.808 ;
     RECT  43.801 45.696 44.161 62.568 ;
     RECT  44.017 63.6 44.161 64.92 ;
     RECT  43.085 44.4 44.245 44.712 ;
     RECT  43.337 37.344 44.377 38.76 ;
     RECT  43.369 27.936 44.381 36.072 ;
     RECT  44.377 37.152 44.413 38.76 ;
     RECT  44.161 4.272 44.437 26.808 ;
     RECT  44.381 27.936 44.437 32.616 ;
     RECT  44.437 4.272 44.483 32.616 ;
     RECT  44.089 39.744 44.485 42.984 ;
     RECT  44.245 44.16 44.485 44.712 ;
     RECT  44.161 45.696 44.489 64.92 ;
     RECT  44.485 39.744 44.881 44.712 ;
     RECT  44.489 45.696 44.881 62.808 ;
     RECT  44.413 37.056 44.917 38.76 ;
     RECT  44.881 39.744 44.917 62.808 ;
     RECT  41.713 2.304 45.025 2.328 ;
     RECT  44.381 33.648 45.349 36.072 ;
     RECT  44.917 37.056 45.349 62.808 ;
     RECT  44.483 5.136 45.385 32.616 ;
     RECT  45.349 33.648 45.385 62.808 ;
     RECT  45.025 2.304 45.608 2.808 ;
     RECT  45.601 3.84 45.608 3.864 ;
     RECT  45.385 5.136 45.608 62.808 ;
     RECT  44.489 63.84 45.608 64.92 ;
     RECT  43.121 66.24 45.608 66.264 ;
     RECT  45.608 2.148 45.712 66.972 ;
     RECT  45.712 2.418 45.904 66.702 ;
     RECT  45.904 4.512 45.965 5.496 ;
     RECT  45.904 13.008 46.019 64.968 ;
     RECT  46.019 13.008 46.108 42.552 ;
     RECT  46.108 13.008 46.181 40.152 ;
     RECT  46.181 13.008 46.433 36.072 ;
     RECT  45.904 6.912 46.595 11.784 ;
     RECT  46.433 13.008 46.721 26.952 ;
     RECT  46.108 41.232 46.793 42.552 ;
     RECT  45.965 5.28 46.901 5.496 ;
     RECT  46.433 27.984 47.045 36.072 ;
     RECT  46.019 43.68 47.153 64.968 ;
     RECT  46.901 5.424 47.221 5.496 ;
     RECT  46.595 6.912 47.261 7.704 ;
     RECT  47.045 36 47.437 36.072 ;
     RECT  46.181 37.056 47.437 40.152 ;
     RECT  47.153 43.68 47.603 64.728 ;
     RECT  45.904 2.832 47.617 3.192 ;
     RECT  47.437 67.824 47.689 67.848 ;
     RECT  47.617 2.64 47.725 3.192 ;
     RECT  46.721 13.104 47.797 26.952 ;
     RECT  47.045 27.984 47.797 34.776 ;
     RECT  47.437 36 47.797 40.152 ;
     RECT  46.793 41.52 47.797 42.552 ;
     RECT  47.797 13.104 47.869 34.776 ;
     RECT  47.689 67.824 48.049 68.424 ;
     RECT  47.725 2.64 48.085 4.104 ;
     RECT  47.221 5.424 48.085 5.592 ;
     RECT  48.049 67.824 48.121 68.472 ;
     RECT  48.085 2.64 48.269 5.592 ;
     RECT  48.121 67.248 48.38 68.472 ;
     RECT  48.269 5.568 48.421 5.592 ;
     RECT  47.261 7.056 48.421 7.704 ;
     RECT  48.38 66.72 48.467 68.472 ;
     RECT  47.869 13.056 48.481 34.776 ;
     RECT  47.603 43.68 48.515 64.248 ;
     RECT  48.481 13.056 48.589 34.968 ;
     RECT  47.797 36 48.589 42.552 ;
     RECT  48.515 53.424 48.593 64.248 ;
     RECT  48.421 5.568 48.629 7.704 ;
     RECT  48.467 67.248 48.659 68.472 ;
     RECT  48.689 68.976 48.773 69 ;
     RECT  48.593 53.424 48.953 64.2 ;
     RECT  48.659 67.248 49.025 67.848 ;
     RECT  49.025 67.824 49.043 67.848 ;
     RECT  48.629 6.24 49.097 7.704 ;
     RECT  49.097 7.152 49.196 7.704 ;
     RECT  48.589 13.056 49.201 42.552 ;
     RECT  48.269 2.64 49.241 4.536 ;
     RECT  49.196 7.152 49.283 7.8 ;
     RECT  49.201 12.96 49.313 42.552 ;
     RECT  49.241 3.36 49.349 4.536 ;
     RECT  48.515 43.68 49.561 52.296 ;
     RECT  48.953 53.424 49.561 63.912 ;
     RECT  49.349 3.36 49.637 3.72 ;
     RECT  49.093 66.144 49.705 66.168 ;
     RECT  49.561 43.68 49.964 63.912 ;
     RECT  49.705 66.144 50.005 66.264 ;
     RECT  49.885 68.4 50.021 68.424 ;
     RECT  50.005 65.664 50.065 66.264 ;
     RECT  49.313 36 50.137 42.552 ;
     RECT  49.964 43.68 50.137 64.344 ;
     RECT  50.065 65.568 50.137 66.264 ;
     RECT  46.595 8.784 50.149 11.784 ;
     RECT  49.313 12.96 50.149 35.016 ;
     RECT  50.021 67.776 50.341 68.424 ;
     RECT  50.341 67.248 50.437 68.424 ;
     RECT  49.637 3.36 50.569 3.384 ;
     RECT  50.389 4.512 50.78 4.536 ;
     RECT  50.137 36 50.929 66.264 ;
     RECT  50.437 67.248 50.929 69 ;
     RECT  50.929 36 50.933 69 ;
     RECT  49.283 7.152 50.965 7.704 ;
     RECT  50.149 8.784 50.965 35.016 ;
     RECT  50.569 3.072 51.008 3.384 ;
     RECT  50.78 4.512 51.008 5.208 ;
     RECT  50.965 7.152 51.008 35.016 ;
     RECT  50.933 36 51.008 68.952 ;
     RECT  51.008 2.148 51.112 68.952 ;
     RECT  51.112 2.418 51.251 68.952 ;
     RECT  51.251 2.418 51.304 66.744 ;
     RECT  51.304 7.152 51.365 66.744 ;
     RECT  51.304 5.472 51.401 5.496 ;
     RECT  51.365 8.784 51.491 66.744 ;
     RECT  51.251 67.824 51.587 68.952 ;
     RECT  51.491 8.784 51.797 66.264 ;
     RECT  51.304 2.832 52.013 3.384 ;
     RECT  51.587 67.824 52.261 68.424 ;
     RECT  51.797 43.584 52.477 66.264 ;
     RECT  52.261 67.248 52.477 68.424 ;
     RECT  52.477 43.584 52.873 68.424 ;
     RECT  51.797 8.784 52.949 42.552 ;
     RECT  51.365 7.152 53.017 7.704 ;
     RECT  52.949 11.28 53.017 42.552 ;
     RECT  52.873 43.584 53.017 68.472 ;
     RECT  53.017 11.28 53.201 68.472 ;
     RECT  53.017 6.096 53.413 7.704 ;
     RECT  53.201 68.4 53.845 68.472 ;
     RECT  53.413 5.76 53.849 7.704 ;
     RECT  53.849 6.336 54.037 7.704 ;
     RECT  52.949 8.784 54.037 10.2 ;
     RECT  53.201 11.28 54.169 67.272 ;
     RECT  53.845 68.4 54.169 68.952 ;
     RECT  54.037 6.336 54.637 10.2 ;
     RECT  52.013 3.36 54.749 3.384 ;
     RECT  54.637 6.336 55.105 10.248 ;
     RECT  55.105 6.288 55.237 10.248 ;
     RECT  54.169 11.28 55.237 68.952 ;
     RECT  54.889 5.088 55.283 5.112 ;
     RECT  55.237 6.288 55.381 68.952 ;
     RECT  55.381 5.376 55.571 68.952 ;
     RECT  56.221 0.48 56.365 0.504 ;
     RECT  55.571 5.376 56.408 67.896 ;
     RECT  56.365 0.432 56.54 0.504 ;
     RECT  55.571 68.928 56.581 68.952 ;
     RECT  56.54 0.432 56.677 0.552 ;
     RECT  56.581 68.88 56.677 68.952 ;
     RECT  56.677 0.432 56.765 0.648 ;
     RECT  56.765 0.432 56.819 0.504 ;
     RECT  56.819 0.432 57.011 0.456 ;
     RECT  56.408 2.148 57.061 67.896 ;
     RECT  57.061 1.728 57.107 67.896 ;
     RECT  56.677 68.88 57.157 69 ;
     RECT  57.157 68.784 57.395 69 ;
     RECT  57.395 68.832 58.501 69 ;
     RECT  57.107 1.728 58.529 67.272 ;
     RECT  58.529 1.728 58.601 67.224 ;
     RECT  58.501 68.784 58.789 69 ;
     RECT  59.237 0.576 59.42 0.6 ;
     RECT  58.601 1.728 59.42 66.792 ;
     RECT  59.42 0.576 59.507 66.792 ;
     RECT  58.789 68.352 59.653 69 ;
     RECT  59.653 68.256 59.857 69 ;
     RECT  59.507 1.728 59.893 66.792 ;
     RECT  59.857 68.064 59.893 69 ;
     RECT  59.507 0.576 60.253 0.6 ;
     RECT  59.893 1.728 60.467 69 ;
     RECT  60.253 0.528 60.473 0.6 ;
     RECT  60.467 1.728 61.181 67.08 ;
     RECT  60.467 68.064 61.193 69 ;
     RECT  61.181 1.152 61.265 67.08 ;
     RECT  61.265 1.728 61.669 67.08 ;
     RECT  61.193 68.064 61.669 68.952 ;
     RECT  60.901 0.096 61.729 0.12 ;
     RECT  61.729 0.096 62.003 0.552 ;
     RECT  61.669 1.728 62.333 68.952 ;
     RECT  62.003 0.144 62.341 0.552 ;
     RECT  62.333 1.728 62.417 69 ;
     RECT  62.417 1.728 63.442 68.952 ;
     RECT  63.442 1.728 63.461 69 ;
     RECT  62.341 0.144 63.677 0.6 ;
     RECT  63.461 1.728 63.779 37.704 ;
     RECT  63.461 38.784 63.865 69 ;
     RECT  63.677 0.144 63.877 0.168 ;
     RECT  63.877 0.096 64.211 0.168 ;
     RECT  63.865 38.784 64.403 68.952 ;
     RECT  64.403 44.4 64.469 68.952 ;
     RECT  64.469 44.448 64.505 68.952 ;
     RECT  63.779 1.728 64.973 37.608 ;
     RECT  64.403 38.832 64.979 43.416 ;
     RECT  64.973 35.424 65.009 37.608 ;
     RECT  65.009 35.424 65.189 37.56 ;
     RECT  64.505 67.824 65.213 68.952 ;
     RECT  64.211 0.096 65.221 0.12 ;
     RECT  64.979 38.976 65.225 43.416 ;
     RECT  65.189 35.568 65.315 37.56 ;
     RECT  65.315 35.568 65.411 37.032 ;
     RECT  64.505 44.448 65.509 66.792 ;
     RECT  65.213 67.824 65.509 69 ;
     RECT  65.225 39.36 65.585 43.416 ;
     RECT  65.509 44.4 65.593 69 ;
     RECT  65.593 44.4 65.761 45.048 ;
     RECT  65.221 0.096 65.797 0.168 ;
     RECT  64.973 1.728 65.801 34.152 ;
     RECT  65.761 43.488 65.837 45.048 ;
     RECT  65.837 43.488 65.891 45 ;
     RECT  65.801 1.728 65.909 33.672 ;
     RECT  65.585 39.36 65.932 42.408 ;
     RECT  65.891 43.872 65.981 45 ;
     RECT  65.932 39.36 65.987 42.12 ;
     RECT  65.909 6.336 66.017 33.672 ;
     RECT  65.909 1.728 66.053 5.352 ;
     RECT  66.017 6.336 66.061 31.368 ;
     RECT  66.017 32.352 66.089 33.672 ;
     RECT  66.061 6.336 66.161 30.504 ;
     RECT  66.089 32.976 66.161 33.672 ;
     RECT  66.053 1.728 66.233 3.96 ;
     RECT  66.161 6.336 66.233 30.408 ;
     RECT  65.593 46.128 66.233 69 ;
     RECT  66.233 1.728 66.269 1.752 ;
     RECT  65.987 39.36 66.269 41.88 ;
     RECT  66.233 46.128 66.305 50.136 ;
     RECT  66.233 20.16 66.377 30.408 ;
     RECT  66.305 46.128 66.377 50.04 ;
     RECT  65.411 35.856 66.413 37.032 ;
     RECT  66.233 2.784 66.446 3.96 ;
     RECT  66.053 5.088 66.449 5.352 ;
     RECT  66.413 35.856 66.449 36.552 ;
     RECT  66.377 47.856 66.449 50.04 ;
     RECT  66.377 46.128 66.467 46.344 ;
     RECT  65.981 43.872 66.485 43.944 ;
     RECT  66.449 47.856 66.515 49.08 ;
     RECT  66.449 5.088 66.521 5.304 ;
     RECT  66.233 6.336 66.593 19.176 ;
     RECT  66.377 20.208 66.593 30.408 ;
     RECT  66.485 43.872 66.593 43.896 ;
     RECT  66.521 5.28 66.611 5.304 ;
     RECT  66.233 51.12 66.611 68.952 ;
     RECT  65.981 44.976 66.629 45 ;
     RECT  66.515 48.432 66.629 49.08 ;
     RECT  66.467 46.32 66.673 46.344 ;
     RECT  66.446 2.784 66.701 3.912 ;
     RECT  66.593 6.336 66.707 19.032 ;
     RECT  66.593 30.384 66.737 30.408 ;
     RECT  66.629 48.528 66.737 49.08 ;
     RECT  66.701 3.216 66.755 3.912 ;
     RECT  66.269 39.36 66.773 41.64 ;
     RECT  66.707 6.336 66.803 6.408 ;
     RECT  66.449 35.856 66.809 36.168 ;
     RECT  66.773 39.36 66.809 39.384 ;
     RECT  66.755 3.216 66.845 3.24 ;
     RECT  66.707 7.44 66.845 19.032 ;
     RECT  66.773 40.992 66.845 41.016 ;
     RECT  66.611 51.12 66.845 67.464 ;
     RECT  66.845 51.264 66.851 67.464 ;
     RECT  65.797 0.096 66.881 0.6 ;
     RECT  66.845 7.44 66.889 8.232 ;
     RECT  66.889 7.968 66.899 8.232 ;
     RECT  66.737 49.056 66.953 49.08 ;
     RECT  66.851 51.504 67.043 67.464 ;
     RECT  66.611 68.832 67.043 68.952 ;
     RECT  66.899 8.208 67.091 8.232 ;
     RECT  67.043 51.504 67.139 55.992 ;
     RECT  66.803 6.384 67.187 6.408 ;
     RECT  66.985 34.704 67.201 34.728 ;
     RECT  67.139 51.504 67.235 55.944 ;
     RECT  66.161 32.976 67.237 33.288 ;
     RECT  67.237 32.976 67.273 33.384 ;
     RECT  67.201 34.704 67.273 35.208 ;
     RECT  66.845 9.696 67.283 19.032 ;
     RECT  66.881 0.096 67.493 0.216 ;
     RECT  67.273 32.304 67.525 35.208 ;
     RECT  67.493 0.096 67.529 0.12 ;
     RECT  67.235 51.504 67.571 55.56 ;
     RECT  66.593 20.208 67.669 29.064 ;
     RECT  67.409 68.976 67.673 69 ;
     RECT  67.669 20.112 67.705 29.064 ;
     RECT  67.283 9.936 67.741 19.032 ;
     RECT  67.705 20.016 67.741 29.064 ;
     RECT  67.571 51.504 67.907 54.696 ;
     RECT  67.043 57.024 68.003 67.464 ;
     RECT  68.003 57.12 68.243 67.464 ;
     RECT  68.243 58.08 68.387 67.464 ;
     RECT  67.741 9.936 68.929 29.064 ;
     RECT  67.907 51.504 69.001 54.504 ;
     RECT  69.001 51.408 69.011 54.504 ;
     RECT  68.929 9.936 69.013 29.16 ;
     RECT  69.013 9.936 69.084 29.064 ;
     RECT  67.525 32.208 69.084 35.208 ;
     RECT  69.011 51.408 69.084 54.408 ;
     RECT  68.387 58.32 69.084 67.464 ;
    LAYER M5 ;
     RECT  56.592 0.016 67.464 0.227 ;
     RECT  56.592 0.227 67.272 0.563 ;
     RECT  56.688 0.563 67.272 0.659 ;
     RECT  56.88 0.659 67.272 2.137 ;
     RECT  2.4 2.137 2.52 2.151 ;
     RECT  7.8 2.137 7.92 2.151 ;
     RECT  13.2 2.137 13.32 2.151 ;
     RECT  18.6 2.137 18.72 2.151 ;
     RECT  24 2.137 24.12 2.151 ;
     RECT  29.4 2.137 29.52 2.151 ;
     RECT  34.8 2.137 34.92 2.151 ;
     RECT  40.2 2.137 40.32 2.151 ;
     RECT  45.6 2.137 45.72 2.151 ;
     RECT  51 2.137 51.12 2.151 ;
     RECT  7.8 2.151 8.112 2.581 ;
     RECT  6.816 2.581 8.112 2.723 ;
     RECT  29.4 2.151 29.712 2.821 ;
     RECT  0.144 2.005 0.168 2.867 ;
     RECT  38.448 2.245 38.472 2.867 ;
     RECT  40.2 2.151 40.512 2.869 ;
     RECT  28.512 2.821 29.712 3.301 ;
     RECT  34.8 2.151 35.112 3.301 ;
     RECT  26.208 2.245 26.232 3.349 ;
     RECT  7.8 2.723 8.112 3.397 ;
     RECT  28.512 3.301 30.408 3.443 ;
     RECT  10.848 2.821 10.872 3.493 ;
     RECT  10.848 3.493 11.592 3.539 ;
     RECT  13.2 2.151 13.512 3.685 ;
     RECT  26.208 3.349 26.712 3.827 ;
     RECT  26.688 3.827 26.712 3.925 ;
     RECT  39.888 2.869 40.512 3.971 ;
     RECT  13.2 3.685 13.608 4.019 ;
     RECT  34.176 3.301 35.112 4.019 ;
     RECT  22.464 3.157 22.488 4.115 ;
     RECT  29.4 3.443 30.408 4.115 ;
     RECT  51 2.151 51.312 4.501 ;
     RECT  48.096 2.629 48.12 4.547 ;
     RECT  43.344 3.589 43.368 4.595 ;
     RECT  17.184 2.821 17.208 4.883 ;
     RECT  7.8 3.397 8.712 4.885 ;
     RECT  7.8 4.885 9.672 4.931 ;
     RECT  41.808 4.501 41.832 5.029 ;
     RECT  44.448 4.261 44.472 5.171 ;
     RECT  11.568 3.539 11.592 5.267 ;
     RECT  55.248 5.077 55.272 5.365 ;
     RECT  56.4 2.137 67.272 5.365 ;
     RECT  45.6 2.151 45.912 5.461 ;
     RECT  41.808 5.029 42.36 5.507 ;
     RECT  15.36 6.229 15.384 6.899 ;
     RECT  20.112 3.925 20.136 6.997 ;
     RECT  20.112 6.997 20.52 7.043 ;
     RECT  18.6 2.151 18.912 7.045 ;
     RECT  29.4 4.115 29.712 7.045 ;
     RECT  29.4 7.045 30.312 7.187 ;
     RECT  24 2.151 24.312 7.189 ;
     RECT  7.8 4.931 8.112 7.237 ;
     RECT  0.144 7.093 0.168 7.283 ;
     RECT  53.136 6.325 53.16 7.333 ;
     RECT  50.832 4.501 51.312 7.379 ;
     RECT  20.496 7.043 20.52 7.381 ;
     RECT  33.648 5.653 33.672 7.381 ;
     RECT  53.136 7.333 54.072 7.429 ;
     RECT  55.248 5.365 67.272 7.429 ;
     RECT  7.8 7.237 8.232 7.477 ;
     RECT  34.8 4.019 35.112 7.573 ;
     RECT  48.432 6.229 48.456 7.619 ;
     RECT  34.8 7.573 35.4 7.715 ;
     RECT  2.4 2.151 2.712 7.861 ;
     RECT  13.2 4.019 13.512 7.909 ;
     RECT  20.496 7.381 21.096 7.909 ;
     RECT  26.688 3.925 27.288 7.909 ;
     RECT  42.336 5.507 42.36 7.909 ;
     RECT  14.496 7.189 14.52 7.955 ;
     RECT  23.472 7.189 24.312 7.955 ;
     RECT  2.4 7.861 2.808 8.003 ;
     RECT  40.2 3.971 40.512 8.005 ;
     RECT  44.544 6.277 44.568 8.051 ;
     RECT  18.6 7.045 19.032 8.197 ;
     RECT  20.496 7.909 21.144 8.197 ;
     RECT  36.528 8.245 36.552 8.341 ;
     RECT  36.384 8.341 36.552 8.437 ;
     RECT  39.504 8.005 40.512 8.485 ;
     RECT  41.712 7.909 42.36 8.485 ;
     RECT  45.6 5.461 46.152 8.485 ;
     RECT  13.056 7.909 13.512 8.579 ;
     RECT  33.072 7.381 33.672 8.675 ;
     RECT  53.136 7.429 67.272 8.675 ;
     RECT  25.872 7.909 27.288 8.723 ;
     RECT  25.872 8.723 26.76 8.771 ;
     RECT  23.904 7.955 24.312 8.819 ;
     RECT  26.448 8.771 26.76 8.819 ;
     RECT  39.504 8.485 42.36 8.965 ;
     RECT  36.384 8.437 37.32 9.013 ;
     RECT  34.8 7.715 35.208 9.061 ;
     RECT  36.384 9.013 38.136 9.061 ;
     RECT  54.576 8.675 67.272 9.203 ;
     RECT  29.4 7.187 30.216 9.349 ;
     RECT  53.136 8.675 53.16 9.349 ;
     RECT  22.32 8.245 22.344 9.397 ;
     RECT  34.8 9.061 38.136 9.539 ;
     RECT  29.4 9.349 30.648 9.541 ;
     RECT  22.272 9.397 22.344 9.587 ;
     RECT  0.192 9.445 0.216 9.635 ;
     RECT  44.256 8.725 44.28 9.637 ;
     RECT  45.6 8.485 46.584 9.637 ;
     RECT  67.248 9.203 67.272 9.731 ;
     RECT  24 8.819 24.312 9.781 ;
     RECT  44.256 9.637 46.584 9.925 ;
     RECT  39.312 8.965 42.36 10.069 ;
     RECT  26.448 8.819 26.472 10.213 ;
     RECT  33.552 8.675 33.672 10.213 ;
     RECT  13.2 8.579 13.512 10.261 ;
     RECT  18.6 8.197 21.144 10.307 ;
     RECT  44.256 9.925 46.824 10.307 ;
     RECT  22.272 9.587 22.296 10.597 ;
     RECT  26.448 10.213 26.808 10.741 ;
     RECT  18.6 10.307 19.992 10.789 ;
     RECT  26.448 10.741 27.384 10.789 ;
     RECT  22.128 10.597 22.296 10.835 ;
     RECT  7.632 7.477 8.232 10.837 ;
     RECT  12.672 10.261 13.512 10.883 ;
     RECT  24 9.781 25.272 10.885 ;
     RECT  26.448 10.789 27.528 10.885 ;
     RECT  29.28 9.541 30.648 10.981 ;
     RECT  49.248 7.765 49.272 10.981 ;
     RECT  51 7.379 51.312 10.981 ;
     RECT  54.576 9.203 66.216 11.027 ;
     RECT  15.984 10.309 16.008 11.173 ;
     RECT  17.664 10.789 19.992 11.173 ;
     RECT  39.312 10.069 43.224 11.221 ;
     RECT  44.256 10.307 44.28 11.221 ;
     RECT  39.312 11.221 44.28 11.267 ;
     RECT  29.28 10.981 30.936 11.317 ;
     RECT  38.304 10.789 38.328 11.365 ;
     RECT  39.312 11.267 44.184 11.365 ;
     RECT  38.304 11.365 44.184 11.411 ;
     RECT  15.984 11.173 19.992 11.459 ;
     RECT  32.592 10.213 33.672 11.509 ;
     RECT  34.8 9.539 37.32 11.509 ;
     RECT  49.248 10.981 51.312 11.509 ;
     RECT  52.656 9.349 53.16 11.509 ;
     RECT  49.248 11.509 53.16 11.699 ;
     RECT  16.752 11.459 19.992 11.749 ;
     RECT  21.12 10.307 21.144 11.749 ;
     RECT  22.896 10.837 22.92 11.797 ;
     RECT  24 10.885 27.528 11.797 ;
     RECT  50.16 11.699 53.16 11.845 ;
     RECT  54.576 11.027 66.12 11.845 ;
     RECT  16.752 11.749 21.144 11.891 ;
     RECT  21.12 11.891 21.144 11.941 ;
     RECT  0.144 11.701 0.168 11.987 ;
     RECT  21.12 11.941 21.384 11.987 ;
     RECT  22.896 11.797 27.528 11.987 ;
     RECT  40.2 11.411 44.184 12.035 ;
     RECT  50.16 11.845 66.12 12.563 ;
     RECT  3.936 12.469 3.96 12.611 ;
     RECT  7.632 10.837 8.328 13.045 ;
     RECT  16.752 11.891 19.992 13.091 ;
     RECT  40.2 12.035 42.84 13.091 ;
     RECT  50.4 12.563 66.12 13.139 ;
     RECT  6.864 13.045 8.328 13.187 ;
     RECT  16.752 13.091 19.656 13.427 ;
     RECT  47.904 13.045 48.504 13.429 ;
     RECT  40.2 13.091 42.792 13.475 ;
     RECT  0.144 13.333 0.168 13.619 ;
     RECT  13.2 10.883 13.512 13.621 ;
     RECT  32.592 11.509 37.32 13.621 ;
     RECT  38.304 11.411 39.048 13.621 ;
     RECT  16.752 13.427 19.416 13.667 ;
     RECT  26.448 11.987 27.528 13.715 ;
     RECT  29.28 11.317 31.08 13.859 ;
     RECT  32.592 13.621 39.048 14.099 ;
     RECT  47.904 13.429 49.272 14.101 ;
     RECT  22.896 11.987 25.272 14.197 ;
     RECT  26.448 13.715 26.472 14.197 ;
     RECT  7.632 13.187 8.328 14.339 ;
     RECT  22.896 14.197 26.472 14.435 ;
     RECT  44.064 12.035 44.184 14.485 ;
     RECT  45.6 10.307 46.824 14.485 ;
     RECT  22.896 14.435 24.408 14.675 ;
     RECT  21.36 11.987 21.384 14.773 ;
     RECT  16.272 13.861 16.296 14.867 ;
     RECT  17.328 13.667 19.416 14.867 ;
     RECT  29.28 13.859 29.712 15.013 ;
     RECT  40.2 13.475 40.512 15.061 ;
     RECT  25.776 14.435 26.472 15.203 ;
     RECT  41.712 13.475 42.792 15.301 ;
     RECT  44.064 14.485 46.824 15.301 ;
     RECT  41.712 15.301 46.824 15.443 ;
     RECT  22.896 14.675 24.312 15.731 ;
     RECT  32.976 14.099 39.048 15.779 ;
     RECT  47.904 14.101 49.368 15.925 ;
     RECT  50.4 13.139 66.024 15.925 ;
     RECT  13.2 13.621 13.608 16.019 ;
     RECT  32.976 15.779 33.672 16.067 ;
     RECT  47.904 15.925 66.024 16.067 ;
     RECT  23.232 15.731 24.312 16.213 ;
     RECT  31.008 13.859 31.08 16.261 ;
     RECT  40.08 15.061 40.512 16.405 ;
     RECT  41.712 15.443 42.36 16.405 ;
     RECT  26.448 15.203 26.472 16.453 ;
     RECT  30.72 16.261 31.08 16.453 ;
     RECT  9.648 4.931 9.672 16.595 ;
     RECT  17.328 14.867 18.912 16.595 ;
     RECT  29.088 15.013 29.712 16.597 ;
     RECT  30.72 16.453 31.32 16.597 ;
     RECT  13.2 16.019 13.512 16.789 ;
     RECT  23.232 16.213 24.408 16.981 ;
     RECT  33.552 16.067 33.672 16.981 ;
     RECT  34.8 15.779 39.048 16.981 ;
     RECT  33.552 16.981 39.048 17.029 ;
     RECT  40.08 16.405 42.36 17.029 ;
     RECT  21.36 14.773 21.912 17.077 ;
     RECT  23.232 16.981 25.224 17.123 ;
     RECT  7.632 14.339 8.232 17.125 ;
     RECT  29.088 16.597 31.32 17.171 ;
     RECT  21.072 17.077 21.912 17.219 ;
     RECT  23.232 17.123 25.08 17.219 ;
     RECT  0.144 17.173 0.168 17.459 ;
     RECT  47.904 16.067 49.272 17.605 ;
     RECT  50.4 16.067 66.024 17.605 ;
     RECT  0.24 17.461 0.264 17.651 ;
     RECT  33.552 17.029 42.36 17.651 ;
     RECT  29.088 17.171 31.08 17.843 ;
     RECT  13.056 16.789 13.512 17.989 ;
     RECT  33.984 17.651 42.36 18.083 ;
     RECT  13.056 17.989 13.656 18.133 ;
     RECT  14.832 16.405 14.856 18.133 ;
     RECT  13.056 18.133 14.856 18.179 ;
     RECT  33.984 18.083 38.808 18.179 ;
     RECT  21.888 17.219 21.912 18.181 ;
     RECT  23.232 17.219 24.408 18.181 ;
     RECT  47.904 17.605 66.024 18.275 ;
     RECT  26.448 16.453 27.336 18.373 ;
     RECT  26.208 18.373 27.336 18.419 ;
     RECT  44.064 15.443 46.824 18.613 ;
     RECT  29.088 17.843 31.032 18.659 ;
     RECT  21.888 18.181 24.408 18.755 ;
     RECT  39.84 18.083 42.36 18.755 ;
     RECT  13.056 18.179 14.712 18.851 ;
     RECT  34.8 18.179 38.808 18.851 ;
     RECT  29.136 18.659 31.032 18.899 ;
     RECT  43.824 18.613 46.824 18.949 ;
     RECT  48.288 18.275 65.016 19.091 ;
     RECT  13.2 18.851 14.712 19.139 ;
     RECT  13.2 19.139 14.232 19.235 ;
     RECT  38.304 18.851 38.808 19.235 ;
     RECT  27.216 18.419 27.336 19.283 ;
     RECT  53.808 19.091 65.016 19.333 ;
     RECT  66 18.275 66.024 19.333 ;
     RECT  34.8 18.851 36.696 19.427 ;
     RECT  21.888 18.755 24.312 19.475 ;
     RECT  43.824 18.949 47.112 19.523 ;
     RECT  22.272 19.475 24.312 19.571 ;
     RECT  38.304 19.235 38.568 19.571 ;
     RECT  34.8 19.427 36.456 19.619 ;
     RECT  32.928 19.093 32.952 19.621 ;
     RECT  26.208 18.419 26.232 19.813 ;
     RECT  27.216 19.283 27.24 19.813 ;
     RECT  26.208 19.813 27.24 19.859 ;
     RECT  7.632 17.125 9.144 19.955 ;
     RECT  13.2 19.235 13.656 20.003 ;
     RECT  39.84 18.755 40.632 20.005 ;
     RECT  41.712 18.755 42.36 20.005 ;
     RECT  29.136 18.899 29.712 20.195 ;
     RECT  39.84 20.005 42.36 20.339 ;
     RECT  43.824 19.523 46.824 20.437 ;
     RECT  31.008 18.899 31.032 20.485 ;
     RECT  0.144 20.341 0.168 20.531 ;
     RECT  43.68 20.437 46.824 20.579 ;
     RECT  22.272 19.571 22.296 21.107 ;
     RECT  26.208 19.859 26.808 21.109 ;
     RECT  13.2 20.003 13.608 21.155 ;
     RECT  48.288 19.091 52.824 21.155 ;
     RECT  18.432 16.595 18.912 21.203 ;
     RECT  39.84 20.339 40.512 21.203 ;
     RECT  44.928 20.579 46.824 21.251 ;
     RECT  11.088 15.637 11.112 21.301 ;
     RECT  29.4 20.195 29.712 21.349 ;
     RECT  41.712 20.339 42.36 21.397 ;
     RECT  26.208 21.109 27.288 21.539 ;
     RECT  7.632 19.955 8.664 21.731 ;
     RECT  48.288 21.155 49.272 21.827 ;
     RECT  41.712 21.397 42.648 22.117 ;
     RECT  43.68 20.579 43.8 22.117 ;
     RECT  45.024 21.251 46.824 22.165 ;
     RECT  31.008 20.485 31.896 22.211 ;
     RECT  41.712 22.117 43.8 22.259 ;
     RECT  45.024 22.165 47.016 22.259 ;
     RECT  41.712 22.259 43.704 22.403 ;
     RECT  26.736 21.539 27.288 22.499 ;
     RECT  31.008 22.211 31.368 22.499 ;
     RECT  53.808 19.333 66.024 22.501 ;
     RECT  48.72 21.827 49.272 22.549 ;
     RECT  50.304 21.155 52.824 22.549 ;
     RECT  27.264 22.499 27.288 22.787 ;
     RECT  32.928 19.621 33.336 22.835 ;
     RECT  53.808 22.501 66.12 22.883 ;
     RECT  31.344 22.499 31.368 22.979 ;
     RECT  7.632 21.731 8.568 23.171 ;
     RECT  20.496 21.637 20.52 23.171 ;
     RECT  40.2 21.203 40.512 23.173 ;
     RECT  41.712 22.403 41.976 23.173 ;
     RECT  32.928 22.835 33.288 23.269 ;
     RECT  4.56 22.165 4.584 23.411 ;
     RECT  28.512 21.349 29.712 23.843 ;
     RECT  17.328 16.595 17.352 23.893 ;
     RECT  32.832 23.269 33.288 24.083 ;
     RECT  54.48 22.883 66.12 24.083 ;
     RECT  13.2 21.155 13.512 24.277 ;
     RECT  16.512 23.893 17.352 24.659 ;
     RECT  54.48 24.083 66.072 24.659 ;
     RECT  38.544 19.571 38.568 24.661 ;
     RECT  40.2 23.173 41.976 24.661 ;
     RECT  10.56 21.301 11.112 24.707 ;
     RECT  54.48 24.659 65.88 24.707 ;
     RECT  43.008 22.403 43.704 24.755 ;
     RECT  54.48 24.707 65.688 24.851 ;
     RECT  38.544 24.661 41.976 24.899 ;
     RECT  12.96 24.277 13.512 24.949 ;
     RECT  12.96 24.949 13.704 25.043 ;
     RECT  24 19.571 24.312 25.093 ;
     RECT  54.48 24.851 65.544 25.139 ;
     RECT  24 25.093 24.504 25.189 ;
     RECT  34.8 19.619 36.12 25.189 ;
     RECT  18.6 21.203 18.912 25.285 ;
     RECT  24 25.189 24.6 25.523 ;
     RECT  34.8 25.189 36.84 25.571 ;
     RECT  24 25.523 24.312 25.573 ;
     RECT  54.48 25.139 65.496 25.573 ;
     RECT  18.6 25.285 19.512 25.715 ;
     RECT  45.072 22.259 47.016 25.715 ;
     RECT  54.432 25.573 65.496 25.715 ;
     RECT  13.008 25.043 13.704 25.763 ;
     RECT  43.68 24.755 43.704 26.099 ;
     RECT  20.832 25.669 20.856 26.197 ;
     RECT  23.856 25.573 24.312 26.243 ;
     RECT  17.328 24.659 17.352 26.291 ;
     RECT  20.832 26.197 21.672 26.291 ;
     RECT  32.928 24.083 33.288 26.437 ;
     RECT  34.8 25.571 36.12 26.437 ;
     RECT  38.544 24.899 40.512 26.531 ;
     RECT  45.264 25.715 47.016 26.533 ;
     RECT  48.72 22.549 52.824 26.533 ;
     RECT  31.488 26.533 31.512 26.629 ;
     RECT  31.392 26.629 31.512 26.675 ;
     RECT  45.264 26.533 52.824 26.675 ;
     RECT  5.376 25.045 5.4 26.725 ;
     RECT  18.6 25.715 18.912 26.725 ;
     RECT  32.928 26.437 36.12 26.725 ;
     RECT  41.952 24.899 41.976 26.725 ;
     RECT  13.008 25.763 13.512 26.915 ;
     RECT  32.88 26.725 36.12 26.917 ;
     RECT  46.992 26.675 52.824 26.963 ;
     RECT  18.432 26.725 18.912 27.205 ;
     RECT  45.264 26.675 45.912 27.301 ;
     RECT  4.896 26.725 5.4 27.347 ;
     RECT  38.544 26.531 38.568 27.347 ;
     RECT  47.808 26.963 52.824 27.395 ;
     RECT  47.808 27.395 48.744 27.635 ;
     RECT  54.432 25.715 64.968 27.683 ;
     RECT  32.832 26.917 36.12 27.685 ;
     RECT  32.832 27.685 36.408 27.779 ;
     RECT  10.56 24.707 10.584 27.877 ;
     RECT  16.608 27.301 16.632 27.877 ;
     RECT  18.336 27.205 18.912 27.877 ;
     RECT  24 26.243 24.312 27.877 ;
     RECT  29.4 23.843 29.712 27.877 ;
     RECT  31.392 26.675 31.416 27.877 ;
     RECT  9.648 27.877 10.584 27.923 ;
     RECT  13.2 26.915 13.512 27.925 ;
     RECT  21.648 26.291 21.672 27.925 ;
     RECT  5.376 27.347 5.4 27.971 ;
     RECT  21.216 27.925 21.672 27.971 ;
     RECT  40.08 26.531 40.512 28.019 ;
     RECT  41.952 26.725 42.072 28.307 ;
     RECT  34.8 27.779 36.408 28.451 ;
     RECT  9.648 27.923 9.672 28.453 ;
     RECT  44.448 27.301 45.912 28.453 ;
     RECT  13.2 27.925 13.656 28.549 ;
     RECT  54.528 27.683 64.968 28.645 ;
     RECT  13.104 28.549 13.656 28.787 ;
     RECT  16.608 27.877 18.912 28.789 ;
     RECT  24 27.877 25.032 29.029 ;
     RECT  54.528 28.645 65.112 29.029 ;
     RECT  68.976 28.933 69 29.171 ;
     RECT  16.608 28.789 19.704 29.219 ;
     RECT  7.632 23.171 8.232 29.221 ;
     RECT  32.832 27.779 33.288 29.363 ;
     RECT  13.2 28.787 13.656 29.365 ;
     RECT  34.8 28.451 36.12 29.461 ;
     RECT  37.248 28.501 37.272 29.461 ;
     RECT  34.8 29.461 37.272 29.557 ;
     RECT  34.8 29.557 37.32 29.605 ;
     RECT  54.528 29.029 65.592 29.605 ;
     RECT  24 29.029 25.08 29.699 ;
     RECT  44.448 28.453 46.008 29.699 ;
     RECT  45.6 29.699 46.008 29.795 ;
     RECT  50.208 27.395 52.824 29.893 ;
     RECT  54.528 29.605 66.024 29.893 ;
     RECT  21.216 27.971 21.24 30.229 ;
     RECT  12 29.605 12.024 30.275 ;
     RECT  21.024 30.229 21.24 30.275 ;
     RECT  42.048 28.307 42.072 30.275 ;
     RECT  10.704 27.925 10.728 30.371 ;
     RECT  16.608 29.219 18.912 30.419 ;
     RECT  9.456 28.453 9.672 30.467 ;
     RECT  4.656 29.077 4.68 30.563 ;
     RECT  34.8 29.605 37.416 30.613 ;
     RECT  38.784 28.117 38.808 30.613 ;
     RECT  7.632 29.221 8.28 30.803 ;
     RECT  10.8 30.757 10.824 30.805 ;
     RECT  40.2 28.019 40.512 30.853 ;
     RECT  10.8 30.805 10.92 30.899 ;
     RECT  16.608 30.419 16.824 30.995 ;
     RECT  40.2 30.853 41.208 30.995 ;
     RECT  13.2 29.365 14.184 31.379 ;
     RECT  19.92 30.181 19.944 31.379 ;
     RECT  34.8 30.613 38.808 31.379 ;
     RECT  50.208 29.893 66.024 31.379 ;
     RECT  44.448 29.699 44.472 31.427 ;
     RECT  50.208 31.379 65.208 31.475 ;
     RECT  24 29.699 24.648 31.523 ;
     RECT  9.648 30.467 9.672 31.525 ;
     RECT  10.896 30.899 10.92 31.667 ;
     RECT  48.72 27.635 48.744 31.715 ;
     RECT  17.904 30.419 18.912 31.763 ;
     RECT  37.296 31.379 37.416 31.859 ;
     RECT  32.832 29.363 32.952 31.907 ;
     RECT  37.296 31.859 37.32 31.907 ;
     RECT  5.136 30.853 5.16 31.955 ;
     RECT  50.208 31.475 64.968 31.955 ;
     RECT  16.608 30.995 16.632 32.099 ;
     RECT  7.632 30.803 8.232 32.149 ;
     RECT  9.648 31.525 9.768 32.149 ;
     RECT  34.8 31.379 36.12 32.195 ;
     RECT  29.4 27.877 31.416 32.243 ;
     RECT  38.784 31.379 38.808 32.389 ;
     RECT  40.2 30.995 40.512 32.437 ;
     RECT  13.2 31.379 13.992 32.531 ;
     RECT  32.88 31.907 32.952 32.627 ;
     RECT  50.208 31.955 64.824 33.013 ;
     RECT  21.024 30.275 21.048 33.107 ;
     RECT  40.2 32.437 41.016 33.107 ;
     RECT  50.208 33.013 64.968 33.299 ;
     RECT  49.008 33.013 49.032 33.349 ;
     RECT  48.912 33.349 49.032 33.395 ;
     RECT  13.2 32.531 13.608 33.539 ;
     RECT  18.432 31.763 18.912 33.541 ;
     RECT  38.736 32.389 38.808 33.541 ;
     RECT  40.2 33.107 40.512 33.541 ;
     RECT  11.568 31.909 11.592 33.683 ;
     RECT  32.88 32.627 32.904 33.683 ;
     RECT  38.736 33.541 40.512 33.683 ;
     RECT  48.912 33.395 48.936 34.067 ;
     RECT  50.208 33.299 52.632 34.261 ;
     RECT  53.664 33.299 64.968 34.261 ;
     RECT  38.784 33.683 40.512 34.307 ;
     RECT  47.28 33.541 47.304 34.307 ;
     RECT  4.08 33.637 4.104 34.355 ;
     RECT  22.704 33.637 22.728 34.355 ;
     RECT  24 31.523 24.552 34.355 ;
     RECT  28.272 34.405 28.296 34.547 ;
     RECT  50.208 34.261 64.968 34.547 ;
     RECT  18.432 33.541 19.848 34.597 ;
     RECT  21.6 33.637 21.624 34.835 ;
     RECT  45.6 29.795 45.912 34.837 ;
     RECT  18.288 34.597 19.848 34.979 ;
     RECT  0.192 34.981 0.216 35.267 ;
     RECT  7.632 32.149 9.768 35.507 ;
     RECT  53.664 34.547 64.968 35.557 ;
     RECT  34.8 32.195 35.304 35.603 ;
     RECT  29.4 32.243 30.696 35.653 ;
     RECT  13.2 33.539 13.512 35.845 ;
     RECT  50.208 34.547 52.536 35.845 ;
     RECT  53.664 35.557 65.4 35.845 ;
     RECT  48.816 35.221 48.84 35.893 ;
     RECT  7.8 35.507 9.768 36.083 ;
     RECT  29.088 35.653 30.696 36.419 ;
     RECT  38.784 35.269 38.808 36.517 ;
     RECT  13.056 35.845 13.512 36.563 ;
     RECT  50.208 35.845 65.4 36.805 ;
     RECT  37.824 36.517 38.808 36.947 ;
     RECT  48.816 35.893 48.936 37.045 ;
     RECT  48.816 37.045 49.032 37.091 ;
     RECT  29.28 36.419 30.696 37.139 ;
     RECT  48.912 37.091 49.032 37.235 ;
     RECT  29.4 37.139 30.696 37.427 ;
     RECT  7.8 36.083 8.808 37.429 ;
     RECT  5.376 36.997 5.4 37.619 ;
     RECT  7.8 37.429 8.904 37.619 ;
     RECT  37.824 36.947 37.848 37.667 ;
     RECT  7.8 37.619 8.808 37.907 ;
     RECT  29.4 37.427 29.976 37.907 ;
     RECT  45.36 34.837 45.912 38.005 ;
     RECT  36.48 37.573 36.504 38.149 ;
     RECT  36.48 38.149 37.368 38.195 ;
     RECT  27.888 37.621 27.912 38.341 ;
     RECT  41.568 35.077 41.592 38.387 ;
     RECT  18.288 34.979 19.368 38.483 ;
     RECT  27.552 38.341 27.912 38.483 ;
     RECT  27.888 38.483 27.912 38.675 ;
     RECT  48.912 37.235 48.936 38.677 ;
     RECT  48.72 38.677 48.936 38.723 ;
     RECT  21.456 37.573 21.48 38.725 ;
     RECT  14.832 38.869 14.856 39.059 ;
     RECT  20.736 38.725 21.48 39.061 ;
     RECT  48.72 38.723 48.744 39.251 ;
     RECT  0.144 39.013 0.168 39.299 ;
     RECT  20.736 39.061 22.44 39.347 ;
     RECT  7.8 37.907 8.568 39.395 ;
     RECT  45.36 38.005 46.008 39.395 ;
     RECT  50.208 36.805 65.496 39.587 ;
     RECT  37.344 38.195 37.368 39.731 ;
     RECT  26.544 39.301 26.568 39.733 ;
     RECT  26.544 39.733 27.48 39.875 ;
     RECT  9.936 38.917 9.96 39.877 ;
     RECT  45.6 39.395 46.008 39.877 ;
     RECT  5.04 38.149 5.064 39.923 ;
     RECT  29.4 37.907 29.832 39.971 ;
     RECT  50.4 39.587 65.496 40.165 ;
     RECT  45.6 39.877 46.056 40.835 ;
     RECT  13.2 36.563 13.512 40.837 ;
     RECT  13.104 40.837 13.512 40.981 ;
     RECT  18.288 38.483 18.912 40.981 ;
     RECT  50.4 40.165 66.12 40.981 ;
     RECT  9.936 39.877 10.776 41.027 ;
     RECT  13.104 40.981 14.232 41.171 ;
     RECT  2.4 8.003 2.712 41.269 ;
     RECT  41.616 38.917 41.64 41.365 ;
     RECT  41.616 41.365 42.168 41.411 ;
     RECT  21.456 39.347 22.44 41.413 ;
     RECT  21.456 41.413 23.016 41.555 ;
     RECT  38.736 41.365 38.76 41.557 ;
     RECT  45.6 40.835 46.008 41.651 ;
     RECT  50.4 40.981 66.648 41.699 ;
     RECT  9.936 41.027 9.96 41.893 ;
     RECT  38.256 41.557 38.76 41.893 ;
     RECT  9.696 41.893 9.96 41.939 ;
     RECT  38.256 41.893 38.808 42.035 ;
     RECT  34.8 35.603 35.112 42.085 ;
     RECT  36.912 41.749 36.936 42.085 ;
     RECT  45.6 41.651 45.912 42.085 ;
     RECT  40.2 34.307 40.512 42.133 ;
     RECT  47.808 41.029 47.832 42.179 ;
     RECT  12.048 41.461 12.072 42.181 ;
     RECT  11.808 42.181 12.072 42.227 ;
     RECT  18.288 40.981 19.032 42.227 ;
     RECT  22.992 41.555 23.016 42.227 ;
     RECT  27.888 40.933 27.912 42.227 ;
     RECT  2.4 41.269 3.384 42.515 ;
     RECT  21.456 41.555 21.48 42.517 ;
     RECT  39.36 42.133 40.512 42.611 ;
     RECT  4.512 42.037 4.536 42.709 ;
     RECT  34.8 42.085 36.936 42.755 ;
     RECT  4.512 42.709 4.68 42.803 ;
     RECT  20.496 42.517 21.48 42.803 ;
     RECT  43.344 42.085 43.368 42.803 ;
     RECT  30.768 42.709 31.272 42.851 ;
     RECT  38.256 42.035 38.28 42.947 ;
     RECT  26.544 39.875 26.568 42.997 ;
     RECT  26.544 42.997 26.76 43.043 ;
     RECT  31.248 42.851 31.272 43.235 ;
     RECT  4.656 42.803 4.68 43.283 ;
     RECT  45.024 42.085 45.912 43.285 ;
     RECT  42.144 41.411 42.168 43.813 ;
     RECT  11.808 42.227 11.832 44.099 ;
     RECT  45.024 43.285 46.008 44.149 ;
     RECT  40.2 42.611 40.512 44.341 ;
     RECT  39.648 44.341 40.512 44.389 ;
     RECT  42.144 43.813 43.032 44.437 ;
     RECT  9.696 41.939 9.72 44.483 ;
     RECT  10.704 43.285 10.728 44.579 ;
     RECT  21.456 42.803 21.48 44.579 ;
     RECT  16.032 43.813 16.056 44.675 ;
     RECT  44.256 44.149 46.008 44.867 ;
     RECT  34.8 42.755 36.072 45.059 ;
     RECT  6.288 43.237 6.312 45.155 ;
     RECT  38.064 44.437 38.088 45.301 ;
     RECT  21.696 44.581 21.72 45.541 ;
     RECT  12.048 44.437 12.072 45.587 ;
     RECT  50.832 41.699 66.648 45.589 ;
     RECT  48.48 44.437 48.504 45.827 ;
     RECT  45.6 44.867 46.008 45.925 ;
     RECT  18.288 42.227 18.912 46.021 ;
     RECT  44.256 44.867 44.472 46.069 ;
     RECT  45.6 45.925 46.056 46.069 ;
     RECT  36.096 45.157 36.168 46.115 ;
     RECT  7.8 39.395 8.112 46.117 ;
     RECT  44.256 46.069 46.056 46.117 ;
     RECT  13.2 41.171 14.232 46.163 ;
     RECT  10.656 44.917 10.68 46.165 ;
     RECT  10.512 46.165 10.68 46.211 ;
     RECT  50.16 45.589 66.648 46.355 ;
     RECT  10.512 46.211 10.536 46.405 ;
     RECT  44.256 46.117 46.104 46.691 ;
     RECT  2.4 42.515 2.712 46.693 ;
     RECT  26.736 43.043 26.76 46.741 ;
     RECT  21.168 45.541 21.72 46.787 ;
     RECT  7.68 46.117 8.112 46.885 ;
     RECT  7.68 46.885 8.568 47.171 ;
     RECT  10.224 46.405 10.536 47.173 ;
     RECT  11.568 46.357 11.592 47.173 ;
     RECT  2.4 46.693 3.48 47.267 ;
     RECT  25.632 43.861 25.656 47.317 ;
     RECT  25.392 47.317 25.656 47.363 ;
     RECT  37.44 45.301 38.088 47.363 ;
     RECT  10.224 47.173 11.592 47.555 ;
     RECT  41.52 44.437 43.032 47.555 ;
     RECT  21.696 46.787 21.72 47.701 ;
     RECT  39.168 44.389 40.512 47.843 ;
     RECT  10.224 47.555 11.304 47.845 ;
     RECT  7.8 47.171 8.568 47.891 ;
     RECT  41.52 47.555 42.792 47.891 ;
     RECT  36.144 46.115 36.168 47.939 ;
     RECT  18.096 46.021 18.912 48.133 ;
     RECT  15.984 47.173 16.008 48.179 ;
     RECT  32.448 47.941 32.472 48.229 ;
     RECT  33.648 34.597 33.672 48.229 ;
     RECT  39.312 47.843 40.512 48.371 ;
     RECT  44.256 46.691 46.056 48.421 ;
     RECT  6.24 47.845 6.264 48.467 ;
     RECT  26.736 46.741 27.048 48.515 ;
     RECT  43.824 48.421 46.872 48.515 ;
     RECT  21.696 47.701 21.816 48.709 ;
     RECT  24 34.355 24.312 48.757 ;
     RECT  21.12 48.709 21.816 48.803 ;
     RECT  29.4 39.971 29.712 48.805 ;
     RECT  45.264 48.515 46.872 48.805 ;
     RECT  21.12 48.803 21.72 48.899 ;
     RECT  25.392 47.363 25.416 48.901 ;
     RECT  21.696 48.899 21.72 48.947 ;
     RECT  26.736 48.515 26.76 48.947 ;
     RECT  38.16 47.845 38.184 48.947 ;
     RECT  42.336 47.891 42.792 48.947 ;
     RECT  50.16 46.355 66.552 48.947 ;
     RECT  50.544 48.947 66.552 48.997 ;
     RECT  9.936 47.845 11.304 49.043 ;
     RECT  7.8 47.891 8.112 49.477 ;
     RECT  32.448 48.229 33.672 49.571 ;
     RECT  9.936 49.043 11.16 49.619 ;
     RECT  25.296 48.901 25.416 49.619 ;
     RECT  30.912 48.661 30.936 49.619 ;
     RECT  48.576 46.597 48.6 49.909 ;
     RECT  17.664 48.133 18.912 50.051 ;
     RECT  13.2 46.163 13.512 50.101 ;
     RECT  18.096 50.051 18.912 50.101 ;
     RECT  50.544 48.997 66.6 50.101 ;
     RECT  10.224 49.619 11.16 50.147 ;
     RECT  7.488 49.477 8.112 50.195 ;
     RECT  29.04 48.805 29.712 50.195 ;
     RECT  48.288 49.909 48.6 50.723 ;
     RECT  32.448 49.571 32.472 50.771 ;
     RECT  23.568 48.757 24.312 50.773 ;
     RECT  39.84 48.371 40.512 50.773 ;
     RECT  45.264 48.805 47.304 50.917 ;
     RECT  23.376 50.773 24.312 50.963 ;
     RECT  6.384 50.101 6.408 50.965 ;
     RECT  39.84 50.773 41.064 51.203 ;
     RECT  7.8 50.195 8.112 51.205 ;
     RECT  50.208 50.101 66.6 51.205 ;
     RECT  50.208 51.205 66.648 51.253 ;
     RECT  12.912 50.101 13.512 51.301 ;
     RECT  43.824 48.515 44.28 51.347 ;
     RECT  33.648 49.571 33.672 51.443 ;
     RECT  10.224 50.147 10.248 51.541 ;
     RECT  16.656 50.101 16.68 51.635 ;
     RECT  39.84 51.203 40.824 51.827 ;
     RECT  39.84 51.827 40.512 51.923 ;
     RECT  42.336 48.947 42.648 51.971 ;
     RECT  6.384 50.965 6.456 52.021 ;
     RECT  30.816 51.061 30.84 52.021 ;
     RECT  45.264 50.917 47.352 52.021 ;
     RECT  48.576 50.723 48.6 52.021 ;
     RECT  30.816 52.021 31.08 52.067 ;
     RECT  18.096 50.101 19.608 52.117 ;
     RECT  4.896 51.253 4.92 52.211 ;
     RECT  6.288 52.021 6.456 52.211 ;
     RECT  26.832 51.061 26.856 52.211 ;
     RECT  45.264 52.021 48.6 52.211 ;
     RECT  7.8 51.205 8.52 52.451 ;
     RECT  14.496 51.589 14.52 52.499 ;
     RECT  45.264 52.211 47.304 52.499 ;
     RECT  12.384 51.301 13.512 52.501 ;
     RECT  48.48 52.211 48.504 52.547 ;
     RECT  45.264 52.499 46.872 52.643 ;
     RECT  50.208 51.253 66.84 52.645 ;
     RECT  17.232 52.117 19.608 52.979 ;
     RECT  45.312 52.643 46.872 53.027 ;
     RECT  10.224 51.541 10.968 53.173 ;
     RECT  12.048 52.501 13.944 53.173 ;
     RECT  10.224 53.173 13.944 53.219 ;
     RECT  25.392 49.619 25.416 53.221 ;
     RECT  50.208 52.645 67.272 53.411 ;
     RECT  68.928 53.221 68.952 53.507 ;
     RECT  50.736 53.411 67.272 53.605 ;
     RECT  6.288 52.211 6.312 53.653 ;
     RECT  7.8 52.451 8.112 53.653 ;
     RECT  50.736 53.605 67.512 53.797 ;
     RECT  34.8 45.059 35.112 53.893 ;
     RECT  6.288 53.653 8.112 54.085 ;
     RECT  18.096 52.979 19.608 54.085 ;
     RECT  42.528 51.971 42.648 54.133 ;
     RECT  24 50.963 24.312 54.325 ;
     RECT  25.392 53.221 26.184 54.325 ;
     RECT  42.432 54.133 42.648 54.325 ;
     RECT  68.832 53.941 68.856 54.469 ;
     RECT  68.832 54.469 69 54.515 ;
     RECT  6 54.085 8.112 54.613 ;
     RECT  31.056 52.067 31.08 54.661 ;
     RECT  50.736 53.797 67.848 54.661 ;
     RECT  31.056 54.661 31.32 54.707 ;
     RECT  48.432 53.557 48.456 54.707 ;
     RECT  27.504 52.261 27.528 54.997 ;
     RECT  34.704 53.893 35.112 55.045 ;
     RECT  31.296 54.707 31.32 55.091 ;
     RECT  44.256 54.661 44.28 55.141 ;
     RECT  45.312 53.027 45.912 55.141 ;
     RECT  6 54.613 8.232 55.237 ;
     RECT  44.256 55.141 45.912 55.331 ;
     RECT  24 54.325 26.184 55.475 ;
     RECT  42.432 54.325 42.744 55.477 ;
     RECT  42.432 55.477 42.792 55.619 ;
     RECT  17.952 54.085 19.608 55.667 ;
     RECT  34.704 55.045 36.072 55.763 ;
     RECT  40.08 51.923 40.512 55.765 ;
     RECT  24 55.475 24.312 55.813 ;
     RECT  27.312 54.997 27.528 55.813 ;
     RECT  6 55.237 9.096 55.955 ;
     RECT  11.376 53.219 13.944 55.955 ;
     RECT  22.176 55.573 22.2 56.195 ;
     RECT  4.656 55.381 4.68 56.243 ;
     RECT  12.912 55.955 13.944 56.243 ;
     RECT  29.4 50.195 29.712 56.245 ;
     RECT  27.312 55.813 28.248 56.389 ;
     RECT  29.232 56.245 29.712 56.389 ;
     RECT  15.264 54.613 15.288 56.483 ;
     RECT  27.312 56.389 29.712 56.483 ;
     RECT  11.376 55.955 11.544 56.675 ;
     RECT  10.224 53.219 10.248 56.725 ;
     RECT  11.376 56.675 11.4 56.725 ;
     RECT  37.536 56.341 37.56 56.725 ;
     RECT  10.224 56.725 11.4 56.771 ;
     RECT  27.504 56.483 29.712 56.915 ;
     RECT  47.424 54.517 47.448 56.917 ;
     RECT  50.736 54.661 67.896 57.013 ;
     RECT  23.328 55.813 24.312 57.059 ;
     RECT  40.08 55.765 40.632 57.059 ;
     RECT  40.2 57.059 40.632 57.107 ;
     RECT  50.736 57.013 67.992 57.109 ;
     RECT  68.976 54.515 69 57.109 ;
     RECT  29.232 56.915 29.712 57.349 ;
     RECT  29.232 57.349 30.696 57.395 ;
     RECT  44.784 55.331 45.912 57.397 ;
     RECT  50.736 57.109 69 57.445 ;
     RECT  37.488 56.725 37.56 57.539 ;
     RECT  6 55.955 8.112 57.541 ;
     RECT  24 57.059 24.312 57.541 ;
     RECT  25.392 55.475 26.184 57.541 ;
     RECT  27.504 56.915 28.248 57.635 ;
     RECT  44.784 57.397 46.152 57.685 ;
     RECT  47.328 56.917 47.448 57.685 ;
     RECT  32.736 55.045 32.76 57.971 ;
     RECT  44.784 57.685 47.448 58.021 ;
     RECT  40.2 57.107 40.512 58.117 ;
     RECT  28.224 57.635 28.248 58.163 ;
     RECT  29.4 57.395 30.696 58.163 ;
     RECT  10.224 56.771 10.968 58.403 ;
     RECT  38.688 58.261 38.712 58.451 ;
     RECT  21.504 57.013 21.528 58.549 ;
     RECT  21.504 58.549 21.624 58.597 ;
     RECT  21.504 58.597 22.104 58.643 ;
     RECT  24 57.541 26.184 58.643 ;
     RECT  17.328 56.437 17.352 58.691 ;
     RECT  24 58.643 26.088 58.691 ;
     RECT  37.488 57.539 37.512 58.693 ;
     RECT  21.6 58.643 22.104 58.789 ;
     RECT  37.392 58.693 37.512 58.835 ;
     RECT  10.224 58.403 10.632 58.931 ;
     RECT  12.048 58.645 12.072 58.931 ;
     RECT  49.008 58.885 49.032 59.027 ;
     RECT  42.432 55.619 42.744 59.029 ;
     RECT  18.6 55.667 19.608 59.173 ;
     RECT  24 58.691 25.992 59.219 ;
     RECT  27.84 58.645 27.864 59.221 ;
     RECT  27.36 59.221 27.864 59.267 ;
     RECT  21.6 58.789 22.2 59.315 ;
     RECT  44.784 58.021 47.496 59.461 ;
     RECT  41.952 59.029 42.744 59.795 ;
     RECT  50.688 57.445 69 59.797 ;
     RECT  13.2 56.243 13.944 59.843 ;
     RECT  21.6 59.315 22.104 59.891 ;
     RECT  37.536 59.173 37.56 59.893 ;
     RECT  27.36 59.267 27.384 59.939 ;
     RECT  40.2 58.117 40.632 60.083 ;
     RECT  37.056 59.893 37.56 60.325 ;
     RECT  37.056 60.325 37.608 60.709 ;
     RECT  50.256 59.797 69 60.901 ;
     RECT  22.08 59.891 22.104 60.949 ;
     RECT  21.84 60.949 22.104 60.995 ;
     RECT  18.096 59.173 19.608 61.043 ;
     RECT  36.432 60.709 37.608 61.043 ;
     RECT  34.704 55.763 35.112 61.139 ;
     RECT  44.784 59.461 47.592 61.139 ;
     RECT  29.4 58.163 29.712 61.189 ;
     RECT  18.6 61.043 19.608 61.523 ;
     RECT  24 59.219 24.312 61.525 ;
     RECT  25.536 59.219 25.992 61.525 ;
     RECT  5.76 57.541 8.112 61.619 ;
     RECT  36.432 61.043 37.08 62.003 ;
     RECT  5.76 61.619 6.312 62.195 ;
     RECT  21.84 60.995 21.864 62.195 ;
     RECT  29.4 61.189 29.88 62.195 ;
     RECT  45.6 61.139 47.592 62.195 ;
     RECT  18.6 61.523 19.464 62.243 ;
     RECT  32.496 60.949 32.52 62.243 ;
     RECT  6.288 62.195 6.312 62.483 ;
     RECT  23.328 61.525 25.992 62.483 ;
     RECT  23.328 62.483 24.312 62.579 ;
     RECT  13.2 59.843 13.512 62.629 ;
     RECT  50.112 60.901 69 62.629 ;
     RECT  47.568 62.195 47.592 63.205 ;
     RECT  13.2 62.629 13.704 63.299 ;
     RECT  25.872 62.483 25.992 63.491 ;
     RECT  18.6 62.243 19.032 63.733 ;
     RECT  25.92 63.491 25.992 63.875 ;
     RECT  36.432 62.003 36.456 63.875 ;
     RECT  47.568 63.205 47.88 63.875 ;
     RECT  13.2 63.299 13.512 64.069 ;
     RECT  10.608 58.931 10.632 64.115 ;
     RECT  42.432 59.795 42.744 64.355 ;
     RECT  27.888 62.677 27.912 64.357 ;
     RECT  27.456 64.357 27.912 64.403 ;
     RECT  18.6 63.733 19.368 64.595 ;
     RECT  25.92 63.875 25.944 64.643 ;
     RECT  47.568 63.875 47.592 64.739 ;
     RECT  13.008 64.069 13.512 64.835 ;
     RECT  42.432 64.355 42.456 65.027 ;
     RECT  13.2 64.835 13.512 65.509 ;
     RECT  24 62.579 24.312 65.509 ;
     RECT  31.44 62.053 31.464 65.509 ;
     RECT  31.152 65.509 31.464 65.555 ;
     RECT  49.968 62.629 69 66.133 ;
     RECT  27.456 64.403 27.48 66.179 ;
     RECT  31.152 65.555 31.176 66.227 ;
     RECT  13.2 65.509 13.608 66.275 ;
     RECT  23.328 65.509 24.312 66.275 ;
     RECT  49.104 66.133 69 66.709 ;
     RECT  15.984 64.981 16.008 66.755 ;
     RECT  48.432 66.709 69 66.803 ;
     RECT  2.4 47.267 2.712 66.969 ;
     RECT  7.8 61.619 8.112 66.969 ;
     RECT  13.2 66.275 13.512 66.969 ;
     RECT  18.6 64.595 18.912 66.969 ;
     RECT  24 66.275 24.312 66.969 ;
     RECT  29.4 62.195 29.712 66.969 ;
     RECT  34.8 61.139 35.112 66.969 ;
     RECT  40.2 60.083 40.512 66.969 ;
     RECT  45.6 62.195 45.912 66.969 ;
     RECT  2.4 66.969 2.52 66.983 ;
     RECT  7.8 66.969 7.92 66.983 ;
     RECT  13.2 66.969 13.32 66.983 ;
     RECT  18.6 66.969 18.72 66.983 ;
     RECT  24 66.969 24.12 66.983 ;
     RECT  29.4 66.969 29.52 66.983 ;
     RECT  34.8 66.969 34.92 66.983 ;
     RECT  40.2 66.969 40.32 66.983 ;
     RECT  45.6 66.969 45.72 66.983 ;
     RECT  48.432 66.803 68.904 67.237 ;
     RECT  48.336 67.237 68.904 67.283 ;
     RECT  48.336 67.283 68.328 67.813 ;
     RECT  48.24 67.813 68.328 68.389 ;
     RECT  48.144 68.389 68.328 69.072 ;
  END
END ot_hgi_dma_back_static_vp4_controller
END LIBRARY
